VERSION 5.8 ;
BUSBITCHARS "[]" ;
DIVIDERCHAR "/" ;
UNITS
    DATABASE MICRONS 1000 ;
END UNITS

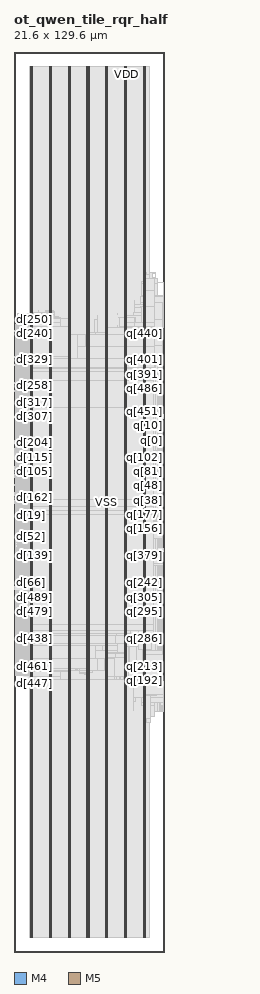
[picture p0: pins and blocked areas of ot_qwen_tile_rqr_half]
MACRO ot_qwen_tile_rqr_half
  FOREIGN ot_qwen_tile_rqr_half 0 0 ;
  CLASS BLOCK ;
  SIZE 21.6 BY 129.6 ;
  PIN clk
    DIRECTION INPUT ;
    USE SIGNAL ;
    PORT
      LAYER M4 ;
        RECT  0 62.064 0.084 62.088 ;
    END
  END clk
  PIN d[0]
    DIRECTION INPUT ;
    USE SIGNAL ;
    PORT
      LAYER M4 ;
        RECT  0 62.16 0.084 62.184 ;
    END
  END d[0]
  PIN d[100]
    DIRECTION INPUT ;
    USE SIGNAL ;
    PORT
      LAYER M4 ;
        RECT  0 68.688 0.084 68.712 ;
    END
  END d[100]
  PIN d[101]
    DIRECTION INPUT ;
    USE SIGNAL ;
    PORT
      LAYER M4 ;
        RECT  0 68.784 0.084 68.808 ;
    END
  END d[101]
  PIN d[102]
    DIRECTION INPUT ;
    USE SIGNAL ;
    PORT
      LAYER M4 ;
        RECT  0 68.88 0.084 68.904 ;
    END
  END d[102]
  PIN d[103]
    DIRECTION INPUT ;
    USE SIGNAL ;
    PORT
      LAYER M4 ;
        RECT  0 68.976 0.084 69 ;
    END
  END d[103]
  PIN d[104]
    DIRECTION INPUT ;
    USE SIGNAL ;
    PORT
      LAYER M4 ;
        RECT  0 69.072 0.084 69.096 ;
    END
  END d[104]
  PIN d[105]
    DIRECTION INPUT ;
    USE SIGNAL ;
    PORT
      LAYER M4 ;
        RECT  0 69.168 0.084 69.192 ;
    END
  END d[105]
  PIN d[106]
    DIRECTION INPUT ;
    USE SIGNAL ;
    PORT
      LAYER M4 ;
        RECT  0 69.264 0.084 69.288 ;
    END
  END d[106]
  PIN d[107]
    DIRECTION INPUT ;
    USE SIGNAL ;
    PORT
      LAYER M4 ;
        RECT  0 69.36 0.084 69.384 ;
    END
  END d[107]
  PIN d[108]
    DIRECTION INPUT ;
    USE SIGNAL ;
    PORT
      LAYER M4 ;
        RECT  0 69.456 0.084 69.48 ;
    END
  END d[108]
  PIN d[109]
    DIRECTION INPUT ;
    USE SIGNAL ;
    PORT
      LAYER M4 ;
        RECT  0 69.552 0.084 69.576 ;
    END
  END d[109]
  PIN d[10]
    DIRECTION INPUT ;
    USE SIGNAL ;
    PORT
      LAYER M4 ;
        RECT  0 63.12 0.084 63.144 ;
    END
  END d[10]
  PIN d[110]
    DIRECTION INPUT ;
    USE SIGNAL ;
    PORT
      LAYER M4 ;
        RECT  0 69.648 0.084 69.672 ;
    END
  END d[110]
  PIN d[111]
    DIRECTION INPUT ;
    USE SIGNAL ;
    PORT
      LAYER M4 ;
        RECT  0 69.744 0.084 69.768 ;
    END
  END d[111]
  PIN d[112]
    DIRECTION INPUT ;
    USE SIGNAL ;
    PORT
      LAYER M4 ;
        RECT  0 69.84 0.084 69.864 ;
    END
  END d[112]
  PIN d[113]
    DIRECTION INPUT ;
    USE SIGNAL ;
    PORT
      LAYER M4 ;
        RECT  0 69.936 0.084 69.96 ;
    END
  END d[113]
  PIN d[114]
    DIRECTION INPUT ;
    USE SIGNAL ;
    PORT
      LAYER M4 ;
        RECT  0 70.032 0.084 70.056 ;
    END
  END d[114]
  PIN d[115]
    DIRECTION INPUT ;
    USE SIGNAL ;
    PORT
      LAYER M4 ;
        RECT  0 70.128 0.084 70.152 ;
    END
  END d[115]
  PIN d[116]
    DIRECTION INPUT ;
    USE SIGNAL ;
    PORT
      LAYER M4 ;
        RECT  0 70.224 0.084 70.248 ;
    END
  END d[116]
  PIN d[117]
    DIRECTION INPUT ;
    USE SIGNAL ;
    PORT
      LAYER M4 ;
        RECT  0 70.32 0.084 70.344 ;
    END
  END d[117]
  PIN d[118]
    DIRECTION INPUT ;
    USE SIGNAL ;
    PORT
      LAYER M4 ;
        RECT  0 70.416 0.084 70.44 ;
    END
  END d[118]
  PIN d[119]
    DIRECTION INPUT ;
    USE SIGNAL ;
    PORT
      LAYER M4 ;
        RECT  0 70.512 0.084 70.536 ;
    END
  END d[119]
  PIN d[11]
    DIRECTION INPUT ;
    USE SIGNAL ;
    PORT
      LAYER M4 ;
        RECT  0 63.216 0.084 63.24 ;
    END
  END d[11]
  PIN d[120]
    DIRECTION INPUT ;
    USE SIGNAL ;
    PORT
      LAYER M4 ;
        RECT  0 70.608 0.084 70.632 ;
    END
  END d[120]
  PIN d[121]
    DIRECTION INPUT ;
    USE SIGNAL ;
    PORT
      LAYER M4 ;
        RECT  0 70.704 0.084 70.728 ;
    END
  END d[121]
  PIN d[122]
    DIRECTION INPUT ;
    USE SIGNAL ;
    PORT
      LAYER M4 ;
        RECT  0 70.8 0.084 70.824 ;
    END
  END d[122]
  PIN d[123]
    DIRECTION INPUT ;
    USE SIGNAL ;
    PORT
      LAYER M4 ;
        RECT  0 70.896 0.084 70.92 ;
    END
  END d[123]
  PIN d[124]
    DIRECTION INPUT ;
    USE SIGNAL ;
    PORT
      LAYER M4 ;
        RECT  0 70.992 0.084 71.016 ;
    END
  END d[124]
  PIN d[125]
    DIRECTION INPUT ;
    USE SIGNAL ;
    PORT
      LAYER M4 ;
        RECT  0 71.088 0.084 71.112 ;
    END
  END d[125]
  PIN d[126]
    DIRECTION INPUT ;
    USE SIGNAL ;
    PORT
      LAYER M4 ;
        RECT  0 71.184 0.084 71.208 ;
    END
  END d[126]
  PIN d[127]
    DIRECTION INPUT ;
    USE SIGNAL ;
    PORT
      LAYER M4 ;
        RECT  0 55.92 0.084 55.944 ;
    END
  END d[127]
  PIN d[128]
    DIRECTION INPUT ;
    USE SIGNAL ;
    PORT
      LAYER M4 ;
        RECT  0 56.016 0.084 56.04 ;
    END
  END d[128]
  PIN d[129]
    DIRECTION INPUT ;
    USE SIGNAL ;
    PORT
      LAYER M4 ;
        RECT  0 56.112 0.084 56.136 ;
    END
  END d[129]
  PIN d[12]
    DIRECTION INPUT ;
    USE SIGNAL ;
    PORT
      LAYER M4 ;
        RECT  0 63.312 0.084 63.336 ;
    END
  END d[12]
  PIN d[130]
    DIRECTION INPUT ;
    USE SIGNAL ;
    PORT
      LAYER M4 ;
        RECT  0 56.208 0.084 56.232 ;
    END
  END d[130]
  PIN d[131]
    DIRECTION INPUT ;
    USE SIGNAL ;
    PORT
      LAYER M4 ;
        RECT  0 56.304 0.084 56.328 ;
    END
  END d[131]
  PIN d[132]
    DIRECTION INPUT ;
    USE SIGNAL ;
    PORT
      LAYER M4 ;
        RECT  0 56.4 0.084 56.424 ;
    END
  END d[132]
  PIN d[133]
    DIRECTION INPUT ;
    USE SIGNAL ;
    PORT
      LAYER M4 ;
        RECT  0 56.496 0.084 56.52 ;
    END
  END d[133]
  PIN d[134]
    DIRECTION INPUT ;
    USE SIGNAL ;
    PORT
      LAYER M4 ;
        RECT  0 56.592 0.084 56.616 ;
    END
  END d[134]
  PIN d[135]
    DIRECTION INPUT ;
    USE SIGNAL ;
    PORT
      LAYER M4 ;
        RECT  0 56.688 0.084 56.712 ;
    END
  END d[135]
  PIN d[136]
    DIRECTION INPUT ;
    USE SIGNAL ;
    PORT
      LAYER M4 ;
        RECT  0 56.784 0.084 56.808 ;
    END
  END d[136]
  PIN d[137]
    DIRECTION INPUT ;
    USE SIGNAL ;
    PORT
      LAYER M4 ;
        RECT  0 56.88 0.084 56.904 ;
    END
  END d[137]
  PIN d[138]
    DIRECTION INPUT ;
    USE SIGNAL ;
    PORT
      LAYER M4 ;
        RECT  0 56.976 0.084 57 ;
    END
  END d[138]
  PIN d[139]
    DIRECTION INPUT ;
    USE SIGNAL ;
    PORT
      LAYER M4 ;
        RECT  0 57.072 0.084 57.096 ;
    END
  END d[139]
  PIN d[13]
    DIRECTION INPUT ;
    USE SIGNAL ;
    PORT
      LAYER M4 ;
        RECT  0 63.408 0.084 63.432 ;
    END
  END d[13]
  PIN d[140]
    DIRECTION INPUT ;
    USE SIGNAL ;
    PORT
      LAYER M4 ;
        RECT  0 57.168 0.084 57.192 ;
    END
  END d[140]
  PIN d[141]
    DIRECTION INPUT ;
    USE SIGNAL ;
    PORT
      LAYER M4 ;
        RECT  0 57.264 0.084 57.288 ;
    END
  END d[141]
  PIN d[142]
    DIRECTION INPUT ;
    USE SIGNAL ;
    PORT
      LAYER M4 ;
        RECT  0 57.36 0.084 57.384 ;
    END
  END d[142]
  PIN d[143]
    DIRECTION INPUT ;
    USE SIGNAL ;
    PORT
      LAYER M4 ;
        RECT  0 57.456 0.084 57.48 ;
    END
  END d[143]
  PIN d[144]
    DIRECTION INPUT ;
    USE SIGNAL ;
    PORT
      LAYER M4 ;
        RECT  0 57.552 0.084 57.576 ;
    END
  END d[144]
  PIN d[145]
    DIRECTION INPUT ;
    USE SIGNAL ;
    PORT
      LAYER M4 ;
        RECT  0 57.648 0.084 57.672 ;
    END
  END d[145]
  PIN d[146]
    DIRECTION INPUT ;
    USE SIGNAL ;
    PORT
      LAYER M4 ;
        RECT  0 57.744 0.084 57.768 ;
    END
  END d[146]
  PIN d[147]
    DIRECTION INPUT ;
    USE SIGNAL ;
    PORT
      LAYER M4 ;
        RECT  0 57.84 0.084 57.864 ;
    END
  END d[147]
  PIN d[148]
    DIRECTION INPUT ;
    USE SIGNAL ;
    PORT
      LAYER M4 ;
        RECT  0 57.936 0.084 57.96 ;
    END
  END d[148]
  PIN d[149]
    DIRECTION INPUT ;
    USE SIGNAL ;
    PORT
      LAYER M4 ;
        RECT  0 58.032 0.084 58.056 ;
    END
  END d[149]
  PIN d[14]
    DIRECTION INPUT ;
    USE SIGNAL ;
    PORT
      LAYER M4 ;
        RECT  0 63.504 0.084 63.528 ;
    END
  END d[14]
  PIN d[150]
    DIRECTION INPUT ;
    USE SIGNAL ;
    PORT
      LAYER M4 ;
        RECT  0 58.128 0.084 58.152 ;
    END
  END d[150]
  PIN d[151]
    DIRECTION INPUT ;
    USE SIGNAL ;
    PORT
      LAYER M4 ;
        RECT  0 58.224 0.084 58.248 ;
    END
  END d[151]
  PIN d[152]
    DIRECTION INPUT ;
    USE SIGNAL ;
    PORT
      LAYER M4 ;
        RECT  0 58.32 0.084 58.344 ;
    END
  END d[152]
  PIN d[153]
    DIRECTION INPUT ;
    USE SIGNAL ;
    PORT
      LAYER M4 ;
        RECT  0 58.416 0.084 58.44 ;
    END
  END d[153]
  PIN d[154]
    DIRECTION INPUT ;
    USE SIGNAL ;
    PORT
      LAYER M4 ;
        RECT  0 58.512 0.084 58.536 ;
    END
  END d[154]
  PIN d[155]
    DIRECTION INPUT ;
    USE SIGNAL ;
    PORT
      LAYER M4 ;
        RECT  0 58.608 0.084 58.632 ;
    END
  END d[155]
  PIN d[156]
    DIRECTION INPUT ;
    USE SIGNAL ;
    PORT
      LAYER M4 ;
        RECT  0 58.704 0.084 58.728 ;
    END
  END d[156]
  PIN d[157]
    DIRECTION INPUT ;
    USE SIGNAL ;
    PORT
      LAYER M4 ;
        RECT  0 58.8 0.084 58.824 ;
    END
  END d[157]
  PIN d[158]
    DIRECTION INPUT ;
    USE SIGNAL ;
    PORT
      LAYER M4 ;
        RECT  0 58.896 0.084 58.92 ;
    END
  END d[158]
  PIN d[159]
    DIRECTION INPUT ;
    USE SIGNAL ;
    PORT
      LAYER M4 ;
        RECT  0 65.136 0.084 65.16 ;
    END
  END d[159]
  PIN d[15]
    DIRECTION INPUT ;
    USE SIGNAL ;
    PORT
      LAYER M4 ;
        RECT  0 63.6 0.084 63.624 ;
    END
  END d[15]
  PIN d[160]
    DIRECTION INPUT ;
    USE SIGNAL ;
    PORT
      LAYER M4 ;
        RECT  0 65.232 0.084 65.256 ;
    END
  END d[160]
  PIN d[161]
    DIRECTION INPUT ;
    USE SIGNAL ;
    PORT
      LAYER M4 ;
        RECT  0 65.328 0.084 65.352 ;
    END
  END d[161]
  PIN d[162]
    DIRECTION INPUT ;
    USE SIGNAL ;
    PORT
      LAYER M4 ;
        RECT  0 65.424 0.084 65.448 ;
    END
  END d[162]
  PIN d[163]
    DIRECTION INPUT ;
    USE SIGNAL ;
    PORT
      LAYER M4 ;
        RECT  0 65.52 0.084 65.544 ;
    END
  END d[163]
  PIN d[164]
    DIRECTION INPUT ;
    USE SIGNAL ;
    PORT
      LAYER M4 ;
        RECT  0 65.616 0.084 65.64 ;
    END
  END d[164]
  PIN d[165]
    DIRECTION INPUT ;
    USE SIGNAL ;
    PORT
      LAYER M4 ;
        RECT  0 65.712 0.084 65.736 ;
    END
  END d[165]
  PIN d[166]
    DIRECTION INPUT ;
    USE SIGNAL ;
    PORT
      LAYER M4 ;
        RECT  0 65.808 0.084 65.832 ;
    END
  END d[166]
  PIN d[167]
    DIRECTION INPUT ;
    USE SIGNAL ;
    PORT
      LAYER M4 ;
        RECT  0 65.904 0.084 65.928 ;
    END
  END d[167]
  PIN d[168]
    DIRECTION INPUT ;
    USE SIGNAL ;
    PORT
      LAYER M4 ;
        RECT  0 66 0.084 66.024 ;
    END
  END d[168]
  PIN d[169]
    DIRECTION INPUT ;
    USE SIGNAL ;
    PORT
      LAYER M4 ;
        RECT  0 66.096 0.084 66.12 ;
    END
  END d[169]
  PIN d[16]
    DIRECTION INPUT ;
    USE SIGNAL ;
    PORT
      LAYER M4 ;
        RECT  0 63.696 0.084 63.72 ;
    END
  END d[16]
  PIN d[170]
    DIRECTION INPUT ;
    USE SIGNAL ;
    PORT
      LAYER M4 ;
        RECT  0 66.192 0.084 66.216 ;
    END
  END d[170]
  PIN d[171]
    DIRECTION INPUT ;
    USE SIGNAL ;
    PORT
      LAYER M4 ;
        RECT  0 66.288 0.084 66.312 ;
    END
  END d[171]
  PIN d[172]
    DIRECTION INPUT ;
    USE SIGNAL ;
    PORT
      LAYER M4 ;
        RECT  0 66.384 0.084 66.408 ;
    END
  END d[172]
  PIN d[173]
    DIRECTION INPUT ;
    USE SIGNAL ;
    PORT
      LAYER M4 ;
        RECT  0 66.48 0.084 66.504 ;
    END
  END d[173]
  PIN d[174]
    DIRECTION INPUT ;
    USE SIGNAL ;
    PORT
      LAYER M4 ;
        RECT  0 66.576 0.084 66.6 ;
    END
  END d[174]
  PIN d[175]
    DIRECTION INPUT ;
    USE SIGNAL ;
    PORT
      LAYER M4 ;
        RECT  0 66.672 0.084 66.696 ;
    END
  END d[175]
  PIN d[176]
    DIRECTION INPUT ;
    USE SIGNAL ;
    PORT
      LAYER M4 ;
        RECT  0 66.768 0.084 66.792 ;
    END
  END d[176]
  PIN d[177]
    DIRECTION INPUT ;
    USE SIGNAL ;
    PORT
      LAYER M4 ;
        RECT  0 66.864 0.084 66.888 ;
    END
  END d[177]
  PIN d[178]
    DIRECTION INPUT ;
    USE SIGNAL ;
    PORT
      LAYER M4 ;
        RECT  0 66.96 0.084 66.984 ;
    END
  END d[178]
  PIN d[179]
    DIRECTION INPUT ;
    USE SIGNAL ;
    PORT
      LAYER M4 ;
        RECT  0 67.056 0.084 67.08 ;
    END
  END d[179]
  PIN d[17]
    DIRECTION INPUT ;
    USE SIGNAL ;
    PORT
      LAYER M4 ;
        RECT  0 63.792 0.084 63.816 ;
    END
  END d[17]
  PIN d[180]
    DIRECTION INPUT ;
    USE SIGNAL ;
    PORT
      LAYER M4 ;
        RECT  0 67.152 0.084 67.176 ;
    END
  END d[180]
  PIN d[181]
    DIRECTION INPUT ;
    USE SIGNAL ;
    PORT
      LAYER M4 ;
        RECT  0 67.248 0.084 67.272 ;
    END
  END d[181]
  PIN d[182]
    DIRECTION INPUT ;
    USE SIGNAL ;
    PORT
      LAYER M4 ;
        RECT  0 67.344 0.084 67.368 ;
    END
  END d[182]
  PIN d[183]
    DIRECTION INPUT ;
    USE SIGNAL ;
    PORT
      LAYER M4 ;
        RECT  0 67.44 0.084 67.464 ;
    END
  END d[183]
  PIN d[184]
    DIRECTION INPUT ;
    USE SIGNAL ;
    PORT
      LAYER M4 ;
        RECT  0 67.536 0.084 67.56 ;
    END
  END d[184]
  PIN d[185]
    DIRECTION INPUT ;
    USE SIGNAL ;
    PORT
      LAYER M4 ;
        RECT  0 67.632 0.084 67.656 ;
    END
  END d[185]
  PIN d[186]
    DIRECTION INPUT ;
    USE SIGNAL ;
    PORT
      LAYER M4 ;
        RECT  0 67.728 0.084 67.752 ;
    END
  END d[186]
  PIN d[187]
    DIRECTION INPUT ;
    USE SIGNAL ;
    PORT
      LAYER M4 ;
        RECT  0 67.824 0.084 67.848 ;
    END
  END d[187]
  PIN d[188]
    DIRECTION INPUT ;
    USE SIGNAL ;
    PORT
      LAYER M4 ;
        RECT  0 67.92 0.084 67.944 ;
    END
  END d[188]
  PIN d[189]
    DIRECTION INPUT ;
    USE SIGNAL ;
    PORT
      LAYER M4 ;
        RECT  0 68.016 0.084 68.04 ;
    END
  END d[189]
  PIN d[18]
    DIRECTION INPUT ;
    USE SIGNAL ;
    PORT
      LAYER M4 ;
        RECT  0 63.888 0.084 63.912 ;
    END
  END d[18]
  PIN d[190]
    DIRECTION INPUT ;
    USE SIGNAL ;
    PORT
      LAYER M4 ;
        RECT  0 68.112 0.084 68.136 ;
    END
  END d[190]
  PIN d[191]
    DIRECTION INPUT ;
    USE SIGNAL ;
    PORT
      LAYER M4 ;
        RECT  0 72.048 0.084 72.072 ;
    END
  END d[191]
  PIN d[192]
    DIRECTION INPUT ;
    USE SIGNAL ;
    PORT
      LAYER M4 ;
        RECT  0 72.144 0.084 72.168 ;
    END
  END d[192]
  PIN d[193]
    DIRECTION INPUT ;
    USE SIGNAL ;
    PORT
      LAYER M4 ;
        RECT  0 72.24 0.084 72.264 ;
    END
  END d[193]
  PIN d[194]
    DIRECTION INPUT ;
    USE SIGNAL ;
    PORT
      LAYER M4 ;
        RECT  0 72.336 0.084 72.36 ;
    END
  END d[194]
  PIN d[195]
    DIRECTION INPUT ;
    USE SIGNAL ;
    PORT
      LAYER M4 ;
        RECT  0 72.432 0.084 72.456 ;
    END
  END d[195]
  PIN d[196]
    DIRECTION INPUT ;
    USE SIGNAL ;
    PORT
      LAYER M4 ;
        RECT  0 72.528 0.084 72.552 ;
    END
  END d[196]
  PIN d[197]
    DIRECTION INPUT ;
    USE SIGNAL ;
    PORT
      LAYER M4 ;
        RECT  0 72.624 0.084 72.648 ;
    END
  END d[197]
  PIN d[198]
    DIRECTION INPUT ;
    USE SIGNAL ;
    PORT
      LAYER M4 ;
        RECT  0 72.72 0.084 72.744 ;
    END
  END d[198]
  PIN d[199]
    DIRECTION INPUT ;
    USE SIGNAL ;
    PORT
      LAYER M4 ;
        RECT  0 72.816 0.084 72.84 ;
    END
  END d[199]
  PIN d[19]
    DIRECTION INPUT ;
    USE SIGNAL ;
    PORT
      LAYER M4 ;
        RECT  0 63.984 0.084 64.008 ;
    END
  END d[19]
  PIN d[1]
    DIRECTION INPUT ;
    USE SIGNAL ;
    PORT
      LAYER M4 ;
        RECT  0 62.256 0.084 62.28 ;
    END
  END d[1]
  PIN d[200]
    DIRECTION INPUT ;
    USE SIGNAL ;
    PORT
      LAYER M4 ;
        RECT  0 72.912 0.084 72.936 ;
    END
  END d[200]
  PIN d[201]
    DIRECTION INPUT ;
    USE SIGNAL ;
    PORT
      LAYER M4 ;
        RECT  0 73.008 0.084 73.032 ;
    END
  END d[201]
  PIN d[202]
    DIRECTION INPUT ;
    USE SIGNAL ;
    PORT
      LAYER M4 ;
        RECT  0 73.104 0.084 73.128 ;
    END
  END d[202]
  PIN d[203]
    DIRECTION INPUT ;
    USE SIGNAL ;
    PORT
      LAYER M4 ;
        RECT  0 73.2 0.084 73.224 ;
    END
  END d[203]
  PIN d[204]
    DIRECTION INPUT ;
    USE SIGNAL ;
    PORT
      LAYER M4 ;
        RECT  0 73.296 0.084 73.32 ;
    END
  END d[204]
  PIN d[205]
    DIRECTION INPUT ;
    USE SIGNAL ;
    PORT
      LAYER M4 ;
        RECT  0 73.392 0.084 73.416 ;
    END
  END d[205]
  PIN d[206]
    DIRECTION INPUT ;
    USE SIGNAL ;
    PORT
      LAYER M4 ;
        RECT  0 73.488 0.084 73.512 ;
    END
  END d[206]
  PIN d[207]
    DIRECTION INPUT ;
    USE SIGNAL ;
    PORT
      LAYER M4 ;
        RECT  0 73.584 0.084 73.608 ;
    END
  END d[207]
  PIN d[208]
    DIRECTION INPUT ;
    USE SIGNAL ;
    PORT
      LAYER M4 ;
        RECT  0 73.68 0.084 73.704 ;
    END
  END d[208]
  PIN d[209]
    DIRECTION INPUT ;
    USE SIGNAL ;
    PORT
      LAYER M4 ;
        RECT  0 73.776 0.084 73.8 ;
    END
  END d[209]
  PIN d[20]
    DIRECTION INPUT ;
    USE SIGNAL ;
    PORT
      LAYER M4 ;
        RECT  0 64.08 0.084 64.104 ;
    END
  END d[20]
  PIN d[210]
    DIRECTION INPUT ;
    USE SIGNAL ;
    PORT
      LAYER M4 ;
        RECT  0 73.872 0.084 73.896 ;
    END
  END d[210]
  PIN d[211]
    DIRECTION INPUT ;
    USE SIGNAL ;
    PORT
      LAYER M4 ;
        RECT  0 73.968 0.084 73.992 ;
    END
  END d[211]
  PIN d[212]
    DIRECTION INPUT ;
    USE SIGNAL ;
    PORT
      LAYER M4 ;
        RECT  0 74.064 0.084 74.088 ;
    END
  END d[212]
  PIN d[213]
    DIRECTION INPUT ;
    USE SIGNAL ;
    PORT
      LAYER M4 ;
        RECT  0 74.16 0.084 74.184 ;
    END
  END d[213]
  PIN d[214]
    DIRECTION INPUT ;
    USE SIGNAL ;
    PORT
      LAYER M4 ;
        RECT  0 74.256 0.084 74.28 ;
    END
  END d[214]
  PIN d[215]
    DIRECTION INPUT ;
    USE SIGNAL ;
    PORT
      LAYER M4 ;
        RECT  0 74.352 0.084 74.376 ;
    END
  END d[215]
  PIN d[216]
    DIRECTION INPUT ;
    USE SIGNAL ;
    PORT
      LAYER M4 ;
        RECT  0 74.448 0.084 74.472 ;
    END
  END d[216]
  PIN d[217]
    DIRECTION INPUT ;
    USE SIGNAL ;
    PORT
      LAYER M4 ;
        RECT  0 74.544 0.084 74.568 ;
    END
  END d[217]
  PIN d[218]
    DIRECTION INPUT ;
    USE SIGNAL ;
    PORT
      LAYER M4 ;
        RECT  0 74.64 0.084 74.664 ;
    END
  END d[218]
  PIN d[219]
    DIRECTION INPUT ;
    USE SIGNAL ;
    PORT
      LAYER M4 ;
        RECT  0 74.736 0.084 74.76 ;
    END
  END d[219]
  PIN d[21]
    DIRECTION INPUT ;
    USE SIGNAL ;
    PORT
      LAYER M4 ;
        RECT  0 64.176 0.084 64.2 ;
    END
  END d[21]
  PIN d[220]
    DIRECTION INPUT ;
    USE SIGNAL ;
    PORT
      LAYER M4 ;
        RECT  0 74.832 0.084 74.856 ;
    END
  END d[220]
  PIN d[221]
    DIRECTION INPUT ;
    USE SIGNAL ;
    PORT
      LAYER M4 ;
        RECT  0 74.928 0.084 74.952 ;
    END
  END d[221]
  PIN d[222]
    DIRECTION INPUT ;
    USE SIGNAL ;
    PORT
      LAYER M4 ;
        RECT  0 75.024 0.084 75.048 ;
    END
  END d[222]
  PIN d[223]
    DIRECTION INPUT ;
    USE SIGNAL ;
    PORT
      LAYER M4 ;
        RECT  0 87.408 0.084 87.432 ;
    END
  END d[223]
  PIN d[224]
    DIRECTION INPUT ;
    USE SIGNAL ;
    PORT
      LAYER M4 ;
        RECT  0 87.504 0.084 87.528 ;
    END
  END d[224]
  PIN d[225]
    DIRECTION INPUT ;
    USE SIGNAL ;
    PORT
      LAYER M4 ;
        RECT  0 87.6 0.084 87.624 ;
    END
  END d[225]
  PIN d[226]
    DIRECTION INPUT ;
    USE SIGNAL ;
    PORT
      LAYER M4 ;
        RECT  0 87.696 0.084 87.72 ;
    END
  END d[226]
  PIN d[227]
    DIRECTION INPUT ;
    USE SIGNAL ;
    PORT
      LAYER M4 ;
        RECT  0 87.792 0.084 87.816 ;
    END
  END d[227]
  PIN d[228]
    DIRECTION INPUT ;
    USE SIGNAL ;
    PORT
      LAYER M4 ;
        RECT  0 87.888 0.084 87.912 ;
    END
  END d[228]
  PIN d[229]
    DIRECTION INPUT ;
    USE SIGNAL ;
    PORT
      LAYER M4 ;
        RECT  0 87.984 0.084 88.008 ;
    END
  END d[229]
  PIN d[22]
    DIRECTION INPUT ;
    USE SIGNAL ;
    PORT
      LAYER M4 ;
        RECT  0 64.272 0.084 64.296 ;
    END
  END d[22]
  PIN d[230]
    DIRECTION INPUT ;
    USE SIGNAL ;
    PORT
      LAYER M4 ;
        RECT  0 88.08 0.084 88.104 ;
    END
  END d[230]
  PIN d[231]
    DIRECTION INPUT ;
    USE SIGNAL ;
    PORT
      LAYER M4 ;
        RECT  0 88.176 0.084 88.2 ;
    END
  END d[231]
  PIN d[232]
    DIRECTION INPUT ;
    USE SIGNAL ;
    PORT
      LAYER M4 ;
        RECT  0 88.272 0.084 88.296 ;
    END
  END d[232]
  PIN d[233]
    DIRECTION INPUT ;
    USE SIGNAL ;
    PORT
      LAYER M4 ;
        RECT  0 88.368 0.084 88.392 ;
    END
  END d[233]
  PIN d[234]
    DIRECTION INPUT ;
    USE SIGNAL ;
    PORT
      LAYER M4 ;
        RECT  0 88.464 0.084 88.488 ;
    END
  END d[234]
  PIN d[235]
    DIRECTION INPUT ;
    USE SIGNAL ;
    PORT
      LAYER M4 ;
        RECT  0 88.56 0.084 88.584 ;
    END
  END d[235]
  PIN d[236]
    DIRECTION INPUT ;
    USE SIGNAL ;
    PORT
      LAYER M4 ;
        RECT  0 88.656 0.084 88.68 ;
    END
  END d[236]
  PIN d[237]
    DIRECTION INPUT ;
    USE SIGNAL ;
    PORT
      LAYER M4 ;
        RECT  0 88.752 0.084 88.776 ;
    END
  END d[237]
  PIN d[238]
    DIRECTION INPUT ;
    USE SIGNAL ;
    PORT
      LAYER M4 ;
        RECT  0 88.848 0.084 88.872 ;
    END
  END d[238]
  PIN d[239]
    DIRECTION INPUT ;
    USE SIGNAL ;
    PORT
      LAYER M4 ;
        RECT  0 88.944 0.084 88.968 ;
    END
  END d[239]
  PIN d[23]
    DIRECTION INPUT ;
    USE SIGNAL ;
    PORT
      LAYER M4 ;
        RECT  0 64.368 0.084 64.392 ;
    END
  END d[23]
  PIN d[240]
    DIRECTION INPUT ;
    USE SIGNAL ;
    PORT
      LAYER M4 ;
        RECT  0 89.04 0.084 89.064 ;
    END
  END d[240]
  PIN d[241]
    DIRECTION INPUT ;
    USE SIGNAL ;
    PORT
      LAYER M4 ;
        RECT  0 89.136 0.084 89.16 ;
    END
  END d[241]
  PIN d[242]
    DIRECTION INPUT ;
    USE SIGNAL ;
    PORT
      LAYER M4 ;
        RECT  0 89.232 0.084 89.256 ;
    END
  END d[242]
  PIN d[243]
    DIRECTION INPUT ;
    USE SIGNAL ;
    PORT
      LAYER M4 ;
        RECT  0 89.328 0.084 89.352 ;
    END
  END d[243]
  PIN d[244]
    DIRECTION INPUT ;
    USE SIGNAL ;
    PORT
      LAYER M4 ;
        RECT  0 89.424 0.084 89.448 ;
    END
  END d[244]
  PIN d[245]
    DIRECTION INPUT ;
    USE SIGNAL ;
    PORT
      LAYER M4 ;
        RECT  0 89.52 0.084 89.544 ;
    END
  END d[245]
  PIN d[246]
    DIRECTION INPUT ;
    USE SIGNAL ;
    PORT
      LAYER M4 ;
        RECT  0 89.616 0.084 89.64 ;
    END
  END d[246]
  PIN d[247]
    DIRECTION INPUT ;
    USE SIGNAL ;
    PORT
      LAYER M4 ;
        RECT  0 89.712 0.084 89.736 ;
    END
  END d[247]
  PIN d[248]
    DIRECTION INPUT ;
    USE SIGNAL ;
    PORT
      LAYER M4 ;
        RECT  0 89.808 0.084 89.832 ;
    END
  END d[248]
  PIN d[249]
    DIRECTION INPUT ;
    USE SIGNAL ;
    PORT
      LAYER M4 ;
        RECT  0 89.904 0.084 89.928 ;
    END
  END d[249]
  PIN d[24]
    DIRECTION INPUT ;
    USE SIGNAL ;
    PORT
      LAYER M4 ;
        RECT  0 64.464 0.084 64.488 ;
    END
  END d[24]
  PIN d[250]
    DIRECTION INPUT ;
    USE SIGNAL ;
    PORT
      LAYER M4 ;
        RECT  0 90 0.084 90.024 ;
    END
  END d[250]
  PIN d[251]
    DIRECTION INPUT ;
    USE SIGNAL ;
    PORT
      LAYER M4 ;
        RECT  0 90.096 0.084 90.12 ;
    END
  END d[251]
  PIN d[252]
    DIRECTION INPUT ;
    USE SIGNAL ;
    PORT
      LAYER M4 ;
        RECT  0 90.192 0.084 90.216 ;
    END
  END d[252]
  PIN d[253]
    DIRECTION INPUT ;
    USE SIGNAL ;
    PORT
      LAYER M4 ;
        RECT  0 90.288 0.084 90.312 ;
    END
  END d[253]
  PIN d[254]
    DIRECTION INPUT ;
    USE SIGNAL ;
    PORT
      LAYER M4 ;
        RECT  0 90.384 0.084 90.408 ;
    END
  END d[254]
  PIN d[255]
    DIRECTION INPUT ;
    USE SIGNAL ;
    PORT
      LAYER M4 ;
        RECT  0 81.264 0.084 81.288 ;
    END
  END d[255]
  PIN d[256]
    DIRECTION INPUT ;
    USE SIGNAL ;
    PORT
      LAYER M4 ;
        RECT  0 81.36 0.084 81.384 ;
    END
  END d[256]
  PIN d[257]
    DIRECTION INPUT ;
    USE SIGNAL ;
    PORT
      LAYER M4 ;
        RECT  0 81.456 0.084 81.48 ;
    END
  END d[257]
  PIN d[258]
    DIRECTION INPUT ;
    USE SIGNAL ;
    PORT
      LAYER M4 ;
        RECT  0 81.552 0.084 81.576 ;
    END
  END d[258]
  PIN d[259]
    DIRECTION INPUT ;
    USE SIGNAL ;
    PORT
      LAYER M4 ;
        RECT  0 81.648 0.084 81.672 ;
    END
  END d[259]
  PIN d[25]
    DIRECTION INPUT ;
    USE SIGNAL ;
    PORT
      LAYER M4 ;
        RECT  0 64.56 0.084 64.584 ;
    END
  END d[25]
  PIN d[260]
    DIRECTION INPUT ;
    USE SIGNAL ;
    PORT
      LAYER M4 ;
        RECT  0 81.744 0.084 81.768 ;
    END
  END d[260]
  PIN d[261]
    DIRECTION INPUT ;
    USE SIGNAL ;
    PORT
      LAYER M4 ;
        RECT  0 81.84 0.084 81.864 ;
    END
  END d[261]
  PIN d[262]
    DIRECTION INPUT ;
    USE SIGNAL ;
    PORT
      LAYER M4 ;
        RECT  0 81.936 0.084 81.96 ;
    END
  END d[262]
  PIN d[263]
    DIRECTION INPUT ;
    USE SIGNAL ;
    PORT
      LAYER M4 ;
        RECT  0 82.032 0.084 82.056 ;
    END
  END d[263]
  PIN d[264]
    DIRECTION INPUT ;
    USE SIGNAL ;
    PORT
      LAYER M4 ;
        RECT  0 82.128 0.084 82.152 ;
    END
  END d[264]
  PIN d[265]
    DIRECTION INPUT ;
    USE SIGNAL ;
    PORT
      LAYER M4 ;
        RECT  0 82.224 0.084 82.248 ;
    END
  END d[265]
  PIN d[266]
    DIRECTION INPUT ;
    USE SIGNAL ;
    PORT
      LAYER M4 ;
        RECT  0 82.32 0.084 82.344 ;
    END
  END d[266]
  PIN d[267]
    DIRECTION INPUT ;
    USE SIGNAL ;
    PORT
      LAYER M4 ;
        RECT  0 82.416 0.084 82.44 ;
    END
  END d[267]
  PIN d[268]
    DIRECTION INPUT ;
    USE SIGNAL ;
    PORT
      LAYER M4 ;
        RECT  0 82.512 0.084 82.536 ;
    END
  END d[268]
  PIN d[269]
    DIRECTION INPUT ;
    USE SIGNAL ;
    PORT
      LAYER M4 ;
        RECT  0 82.608 0.084 82.632 ;
    END
  END d[269]
  PIN d[26]
    DIRECTION INPUT ;
    USE SIGNAL ;
    PORT
      LAYER M4 ;
        RECT  0 64.656 0.084 64.68 ;
    END
  END d[26]
  PIN d[270]
    DIRECTION INPUT ;
    USE SIGNAL ;
    PORT
      LAYER M4 ;
        RECT  0 82.704 0.084 82.728 ;
    END
  END d[270]
  PIN d[271]
    DIRECTION INPUT ;
    USE SIGNAL ;
    PORT
      LAYER M4 ;
        RECT  0 82.8 0.084 82.824 ;
    END
  END d[271]
  PIN d[272]
    DIRECTION INPUT ;
    USE SIGNAL ;
    PORT
      LAYER M4 ;
        RECT  0 82.896 0.084 82.92 ;
    END
  END d[272]
  PIN d[273]
    DIRECTION INPUT ;
    USE SIGNAL ;
    PORT
      LAYER M4 ;
        RECT  0 82.992 0.084 83.016 ;
    END
  END d[273]
  PIN d[274]
    DIRECTION INPUT ;
    USE SIGNAL ;
    PORT
      LAYER M4 ;
        RECT  0 83.088 0.084 83.112 ;
    END
  END d[274]
  PIN d[275]
    DIRECTION INPUT ;
    USE SIGNAL ;
    PORT
      LAYER M4 ;
        RECT  0 83.184 0.084 83.208 ;
    END
  END d[275]
  PIN d[276]
    DIRECTION INPUT ;
    USE SIGNAL ;
    PORT
      LAYER M4 ;
        RECT  0 83.28 0.084 83.304 ;
    END
  END d[276]
  PIN d[277]
    DIRECTION INPUT ;
    USE SIGNAL ;
    PORT
      LAYER M4 ;
        RECT  0 83.376 0.084 83.4 ;
    END
  END d[277]
  PIN d[278]
    DIRECTION INPUT ;
    USE SIGNAL ;
    PORT
      LAYER M4 ;
        RECT  0 83.472 0.084 83.496 ;
    END
  END d[278]
  PIN d[279]
    DIRECTION INPUT ;
    USE SIGNAL ;
    PORT
      LAYER M4 ;
        RECT  0 83.568 0.084 83.592 ;
    END
  END d[279]
  PIN d[27]
    DIRECTION INPUT ;
    USE SIGNAL ;
    PORT
      LAYER M4 ;
        RECT  0 64.752 0.084 64.776 ;
    END
  END d[27]
  PIN d[280]
    DIRECTION INPUT ;
    USE SIGNAL ;
    PORT
      LAYER M4 ;
        RECT  0 83.664 0.084 83.688 ;
    END
  END d[280]
  PIN d[281]
    DIRECTION INPUT ;
    USE SIGNAL ;
    PORT
      LAYER M4 ;
        RECT  0 83.76 0.084 83.784 ;
    END
  END d[281]
  PIN d[282]
    DIRECTION INPUT ;
    USE SIGNAL ;
    PORT
      LAYER M4 ;
        RECT  0 83.856 0.084 83.88 ;
    END
  END d[282]
  PIN d[283]
    DIRECTION INPUT ;
    USE SIGNAL ;
    PORT
      LAYER M4 ;
        RECT  0 83.952 0.084 83.976 ;
    END
  END d[283]
  PIN d[284]
    DIRECTION INPUT ;
    USE SIGNAL ;
    PORT
      LAYER M4 ;
        RECT  0 84.048 0.084 84.072 ;
    END
  END d[284]
  PIN d[285]
    DIRECTION INPUT ;
    USE SIGNAL ;
    PORT
      LAYER M4 ;
        RECT  0 84.144 0.084 84.168 ;
    END
  END d[285]
  PIN d[286]
    DIRECTION INPUT ;
    USE SIGNAL ;
    PORT
      LAYER M4 ;
        RECT  0 84.24 0.084 84.264 ;
    END
  END d[286]
  PIN d[287]
    DIRECTION INPUT ;
    USE SIGNAL ;
    PORT
      LAYER M4 ;
        RECT  0 75.12 0.084 75.144 ;
    END
  END d[287]
  PIN d[288]
    DIRECTION INPUT ;
    USE SIGNAL ;
    PORT
      LAYER M4 ;
        RECT  0 75.216 0.084 75.24 ;
    END
  END d[288]
  PIN d[289]
    DIRECTION INPUT ;
    USE SIGNAL ;
    PORT
      LAYER M4 ;
        RECT  0 75.312 0.084 75.336 ;
    END
  END d[289]
  PIN d[28]
    DIRECTION INPUT ;
    USE SIGNAL ;
    PORT
      LAYER M4 ;
        RECT  0 64.848 0.084 64.872 ;
    END
  END d[28]
  PIN d[290]
    DIRECTION INPUT ;
    USE SIGNAL ;
    PORT
      LAYER M4 ;
        RECT  0 75.408 0.084 75.432 ;
    END
  END d[290]
  PIN d[291]
    DIRECTION INPUT ;
    USE SIGNAL ;
    PORT
      LAYER M4 ;
        RECT  0 75.504 0.084 75.528 ;
    END
  END d[291]
  PIN d[292]
    DIRECTION INPUT ;
    USE SIGNAL ;
    PORT
      LAYER M4 ;
        RECT  0 75.6 0.084 75.624 ;
    END
  END d[292]
  PIN d[293]
    DIRECTION INPUT ;
    USE SIGNAL ;
    PORT
      LAYER M4 ;
        RECT  0 75.696 0.084 75.72 ;
    END
  END d[293]
  PIN d[294]
    DIRECTION INPUT ;
    USE SIGNAL ;
    PORT
      LAYER M4 ;
        RECT  0 75.792 0.084 75.816 ;
    END
  END d[294]
  PIN d[295]
    DIRECTION INPUT ;
    USE SIGNAL ;
    PORT
      LAYER M4 ;
        RECT  0 75.888 0.084 75.912 ;
    END
  END d[295]
  PIN d[296]
    DIRECTION INPUT ;
    USE SIGNAL ;
    PORT
      LAYER M4 ;
        RECT  0 75.984 0.084 76.008 ;
    END
  END d[296]
  PIN d[297]
    DIRECTION INPUT ;
    USE SIGNAL ;
    PORT
      LAYER M4 ;
        RECT  0 76.08 0.084 76.104 ;
    END
  END d[297]
  PIN d[298]
    DIRECTION INPUT ;
    USE SIGNAL ;
    PORT
      LAYER M4 ;
        RECT  0 76.176 0.084 76.2 ;
    END
  END d[298]
  PIN d[299]
    DIRECTION INPUT ;
    USE SIGNAL ;
    PORT
      LAYER M4 ;
        RECT  0 76.272 0.084 76.296 ;
    END
  END d[299]
  PIN d[29]
    DIRECTION INPUT ;
    USE SIGNAL ;
    PORT
      LAYER M4 ;
        RECT  0 64.944 0.084 64.968 ;
    END
  END d[29]
  PIN d[2]
    DIRECTION INPUT ;
    USE SIGNAL ;
    PORT
      LAYER M4 ;
        RECT  0 62.352 0.084 62.376 ;
    END
  END d[2]
  PIN d[300]
    DIRECTION INPUT ;
    USE SIGNAL ;
    PORT
      LAYER M4 ;
        RECT  0 76.368 0.084 76.392 ;
    END
  END d[300]
  PIN d[301]
    DIRECTION INPUT ;
    USE SIGNAL ;
    PORT
      LAYER M4 ;
        RECT  0 76.464 0.084 76.488 ;
    END
  END d[301]
  PIN d[302]
    DIRECTION INPUT ;
    USE SIGNAL ;
    PORT
      LAYER M4 ;
        RECT  0 76.56 0.084 76.584 ;
    END
  END d[302]
  PIN d[303]
    DIRECTION INPUT ;
    USE SIGNAL ;
    PORT
      LAYER M4 ;
        RECT  0 76.656 0.084 76.68 ;
    END
  END d[303]
  PIN d[304]
    DIRECTION INPUT ;
    USE SIGNAL ;
    PORT
      LAYER M4 ;
        RECT  0 76.752 0.084 76.776 ;
    END
  END d[304]
  PIN d[305]
    DIRECTION INPUT ;
    USE SIGNAL ;
    PORT
      LAYER M4 ;
        RECT  0 76.848 0.084 76.872 ;
    END
  END d[305]
  PIN d[306]
    DIRECTION INPUT ;
    USE SIGNAL ;
    PORT
      LAYER M4 ;
        RECT  0 76.944 0.084 76.968 ;
    END
  END d[306]
  PIN d[307]
    DIRECTION INPUT ;
    USE SIGNAL ;
    PORT
      LAYER M4 ;
        RECT  0 77.04 0.084 77.064 ;
    END
  END d[307]
  PIN d[308]
    DIRECTION INPUT ;
    USE SIGNAL ;
    PORT
      LAYER M4 ;
        RECT  0 77.136 0.084 77.16 ;
    END
  END d[308]
  PIN d[309]
    DIRECTION INPUT ;
    USE SIGNAL ;
    PORT
      LAYER M4 ;
        RECT  0 77.232 0.084 77.256 ;
    END
  END d[309]
  PIN d[30]
    DIRECTION INPUT ;
    USE SIGNAL ;
    PORT
      LAYER M4 ;
        RECT  0 65.04 0.084 65.064 ;
    END
  END d[30]
  PIN d[310]
    DIRECTION INPUT ;
    USE SIGNAL ;
    PORT
      LAYER M4 ;
        RECT  0 77.328 0.084 77.352 ;
    END
  END d[310]
  PIN d[311]
    DIRECTION INPUT ;
    USE SIGNAL ;
    PORT
      LAYER M4 ;
        RECT  0 77.424 0.084 77.448 ;
    END
  END d[311]
  PIN d[312]
    DIRECTION INPUT ;
    USE SIGNAL ;
    PORT
      LAYER M4 ;
        RECT  0 77.52 0.084 77.544 ;
    END
  END d[312]
  PIN d[313]
    DIRECTION INPUT ;
    USE SIGNAL ;
    PORT
      LAYER M4 ;
        RECT  0 77.616 0.084 77.64 ;
    END
  END d[313]
  PIN d[314]
    DIRECTION INPUT ;
    USE SIGNAL ;
    PORT
      LAYER M4 ;
        RECT  0 77.712 0.084 77.736 ;
    END
  END d[314]
  PIN d[315]
    DIRECTION INPUT ;
    USE SIGNAL ;
    PORT
      LAYER M4 ;
        RECT  0 77.808 0.084 77.832 ;
    END
  END d[315]
  PIN d[316]
    DIRECTION INPUT ;
    USE SIGNAL ;
    PORT
      LAYER M4 ;
        RECT  0 77.904 0.084 77.928 ;
    END
  END d[316]
  PIN d[317]
    DIRECTION INPUT ;
    USE SIGNAL ;
    PORT
      LAYER M4 ;
        RECT  0 78 0.084 78.024 ;
    END
  END d[317]
  PIN d[318]
    DIRECTION INPUT ;
    USE SIGNAL ;
    PORT
      LAYER M4 ;
        RECT  0 78.096 0.084 78.12 ;
    END
  END d[318]
  PIN d[319]
    DIRECTION INPUT ;
    USE SIGNAL ;
    PORT
      LAYER M4 ;
        RECT  0 84.336 0.084 84.36 ;
    END
  END d[319]
  PIN d[31]
    DIRECTION INPUT ;
    USE SIGNAL ;
    PORT
      LAYER M4 ;
        RECT  0 58.992 0.084 59.016 ;
    END
  END d[31]
  PIN d[320]
    DIRECTION INPUT ;
    USE SIGNAL ;
    PORT
      LAYER M4 ;
        RECT  0 84.432 0.084 84.456 ;
    END
  END d[320]
  PIN d[321]
    DIRECTION INPUT ;
    USE SIGNAL ;
    PORT
      LAYER M4 ;
        RECT  0 84.528 0.084 84.552 ;
    END
  END d[321]
  PIN d[322]
    DIRECTION INPUT ;
    USE SIGNAL ;
    PORT
      LAYER M4 ;
        RECT  0 84.624 0.084 84.648 ;
    END
  END d[322]
  PIN d[323]
    DIRECTION INPUT ;
    USE SIGNAL ;
    PORT
      LAYER M4 ;
        RECT  0 84.72 0.084 84.744 ;
    END
  END d[323]
  PIN d[324]
    DIRECTION INPUT ;
    USE SIGNAL ;
    PORT
      LAYER M4 ;
        RECT  0 84.816 0.084 84.84 ;
    END
  END d[324]
  PIN d[325]
    DIRECTION INPUT ;
    USE SIGNAL ;
    PORT
      LAYER M4 ;
        RECT  0 84.912 0.084 84.936 ;
    END
  END d[325]
  PIN d[326]
    DIRECTION INPUT ;
    USE SIGNAL ;
    PORT
      LAYER M4 ;
        RECT  0 85.008 0.084 85.032 ;
    END
  END d[326]
  PIN d[327]
    DIRECTION INPUT ;
    USE SIGNAL ;
    PORT
      LAYER M4 ;
        RECT  0 85.104 0.084 85.128 ;
    END
  END d[327]
  PIN d[328]
    DIRECTION INPUT ;
    USE SIGNAL ;
    PORT
      LAYER M4 ;
        RECT  0 85.2 0.084 85.224 ;
    END
  END d[328]
  PIN d[329]
    DIRECTION INPUT ;
    USE SIGNAL ;
    PORT
      LAYER M4 ;
        RECT  0 85.296 0.084 85.32 ;
    END
  END d[329]
  PIN d[32]
    DIRECTION INPUT ;
    USE SIGNAL ;
    PORT
      LAYER M4 ;
        RECT  0 59.088 0.084 59.112 ;
    END
  END d[32]
  PIN d[330]
    DIRECTION INPUT ;
    USE SIGNAL ;
    PORT
      LAYER M4 ;
        RECT  0 85.392 0.084 85.416 ;
    END
  END d[330]
  PIN d[331]
    DIRECTION INPUT ;
    USE SIGNAL ;
    PORT
      LAYER M4 ;
        RECT  0 85.488 0.084 85.512 ;
    END
  END d[331]
  PIN d[332]
    DIRECTION INPUT ;
    USE SIGNAL ;
    PORT
      LAYER M4 ;
        RECT  0 85.584 0.084 85.608 ;
    END
  END d[332]
  PIN d[333]
    DIRECTION INPUT ;
    USE SIGNAL ;
    PORT
      LAYER M4 ;
        RECT  0 85.68 0.084 85.704 ;
    END
  END d[333]
  PIN d[334]
    DIRECTION INPUT ;
    USE SIGNAL ;
    PORT
      LAYER M4 ;
        RECT  0 85.776 0.084 85.8 ;
    END
  END d[334]
  PIN d[335]
    DIRECTION INPUT ;
    USE SIGNAL ;
    PORT
      LAYER M4 ;
        RECT  0 85.872 0.084 85.896 ;
    END
  END d[335]
  PIN d[336]
    DIRECTION INPUT ;
    USE SIGNAL ;
    PORT
      LAYER M4 ;
        RECT  0 85.968 0.084 85.992 ;
    END
  END d[336]
  PIN d[337]
    DIRECTION INPUT ;
    USE SIGNAL ;
    PORT
      LAYER M4 ;
        RECT  0 86.064 0.084 86.088 ;
    END
  END d[337]
  PIN d[338]
    DIRECTION INPUT ;
    USE SIGNAL ;
    PORT
      LAYER M4 ;
        RECT  0 86.16 0.084 86.184 ;
    END
  END d[338]
  PIN d[339]
    DIRECTION INPUT ;
    USE SIGNAL ;
    PORT
      LAYER M4 ;
        RECT  0 86.256 0.084 86.28 ;
    END
  END d[339]
  PIN d[33]
    DIRECTION INPUT ;
    USE SIGNAL ;
    PORT
      LAYER M4 ;
        RECT  0 59.184 0.084 59.208 ;
    END
  END d[33]
  PIN d[340]
    DIRECTION INPUT ;
    USE SIGNAL ;
    PORT
      LAYER M4 ;
        RECT  0 86.352 0.084 86.376 ;
    END
  END d[340]
  PIN d[341]
    DIRECTION INPUT ;
    USE SIGNAL ;
    PORT
      LAYER M4 ;
        RECT  0 86.448 0.084 86.472 ;
    END
  END d[341]
  PIN d[342]
    DIRECTION INPUT ;
    USE SIGNAL ;
    PORT
      LAYER M4 ;
        RECT  0 86.544 0.084 86.568 ;
    END
  END d[342]
  PIN d[343]
    DIRECTION INPUT ;
    USE SIGNAL ;
    PORT
      LAYER M4 ;
        RECT  0 86.64 0.084 86.664 ;
    END
  END d[343]
  PIN d[344]
    DIRECTION INPUT ;
    USE SIGNAL ;
    PORT
      LAYER M4 ;
        RECT  0 86.736 0.084 86.76 ;
    END
  END d[344]
  PIN d[345]
    DIRECTION INPUT ;
    USE SIGNAL ;
    PORT
      LAYER M4 ;
        RECT  0 86.832 0.084 86.856 ;
    END
  END d[345]
  PIN d[346]
    DIRECTION INPUT ;
    USE SIGNAL ;
    PORT
      LAYER M4 ;
        RECT  0 86.928 0.084 86.952 ;
    END
  END d[346]
  PIN d[347]
    DIRECTION INPUT ;
    USE SIGNAL ;
    PORT
      LAYER M4 ;
        RECT  0 87.024 0.084 87.048 ;
    END
  END d[347]
  PIN d[348]
    DIRECTION INPUT ;
    USE SIGNAL ;
    PORT
      LAYER M4 ;
        RECT  0 87.12 0.084 87.144 ;
    END
  END d[348]
  PIN d[349]
    DIRECTION INPUT ;
    USE SIGNAL ;
    PORT
      LAYER M4 ;
        RECT  0 87.216 0.084 87.24 ;
    END
  END d[349]
  PIN d[34]
    DIRECTION INPUT ;
    USE SIGNAL ;
    PORT
      LAYER M4 ;
        RECT  0 59.28 0.084 59.304 ;
    END
  END d[34]
  PIN d[350]
    DIRECTION INPUT ;
    USE SIGNAL ;
    PORT
      LAYER M4 ;
        RECT  0 87.312 0.084 87.336 ;
    END
  END d[350]
  PIN d[351]
    DIRECTION INPUT ;
    USE SIGNAL ;
    PORT
      LAYER M4 ;
        RECT  0 78.192 0.084 78.216 ;
    END
  END d[351]
  PIN d[352]
    DIRECTION INPUT ;
    USE SIGNAL ;
    PORT
      LAYER M4 ;
        RECT  0 78.288 0.084 78.312 ;
    END
  END d[352]
  PIN d[353]
    DIRECTION INPUT ;
    USE SIGNAL ;
    PORT
      LAYER M4 ;
        RECT  0 78.384 0.084 78.408 ;
    END
  END d[353]
  PIN d[354]
    DIRECTION INPUT ;
    USE SIGNAL ;
    PORT
      LAYER M4 ;
        RECT  0 78.48 0.084 78.504 ;
    END
  END d[354]
  PIN d[355]
    DIRECTION INPUT ;
    USE SIGNAL ;
    PORT
      LAYER M4 ;
        RECT  0 78.576 0.084 78.6 ;
    END
  END d[355]
  PIN d[356]
    DIRECTION INPUT ;
    USE SIGNAL ;
    PORT
      LAYER M4 ;
        RECT  0 78.672 0.084 78.696 ;
    END
  END d[356]
  PIN d[357]
    DIRECTION INPUT ;
    USE SIGNAL ;
    PORT
      LAYER M4 ;
        RECT  0 78.768 0.084 78.792 ;
    END
  END d[357]
  PIN d[358]
    DIRECTION INPUT ;
    USE SIGNAL ;
    PORT
      LAYER M4 ;
        RECT  0 78.864 0.084 78.888 ;
    END
  END d[358]
  PIN d[359]
    DIRECTION INPUT ;
    USE SIGNAL ;
    PORT
      LAYER M4 ;
        RECT  0 78.96 0.084 78.984 ;
    END
  END d[359]
  PIN d[35]
    DIRECTION INPUT ;
    USE SIGNAL ;
    PORT
      LAYER M4 ;
        RECT  0 59.376 0.084 59.4 ;
    END
  END d[35]
  PIN d[360]
    DIRECTION INPUT ;
    USE SIGNAL ;
    PORT
      LAYER M4 ;
        RECT  0 79.056 0.084 79.08 ;
    END
  END d[360]
  PIN d[361]
    DIRECTION INPUT ;
    USE SIGNAL ;
    PORT
      LAYER M4 ;
        RECT  0 79.152 0.084 79.176 ;
    END
  END d[361]
  PIN d[362]
    DIRECTION INPUT ;
    USE SIGNAL ;
    PORT
      LAYER M4 ;
        RECT  0 79.248 0.084 79.272 ;
    END
  END d[362]
  PIN d[363]
    DIRECTION INPUT ;
    USE SIGNAL ;
    PORT
      LAYER M4 ;
        RECT  0 79.344 0.084 79.368 ;
    END
  END d[363]
  PIN d[364]
    DIRECTION INPUT ;
    USE SIGNAL ;
    PORT
      LAYER M4 ;
        RECT  0 79.44 0.084 79.464 ;
    END
  END d[364]
  PIN d[365]
    DIRECTION INPUT ;
    USE SIGNAL ;
    PORT
      LAYER M4 ;
        RECT  0 79.536 0.084 79.56 ;
    END
  END d[365]
  PIN d[366]
    DIRECTION INPUT ;
    USE SIGNAL ;
    PORT
      LAYER M4 ;
        RECT  0 79.632 0.084 79.656 ;
    END
  END d[366]
  PIN d[367]
    DIRECTION INPUT ;
    USE SIGNAL ;
    PORT
      LAYER M4 ;
        RECT  0 79.728 0.084 79.752 ;
    END
  END d[367]
  PIN d[368]
    DIRECTION INPUT ;
    USE SIGNAL ;
    PORT
      LAYER M4 ;
        RECT  0 79.824 0.084 79.848 ;
    END
  END d[368]
  PIN d[369]
    DIRECTION INPUT ;
    USE SIGNAL ;
    PORT
      LAYER M4 ;
        RECT  0 79.92 0.084 79.944 ;
    END
  END d[369]
  PIN d[36]
    DIRECTION INPUT ;
    USE SIGNAL ;
    PORT
      LAYER M4 ;
        RECT  0 59.472 0.084 59.496 ;
    END
  END d[36]
  PIN d[370]
    DIRECTION INPUT ;
    USE SIGNAL ;
    PORT
      LAYER M4 ;
        RECT  0 80.016 0.084 80.04 ;
    END
  END d[370]
  PIN d[371]
    DIRECTION INPUT ;
    USE SIGNAL ;
    PORT
      LAYER M4 ;
        RECT  0 80.112 0.084 80.136 ;
    END
  END d[371]
  PIN d[372]
    DIRECTION INPUT ;
    USE SIGNAL ;
    PORT
      LAYER M4 ;
        RECT  0 80.208 0.084 80.232 ;
    END
  END d[372]
  PIN d[373]
    DIRECTION INPUT ;
    USE SIGNAL ;
    PORT
      LAYER M4 ;
        RECT  0 80.304 0.084 80.328 ;
    END
  END d[373]
  PIN d[374]
    DIRECTION INPUT ;
    USE SIGNAL ;
    PORT
      LAYER M4 ;
        RECT  0 80.4 0.084 80.424 ;
    END
  END d[374]
  PIN d[375]
    DIRECTION INPUT ;
    USE SIGNAL ;
    PORT
      LAYER M4 ;
        RECT  0 80.496 0.084 80.52 ;
    END
  END d[375]
  PIN d[376]
    DIRECTION INPUT ;
    USE SIGNAL ;
    PORT
      LAYER M4 ;
        RECT  0 80.592 0.084 80.616 ;
    END
  END d[376]
  PIN d[377]
    DIRECTION INPUT ;
    USE SIGNAL ;
    PORT
      LAYER M4 ;
        RECT  0 80.688 0.084 80.712 ;
    END
  END d[377]
  PIN d[378]
    DIRECTION INPUT ;
    USE SIGNAL ;
    PORT
      LAYER M4 ;
        RECT  0 80.784 0.084 80.808 ;
    END
  END d[378]
  PIN d[379]
    DIRECTION INPUT ;
    USE SIGNAL ;
    PORT
      LAYER M4 ;
        RECT  0 80.88 0.084 80.904 ;
    END
  END d[379]
  PIN d[37]
    DIRECTION INPUT ;
    USE SIGNAL ;
    PORT
      LAYER M4 ;
        RECT  0 59.568 0.084 59.592 ;
    END
  END d[37]
  PIN d[380]
    DIRECTION INPUT ;
    USE SIGNAL ;
    PORT
      LAYER M4 ;
        RECT  0 80.976 0.084 81 ;
    END
  END d[380]
  PIN d[381]
    DIRECTION INPUT ;
    USE SIGNAL ;
    PORT
      LAYER M4 ;
        RECT  0 81.072 0.084 81.096 ;
    END
  END d[381]
  PIN d[382]
    DIRECTION INPUT ;
    USE SIGNAL ;
    PORT
      LAYER M4 ;
        RECT  0 81.168 0.084 81.192 ;
    END
  END d[382]
  PIN d[383]
    DIRECTION INPUT ;
    USE SIGNAL ;
    PORT
      LAYER M4 ;
        RECT  0 45.936 0.084 45.96 ;
    END
  END d[383]
  PIN d[384]
    DIRECTION INPUT ;
    USE SIGNAL ;
    PORT
      LAYER M4 ;
        RECT  0 46.032 0.084 46.056 ;
    END
  END d[384]
  PIN d[385]
    DIRECTION INPUT ;
    USE SIGNAL ;
    PORT
      LAYER M4 ;
        RECT  0 46.128 0.084 46.152 ;
    END
  END d[385]
  PIN d[386]
    DIRECTION INPUT ;
    USE SIGNAL ;
    PORT
      LAYER M4 ;
        RECT  0 46.224 0.084 46.248 ;
    END
  END d[386]
  PIN d[387]
    DIRECTION INPUT ;
    USE SIGNAL ;
    PORT
      LAYER M4 ;
        RECT  0 46.32 0.084 46.344 ;
    END
  END d[387]
  PIN d[388]
    DIRECTION INPUT ;
    USE SIGNAL ;
    PORT
      LAYER M4 ;
        RECT  0 46.416 0.084 46.44 ;
    END
  END d[388]
  PIN d[389]
    DIRECTION INPUT ;
    USE SIGNAL ;
    PORT
      LAYER M4 ;
        RECT  0 46.512 0.084 46.536 ;
    END
  END d[389]
  PIN d[38]
    DIRECTION INPUT ;
    USE SIGNAL ;
    PORT
      LAYER M4 ;
        RECT  0 59.664 0.084 59.688 ;
    END
  END d[38]
  PIN d[390]
    DIRECTION INPUT ;
    USE SIGNAL ;
    PORT
      LAYER M4 ;
        RECT  0 46.608 0.084 46.632 ;
    END
  END d[390]
  PIN d[391]
    DIRECTION INPUT ;
    USE SIGNAL ;
    PORT
      LAYER M4 ;
        RECT  0 46.704 0.084 46.728 ;
    END
  END d[391]
  PIN d[392]
    DIRECTION INPUT ;
    USE SIGNAL ;
    PORT
      LAYER M4 ;
        RECT  0 46.8 0.084 46.824 ;
    END
  END d[392]
  PIN d[393]
    DIRECTION INPUT ;
    USE SIGNAL ;
    PORT
      LAYER M4 ;
        RECT  0 46.896 0.084 46.92 ;
    END
  END d[393]
  PIN d[394]
    DIRECTION INPUT ;
    USE SIGNAL ;
    PORT
      LAYER M4 ;
        RECT  0 46.992 0.084 47.016 ;
    END
  END d[394]
  PIN d[395]
    DIRECTION INPUT ;
    USE SIGNAL ;
    PORT
      LAYER M4 ;
        RECT  0 47.088 0.084 47.112 ;
    END
  END d[395]
  PIN d[396]
    DIRECTION INPUT ;
    USE SIGNAL ;
    PORT
      LAYER M4 ;
        RECT  0 47.184 0.084 47.208 ;
    END
  END d[396]
  PIN d[397]
    DIRECTION INPUT ;
    USE SIGNAL ;
    PORT
      LAYER M4 ;
        RECT  0 47.28 0.084 47.304 ;
    END
  END d[397]
  PIN d[398]
    DIRECTION INPUT ;
    USE SIGNAL ;
    PORT
      LAYER M4 ;
        RECT  0 47.376 0.084 47.4 ;
    END
  END d[398]
  PIN d[399]
    DIRECTION INPUT ;
    USE SIGNAL ;
    PORT
      LAYER M4 ;
        RECT  0 47.472 0.084 47.496 ;
    END
  END d[399]
  PIN d[39]
    DIRECTION INPUT ;
    USE SIGNAL ;
    PORT
      LAYER M4 ;
        RECT  0 59.76 0.084 59.784 ;
    END
  END d[39]
  PIN d[3]
    DIRECTION INPUT ;
    USE SIGNAL ;
    PORT
      LAYER M4 ;
        RECT  0 62.448 0.084 62.472 ;
    END
  END d[3]
  PIN d[400]
    DIRECTION INPUT ;
    USE SIGNAL ;
    PORT
      LAYER M4 ;
        RECT  0 47.568 0.084 47.592 ;
    END
  END d[400]
  PIN d[401]
    DIRECTION INPUT ;
    USE SIGNAL ;
    PORT
      LAYER M4 ;
        RECT  0 47.664 0.084 47.688 ;
    END
  END d[401]
  PIN d[402]
    DIRECTION INPUT ;
    USE SIGNAL ;
    PORT
      LAYER M4 ;
        RECT  0 47.76 0.084 47.784 ;
    END
  END d[402]
  PIN d[403]
    DIRECTION INPUT ;
    USE SIGNAL ;
    PORT
      LAYER M4 ;
        RECT  0 47.856 0.084 47.88 ;
    END
  END d[403]
  PIN d[404]
    DIRECTION INPUT ;
    USE SIGNAL ;
    PORT
      LAYER M4 ;
        RECT  0 47.952 0.084 47.976 ;
    END
  END d[404]
  PIN d[405]
    DIRECTION INPUT ;
    USE SIGNAL ;
    PORT
      LAYER M4 ;
        RECT  0 48.048 0.084 48.072 ;
    END
  END d[405]
  PIN d[406]
    DIRECTION INPUT ;
    USE SIGNAL ;
    PORT
      LAYER M4 ;
        RECT  0 48.144 0.084 48.168 ;
    END
  END d[406]
  PIN d[407]
    DIRECTION INPUT ;
    USE SIGNAL ;
    PORT
      LAYER M4 ;
        RECT  0 48.24 0.084 48.264 ;
    END
  END d[407]
  PIN d[408]
    DIRECTION INPUT ;
    USE SIGNAL ;
    PORT
      LAYER M4 ;
        RECT  0 48.336 0.084 48.36 ;
    END
  END d[408]
  PIN d[409]
    DIRECTION INPUT ;
    USE SIGNAL ;
    PORT
      LAYER M4 ;
        RECT  0 48.432 0.084 48.456 ;
    END
  END d[409]
  PIN d[40]
    DIRECTION INPUT ;
    USE SIGNAL ;
    PORT
      LAYER M4 ;
        RECT  0 59.856 0.084 59.88 ;
    END
  END d[40]
  PIN d[410]
    DIRECTION INPUT ;
    USE SIGNAL ;
    PORT
      LAYER M4 ;
        RECT  0 48.528 0.084 48.552 ;
    END
  END d[410]
  PIN d[411]
    DIRECTION INPUT ;
    USE SIGNAL ;
    PORT
      LAYER M4 ;
        RECT  0 48.624 0.084 48.648 ;
    END
  END d[411]
  PIN d[412]
    DIRECTION INPUT ;
    USE SIGNAL ;
    PORT
      LAYER M4 ;
        RECT  0 48.72 0.084 48.744 ;
    END
  END d[412]
  PIN d[413]
    DIRECTION INPUT ;
    USE SIGNAL ;
    PORT
      LAYER M4 ;
        RECT  0 48.816 0.084 48.84 ;
    END
  END d[413]
  PIN d[414]
    DIRECTION INPUT ;
    USE SIGNAL ;
    PORT
      LAYER M4 ;
        RECT  0 48.912 0.084 48.936 ;
    END
  END d[414]
  PIN d[415]
    DIRECTION INPUT ;
    USE SIGNAL ;
    PORT
      LAYER M4 ;
        RECT  0 42.864 0.084 42.888 ;
    END
  END d[415]
  PIN d[416]
    DIRECTION INPUT ;
    USE SIGNAL ;
    PORT
      LAYER M4 ;
        RECT  0 42.96 0.084 42.984 ;
    END
  END d[416]
  PIN d[417]
    DIRECTION INPUT ;
    USE SIGNAL ;
    PORT
      LAYER M4 ;
        RECT  0 43.056 0.084 43.08 ;
    END
  END d[417]
  PIN d[418]
    DIRECTION INPUT ;
    USE SIGNAL ;
    PORT
      LAYER M4 ;
        RECT  0 43.152 0.084 43.176 ;
    END
  END d[418]
  PIN d[419]
    DIRECTION INPUT ;
    USE SIGNAL ;
    PORT
      LAYER M4 ;
        RECT  0 43.248 0.084 43.272 ;
    END
  END d[419]
  PIN d[41]
    DIRECTION INPUT ;
    USE SIGNAL ;
    PORT
      LAYER M4 ;
        RECT  0 59.952 0.084 59.976 ;
    END
  END d[41]
  PIN d[420]
    DIRECTION INPUT ;
    USE SIGNAL ;
    PORT
      LAYER M4 ;
        RECT  0 43.344 0.084 43.368 ;
    END
  END d[420]
  PIN d[421]
    DIRECTION INPUT ;
    USE SIGNAL ;
    PORT
      LAYER M4 ;
        RECT  0 43.44 0.084 43.464 ;
    END
  END d[421]
  PIN d[422]
    DIRECTION INPUT ;
    USE SIGNAL ;
    PORT
      LAYER M4 ;
        RECT  0 43.536 0.084 43.56 ;
    END
  END d[422]
  PIN d[423]
    DIRECTION INPUT ;
    USE SIGNAL ;
    PORT
      LAYER M4 ;
        RECT  0 43.632 0.084 43.656 ;
    END
  END d[423]
  PIN d[424]
    DIRECTION INPUT ;
    USE SIGNAL ;
    PORT
      LAYER M4 ;
        RECT  0 43.728 0.084 43.752 ;
    END
  END d[424]
  PIN d[425]
    DIRECTION INPUT ;
    USE SIGNAL ;
    PORT
      LAYER M4 ;
        RECT  0 43.824 0.084 43.848 ;
    END
  END d[425]
  PIN d[426]
    DIRECTION INPUT ;
    USE SIGNAL ;
    PORT
      LAYER M4 ;
        RECT  0 43.92 0.084 43.944 ;
    END
  END d[426]
  PIN d[427]
    DIRECTION INPUT ;
    USE SIGNAL ;
    PORT
      LAYER M4 ;
        RECT  0 44.016 0.084 44.04 ;
    END
  END d[427]
  PIN d[428]
    DIRECTION INPUT ;
    USE SIGNAL ;
    PORT
      LAYER M4 ;
        RECT  0 44.112 0.084 44.136 ;
    END
  END d[428]
  PIN d[429]
    DIRECTION INPUT ;
    USE SIGNAL ;
    PORT
      LAYER M4 ;
        RECT  0 44.208 0.084 44.232 ;
    END
  END d[429]
  PIN d[42]
    DIRECTION INPUT ;
    USE SIGNAL ;
    PORT
      LAYER M4 ;
        RECT  0 60.048 0.084 60.072 ;
    END
  END d[42]
  PIN d[430]
    DIRECTION INPUT ;
    USE SIGNAL ;
    PORT
      LAYER M4 ;
        RECT  0 44.304 0.084 44.328 ;
    END
  END d[430]
  PIN d[431]
    DIRECTION INPUT ;
    USE SIGNAL ;
    PORT
      LAYER M4 ;
        RECT  0 44.4 0.084 44.424 ;
    END
  END d[431]
  PIN d[432]
    DIRECTION INPUT ;
    USE SIGNAL ;
    PORT
      LAYER M4 ;
        RECT  0 44.496 0.084 44.52 ;
    END
  END d[432]
  PIN d[433]
    DIRECTION INPUT ;
    USE SIGNAL ;
    PORT
      LAYER M4 ;
        RECT  0 44.592 0.084 44.616 ;
    END
  END d[433]
  PIN d[434]
    DIRECTION INPUT ;
    USE SIGNAL ;
    PORT
      LAYER M4 ;
        RECT  0 44.688 0.084 44.712 ;
    END
  END d[434]
  PIN d[435]
    DIRECTION INPUT ;
    USE SIGNAL ;
    PORT
      LAYER M4 ;
        RECT  0 44.784 0.084 44.808 ;
    END
  END d[435]
  PIN d[436]
    DIRECTION INPUT ;
    USE SIGNAL ;
    PORT
      LAYER M4 ;
        RECT  0 44.88 0.084 44.904 ;
    END
  END d[436]
  PIN d[437]
    DIRECTION INPUT ;
    USE SIGNAL ;
    PORT
      LAYER M4 ;
        RECT  0 44.976 0.084 45 ;
    END
  END d[437]
  PIN d[438]
    DIRECTION INPUT ;
    USE SIGNAL ;
    PORT
      LAYER M4 ;
        RECT  0 45.072 0.084 45.096 ;
    END
  END d[438]
  PIN d[439]
    DIRECTION INPUT ;
    USE SIGNAL ;
    PORT
      LAYER M4 ;
        RECT  0 45.168 0.084 45.192 ;
    END
  END d[439]
  PIN d[43]
    DIRECTION INPUT ;
    USE SIGNAL ;
    PORT
      LAYER M4 ;
        RECT  0 60.144 0.084 60.168 ;
    END
  END d[43]
  PIN d[440]
    DIRECTION INPUT ;
    USE SIGNAL ;
    PORT
      LAYER M4 ;
        RECT  0 45.264 0.084 45.288 ;
    END
  END d[440]
  PIN d[441]
    DIRECTION INPUT ;
    USE SIGNAL ;
    PORT
      LAYER M4 ;
        RECT  0 45.36 0.084 45.384 ;
    END
  END d[441]
  PIN d[442]
    DIRECTION INPUT ;
    USE SIGNAL ;
    PORT
      LAYER M4 ;
        RECT  0 45.456 0.084 45.48 ;
    END
  END d[442]
  PIN d[443]
    DIRECTION INPUT ;
    USE SIGNAL ;
    PORT
      LAYER M4 ;
        RECT  0 45.552 0.084 45.576 ;
    END
  END d[443]
  PIN d[444]
    DIRECTION INPUT ;
    USE SIGNAL ;
    PORT
      LAYER M4 ;
        RECT  0 45.648 0.084 45.672 ;
    END
  END d[444]
  PIN d[445]
    DIRECTION INPUT ;
    USE SIGNAL ;
    PORT
      LAYER M4 ;
        RECT  0 45.744 0.084 45.768 ;
    END
  END d[445]
  PIN d[446]
    DIRECTION INPUT ;
    USE SIGNAL ;
    PORT
      LAYER M4 ;
        RECT  0 45.84 0.084 45.864 ;
    END
  END d[446]
  PIN d[447]
    DIRECTION INPUT ;
    USE SIGNAL ;
    PORT
      LAYER M4 ;
        RECT  0 39.792 0.084 39.816 ;
    END
  END d[447]
  PIN d[448]
    DIRECTION INPUT ;
    USE SIGNAL ;
    PORT
      LAYER M4 ;
        RECT  0 39.888 0.084 39.912 ;
    END
  END d[448]
  PIN d[449]
    DIRECTION INPUT ;
    USE SIGNAL ;
    PORT
      LAYER M4 ;
        RECT  0 39.984 0.084 40.008 ;
    END
  END d[449]
  PIN d[44]
    DIRECTION INPUT ;
    USE SIGNAL ;
    PORT
      LAYER M4 ;
        RECT  0 60.24 0.084 60.264 ;
    END
  END d[44]
  PIN d[450]
    DIRECTION INPUT ;
    USE SIGNAL ;
    PORT
      LAYER M4 ;
        RECT  0 40.08 0.084 40.104 ;
    END
  END d[450]
  PIN d[451]
    DIRECTION INPUT ;
    USE SIGNAL ;
    PORT
      LAYER M4 ;
        RECT  0 40.176 0.084 40.2 ;
    END
  END d[451]
  PIN d[452]
    DIRECTION INPUT ;
    USE SIGNAL ;
    PORT
      LAYER M4 ;
        RECT  0 40.272 0.084 40.296 ;
    END
  END d[452]
  PIN d[453]
    DIRECTION INPUT ;
    USE SIGNAL ;
    PORT
      LAYER M4 ;
        RECT  0 40.368 0.084 40.392 ;
    END
  END d[453]
  PIN d[454]
    DIRECTION INPUT ;
    USE SIGNAL ;
    PORT
      LAYER M4 ;
        RECT  0 40.464 0.084 40.488 ;
    END
  END d[454]
  PIN d[455]
    DIRECTION INPUT ;
    USE SIGNAL ;
    PORT
      LAYER M4 ;
        RECT  0 40.56 0.084 40.584 ;
    END
  END d[455]
  PIN d[456]
    DIRECTION INPUT ;
    USE SIGNAL ;
    PORT
      LAYER M4 ;
        RECT  0 40.656 0.084 40.68 ;
    END
  END d[456]
  PIN d[457]
    DIRECTION INPUT ;
    USE SIGNAL ;
    PORT
      LAYER M4 ;
        RECT  0 40.752 0.084 40.776 ;
    END
  END d[457]
  PIN d[458]
    DIRECTION INPUT ;
    USE SIGNAL ;
    PORT
      LAYER M4 ;
        RECT  0 40.848 0.084 40.872 ;
    END
  END d[458]
  PIN d[459]
    DIRECTION INPUT ;
    USE SIGNAL ;
    PORT
      LAYER M4 ;
        RECT  0 40.944 0.084 40.968 ;
    END
  END d[459]
  PIN d[45]
    DIRECTION INPUT ;
    USE SIGNAL ;
    PORT
      LAYER M4 ;
        RECT  0 60.336 0.084 60.36 ;
    END
  END d[45]
  PIN d[460]
    DIRECTION INPUT ;
    USE SIGNAL ;
    PORT
      LAYER M4 ;
        RECT  0 41.04 0.084 41.064 ;
    END
  END d[460]
  PIN d[461]
    DIRECTION INPUT ;
    USE SIGNAL ;
    PORT
      LAYER M4 ;
        RECT  0 41.136 0.084 41.16 ;
    END
  END d[461]
  PIN d[462]
    DIRECTION INPUT ;
    USE SIGNAL ;
    PORT
      LAYER M4 ;
        RECT  0 41.232 0.084 41.256 ;
    END
  END d[462]
  PIN d[463]
    DIRECTION INPUT ;
    USE SIGNAL ;
    PORT
      LAYER M4 ;
        RECT  0 41.328 0.084 41.352 ;
    END
  END d[463]
  PIN d[464]
    DIRECTION INPUT ;
    USE SIGNAL ;
    PORT
      LAYER M4 ;
        RECT  0 41.424 0.084 41.448 ;
    END
  END d[464]
  PIN d[465]
    DIRECTION INPUT ;
    USE SIGNAL ;
    PORT
      LAYER M4 ;
        RECT  0 41.52 0.084 41.544 ;
    END
  END d[465]
  PIN d[466]
    DIRECTION INPUT ;
    USE SIGNAL ;
    PORT
      LAYER M4 ;
        RECT  0 41.616 0.084 41.64 ;
    END
  END d[466]
  PIN d[467]
    DIRECTION INPUT ;
    USE SIGNAL ;
    PORT
      LAYER M4 ;
        RECT  0 41.712 0.084 41.736 ;
    END
  END d[467]
  PIN d[468]
    DIRECTION INPUT ;
    USE SIGNAL ;
    PORT
      LAYER M4 ;
        RECT  0 41.808 0.084 41.832 ;
    END
  END d[468]
  PIN d[469]
    DIRECTION INPUT ;
    USE SIGNAL ;
    PORT
      LAYER M4 ;
        RECT  0 41.904 0.084 41.928 ;
    END
  END d[469]
  PIN d[46]
    DIRECTION INPUT ;
    USE SIGNAL ;
    PORT
      LAYER M4 ;
        RECT  0 60.432 0.084 60.456 ;
    END
  END d[46]
  PIN d[470]
    DIRECTION INPUT ;
    USE SIGNAL ;
    PORT
      LAYER M4 ;
        RECT  0 42 0.084 42.024 ;
    END
  END d[470]
  PIN d[471]
    DIRECTION INPUT ;
    USE SIGNAL ;
    PORT
      LAYER M4 ;
        RECT  0 42.096 0.084 42.12 ;
    END
  END d[471]
  PIN d[472]
    DIRECTION INPUT ;
    USE SIGNAL ;
    PORT
      LAYER M4 ;
        RECT  0 42.192 0.084 42.216 ;
    END
  END d[472]
  PIN d[473]
    DIRECTION INPUT ;
    USE SIGNAL ;
    PORT
      LAYER M4 ;
        RECT  0 42.288 0.084 42.312 ;
    END
  END d[473]
  PIN d[474]
    DIRECTION INPUT ;
    USE SIGNAL ;
    PORT
      LAYER M4 ;
        RECT  0 42.384 0.084 42.408 ;
    END
  END d[474]
  PIN d[475]
    DIRECTION INPUT ;
    USE SIGNAL ;
    PORT
      LAYER M4 ;
        RECT  0 42.48 0.084 42.504 ;
    END
  END d[475]
  PIN d[476]
    DIRECTION INPUT ;
    USE SIGNAL ;
    PORT
      LAYER M4 ;
        RECT  0 42.576 0.084 42.6 ;
    END
  END d[476]
  PIN d[477]
    DIRECTION INPUT ;
    USE SIGNAL ;
    PORT
      LAYER M4 ;
        RECT  0 42.672 0.084 42.696 ;
    END
  END d[477]
  PIN d[478]
    DIRECTION INPUT ;
    USE SIGNAL ;
    PORT
      LAYER M4 ;
        RECT  0 42.768 0.084 42.792 ;
    END
  END d[478]
  PIN d[479]
    DIRECTION INPUT ;
    USE SIGNAL ;
    PORT
      LAYER M4 ;
        RECT  0 49.008 0.084 49.032 ;
    END
  END d[479]
  PIN d[47]
    DIRECTION INPUT ;
    USE SIGNAL ;
    PORT
      LAYER M4 ;
        RECT  0 60.528 0.084 60.552 ;
    END
  END d[47]
  PIN d[480]
    DIRECTION INPUT ;
    USE SIGNAL ;
    PORT
      LAYER M4 ;
        RECT  0 49.104 0.084 49.128 ;
    END
  END d[480]
  PIN d[481]
    DIRECTION INPUT ;
    USE SIGNAL ;
    PORT
      LAYER M4 ;
        RECT  0 49.2 0.084 49.224 ;
    END
  END d[481]
  PIN d[482]
    DIRECTION INPUT ;
    USE SIGNAL ;
    PORT
      LAYER M4 ;
        RECT  0 49.296 0.084 49.32 ;
    END
  END d[482]
  PIN d[483]
    DIRECTION INPUT ;
    USE SIGNAL ;
    PORT
      LAYER M4 ;
        RECT  0 49.392 0.084 49.416 ;
    END
  END d[483]
  PIN d[484]
    DIRECTION INPUT ;
    USE SIGNAL ;
    PORT
      LAYER M4 ;
        RECT  0 49.488 0.084 49.512 ;
    END
  END d[484]
  PIN d[485]
    DIRECTION INPUT ;
    USE SIGNAL ;
    PORT
      LAYER M4 ;
        RECT  0 49.584 0.084 49.608 ;
    END
  END d[485]
  PIN d[486]
    DIRECTION INPUT ;
    USE SIGNAL ;
    PORT
      LAYER M4 ;
        RECT  0 49.68 0.084 49.704 ;
    END
  END d[486]
  PIN d[487]
    DIRECTION INPUT ;
    USE SIGNAL ;
    PORT
      LAYER M4 ;
        RECT  0 49.776 0.084 49.8 ;
    END
  END d[487]
  PIN d[488]
    DIRECTION INPUT ;
    USE SIGNAL ;
    PORT
      LAYER M4 ;
        RECT  0 49.872 0.084 49.896 ;
    END
  END d[488]
  PIN d[489]
    DIRECTION INPUT ;
    USE SIGNAL ;
    PORT
      LAYER M4 ;
        RECT  0 49.968 0.084 49.992 ;
    END
  END d[489]
  PIN d[48]
    DIRECTION INPUT ;
    USE SIGNAL ;
    PORT
      LAYER M4 ;
        RECT  0 60.624 0.084 60.648 ;
    END
  END d[48]
  PIN d[490]
    DIRECTION INPUT ;
    USE SIGNAL ;
    PORT
      LAYER M4 ;
        RECT  0 50.064 0.084 50.088 ;
    END
  END d[490]
  PIN d[491]
    DIRECTION INPUT ;
    USE SIGNAL ;
    PORT
      LAYER M4 ;
        RECT  0 50.16 0.084 50.184 ;
    END
  END d[491]
  PIN d[492]
    DIRECTION INPUT ;
    USE SIGNAL ;
    PORT
      LAYER M4 ;
        RECT  0 50.256 0.084 50.28 ;
    END
  END d[492]
  PIN d[493]
    DIRECTION INPUT ;
    USE SIGNAL ;
    PORT
      LAYER M4 ;
        RECT  0 50.352 0.084 50.376 ;
    END
  END d[493]
  PIN d[494]
    DIRECTION INPUT ;
    USE SIGNAL ;
    PORT
      LAYER M4 ;
        RECT  0 50.448 0.084 50.472 ;
    END
  END d[494]
  PIN d[495]
    DIRECTION INPUT ;
    USE SIGNAL ;
    PORT
      LAYER M4 ;
        RECT  0 50.544 0.084 50.568 ;
    END
  END d[495]
  PIN d[496]
    DIRECTION INPUT ;
    USE SIGNAL ;
    PORT
      LAYER M4 ;
        RECT  0 50.64 0.084 50.664 ;
    END
  END d[496]
  PIN d[497]
    DIRECTION INPUT ;
    USE SIGNAL ;
    PORT
      LAYER M4 ;
        RECT  0 50.736 0.084 50.76 ;
    END
  END d[497]
  PIN d[498]
    DIRECTION INPUT ;
    USE SIGNAL ;
    PORT
      LAYER M4 ;
        RECT  0 50.832 0.084 50.856 ;
    END
  END d[498]
  PIN d[499]
    DIRECTION INPUT ;
    USE SIGNAL ;
    PORT
      LAYER M4 ;
        RECT  0 50.928 0.084 50.952 ;
    END
  END d[499]
  PIN d[49]
    DIRECTION INPUT ;
    USE SIGNAL ;
    PORT
      LAYER M4 ;
        RECT  0 60.72 0.084 60.744 ;
    END
  END d[49]
  PIN d[4]
    DIRECTION INPUT ;
    USE SIGNAL ;
    PORT
      LAYER M4 ;
        RECT  0 62.544 0.084 62.568 ;
    END
  END d[4]
  PIN d[500]
    DIRECTION INPUT ;
    USE SIGNAL ;
    PORT
      LAYER M4 ;
        RECT  0 51.024 0.084 51.048 ;
    END
  END d[500]
  PIN d[501]
    DIRECTION INPUT ;
    USE SIGNAL ;
    PORT
      LAYER M4 ;
        RECT  0 51.12 0.084 51.144 ;
    END
  END d[501]
  PIN d[502]
    DIRECTION INPUT ;
    USE SIGNAL ;
    PORT
      LAYER M4 ;
        RECT  0 51.216 0.084 51.24 ;
    END
  END d[502]
  PIN d[503]
    DIRECTION INPUT ;
    USE SIGNAL ;
    PORT
      LAYER M4 ;
        RECT  0 51.312 0.084 51.336 ;
    END
  END d[503]
  PIN d[504]
    DIRECTION INPUT ;
    USE SIGNAL ;
    PORT
      LAYER M4 ;
        RECT  0 51.408 0.084 51.432 ;
    END
  END d[504]
  PIN d[505]
    DIRECTION INPUT ;
    USE SIGNAL ;
    PORT
      LAYER M4 ;
        RECT  0 51.504 0.084 51.528 ;
    END
  END d[505]
  PIN d[506]
    DIRECTION INPUT ;
    USE SIGNAL ;
    PORT
      LAYER M4 ;
        RECT  0 51.6 0.084 51.624 ;
    END
  END d[506]
  PIN d[507]
    DIRECTION INPUT ;
    USE SIGNAL ;
    PORT
      LAYER M4 ;
        RECT  0 51.696 0.084 51.72 ;
    END
  END d[507]
  PIN d[508]
    DIRECTION INPUT ;
    USE SIGNAL ;
    PORT
      LAYER M4 ;
        RECT  0 51.792 0.084 51.816 ;
    END
  END d[508]
  PIN d[509]
    DIRECTION INPUT ;
    USE SIGNAL ;
    PORT
      LAYER M4 ;
        RECT  0 51.888 0.084 51.912 ;
    END
  END d[509]
  PIN d[50]
    DIRECTION INPUT ;
    USE SIGNAL ;
    PORT
      LAYER M4 ;
        RECT  0 60.816 0.084 60.84 ;
    END
  END d[50]
  PIN d[510]
    DIRECTION INPUT ;
    USE SIGNAL ;
    PORT
      LAYER M4 ;
        RECT  0 51.984 0.084 52.008 ;
    END
  END d[510]
  PIN d[511]
    DIRECTION INPUT ;
    USE SIGNAL ;
    PORT
      LAYER M4 ;
        RECT  0 71.952 0.084 71.976 ;
    END
  END d[511]
  PIN d[51]
    DIRECTION INPUT ;
    USE SIGNAL ;
    PORT
      LAYER M4 ;
        RECT  0 60.912 0.084 60.936 ;
    END
  END d[51]
  PIN d[52]
    DIRECTION INPUT ;
    USE SIGNAL ;
    PORT
      LAYER M4 ;
        RECT  0 61.008 0.084 61.032 ;
    END
  END d[52]
  PIN d[53]
    DIRECTION INPUT ;
    USE SIGNAL ;
    PORT
      LAYER M4 ;
        RECT  0 61.104 0.084 61.128 ;
    END
  END d[53]
  PIN d[54]
    DIRECTION INPUT ;
    USE SIGNAL ;
    PORT
      LAYER M4 ;
        RECT  0 61.2 0.084 61.224 ;
    END
  END d[54]
  PIN d[55]
    DIRECTION INPUT ;
    USE SIGNAL ;
    PORT
      LAYER M4 ;
        RECT  0 61.296 0.084 61.32 ;
    END
  END d[55]
  PIN d[56]
    DIRECTION INPUT ;
    USE SIGNAL ;
    PORT
      LAYER M4 ;
        RECT  0 61.392 0.084 61.416 ;
    END
  END d[56]
  PIN d[57]
    DIRECTION INPUT ;
    USE SIGNAL ;
    PORT
      LAYER M4 ;
        RECT  0 61.488 0.084 61.512 ;
    END
  END d[57]
  PIN d[58]
    DIRECTION INPUT ;
    USE SIGNAL ;
    PORT
      LAYER M4 ;
        RECT  0 61.584 0.084 61.608 ;
    END
  END d[58]
  PIN d[59]
    DIRECTION INPUT ;
    USE SIGNAL ;
    PORT
      LAYER M4 ;
        RECT  0 61.68 0.084 61.704 ;
    END
  END d[59]
  PIN d[5]
    DIRECTION INPUT ;
    USE SIGNAL ;
    PORT
      LAYER M4 ;
        RECT  0 62.64 0.084 62.664 ;
    END
  END d[5]
  PIN d[60]
    DIRECTION INPUT ;
    USE SIGNAL ;
    PORT
      LAYER M4 ;
        RECT  0 61.776 0.084 61.8 ;
    END
  END d[60]
  PIN d[61]
    DIRECTION INPUT ;
    USE SIGNAL ;
    PORT
      LAYER M4 ;
        RECT  0 61.872 0.084 61.896 ;
    END
  END d[61]
  PIN d[62]
    DIRECTION INPUT ;
    USE SIGNAL ;
    PORT
      LAYER M4 ;
        RECT  0 61.968 0.084 61.992 ;
    END
  END d[62]
  PIN d[63]
    DIRECTION INPUT ;
    USE SIGNAL ;
    PORT
      LAYER M4 ;
        RECT  0 52.848 0.084 52.872 ;
    END
  END d[63]
  PIN d[64]
    DIRECTION INPUT ;
    USE SIGNAL ;
    PORT
      LAYER M4 ;
        RECT  0 52.944 0.084 52.968 ;
    END
  END d[64]
  PIN d[65]
    DIRECTION INPUT ;
    USE SIGNAL ;
    PORT
      LAYER M4 ;
        RECT  0 53.04 0.084 53.064 ;
    END
  END d[65]
  PIN d[66]
    DIRECTION INPUT ;
    USE SIGNAL ;
    PORT
      LAYER M4 ;
        RECT  0 53.136 0.084 53.16 ;
    END
  END d[66]
  PIN d[67]
    DIRECTION INPUT ;
    USE SIGNAL ;
    PORT
      LAYER M4 ;
        RECT  0 53.232 0.084 53.256 ;
    END
  END d[67]
  PIN d[68]
    DIRECTION INPUT ;
    USE SIGNAL ;
    PORT
      LAYER M4 ;
        RECT  0 53.328 0.084 53.352 ;
    END
  END d[68]
  PIN d[69]
    DIRECTION INPUT ;
    USE SIGNAL ;
    PORT
      LAYER M4 ;
        RECT  0 53.424 0.084 53.448 ;
    END
  END d[69]
  PIN d[6]
    DIRECTION INPUT ;
    USE SIGNAL ;
    PORT
      LAYER M4 ;
        RECT  0 62.736 0.084 62.76 ;
    END
  END d[6]
  PIN d[70]
    DIRECTION INPUT ;
    USE SIGNAL ;
    PORT
      LAYER M4 ;
        RECT  0 53.52 0.084 53.544 ;
    END
  END d[70]
  PIN d[71]
    DIRECTION INPUT ;
    USE SIGNAL ;
    PORT
      LAYER M4 ;
        RECT  0 53.616 0.084 53.64 ;
    END
  END d[71]
  PIN d[72]
    DIRECTION INPUT ;
    USE SIGNAL ;
    PORT
      LAYER M4 ;
        RECT  0 53.712 0.084 53.736 ;
    END
  END d[72]
  PIN d[73]
    DIRECTION INPUT ;
    USE SIGNAL ;
    PORT
      LAYER M4 ;
        RECT  0 53.808 0.084 53.832 ;
    END
  END d[73]
  PIN d[74]
    DIRECTION INPUT ;
    USE SIGNAL ;
    PORT
      LAYER M4 ;
        RECT  0 53.904 0.084 53.928 ;
    END
  END d[74]
  PIN d[75]
    DIRECTION INPUT ;
    USE SIGNAL ;
    PORT
      LAYER M4 ;
        RECT  0 54 0.084 54.024 ;
    END
  END d[75]
  PIN d[76]
    DIRECTION INPUT ;
    USE SIGNAL ;
    PORT
      LAYER M4 ;
        RECT  0 54.096 0.084 54.12 ;
    END
  END d[76]
  PIN d[77]
    DIRECTION INPUT ;
    USE SIGNAL ;
    PORT
      LAYER M4 ;
        RECT  0 54.192 0.084 54.216 ;
    END
  END d[77]
  PIN d[78]
    DIRECTION INPUT ;
    USE SIGNAL ;
    PORT
      LAYER M4 ;
        RECT  0 54.288 0.084 54.312 ;
    END
  END d[78]
  PIN d[79]
    DIRECTION INPUT ;
    USE SIGNAL ;
    PORT
      LAYER M4 ;
        RECT  0 54.384 0.084 54.408 ;
    END
  END d[79]
  PIN d[7]
    DIRECTION INPUT ;
    USE SIGNAL ;
    PORT
      LAYER M4 ;
        RECT  0 62.832 0.084 62.856 ;
    END
  END d[7]
  PIN d[80]
    DIRECTION INPUT ;
    USE SIGNAL ;
    PORT
      LAYER M4 ;
        RECT  0 54.48 0.084 54.504 ;
    END
  END d[80]
  PIN d[81]
    DIRECTION INPUT ;
    USE SIGNAL ;
    PORT
      LAYER M4 ;
        RECT  0 54.576 0.084 54.6 ;
    END
  END d[81]
  PIN d[82]
    DIRECTION INPUT ;
    USE SIGNAL ;
    PORT
      LAYER M4 ;
        RECT  0 54.672 0.084 54.696 ;
    END
  END d[82]
  PIN d[83]
    DIRECTION INPUT ;
    USE SIGNAL ;
    PORT
      LAYER M4 ;
        RECT  0 54.768 0.084 54.792 ;
    END
  END d[83]
  PIN d[84]
    DIRECTION INPUT ;
    USE SIGNAL ;
    PORT
      LAYER M4 ;
        RECT  0 54.864 0.084 54.888 ;
    END
  END d[84]
  PIN d[85]
    DIRECTION INPUT ;
    USE SIGNAL ;
    PORT
      LAYER M4 ;
        RECT  0 54.96 0.084 54.984 ;
    END
  END d[85]
  PIN d[86]
    DIRECTION INPUT ;
    USE SIGNAL ;
    PORT
      LAYER M4 ;
        RECT  0 55.056 0.084 55.08 ;
    END
  END d[86]
  PIN d[87]
    DIRECTION INPUT ;
    USE SIGNAL ;
    PORT
      LAYER M4 ;
        RECT  0 55.152 0.084 55.176 ;
    END
  END d[87]
  PIN d[88]
    DIRECTION INPUT ;
    USE SIGNAL ;
    PORT
      LAYER M4 ;
        RECT  0 55.248 0.084 55.272 ;
    END
  END d[88]
  PIN d[89]
    DIRECTION INPUT ;
    USE SIGNAL ;
    PORT
      LAYER M4 ;
        RECT  0 55.344 0.084 55.368 ;
    END
  END d[89]
  PIN d[8]
    DIRECTION INPUT ;
    USE SIGNAL ;
    PORT
      LAYER M4 ;
        RECT  0 62.928 0.084 62.952 ;
    END
  END d[8]
  PIN d[90]
    DIRECTION INPUT ;
    USE SIGNAL ;
    PORT
      LAYER M4 ;
        RECT  0 55.44 0.084 55.464 ;
    END
  END d[90]
  PIN d[91]
    DIRECTION INPUT ;
    USE SIGNAL ;
    PORT
      LAYER M4 ;
        RECT  0 55.536 0.084 55.56 ;
    END
  END d[91]
  PIN d[92]
    DIRECTION INPUT ;
    USE SIGNAL ;
    PORT
      LAYER M4 ;
        RECT  0 55.632 0.084 55.656 ;
    END
  END d[92]
  PIN d[93]
    DIRECTION INPUT ;
    USE SIGNAL ;
    PORT
      LAYER M4 ;
        RECT  0 55.728 0.084 55.752 ;
    END
  END d[93]
  PIN d[94]
    DIRECTION INPUT ;
    USE SIGNAL ;
    PORT
      LAYER M4 ;
        RECT  0 55.824 0.084 55.848 ;
    END
  END d[94]
  PIN d[95]
    DIRECTION INPUT ;
    USE SIGNAL ;
    PORT
      LAYER M4 ;
        RECT  0 68.208 0.084 68.232 ;
    END
  END d[95]
  PIN d[96]
    DIRECTION INPUT ;
    USE SIGNAL ;
    PORT
      LAYER M4 ;
        RECT  0 68.304 0.084 68.328 ;
    END
  END d[96]
  PIN d[97]
    DIRECTION INPUT ;
    USE SIGNAL ;
    PORT
      LAYER M4 ;
        RECT  0 68.4 0.084 68.424 ;
    END
  END d[97]
  PIN d[98]
    DIRECTION INPUT ;
    USE SIGNAL ;
    PORT
      LAYER M4 ;
        RECT  0 68.496 0.084 68.52 ;
    END
  END d[98]
  PIN d[99]
    DIRECTION INPUT ;
    USE SIGNAL ;
    PORT
      LAYER M4 ;
        RECT  0 68.592 0.084 68.616 ;
    END
  END d[99]
  PIN d[9]
    DIRECTION INPUT ;
    USE SIGNAL ;
    PORT
      LAYER M4 ;
        RECT  0 63.024 0.084 63.048 ;
    END
  END d[9]
  PIN q[0]
    DIRECTION OUTPUT ;
    USE SIGNAL ;
    PORT
      LAYER M4 ;
        RECT  21.516 73.68 21.6 73.704 ;
    END
  END q[0]
  PIN q[100]
    DIRECTION OUTPUT ;
    USE SIGNAL ;
    PORT
      LAYER M4 ;
        RECT  21.516 70.992 21.6 71.016 ;
    END
  END q[100]
  PIN q[101]
    DIRECTION OUTPUT ;
    USE SIGNAL ;
    PORT
      LAYER M4 ;
        RECT  21.516 71.088 21.6 71.112 ;
    END
  END q[101]
  PIN q[102]
    DIRECTION OUTPUT ;
    USE SIGNAL ;
    PORT
      LAYER M4 ;
        RECT  21.516 71.184 21.6 71.208 ;
    END
  END q[102]
  PIN q[103]
    DIRECTION OUTPUT ;
    USE SIGNAL ;
    PORT
      LAYER M4 ;
        RECT  21.516 71.28 21.6 71.304 ;
    END
  END q[103]
  PIN q[104]
    DIRECTION OUTPUT ;
    USE SIGNAL ;
    PORT
      LAYER M4 ;
        RECT  21.516 71.376 21.6 71.4 ;
    END
  END q[104]
  PIN q[105]
    DIRECTION OUTPUT ;
    USE SIGNAL ;
    PORT
      LAYER M4 ;
        RECT  21.516 71.472 21.6 71.496 ;
    END
  END q[105]
  PIN q[106]
    DIRECTION OUTPUT ;
    USE SIGNAL ;
    PORT
      LAYER M4 ;
        RECT  21.516 71.568 21.6 71.592 ;
    END
  END q[106]
  PIN q[107]
    DIRECTION OUTPUT ;
    USE SIGNAL ;
    PORT
      LAYER M4 ;
        RECT  21.516 71.664 21.6 71.688 ;
    END
  END q[107]
  PIN q[108]
    DIRECTION OUTPUT ;
    USE SIGNAL ;
    PORT
      LAYER M4 ;
        RECT  21.516 71.76 21.6 71.784 ;
    END
  END q[108]
  PIN q[109]
    DIRECTION OUTPUT ;
    USE SIGNAL ;
    PORT
      LAYER M4 ;
        RECT  21.516 71.856 21.6 71.88 ;
    END
  END q[109]
  PIN q[10]
    DIRECTION OUTPUT ;
    USE SIGNAL ;
    PORT
      LAYER M4 ;
        RECT  21.516 74.64 21.6 74.664 ;
    END
  END q[10]
  PIN q[110]
    DIRECTION OUTPUT ;
    USE SIGNAL ;
    PORT
      LAYER M4 ;
        RECT  21.516 71.952 21.6 71.976 ;
    END
  END q[110]
  PIN q[111]
    DIRECTION OUTPUT ;
    USE SIGNAL ;
    PORT
      LAYER M4 ;
        RECT  21.516 72.048 21.6 72.072 ;
    END
  END q[111]
  PIN q[112]
    DIRECTION OUTPUT ;
    USE SIGNAL ;
    PORT
      LAYER M4 ;
        RECT  21.516 72.144 21.6 72.168 ;
    END
  END q[112]
  PIN q[113]
    DIRECTION OUTPUT ;
    USE SIGNAL ;
    PORT
      LAYER M4 ;
        RECT  21.516 72.24 21.6 72.264 ;
    END
  END q[113]
  PIN q[114]
    DIRECTION OUTPUT ;
    USE SIGNAL ;
    PORT
      LAYER M4 ;
        RECT  21.516 72.336 21.6 72.36 ;
    END
  END q[114]
  PIN q[115]
    DIRECTION OUTPUT ;
    USE SIGNAL ;
    PORT
      LAYER M4 ;
        RECT  21.516 72.432 21.6 72.456 ;
    END
  END q[115]
  PIN q[116]
    DIRECTION OUTPUT ;
    USE SIGNAL ;
    PORT
      LAYER M4 ;
        RECT  21.516 72.528 21.6 72.552 ;
    END
  END q[116]
  PIN q[117]
    DIRECTION OUTPUT ;
    USE SIGNAL ;
    PORT
      LAYER M4 ;
        RECT  21.516 72.624 21.6 72.648 ;
    END
  END q[117]
  PIN q[118]
    DIRECTION OUTPUT ;
    USE SIGNAL ;
    PORT
      LAYER M4 ;
        RECT  21.516 72.72 21.6 72.744 ;
    END
  END q[118]
  PIN q[119]
    DIRECTION OUTPUT ;
    USE SIGNAL ;
    PORT
      LAYER M4 ;
        RECT  21.516 72.816 21.6 72.84 ;
    END
  END q[119]
  PIN q[11]
    DIRECTION OUTPUT ;
    USE SIGNAL ;
    PORT
      LAYER M4 ;
        RECT  21.516 74.736 21.6 74.76 ;
    END
  END q[11]
  PIN q[120]
    DIRECTION OUTPUT ;
    USE SIGNAL ;
    PORT
      LAYER M4 ;
        RECT  21.516 72.912 21.6 72.936 ;
    END
  END q[120]
  PIN q[121]
    DIRECTION OUTPUT ;
    USE SIGNAL ;
    PORT
      LAYER M4 ;
        RECT  21.516 73.008 21.6 73.032 ;
    END
  END q[121]
  PIN q[122]
    DIRECTION OUTPUT ;
    USE SIGNAL ;
    PORT
      LAYER M4 ;
        RECT  21.516 73.104 21.6 73.128 ;
    END
  END q[122]
  PIN q[123]
    DIRECTION OUTPUT ;
    USE SIGNAL ;
    PORT
      LAYER M4 ;
        RECT  21.516 73.2 21.6 73.224 ;
    END
  END q[123]
  PIN q[124]
    DIRECTION OUTPUT ;
    USE SIGNAL ;
    PORT
      LAYER M4 ;
        RECT  21.516 73.296 21.6 73.32 ;
    END
  END q[124]
  PIN q[125]
    DIRECTION OUTPUT ;
    USE SIGNAL ;
    PORT
      LAYER M4 ;
        RECT  21.516 73.392 21.6 73.416 ;
    END
  END q[125]
  PIN q[126]
    DIRECTION OUTPUT ;
    USE SIGNAL ;
    PORT
      LAYER M4 ;
        RECT  21.516 73.488 21.6 73.512 ;
    END
  END q[126]
  PIN q[127]
    DIRECTION OUTPUT ;
    USE SIGNAL ;
    PORT
      LAYER M4 ;
        RECT  21.516 73.584 21.6 73.608 ;
    END
  END q[127]
  PIN q[128]
    DIRECTION OUTPUT ;
    USE SIGNAL ;
    PORT
      LAYER M4 ;
        RECT  21.516 58.32 21.6 58.344 ;
    END
  END q[128]
  PIN q[129]
    DIRECTION OUTPUT ;
    USE SIGNAL ;
    PORT
      LAYER M4 ;
        RECT  21.516 58.416 21.6 58.44 ;
    END
  END q[129]
  PIN q[12]
    DIRECTION OUTPUT ;
    USE SIGNAL ;
    PORT
      LAYER M4 ;
        RECT  21.516 74.832 21.6 74.856 ;
    END
  END q[12]
  PIN q[130]
    DIRECTION OUTPUT ;
    USE SIGNAL ;
    PORT
      LAYER M4 ;
        RECT  21.516 58.512 21.6 58.536 ;
    END
  END q[130]
  PIN q[131]
    DIRECTION OUTPUT ;
    USE SIGNAL ;
    PORT
      LAYER M4 ;
        RECT  21.516 58.608 21.6 58.632 ;
    END
  END q[131]
  PIN q[132]
    DIRECTION OUTPUT ;
    USE SIGNAL ;
    PORT
      LAYER M4 ;
        RECT  21.516 58.704 21.6 58.728 ;
    END
  END q[132]
  PIN q[133]
    DIRECTION OUTPUT ;
    USE SIGNAL ;
    PORT
      LAYER M4 ;
        RECT  21.516 58.8 21.6 58.824 ;
    END
  END q[133]
  PIN q[134]
    DIRECTION OUTPUT ;
    USE SIGNAL ;
    PORT
      LAYER M4 ;
        RECT  21.516 58.896 21.6 58.92 ;
    END
  END q[134]
  PIN q[135]
    DIRECTION OUTPUT ;
    USE SIGNAL ;
    PORT
      LAYER M4 ;
        RECT  21.516 58.992 21.6 59.016 ;
    END
  END q[135]
  PIN q[136]
    DIRECTION OUTPUT ;
    USE SIGNAL ;
    PORT
      LAYER M4 ;
        RECT  21.516 59.088 21.6 59.112 ;
    END
  END q[136]
  PIN q[137]
    DIRECTION OUTPUT ;
    USE SIGNAL ;
    PORT
      LAYER M4 ;
        RECT  21.516 59.184 21.6 59.208 ;
    END
  END q[137]
  PIN q[138]
    DIRECTION OUTPUT ;
    USE SIGNAL ;
    PORT
      LAYER M4 ;
        RECT  21.516 59.28 21.6 59.304 ;
    END
  END q[138]
  PIN q[139]
    DIRECTION OUTPUT ;
    USE SIGNAL ;
    PORT
      LAYER M4 ;
        RECT  21.516 59.376 21.6 59.4 ;
    END
  END q[139]
  PIN q[13]
    DIRECTION OUTPUT ;
    USE SIGNAL ;
    PORT
      LAYER M4 ;
        RECT  21.516 74.928 21.6 74.952 ;
    END
  END q[13]
  PIN q[140]
    DIRECTION OUTPUT ;
    USE SIGNAL ;
    PORT
      LAYER M4 ;
        RECT  21.516 59.472 21.6 59.496 ;
    END
  END q[140]
  PIN q[141]
    DIRECTION OUTPUT ;
    USE SIGNAL ;
    PORT
      LAYER M4 ;
        RECT  21.516 59.568 21.6 59.592 ;
    END
  END q[141]
  PIN q[142]
    DIRECTION OUTPUT ;
    USE SIGNAL ;
    PORT
      LAYER M4 ;
        RECT  21.516 59.664 21.6 59.688 ;
    END
  END q[142]
  PIN q[143]
    DIRECTION OUTPUT ;
    USE SIGNAL ;
    PORT
      LAYER M4 ;
        RECT  21.516 59.76 21.6 59.784 ;
    END
  END q[143]
  PIN q[144]
    DIRECTION OUTPUT ;
    USE SIGNAL ;
    PORT
      LAYER M4 ;
        RECT  21.516 59.856 21.6 59.88 ;
    END
  END q[144]
  PIN q[145]
    DIRECTION OUTPUT ;
    USE SIGNAL ;
    PORT
      LAYER M4 ;
        RECT  21.516 59.952 21.6 59.976 ;
    END
  END q[145]
  PIN q[146]
    DIRECTION OUTPUT ;
    USE SIGNAL ;
    PORT
      LAYER M4 ;
        RECT  21.516 60.048 21.6 60.072 ;
    END
  END q[146]
  PIN q[147]
    DIRECTION OUTPUT ;
    USE SIGNAL ;
    PORT
      LAYER M4 ;
        RECT  21.516 60.144 21.6 60.168 ;
    END
  END q[147]
  PIN q[148]
    DIRECTION OUTPUT ;
    USE SIGNAL ;
    PORT
      LAYER M4 ;
        RECT  21.516 60.24 21.6 60.264 ;
    END
  END q[148]
  PIN q[149]
    DIRECTION OUTPUT ;
    USE SIGNAL ;
    PORT
      LAYER M4 ;
        RECT  21.516 60.336 21.6 60.36 ;
    END
  END q[149]
  PIN q[14]
    DIRECTION OUTPUT ;
    USE SIGNAL ;
    PORT
      LAYER M4 ;
        RECT  21.516 75.024 21.6 75.048 ;
    END
  END q[14]
  PIN q[150]
    DIRECTION OUTPUT ;
    USE SIGNAL ;
    PORT
      LAYER M4 ;
        RECT  21.516 60.432 21.6 60.456 ;
    END
  END q[150]
  PIN q[151]
    DIRECTION OUTPUT ;
    USE SIGNAL ;
    PORT
      LAYER M4 ;
        RECT  21.516 60.528 21.6 60.552 ;
    END
  END q[151]
  PIN q[152]
    DIRECTION OUTPUT ;
    USE SIGNAL ;
    PORT
      LAYER M4 ;
        RECT  21.516 60.624 21.6 60.648 ;
    END
  END q[152]
  PIN q[153]
    DIRECTION OUTPUT ;
    USE SIGNAL ;
    PORT
      LAYER M4 ;
        RECT  21.516 60.72 21.6 60.744 ;
    END
  END q[153]
  PIN q[154]
    DIRECTION OUTPUT ;
    USE SIGNAL ;
    PORT
      LAYER M4 ;
        RECT  21.516 60.816 21.6 60.84 ;
    END
  END q[154]
  PIN q[155]
    DIRECTION OUTPUT ;
    USE SIGNAL ;
    PORT
      LAYER M4 ;
        RECT  21.516 60.912 21.6 60.936 ;
    END
  END q[155]
  PIN q[156]
    DIRECTION OUTPUT ;
    USE SIGNAL ;
    PORT
      LAYER M4 ;
        RECT  21.516 61.008 21.6 61.032 ;
    END
  END q[156]
  PIN q[157]
    DIRECTION OUTPUT ;
    USE SIGNAL ;
    PORT
      LAYER M4 ;
        RECT  21.516 61.104 21.6 61.128 ;
    END
  END q[157]
  PIN q[158]
    DIRECTION OUTPUT ;
    USE SIGNAL ;
    PORT
      LAYER M4 ;
        RECT  21.516 61.2 21.6 61.224 ;
    END
  END q[158]
  PIN q[159]
    DIRECTION OUTPUT ;
    USE SIGNAL ;
    PORT
      LAYER M4 ;
        RECT  21.516 61.296 21.6 61.32 ;
    END
  END q[159]
  PIN q[15]
    DIRECTION OUTPUT ;
    USE SIGNAL ;
    PORT
      LAYER M4 ;
        RECT  21.516 75.12 21.6 75.144 ;
    END
  END q[15]
  PIN q[160]
    DIRECTION OUTPUT ;
    USE SIGNAL ;
    PORT
      LAYER M4 ;
        RECT  21.516 61.392 21.6 61.416 ;
    END
  END q[160]
  PIN q[161]
    DIRECTION OUTPUT ;
    USE SIGNAL ;
    PORT
      LAYER M4 ;
        RECT  21.516 61.488 21.6 61.512 ;
    END
  END q[161]
  PIN q[162]
    DIRECTION OUTPUT ;
    USE SIGNAL ;
    PORT
      LAYER M4 ;
        RECT  21.516 61.584 21.6 61.608 ;
    END
  END q[162]
  PIN q[163]
    DIRECTION OUTPUT ;
    USE SIGNAL ;
    PORT
      LAYER M4 ;
        RECT  21.516 61.68 21.6 61.704 ;
    END
  END q[163]
  PIN q[164]
    DIRECTION OUTPUT ;
    USE SIGNAL ;
    PORT
      LAYER M4 ;
        RECT  21.516 61.776 21.6 61.8 ;
    END
  END q[164]
  PIN q[165]
    DIRECTION OUTPUT ;
    USE SIGNAL ;
    PORT
      LAYER M4 ;
        RECT  21.516 61.872 21.6 61.896 ;
    END
  END q[165]
  PIN q[166]
    DIRECTION OUTPUT ;
    USE SIGNAL ;
    PORT
      LAYER M4 ;
        RECT  21.516 61.968 21.6 61.992 ;
    END
  END q[166]
  PIN q[167]
    DIRECTION OUTPUT ;
    USE SIGNAL ;
    PORT
      LAYER M4 ;
        RECT  21.516 62.064 21.6 62.088 ;
    END
  END q[167]
  PIN q[168]
    DIRECTION OUTPUT ;
    USE SIGNAL ;
    PORT
      LAYER M4 ;
        RECT  21.516 62.16 21.6 62.184 ;
    END
  END q[168]
  PIN q[169]
    DIRECTION OUTPUT ;
    USE SIGNAL ;
    PORT
      LAYER M4 ;
        RECT  21.516 62.256 21.6 62.28 ;
    END
  END q[169]
  PIN q[16]
    DIRECTION OUTPUT ;
    USE SIGNAL ;
    PORT
      LAYER M4 ;
        RECT  21.516 75.216 21.6 75.24 ;
    END
  END q[16]
  PIN q[170]
    DIRECTION OUTPUT ;
    USE SIGNAL ;
    PORT
      LAYER M4 ;
        RECT  21.516 62.352 21.6 62.376 ;
    END
  END q[170]
  PIN q[171]
    DIRECTION OUTPUT ;
    USE SIGNAL ;
    PORT
      LAYER M4 ;
        RECT  21.516 62.448 21.6 62.472 ;
    END
  END q[171]
  PIN q[172]
    DIRECTION OUTPUT ;
    USE SIGNAL ;
    PORT
      LAYER M4 ;
        RECT  21.516 62.544 21.6 62.568 ;
    END
  END q[172]
  PIN q[173]
    DIRECTION OUTPUT ;
    USE SIGNAL ;
    PORT
      LAYER M4 ;
        RECT  21.516 62.64 21.6 62.664 ;
    END
  END q[173]
  PIN q[174]
    DIRECTION OUTPUT ;
    USE SIGNAL ;
    PORT
      LAYER M4 ;
        RECT  21.516 62.736 21.6 62.76 ;
    END
  END q[174]
  PIN q[175]
    DIRECTION OUTPUT ;
    USE SIGNAL ;
    PORT
      LAYER M4 ;
        RECT  21.516 62.832 21.6 62.856 ;
    END
  END q[175]
  PIN q[176]
    DIRECTION OUTPUT ;
    USE SIGNAL ;
    PORT
      LAYER M4 ;
        RECT  21.516 62.928 21.6 62.952 ;
    END
  END q[176]
  PIN q[177]
    DIRECTION OUTPUT ;
    USE SIGNAL ;
    PORT
      LAYER M4 ;
        RECT  21.516 63.024 21.6 63.048 ;
    END
  END q[177]
  PIN q[178]
    DIRECTION OUTPUT ;
    USE SIGNAL ;
    PORT
      LAYER M4 ;
        RECT  21.516 63.12 21.6 63.144 ;
    END
  END q[178]
  PIN q[179]
    DIRECTION OUTPUT ;
    USE SIGNAL ;
    PORT
      LAYER M4 ;
        RECT  21.516 63.216 21.6 63.24 ;
    END
  END q[179]
  PIN q[17]
    DIRECTION OUTPUT ;
    USE SIGNAL ;
    PORT
      LAYER M4 ;
        RECT  21.516 75.312 21.6 75.336 ;
    END
  END q[17]
  PIN q[180]
    DIRECTION OUTPUT ;
    USE SIGNAL ;
    PORT
      LAYER M4 ;
        RECT  21.516 63.312 21.6 63.336 ;
    END
  END q[180]
  PIN q[181]
    DIRECTION OUTPUT ;
    USE SIGNAL ;
    PORT
      LAYER M4 ;
        RECT  21.516 63.408 21.6 63.432 ;
    END
  END q[181]
  PIN q[182]
    DIRECTION OUTPUT ;
    USE SIGNAL ;
    PORT
      LAYER M4 ;
        RECT  21.516 63.504 21.6 63.528 ;
    END
  END q[182]
  PIN q[183]
    DIRECTION OUTPUT ;
    USE SIGNAL ;
    PORT
      LAYER M4 ;
        RECT  21.516 63.6 21.6 63.624 ;
    END
  END q[183]
  PIN q[184]
    DIRECTION OUTPUT ;
    USE SIGNAL ;
    PORT
      LAYER M4 ;
        RECT  21.516 63.696 21.6 63.72 ;
    END
  END q[184]
  PIN q[185]
    DIRECTION OUTPUT ;
    USE SIGNAL ;
    PORT
      LAYER M4 ;
        RECT  21.516 63.792 21.6 63.816 ;
    END
  END q[185]
  PIN q[186]
    DIRECTION OUTPUT ;
    USE SIGNAL ;
    PORT
      LAYER M4 ;
        RECT  21.516 63.888 21.6 63.912 ;
    END
  END q[186]
  PIN q[187]
    DIRECTION OUTPUT ;
    USE SIGNAL ;
    PORT
      LAYER M4 ;
        RECT  21.516 63.984 21.6 64.008 ;
    END
  END q[187]
  PIN q[188]
    DIRECTION OUTPUT ;
    USE SIGNAL ;
    PORT
      LAYER M4 ;
        RECT  21.516 64.08 21.6 64.104 ;
    END
  END q[188]
  PIN q[189]
    DIRECTION OUTPUT ;
    USE SIGNAL ;
    PORT
      LAYER M4 ;
        RECT  21.516 64.176 21.6 64.2 ;
    END
  END q[189]
  PIN q[18]
    DIRECTION OUTPUT ;
    USE SIGNAL ;
    PORT
      LAYER M4 ;
        RECT  21.516 75.408 21.6 75.432 ;
    END
  END q[18]
  PIN q[190]
    DIRECTION OUTPUT ;
    USE SIGNAL ;
    PORT
      LAYER M4 ;
        RECT  21.516 64.272 21.6 64.296 ;
    END
  END q[190]
  PIN q[191]
    DIRECTION OUTPUT ;
    USE SIGNAL ;
    PORT
      LAYER M4 ;
        RECT  21.516 64.368 21.6 64.392 ;
    END
  END q[191]
  PIN q[192]
    DIRECTION OUTPUT ;
    USE SIGNAL ;
    PORT
      LAYER M4 ;
        RECT  21.516 39.12 21.6 39.144 ;
    END
  END q[192]
  PIN q[193]
    DIRECTION OUTPUT ;
    USE SIGNAL ;
    PORT
      LAYER M4 ;
        RECT  21.516 39.216 21.6 39.24 ;
    END
  END q[193]
  PIN q[194]
    DIRECTION OUTPUT ;
    USE SIGNAL ;
    PORT
      LAYER M4 ;
        RECT  21.516 39.312 21.6 39.336 ;
    END
  END q[194]
  PIN q[195]
    DIRECTION OUTPUT ;
    USE SIGNAL ;
    PORT
      LAYER M4 ;
        RECT  21.516 39.408 21.6 39.432 ;
    END
  END q[195]
  PIN q[196]
    DIRECTION OUTPUT ;
    USE SIGNAL ;
    PORT
      LAYER M4 ;
        RECT  21.516 39.504 21.6 39.528 ;
    END
  END q[196]
  PIN q[197]
    DIRECTION OUTPUT ;
    USE SIGNAL ;
    PORT
      LAYER M4 ;
        RECT  21.516 39.6 21.6 39.624 ;
    END
  END q[197]
  PIN q[198]
    DIRECTION OUTPUT ;
    USE SIGNAL ;
    PORT
      LAYER M4 ;
        RECT  21.516 39.696 21.6 39.72 ;
    END
  END q[198]
  PIN q[199]
    DIRECTION OUTPUT ;
    USE SIGNAL ;
    PORT
      LAYER M4 ;
        RECT  21.516 39.792 21.6 39.816 ;
    END
  END q[199]
  PIN q[19]
    DIRECTION OUTPUT ;
    USE SIGNAL ;
    PORT
      LAYER M4 ;
        RECT  21.516 75.504 21.6 75.528 ;
    END
  END q[19]
  PIN q[1]
    DIRECTION OUTPUT ;
    USE SIGNAL ;
    PORT
      LAYER M4 ;
        RECT  21.516 73.776 21.6 73.8 ;
    END
  END q[1]
  PIN q[200]
    DIRECTION OUTPUT ;
    USE SIGNAL ;
    PORT
      LAYER M4 ;
        RECT  21.516 39.888 21.6 39.912 ;
    END
  END q[200]
  PIN q[201]
    DIRECTION OUTPUT ;
    USE SIGNAL ;
    PORT
      LAYER M4 ;
        RECT  21.516 39.984 21.6 40.008 ;
    END
  END q[201]
  PIN q[202]
    DIRECTION OUTPUT ;
    USE SIGNAL ;
    PORT
      LAYER M4 ;
        RECT  21.516 40.08 21.6 40.104 ;
    END
  END q[202]
  PIN q[203]
    DIRECTION OUTPUT ;
    USE SIGNAL ;
    PORT
      LAYER M4 ;
        RECT  21.516 40.176 21.6 40.2 ;
    END
  END q[203]
  PIN q[204]
    DIRECTION OUTPUT ;
    USE SIGNAL ;
    PORT
      LAYER M4 ;
        RECT  21.516 40.272 21.6 40.296 ;
    END
  END q[204]
  PIN q[205]
    DIRECTION OUTPUT ;
    USE SIGNAL ;
    PORT
      LAYER M4 ;
        RECT  21.516 40.368 21.6 40.392 ;
    END
  END q[205]
  PIN q[206]
    DIRECTION OUTPUT ;
    USE SIGNAL ;
    PORT
      LAYER M4 ;
        RECT  21.516 40.464 21.6 40.488 ;
    END
  END q[206]
  PIN q[207]
    DIRECTION OUTPUT ;
    USE SIGNAL ;
    PORT
      LAYER M4 ;
        RECT  21.516 40.56 21.6 40.584 ;
    END
  END q[207]
  PIN q[208]
    DIRECTION OUTPUT ;
    USE SIGNAL ;
    PORT
      LAYER M4 ;
        RECT  21.516 40.656 21.6 40.68 ;
    END
  END q[208]
  PIN q[209]
    DIRECTION OUTPUT ;
    USE SIGNAL ;
    PORT
      LAYER M4 ;
        RECT  21.516 40.752 21.6 40.776 ;
    END
  END q[209]
  PIN q[20]
    DIRECTION OUTPUT ;
    USE SIGNAL ;
    PORT
      LAYER M4 ;
        RECT  21.516 75.6 21.6 75.624 ;
    END
  END q[20]
  PIN q[210]
    DIRECTION OUTPUT ;
    USE SIGNAL ;
    PORT
      LAYER M4 ;
        RECT  21.516 40.848 21.6 40.872 ;
    END
  END q[210]
  PIN q[211]
    DIRECTION OUTPUT ;
    USE SIGNAL ;
    PORT
      LAYER M4 ;
        RECT  21.516 40.944 21.6 40.968 ;
    END
  END q[211]
  PIN q[212]
    DIRECTION OUTPUT ;
    USE SIGNAL ;
    PORT
      LAYER M4 ;
        RECT  21.516 41.04 21.6 41.064 ;
    END
  END q[212]
  PIN q[213]
    DIRECTION OUTPUT ;
    USE SIGNAL ;
    PORT
      LAYER M4 ;
        RECT  21.516 41.136 21.6 41.16 ;
    END
  END q[213]
  PIN q[214]
    DIRECTION OUTPUT ;
    USE SIGNAL ;
    PORT
      LAYER M4 ;
        RECT  21.516 41.232 21.6 41.256 ;
    END
  END q[214]
  PIN q[215]
    DIRECTION OUTPUT ;
    USE SIGNAL ;
    PORT
      LAYER M4 ;
        RECT  21.516 41.328 21.6 41.352 ;
    END
  END q[215]
  PIN q[216]
    DIRECTION OUTPUT ;
    USE SIGNAL ;
    PORT
      LAYER M4 ;
        RECT  21.516 41.424 21.6 41.448 ;
    END
  END q[216]
  PIN q[217]
    DIRECTION OUTPUT ;
    USE SIGNAL ;
    PORT
      LAYER M4 ;
        RECT  21.516 41.52 21.6 41.544 ;
    END
  END q[217]
  PIN q[218]
    DIRECTION OUTPUT ;
    USE SIGNAL ;
    PORT
      LAYER M4 ;
        RECT  21.516 41.616 21.6 41.64 ;
    END
  END q[218]
  PIN q[219]
    DIRECTION OUTPUT ;
    USE SIGNAL ;
    PORT
      LAYER M4 ;
        RECT  21.516 41.712 21.6 41.736 ;
    END
  END q[219]
  PIN q[21]
    DIRECTION OUTPUT ;
    USE SIGNAL ;
    PORT
      LAYER M4 ;
        RECT  21.516 75.696 21.6 75.72 ;
    END
  END q[21]
  PIN q[220]
    DIRECTION OUTPUT ;
    USE SIGNAL ;
    PORT
      LAYER M4 ;
        RECT  21.516 41.808 21.6 41.832 ;
    END
  END q[220]
  PIN q[221]
    DIRECTION OUTPUT ;
    USE SIGNAL ;
    PORT
      LAYER M4 ;
        RECT  21.516 41.904 21.6 41.928 ;
    END
  END q[221]
  PIN q[222]
    DIRECTION OUTPUT ;
    USE SIGNAL ;
    PORT
      LAYER M4 ;
        RECT  21.516 42 21.6 42.024 ;
    END
  END q[222]
  PIN q[223]
    DIRECTION OUTPUT ;
    USE SIGNAL ;
    PORT
      LAYER M4 ;
        RECT  21.516 42.096 21.6 42.12 ;
    END
  END q[223]
  PIN q[224]
    DIRECTION OUTPUT ;
    USE SIGNAL ;
    PORT
      LAYER M4 ;
        RECT  21.516 51.408 21.6 51.432 ;
    END
  END q[224]
  PIN q[225]
    DIRECTION OUTPUT ;
    USE SIGNAL ;
    PORT
      LAYER M4 ;
        RECT  21.516 51.504 21.6 51.528 ;
    END
  END q[225]
  PIN q[226]
    DIRECTION OUTPUT ;
    USE SIGNAL ;
    PORT
      LAYER M4 ;
        RECT  21.516 51.6 21.6 51.624 ;
    END
  END q[226]
  PIN q[227]
    DIRECTION OUTPUT ;
    USE SIGNAL ;
    PORT
      LAYER M4 ;
        RECT  21.516 51.696 21.6 51.72 ;
    END
  END q[227]
  PIN q[228]
    DIRECTION OUTPUT ;
    USE SIGNAL ;
    PORT
      LAYER M4 ;
        RECT  21.516 51.792 21.6 51.816 ;
    END
  END q[228]
  PIN q[229]
    DIRECTION OUTPUT ;
    USE SIGNAL ;
    PORT
      LAYER M4 ;
        RECT  21.516 51.888 21.6 51.912 ;
    END
  END q[229]
  PIN q[22]
    DIRECTION OUTPUT ;
    USE SIGNAL ;
    PORT
      LAYER M4 ;
        RECT  21.516 75.792 21.6 75.816 ;
    END
  END q[22]
  PIN q[230]
    DIRECTION OUTPUT ;
    USE SIGNAL ;
    PORT
      LAYER M4 ;
        RECT  21.516 51.984 21.6 52.008 ;
    END
  END q[230]
  PIN q[231]
    DIRECTION OUTPUT ;
    USE SIGNAL ;
    PORT
      LAYER M4 ;
        RECT  21.516 52.08 21.6 52.104 ;
    END
  END q[231]
  PIN q[232]
    DIRECTION OUTPUT ;
    USE SIGNAL ;
    PORT
      LAYER M4 ;
        RECT  21.516 52.176 21.6 52.2 ;
    END
  END q[232]
  PIN q[233]
    DIRECTION OUTPUT ;
    USE SIGNAL ;
    PORT
      LAYER M4 ;
        RECT  21.516 52.272 21.6 52.296 ;
    END
  END q[233]
  PIN q[234]
    DIRECTION OUTPUT ;
    USE SIGNAL ;
    PORT
      LAYER M4 ;
        RECT  21.516 52.368 21.6 52.392 ;
    END
  END q[234]
  PIN q[235]
    DIRECTION OUTPUT ;
    USE SIGNAL ;
    PORT
      LAYER M4 ;
        RECT  21.516 52.464 21.6 52.488 ;
    END
  END q[235]
  PIN q[236]
    DIRECTION OUTPUT ;
    USE SIGNAL ;
    PORT
      LAYER M4 ;
        RECT  21.516 52.56 21.6 52.584 ;
    END
  END q[236]
  PIN q[237]
    DIRECTION OUTPUT ;
    USE SIGNAL ;
    PORT
      LAYER M4 ;
        RECT  21.516 52.656 21.6 52.68 ;
    END
  END q[237]
  PIN q[238]
    DIRECTION OUTPUT ;
    USE SIGNAL ;
    PORT
      LAYER M4 ;
        RECT  21.516 52.752 21.6 52.776 ;
    END
  END q[238]
  PIN q[239]
    DIRECTION OUTPUT ;
    USE SIGNAL ;
    PORT
      LAYER M4 ;
        RECT  21.516 52.848 21.6 52.872 ;
    END
  END q[239]
  PIN q[23]
    DIRECTION OUTPUT ;
    USE SIGNAL ;
    PORT
      LAYER M4 ;
        RECT  21.516 75.888 21.6 75.912 ;
    END
  END q[23]
  PIN q[240]
    DIRECTION OUTPUT ;
    USE SIGNAL ;
    PORT
      LAYER M4 ;
        RECT  21.516 52.944 21.6 52.968 ;
    END
  END q[240]
  PIN q[241]
    DIRECTION OUTPUT ;
    USE SIGNAL ;
    PORT
      LAYER M4 ;
        RECT  21.516 53.04 21.6 53.064 ;
    END
  END q[241]
  PIN q[242]
    DIRECTION OUTPUT ;
    USE SIGNAL ;
    PORT
      LAYER M4 ;
        RECT  21.516 53.136 21.6 53.16 ;
    END
  END q[242]
  PIN q[243]
    DIRECTION OUTPUT ;
    USE SIGNAL ;
    PORT
      LAYER M4 ;
        RECT  21.516 53.232 21.6 53.256 ;
    END
  END q[243]
  PIN q[244]
    DIRECTION OUTPUT ;
    USE SIGNAL ;
    PORT
      LAYER M4 ;
        RECT  21.516 53.328 21.6 53.352 ;
    END
  END q[244]
  PIN q[245]
    DIRECTION OUTPUT ;
    USE SIGNAL ;
    PORT
      LAYER M4 ;
        RECT  21.516 53.424 21.6 53.448 ;
    END
  END q[245]
  PIN q[246]
    DIRECTION OUTPUT ;
    USE SIGNAL ;
    PORT
      LAYER M4 ;
        RECT  21.516 53.52 21.6 53.544 ;
    END
  END q[246]
  PIN q[247]
    DIRECTION OUTPUT ;
    USE SIGNAL ;
    PORT
      LAYER M4 ;
        RECT  21.516 53.616 21.6 53.64 ;
    END
  END q[247]
  PIN q[248]
    DIRECTION OUTPUT ;
    USE SIGNAL ;
    PORT
      LAYER M4 ;
        RECT  21.516 53.712 21.6 53.736 ;
    END
  END q[248]
  PIN q[249]
    DIRECTION OUTPUT ;
    USE SIGNAL ;
    PORT
      LAYER M4 ;
        RECT  21.516 53.808 21.6 53.832 ;
    END
  END q[249]
  PIN q[24]
    DIRECTION OUTPUT ;
    USE SIGNAL ;
    PORT
      LAYER M4 ;
        RECT  21.516 75.984 21.6 76.008 ;
    END
  END q[24]
  PIN q[250]
    DIRECTION OUTPUT ;
    USE SIGNAL ;
    PORT
      LAYER M4 ;
        RECT  21.516 53.904 21.6 53.928 ;
    END
  END q[250]
  PIN q[251]
    DIRECTION OUTPUT ;
    USE SIGNAL ;
    PORT
      LAYER M4 ;
        RECT  21.516 54 21.6 54.024 ;
    END
  END q[251]
  PIN q[252]
    DIRECTION OUTPUT ;
    USE SIGNAL ;
    PORT
      LAYER M4 ;
        RECT  21.516 54.096 21.6 54.12 ;
    END
  END q[252]
  PIN q[253]
    DIRECTION OUTPUT ;
    USE SIGNAL ;
    PORT
      LAYER M4 ;
        RECT  21.516 54.192 21.6 54.216 ;
    END
  END q[253]
  PIN q[254]
    DIRECTION OUTPUT ;
    USE SIGNAL ;
    PORT
      LAYER M4 ;
        RECT  21.516 54.288 21.6 54.312 ;
    END
  END q[254]
  PIN q[255]
    DIRECTION OUTPUT ;
    USE SIGNAL ;
    PORT
      LAYER M4 ;
        RECT  21.516 54.384 21.6 54.408 ;
    END
  END q[255]
  PIN q[256]
    DIRECTION OUTPUT ;
    USE SIGNAL ;
    PORT
      LAYER M4 ;
        RECT  21.516 42.192 21.6 42.216 ;
    END
  END q[256]
  PIN q[257]
    DIRECTION OUTPUT ;
    USE SIGNAL ;
    PORT
      LAYER M4 ;
        RECT  21.516 42.288 21.6 42.312 ;
    END
  END q[257]
  PIN q[258]
    DIRECTION OUTPUT ;
    USE SIGNAL ;
    PORT
      LAYER M4 ;
        RECT  21.516 42.384 21.6 42.408 ;
    END
  END q[258]
  PIN q[259]
    DIRECTION OUTPUT ;
    USE SIGNAL ;
    PORT
      LAYER M4 ;
        RECT  21.516 42.48 21.6 42.504 ;
    END
  END q[259]
  PIN q[25]
    DIRECTION OUTPUT ;
    USE SIGNAL ;
    PORT
      LAYER M4 ;
        RECT  21.516 76.08 21.6 76.104 ;
    END
  END q[25]
  PIN q[260]
    DIRECTION OUTPUT ;
    USE SIGNAL ;
    PORT
      LAYER M4 ;
        RECT  21.516 42.576 21.6 42.6 ;
    END
  END q[260]
  PIN q[261]
    DIRECTION OUTPUT ;
    USE SIGNAL ;
    PORT
      LAYER M4 ;
        RECT  21.516 42.672 21.6 42.696 ;
    END
  END q[261]
  PIN q[262]
    DIRECTION OUTPUT ;
    USE SIGNAL ;
    PORT
      LAYER M4 ;
        RECT  21.516 42.768 21.6 42.792 ;
    END
  END q[262]
  PIN q[263]
    DIRECTION OUTPUT ;
    USE SIGNAL ;
    PORT
      LAYER M4 ;
        RECT  21.516 42.864 21.6 42.888 ;
    END
  END q[263]
  PIN q[264]
    DIRECTION OUTPUT ;
    USE SIGNAL ;
    PORT
      LAYER M4 ;
        RECT  21.516 42.96 21.6 42.984 ;
    END
  END q[264]
  PIN q[265]
    DIRECTION OUTPUT ;
    USE SIGNAL ;
    PORT
      LAYER M4 ;
        RECT  21.516 43.056 21.6 43.08 ;
    END
  END q[265]
  PIN q[266]
    DIRECTION OUTPUT ;
    USE SIGNAL ;
    PORT
      LAYER M4 ;
        RECT  21.516 43.152 21.6 43.176 ;
    END
  END q[266]
  PIN q[267]
    DIRECTION OUTPUT ;
    USE SIGNAL ;
    PORT
      LAYER M4 ;
        RECT  21.516 43.248 21.6 43.272 ;
    END
  END q[267]
  PIN q[268]
    DIRECTION OUTPUT ;
    USE SIGNAL ;
    PORT
      LAYER M4 ;
        RECT  21.516 43.344 21.6 43.368 ;
    END
  END q[268]
  PIN q[269]
    DIRECTION OUTPUT ;
    USE SIGNAL ;
    PORT
      LAYER M4 ;
        RECT  21.516 43.44 21.6 43.464 ;
    END
  END q[269]
  PIN q[26]
    DIRECTION OUTPUT ;
    USE SIGNAL ;
    PORT
      LAYER M4 ;
        RECT  21.516 76.176 21.6 76.2 ;
    END
  END q[26]
  PIN q[270]
    DIRECTION OUTPUT ;
    USE SIGNAL ;
    PORT
      LAYER M4 ;
        RECT  21.516 43.536 21.6 43.56 ;
    END
  END q[270]
  PIN q[271]
    DIRECTION OUTPUT ;
    USE SIGNAL ;
    PORT
      LAYER M4 ;
        RECT  21.516 43.632 21.6 43.656 ;
    END
  END q[271]
  PIN q[272]
    DIRECTION OUTPUT ;
    USE SIGNAL ;
    PORT
      LAYER M4 ;
        RECT  21.516 43.728 21.6 43.752 ;
    END
  END q[272]
  PIN q[273]
    DIRECTION OUTPUT ;
    USE SIGNAL ;
    PORT
      LAYER M4 ;
        RECT  21.516 43.824 21.6 43.848 ;
    END
  END q[273]
  PIN q[274]
    DIRECTION OUTPUT ;
    USE SIGNAL ;
    PORT
      LAYER M4 ;
        RECT  21.516 43.92 21.6 43.944 ;
    END
  END q[274]
  PIN q[275]
    DIRECTION OUTPUT ;
    USE SIGNAL ;
    PORT
      LAYER M4 ;
        RECT  21.516 44.016 21.6 44.04 ;
    END
  END q[275]
  PIN q[276]
    DIRECTION OUTPUT ;
    USE SIGNAL ;
    PORT
      LAYER M4 ;
        RECT  21.516 44.112 21.6 44.136 ;
    END
  END q[276]
  PIN q[277]
    DIRECTION OUTPUT ;
    USE SIGNAL ;
    PORT
      LAYER M4 ;
        RECT  21.516 44.208 21.6 44.232 ;
    END
  END q[277]
  PIN q[278]
    DIRECTION OUTPUT ;
    USE SIGNAL ;
    PORT
      LAYER M4 ;
        RECT  21.516 44.304 21.6 44.328 ;
    END
  END q[278]
  PIN q[279]
    DIRECTION OUTPUT ;
    USE SIGNAL ;
    PORT
      LAYER M4 ;
        RECT  21.516 44.4 21.6 44.424 ;
    END
  END q[279]
  PIN q[27]
    DIRECTION OUTPUT ;
    USE SIGNAL ;
    PORT
      LAYER M4 ;
        RECT  21.516 76.272 21.6 76.296 ;
    END
  END q[27]
  PIN q[280]
    DIRECTION OUTPUT ;
    USE SIGNAL ;
    PORT
      LAYER M4 ;
        RECT  21.516 44.496 21.6 44.52 ;
    END
  END q[280]
  PIN q[281]
    DIRECTION OUTPUT ;
    USE SIGNAL ;
    PORT
      LAYER M4 ;
        RECT  21.516 44.592 21.6 44.616 ;
    END
  END q[281]
  PIN q[282]
    DIRECTION OUTPUT ;
    USE SIGNAL ;
    PORT
      LAYER M4 ;
        RECT  21.516 44.688 21.6 44.712 ;
    END
  END q[282]
  PIN q[283]
    DIRECTION OUTPUT ;
    USE SIGNAL ;
    PORT
      LAYER M4 ;
        RECT  21.516 44.784 21.6 44.808 ;
    END
  END q[283]
  PIN q[284]
    DIRECTION OUTPUT ;
    USE SIGNAL ;
    PORT
      LAYER M4 ;
        RECT  21.516 44.88 21.6 44.904 ;
    END
  END q[284]
  PIN q[285]
    DIRECTION OUTPUT ;
    USE SIGNAL ;
    PORT
      LAYER M4 ;
        RECT  21.516 44.976 21.6 45 ;
    END
  END q[285]
  PIN q[286]
    DIRECTION OUTPUT ;
    USE SIGNAL ;
    PORT
      LAYER M4 ;
        RECT  21.516 45.072 21.6 45.096 ;
    END
  END q[286]
  PIN q[287]
    DIRECTION OUTPUT ;
    USE SIGNAL ;
    PORT
      LAYER M4 ;
        RECT  21.516 45.168 21.6 45.192 ;
    END
  END q[287]
  PIN q[288]
    DIRECTION OUTPUT ;
    USE SIGNAL ;
    PORT
      LAYER M4 ;
        RECT  21.516 48.336 21.6 48.36 ;
    END
  END q[288]
  PIN q[289]
    DIRECTION OUTPUT ;
    USE SIGNAL ;
    PORT
      LAYER M4 ;
        RECT  21.516 48.432 21.6 48.456 ;
    END
  END q[289]
  PIN q[28]
    DIRECTION OUTPUT ;
    USE SIGNAL ;
    PORT
      LAYER M4 ;
        RECT  21.516 76.368 21.6 76.392 ;
    END
  END q[28]
  PIN q[290]
    DIRECTION OUTPUT ;
    USE SIGNAL ;
    PORT
      LAYER M4 ;
        RECT  21.516 48.528 21.6 48.552 ;
    END
  END q[290]
  PIN q[291]
    DIRECTION OUTPUT ;
    USE SIGNAL ;
    PORT
      LAYER M4 ;
        RECT  21.516 48.624 21.6 48.648 ;
    END
  END q[291]
  PIN q[292]
    DIRECTION OUTPUT ;
    USE SIGNAL ;
    PORT
      LAYER M4 ;
        RECT  21.516 48.72 21.6 48.744 ;
    END
  END q[292]
  PIN q[293]
    DIRECTION OUTPUT ;
    USE SIGNAL ;
    PORT
      LAYER M4 ;
        RECT  21.516 48.816 21.6 48.84 ;
    END
  END q[293]
  PIN q[294]
    DIRECTION OUTPUT ;
    USE SIGNAL ;
    PORT
      LAYER M4 ;
        RECT  21.516 48.912 21.6 48.936 ;
    END
  END q[294]
  PIN q[295]
    DIRECTION OUTPUT ;
    USE SIGNAL ;
    PORT
      LAYER M4 ;
        RECT  21.516 49.008 21.6 49.032 ;
    END
  END q[295]
  PIN q[296]
    DIRECTION OUTPUT ;
    USE SIGNAL ;
    PORT
      LAYER M4 ;
        RECT  21.516 49.104 21.6 49.128 ;
    END
  END q[296]
  PIN q[297]
    DIRECTION OUTPUT ;
    USE SIGNAL ;
    PORT
      LAYER M4 ;
        RECT  21.516 49.2 21.6 49.224 ;
    END
  END q[297]
  PIN q[298]
    DIRECTION OUTPUT ;
    USE SIGNAL ;
    PORT
      LAYER M4 ;
        RECT  21.516 49.296 21.6 49.32 ;
    END
  END q[298]
  PIN q[299]
    DIRECTION OUTPUT ;
    USE SIGNAL ;
    PORT
      LAYER M4 ;
        RECT  21.516 49.392 21.6 49.416 ;
    END
  END q[299]
  PIN q[29]
    DIRECTION OUTPUT ;
    USE SIGNAL ;
    PORT
      LAYER M4 ;
        RECT  21.516 76.464 21.6 76.488 ;
    END
  END q[29]
  PIN q[2]
    DIRECTION OUTPUT ;
    USE SIGNAL ;
    PORT
      LAYER M4 ;
        RECT  21.516 73.872 21.6 73.896 ;
    END
  END q[2]
  PIN q[300]
    DIRECTION OUTPUT ;
    USE SIGNAL ;
    PORT
      LAYER M4 ;
        RECT  21.516 49.488 21.6 49.512 ;
    END
  END q[300]
  PIN q[301]
    DIRECTION OUTPUT ;
    USE SIGNAL ;
    PORT
      LAYER M4 ;
        RECT  21.516 49.584 21.6 49.608 ;
    END
  END q[301]
  PIN q[302]
    DIRECTION OUTPUT ;
    USE SIGNAL ;
    PORT
      LAYER M4 ;
        RECT  21.516 49.68 21.6 49.704 ;
    END
  END q[302]
  PIN q[303]
    DIRECTION OUTPUT ;
    USE SIGNAL ;
    PORT
      LAYER M4 ;
        RECT  21.516 49.776 21.6 49.8 ;
    END
  END q[303]
  PIN q[304]
    DIRECTION OUTPUT ;
    USE SIGNAL ;
    PORT
      LAYER M4 ;
        RECT  21.516 49.872 21.6 49.896 ;
    END
  END q[304]
  PIN q[305]
    DIRECTION OUTPUT ;
    USE SIGNAL ;
    PORT
      LAYER M4 ;
        RECT  21.516 49.968 21.6 49.992 ;
    END
  END q[305]
  PIN q[306]
    DIRECTION OUTPUT ;
    USE SIGNAL ;
    PORT
      LAYER M4 ;
        RECT  21.516 50.064 21.6 50.088 ;
    END
  END q[306]
  PIN q[307]
    DIRECTION OUTPUT ;
    USE SIGNAL ;
    PORT
      LAYER M4 ;
        RECT  21.516 50.16 21.6 50.184 ;
    END
  END q[307]
  PIN q[308]
    DIRECTION OUTPUT ;
    USE SIGNAL ;
    PORT
      LAYER M4 ;
        RECT  21.516 50.256 21.6 50.28 ;
    END
  END q[308]
  PIN q[309]
    DIRECTION OUTPUT ;
    USE SIGNAL ;
    PORT
      LAYER M4 ;
        RECT  21.516 50.352 21.6 50.376 ;
    END
  END q[309]
  PIN q[30]
    DIRECTION OUTPUT ;
    USE SIGNAL ;
    PORT
      LAYER M4 ;
        RECT  21.516 76.56 21.6 76.584 ;
    END
  END q[30]
  PIN q[310]
    DIRECTION OUTPUT ;
    USE SIGNAL ;
    PORT
      LAYER M4 ;
        RECT  21.516 50.448 21.6 50.472 ;
    END
  END q[310]
  PIN q[311]
    DIRECTION OUTPUT ;
    USE SIGNAL ;
    PORT
      LAYER M4 ;
        RECT  21.516 50.544 21.6 50.568 ;
    END
  END q[311]
  PIN q[312]
    DIRECTION OUTPUT ;
    USE SIGNAL ;
    PORT
      LAYER M4 ;
        RECT  21.516 50.64 21.6 50.664 ;
    END
  END q[312]
  PIN q[313]
    DIRECTION OUTPUT ;
    USE SIGNAL ;
    PORT
      LAYER M4 ;
        RECT  21.516 50.736 21.6 50.76 ;
    END
  END q[313]
  PIN q[314]
    DIRECTION OUTPUT ;
    USE SIGNAL ;
    PORT
      LAYER M4 ;
        RECT  21.516 50.832 21.6 50.856 ;
    END
  END q[314]
  PIN q[315]
    DIRECTION OUTPUT ;
    USE SIGNAL ;
    PORT
      LAYER M4 ;
        RECT  21.516 50.928 21.6 50.952 ;
    END
  END q[315]
  PIN q[316]
    DIRECTION OUTPUT ;
    USE SIGNAL ;
    PORT
      LAYER M4 ;
        RECT  21.516 51.024 21.6 51.048 ;
    END
  END q[316]
  PIN q[317]
    DIRECTION OUTPUT ;
    USE SIGNAL ;
    PORT
      LAYER M4 ;
        RECT  21.516 51.12 21.6 51.144 ;
    END
  END q[317]
  PIN q[318]
    DIRECTION OUTPUT ;
    USE SIGNAL ;
    PORT
      LAYER M4 ;
        RECT  21.516 51.216 21.6 51.24 ;
    END
  END q[318]
  PIN q[319]
    DIRECTION OUTPUT ;
    USE SIGNAL ;
    PORT
      LAYER M4 ;
        RECT  21.516 51.312 21.6 51.336 ;
    END
  END q[319]
  PIN q[31]
    DIRECTION OUTPUT ;
    USE SIGNAL ;
    PORT
      LAYER M4 ;
        RECT  21.516 76.656 21.6 76.68 ;
    END
  END q[31]
  PIN q[320]
    DIRECTION OUTPUT ;
    USE SIGNAL ;
    PORT
      LAYER M4 ;
        RECT  21.516 45.264 21.6 45.288 ;
    END
  END q[320]
  PIN q[321]
    DIRECTION OUTPUT ;
    USE SIGNAL ;
    PORT
      LAYER M4 ;
        RECT  21.516 45.36 21.6 45.384 ;
    END
  END q[321]
  PIN q[322]
    DIRECTION OUTPUT ;
    USE SIGNAL ;
    PORT
      LAYER M4 ;
        RECT  21.516 45.456 21.6 45.48 ;
    END
  END q[322]
  PIN q[323]
    DIRECTION OUTPUT ;
    USE SIGNAL ;
    PORT
      LAYER M4 ;
        RECT  21.516 45.552 21.6 45.576 ;
    END
  END q[323]
  PIN q[324]
    DIRECTION OUTPUT ;
    USE SIGNAL ;
    PORT
      LAYER M4 ;
        RECT  21.516 45.648 21.6 45.672 ;
    END
  END q[324]
  PIN q[325]
    DIRECTION OUTPUT ;
    USE SIGNAL ;
    PORT
      LAYER M4 ;
        RECT  21.516 45.744 21.6 45.768 ;
    END
  END q[325]
  PIN q[326]
    DIRECTION OUTPUT ;
    USE SIGNAL ;
    PORT
      LAYER M4 ;
        RECT  21.516 45.84 21.6 45.864 ;
    END
  END q[326]
  PIN q[327]
    DIRECTION OUTPUT ;
    USE SIGNAL ;
    PORT
      LAYER M4 ;
        RECT  21.516 45.936 21.6 45.96 ;
    END
  END q[327]
  PIN q[328]
    DIRECTION OUTPUT ;
    USE SIGNAL ;
    PORT
      LAYER M4 ;
        RECT  21.516 46.032 21.6 46.056 ;
    END
  END q[328]
  PIN q[329]
    DIRECTION OUTPUT ;
    USE SIGNAL ;
    PORT
      LAYER M4 ;
        RECT  21.516 46.128 21.6 46.152 ;
    END
  END q[329]
  PIN q[32]
    DIRECTION OUTPUT ;
    USE SIGNAL ;
    PORT
      LAYER M4 ;
        RECT  21.516 64.464 21.6 64.488 ;
    END
  END q[32]
  PIN q[330]
    DIRECTION OUTPUT ;
    USE SIGNAL ;
    PORT
      LAYER M4 ;
        RECT  21.516 46.224 21.6 46.248 ;
    END
  END q[330]
  PIN q[331]
    DIRECTION OUTPUT ;
    USE SIGNAL ;
    PORT
      LAYER M4 ;
        RECT  21.516 46.32 21.6 46.344 ;
    END
  END q[331]
  PIN q[332]
    DIRECTION OUTPUT ;
    USE SIGNAL ;
    PORT
      LAYER M4 ;
        RECT  21.516 46.416 21.6 46.44 ;
    END
  END q[332]
  PIN q[333]
    DIRECTION OUTPUT ;
    USE SIGNAL ;
    PORT
      LAYER M4 ;
        RECT  21.516 46.512 21.6 46.536 ;
    END
  END q[333]
  PIN q[334]
    DIRECTION OUTPUT ;
    USE SIGNAL ;
    PORT
      LAYER M4 ;
        RECT  21.516 46.608 21.6 46.632 ;
    END
  END q[334]
  PIN q[335]
    DIRECTION OUTPUT ;
    USE SIGNAL ;
    PORT
      LAYER M4 ;
        RECT  21.516 46.704 21.6 46.728 ;
    END
  END q[335]
  PIN q[336]
    DIRECTION OUTPUT ;
    USE SIGNAL ;
    PORT
      LAYER M4 ;
        RECT  21.516 46.8 21.6 46.824 ;
    END
  END q[336]
  PIN q[337]
    DIRECTION OUTPUT ;
    USE SIGNAL ;
    PORT
      LAYER M4 ;
        RECT  21.516 46.896 21.6 46.92 ;
    END
  END q[337]
  PIN q[338]
    DIRECTION OUTPUT ;
    USE SIGNAL ;
    PORT
      LAYER M4 ;
        RECT  21.516 46.992 21.6 47.016 ;
    END
  END q[338]
  PIN q[339]
    DIRECTION OUTPUT ;
    USE SIGNAL ;
    PORT
      LAYER M4 ;
        RECT  21.516 47.088 21.6 47.112 ;
    END
  END q[339]
  PIN q[33]
    DIRECTION OUTPUT ;
    USE SIGNAL ;
    PORT
      LAYER M4 ;
        RECT  21.516 64.56 21.6 64.584 ;
    END
  END q[33]
  PIN q[340]
    DIRECTION OUTPUT ;
    USE SIGNAL ;
    PORT
      LAYER M4 ;
        RECT  21.516 47.184 21.6 47.208 ;
    END
  END q[340]
  PIN q[341]
    DIRECTION OUTPUT ;
    USE SIGNAL ;
    PORT
      LAYER M4 ;
        RECT  21.516 47.28 21.6 47.304 ;
    END
  END q[341]
  PIN q[342]
    DIRECTION OUTPUT ;
    USE SIGNAL ;
    PORT
      LAYER M4 ;
        RECT  21.516 47.376 21.6 47.4 ;
    END
  END q[342]
  PIN q[343]
    DIRECTION OUTPUT ;
    USE SIGNAL ;
    PORT
      LAYER M4 ;
        RECT  21.516 47.472 21.6 47.496 ;
    END
  END q[343]
  PIN q[344]
    DIRECTION OUTPUT ;
    USE SIGNAL ;
    PORT
      LAYER M4 ;
        RECT  21.516 47.568 21.6 47.592 ;
    END
  END q[344]
  PIN q[345]
    DIRECTION OUTPUT ;
    USE SIGNAL ;
    PORT
      LAYER M4 ;
        RECT  21.516 47.664 21.6 47.688 ;
    END
  END q[345]
  PIN q[346]
    DIRECTION OUTPUT ;
    USE SIGNAL ;
    PORT
      LAYER M4 ;
        RECT  21.516 47.76 21.6 47.784 ;
    END
  END q[346]
  PIN q[347]
    DIRECTION OUTPUT ;
    USE SIGNAL ;
    PORT
      LAYER M4 ;
        RECT  21.516 47.856 21.6 47.88 ;
    END
  END q[347]
  PIN q[348]
    DIRECTION OUTPUT ;
    USE SIGNAL ;
    PORT
      LAYER M4 ;
        RECT  21.516 47.952 21.6 47.976 ;
    END
  END q[348]
  PIN q[349]
    DIRECTION OUTPUT ;
    USE SIGNAL ;
    PORT
      LAYER M4 ;
        RECT  21.516 48.048 21.6 48.072 ;
    END
  END q[349]
  PIN q[34]
    DIRECTION OUTPUT ;
    USE SIGNAL ;
    PORT
      LAYER M4 ;
        RECT  21.516 64.656 21.6 64.68 ;
    END
  END q[34]
  PIN q[350]
    DIRECTION OUTPUT ;
    USE SIGNAL ;
    PORT
      LAYER M4 ;
        RECT  21.516 48.144 21.6 48.168 ;
    END
  END q[350]
  PIN q[351]
    DIRECTION OUTPUT ;
    USE SIGNAL ;
    PORT
      LAYER M4 ;
        RECT  21.516 48.24 21.6 48.264 ;
    END
  END q[351]
  PIN q[352]
    DIRECTION OUTPUT ;
    USE SIGNAL ;
    PORT
      LAYER M4 ;
        RECT  21.516 54.48 21.6 54.504 ;
    END
  END q[352]
  PIN q[353]
    DIRECTION OUTPUT ;
    USE SIGNAL ;
    PORT
      LAYER M4 ;
        RECT  21.516 54.576 21.6 54.6 ;
    END
  END q[353]
  PIN q[354]
    DIRECTION OUTPUT ;
    USE SIGNAL ;
    PORT
      LAYER M4 ;
        RECT  21.516 54.672 21.6 54.696 ;
    END
  END q[354]
  PIN q[355]
    DIRECTION OUTPUT ;
    USE SIGNAL ;
    PORT
      LAYER M4 ;
        RECT  21.516 54.768 21.6 54.792 ;
    END
  END q[355]
  PIN q[356]
    DIRECTION OUTPUT ;
    USE SIGNAL ;
    PORT
      LAYER M4 ;
        RECT  21.516 54.864 21.6 54.888 ;
    END
  END q[356]
  PIN q[357]
    DIRECTION OUTPUT ;
    USE SIGNAL ;
    PORT
      LAYER M4 ;
        RECT  21.516 54.96 21.6 54.984 ;
    END
  END q[357]
  PIN q[358]
    DIRECTION OUTPUT ;
    USE SIGNAL ;
    PORT
      LAYER M4 ;
        RECT  21.516 55.056 21.6 55.08 ;
    END
  END q[358]
  PIN q[359]
    DIRECTION OUTPUT ;
    USE SIGNAL ;
    PORT
      LAYER M4 ;
        RECT  21.516 55.152 21.6 55.176 ;
    END
  END q[359]
  PIN q[35]
    DIRECTION OUTPUT ;
    USE SIGNAL ;
    PORT
      LAYER M4 ;
        RECT  21.516 64.752 21.6 64.776 ;
    END
  END q[35]
  PIN q[360]
    DIRECTION OUTPUT ;
    USE SIGNAL ;
    PORT
      LAYER M4 ;
        RECT  21.516 55.248 21.6 55.272 ;
    END
  END q[360]
  PIN q[361]
    DIRECTION OUTPUT ;
    USE SIGNAL ;
    PORT
      LAYER M4 ;
        RECT  21.516 55.344 21.6 55.368 ;
    END
  END q[361]
  PIN q[362]
    DIRECTION OUTPUT ;
    USE SIGNAL ;
    PORT
      LAYER M4 ;
        RECT  21.516 55.44 21.6 55.464 ;
    END
  END q[362]
  PIN q[363]
    DIRECTION OUTPUT ;
    USE SIGNAL ;
    PORT
      LAYER M4 ;
        RECT  21.516 55.536 21.6 55.56 ;
    END
  END q[363]
  PIN q[364]
    DIRECTION OUTPUT ;
    USE SIGNAL ;
    PORT
      LAYER M4 ;
        RECT  21.516 55.632 21.6 55.656 ;
    END
  END q[364]
  PIN q[365]
    DIRECTION OUTPUT ;
    USE SIGNAL ;
    PORT
      LAYER M4 ;
        RECT  21.516 55.728 21.6 55.752 ;
    END
  END q[365]
  PIN q[366]
    DIRECTION OUTPUT ;
    USE SIGNAL ;
    PORT
      LAYER M4 ;
        RECT  21.516 55.824 21.6 55.848 ;
    END
  END q[366]
  PIN q[367]
    DIRECTION OUTPUT ;
    USE SIGNAL ;
    PORT
      LAYER M4 ;
        RECT  21.516 55.92 21.6 55.944 ;
    END
  END q[367]
  PIN q[368]
    DIRECTION OUTPUT ;
    USE SIGNAL ;
    PORT
      LAYER M4 ;
        RECT  21.516 56.016 21.6 56.04 ;
    END
  END q[368]
  PIN q[369]
    DIRECTION OUTPUT ;
    USE SIGNAL ;
    PORT
      LAYER M4 ;
        RECT  21.516 56.112 21.6 56.136 ;
    END
  END q[369]
  PIN q[36]
    DIRECTION OUTPUT ;
    USE SIGNAL ;
    PORT
      LAYER M4 ;
        RECT  21.516 64.848 21.6 64.872 ;
    END
  END q[36]
  PIN q[370]
    DIRECTION OUTPUT ;
    USE SIGNAL ;
    PORT
      LAYER M4 ;
        RECT  21.516 56.208 21.6 56.232 ;
    END
  END q[370]
  PIN q[371]
    DIRECTION OUTPUT ;
    USE SIGNAL ;
    PORT
      LAYER M4 ;
        RECT  21.516 56.304 21.6 56.328 ;
    END
  END q[371]
  PIN q[372]
    DIRECTION OUTPUT ;
    USE SIGNAL ;
    PORT
      LAYER M4 ;
        RECT  21.516 56.4 21.6 56.424 ;
    END
  END q[372]
  PIN q[373]
    DIRECTION OUTPUT ;
    USE SIGNAL ;
    PORT
      LAYER M4 ;
        RECT  21.516 56.496 21.6 56.52 ;
    END
  END q[373]
  PIN q[374]
    DIRECTION OUTPUT ;
    USE SIGNAL ;
    PORT
      LAYER M4 ;
        RECT  21.516 56.592 21.6 56.616 ;
    END
  END q[374]
  PIN q[375]
    DIRECTION OUTPUT ;
    USE SIGNAL ;
    PORT
      LAYER M4 ;
        RECT  21.516 56.688 21.6 56.712 ;
    END
  END q[375]
  PIN q[376]
    DIRECTION OUTPUT ;
    USE SIGNAL ;
    PORT
      LAYER M4 ;
        RECT  21.516 56.784 21.6 56.808 ;
    END
  END q[376]
  PIN q[377]
    DIRECTION OUTPUT ;
    USE SIGNAL ;
    PORT
      LAYER M4 ;
        RECT  21.516 56.88 21.6 56.904 ;
    END
  END q[377]
  PIN q[378]
    DIRECTION OUTPUT ;
    USE SIGNAL ;
    PORT
      LAYER M4 ;
        RECT  21.516 56.976 21.6 57 ;
    END
  END q[378]
  PIN q[379]
    DIRECTION OUTPUT ;
    USE SIGNAL ;
    PORT
      LAYER M4 ;
        RECT  21.516 57.072 21.6 57.096 ;
    END
  END q[379]
  PIN q[37]
    DIRECTION OUTPUT ;
    USE SIGNAL ;
    PORT
      LAYER M4 ;
        RECT  21.516 64.944 21.6 64.968 ;
    END
  END q[37]
  PIN q[380]
    DIRECTION OUTPUT ;
    USE SIGNAL ;
    PORT
      LAYER M4 ;
        RECT  21.516 57.168 21.6 57.192 ;
    END
  END q[380]
  PIN q[381]
    DIRECTION OUTPUT ;
    USE SIGNAL ;
    PORT
      LAYER M4 ;
        RECT  21.516 57.264 21.6 57.288 ;
    END
  END q[381]
  PIN q[382]
    DIRECTION OUTPUT ;
    USE SIGNAL ;
    PORT
      LAYER M4 ;
        RECT  21.516 57.36 21.6 57.384 ;
    END
  END q[382]
  PIN q[383]
    DIRECTION OUTPUT ;
    USE SIGNAL ;
    PORT
      LAYER M4 ;
        RECT  21.516 57.456 21.6 57.48 ;
    END
  END q[383]
  PIN q[384]
    DIRECTION OUTPUT ;
    USE SIGNAL ;
    PORT
      LAYER M4 ;
        RECT  21.516 83.664 21.6 83.688 ;
    END
  END q[384]
  PIN q[385]
    DIRECTION OUTPUT ;
    USE SIGNAL ;
    PORT
      LAYER M4 ;
        RECT  21.516 83.76 21.6 83.784 ;
    END
  END q[385]
  PIN q[386]
    DIRECTION OUTPUT ;
    USE SIGNAL ;
    PORT
      LAYER M4 ;
        RECT  21.516 83.856 21.6 83.88 ;
    END
  END q[386]
  PIN q[387]
    DIRECTION OUTPUT ;
    USE SIGNAL ;
    PORT
      LAYER M4 ;
        RECT  21.516 83.952 21.6 83.976 ;
    END
  END q[387]
  PIN q[388]
    DIRECTION OUTPUT ;
    USE SIGNAL ;
    PORT
      LAYER M4 ;
        RECT  21.516 84.048 21.6 84.072 ;
    END
  END q[388]
  PIN q[389]
    DIRECTION OUTPUT ;
    USE SIGNAL ;
    PORT
      LAYER M4 ;
        RECT  21.516 84.144 21.6 84.168 ;
    END
  END q[389]
  PIN q[38]
    DIRECTION OUTPUT ;
    USE SIGNAL ;
    PORT
      LAYER M4 ;
        RECT  21.516 65.04 21.6 65.064 ;
    END
  END q[38]
  PIN q[390]
    DIRECTION OUTPUT ;
    USE SIGNAL ;
    PORT
      LAYER M4 ;
        RECT  21.516 84.24 21.6 84.264 ;
    END
  END q[390]
  PIN q[391]
    DIRECTION OUTPUT ;
    USE SIGNAL ;
    PORT
      LAYER M4 ;
        RECT  21.516 84.336 21.6 84.36 ;
    END
  END q[391]
  PIN q[392]
    DIRECTION OUTPUT ;
    USE SIGNAL ;
    PORT
      LAYER M4 ;
        RECT  21.516 84.432 21.6 84.456 ;
    END
  END q[392]
  PIN q[393]
    DIRECTION OUTPUT ;
    USE SIGNAL ;
    PORT
      LAYER M4 ;
        RECT  21.516 84.528 21.6 84.552 ;
    END
  END q[393]
  PIN q[394]
    DIRECTION OUTPUT ;
    USE SIGNAL ;
    PORT
      LAYER M4 ;
        RECT  21.516 84.624 21.6 84.648 ;
    END
  END q[394]
  PIN q[395]
    DIRECTION OUTPUT ;
    USE SIGNAL ;
    PORT
      LAYER M4 ;
        RECT  21.516 84.72 21.6 84.744 ;
    END
  END q[395]
  PIN q[396]
    DIRECTION OUTPUT ;
    USE SIGNAL ;
    PORT
      LAYER M4 ;
        RECT  21.516 84.816 21.6 84.84 ;
    END
  END q[396]
  PIN q[397]
    DIRECTION OUTPUT ;
    USE SIGNAL ;
    PORT
      LAYER M4 ;
        RECT  21.516 84.912 21.6 84.936 ;
    END
  END q[397]
  PIN q[398]
    DIRECTION OUTPUT ;
    USE SIGNAL ;
    PORT
      LAYER M4 ;
        RECT  21.516 85.008 21.6 85.032 ;
    END
  END q[398]
  PIN q[399]
    DIRECTION OUTPUT ;
    USE SIGNAL ;
    PORT
      LAYER M4 ;
        RECT  21.516 85.104 21.6 85.128 ;
    END
  END q[399]
  PIN q[39]
    DIRECTION OUTPUT ;
    USE SIGNAL ;
    PORT
      LAYER M4 ;
        RECT  21.516 65.136 21.6 65.16 ;
    END
  END q[39]
  PIN q[3]
    DIRECTION OUTPUT ;
    USE SIGNAL ;
    PORT
      LAYER M4 ;
        RECT  21.516 73.968 21.6 73.992 ;
    END
  END q[3]
  PIN q[400]
    DIRECTION OUTPUT ;
    USE SIGNAL ;
    PORT
      LAYER M4 ;
        RECT  21.516 85.2 21.6 85.224 ;
    END
  END q[400]
  PIN q[401]
    DIRECTION OUTPUT ;
    USE SIGNAL ;
    PORT
      LAYER M4 ;
        RECT  21.516 85.296 21.6 85.32 ;
    END
  END q[401]
  PIN q[402]
    DIRECTION OUTPUT ;
    USE SIGNAL ;
    PORT
      LAYER M4 ;
        RECT  21.516 85.392 21.6 85.416 ;
    END
  END q[402]
  PIN q[403]
    DIRECTION OUTPUT ;
    USE SIGNAL ;
    PORT
      LAYER M4 ;
        RECT  21.516 85.488 21.6 85.512 ;
    END
  END q[403]
  PIN q[404]
    DIRECTION OUTPUT ;
    USE SIGNAL ;
    PORT
      LAYER M4 ;
        RECT  21.516 85.584 21.6 85.608 ;
    END
  END q[404]
  PIN q[405]
    DIRECTION OUTPUT ;
    USE SIGNAL ;
    PORT
      LAYER M4 ;
        RECT  21.516 85.68 21.6 85.704 ;
    END
  END q[405]
  PIN q[406]
    DIRECTION OUTPUT ;
    USE SIGNAL ;
    PORT
      LAYER M4 ;
        RECT  21.516 85.776 21.6 85.8 ;
    END
  END q[406]
  PIN q[407]
    DIRECTION OUTPUT ;
    USE SIGNAL ;
    PORT
      LAYER M4 ;
        RECT  21.516 85.872 21.6 85.896 ;
    END
  END q[407]
  PIN q[408]
    DIRECTION OUTPUT ;
    USE SIGNAL ;
    PORT
      LAYER M4 ;
        RECT  21.516 85.968 21.6 85.992 ;
    END
  END q[408]
  PIN q[409]
    DIRECTION OUTPUT ;
    USE SIGNAL ;
    PORT
      LAYER M4 ;
        RECT  21.516 86.064 21.6 86.088 ;
    END
  END q[409]
  PIN q[40]
    DIRECTION OUTPUT ;
    USE SIGNAL ;
    PORT
      LAYER M4 ;
        RECT  21.516 65.232 21.6 65.256 ;
    END
  END q[40]
  PIN q[410]
    DIRECTION OUTPUT ;
    USE SIGNAL ;
    PORT
      LAYER M4 ;
        RECT  21.516 86.16 21.6 86.184 ;
    END
  END q[410]
  PIN q[411]
    DIRECTION OUTPUT ;
    USE SIGNAL ;
    PORT
      LAYER M4 ;
        RECT  21.516 86.256 21.6 86.28 ;
    END
  END q[411]
  PIN q[412]
    DIRECTION OUTPUT ;
    USE SIGNAL ;
    PORT
      LAYER M4 ;
        RECT  21.516 86.352 21.6 86.376 ;
    END
  END q[412]
  PIN q[413]
    DIRECTION OUTPUT ;
    USE SIGNAL ;
    PORT
      LAYER M4 ;
        RECT  21.516 86.448 21.6 86.472 ;
    END
  END q[413]
  PIN q[414]
    DIRECTION OUTPUT ;
    USE SIGNAL ;
    PORT
      LAYER M4 ;
        RECT  21.516 86.544 21.6 86.568 ;
    END
  END q[414]
  PIN q[415]
    DIRECTION OUTPUT ;
    USE SIGNAL ;
    PORT
      LAYER M4 ;
        RECT  21.516 86.64 21.6 86.664 ;
    END
  END q[415]
  PIN q[416]
    DIRECTION OUTPUT ;
    USE SIGNAL ;
    PORT
      LAYER M4 ;
        RECT  21.516 86.736 21.6 86.76 ;
    END
  END q[416]
  PIN q[417]
    DIRECTION OUTPUT ;
    USE SIGNAL ;
    PORT
      LAYER M4 ;
        RECT  21.516 86.832 21.6 86.856 ;
    END
  END q[417]
  PIN q[418]
    DIRECTION OUTPUT ;
    USE SIGNAL ;
    PORT
      LAYER M4 ;
        RECT  21.516 86.928 21.6 86.952 ;
    END
  END q[418]
  PIN q[419]
    DIRECTION OUTPUT ;
    USE SIGNAL ;
    PORT
      LAYER M4 ;
        RECT  21.516 87.024 21.6 87.048 ;
    END
  END q[419]
  PIN q[41]
    DIRECTION OUTPUT ;
    USE SIGNAL ;
    PORT
      LAYER M4 ;
        RECT  21.516 65.328 21.6 65.352 ;
    END
  END q[41]
  PIN q[420]
    DIRECTION OUTPUT ;
    USE SIGNAL ;
    PORT
      LAYER M4 ;
        RECT  21.516 87.12 21.6 87.144 ;
    END
  END q[420]
  PIN q[421]
    DIRECTION OUTPUT ;
    USE SIGNAL ;
    PORT
      LAYER M4 ;
        RECT  21.516 87.216 21.6 87.24 ;
    END
  END q[421]
  PIN q[422]
    DIRECTION OUTPUT ;
    USE SIGNAL ;
    PORT
      LAYER M4 ;
        RECT  21.516 87.312 21.6 87.336 ;
    END
  END q[422]
  PIN q[423]
    DIRECTION OUTPUT ;
    USE SIGNAL ;
    PORT
      LAYER M4 ;
        RECT  21.516 87.408 21.6 87.432 ;
    END
  END q[423]
  PIN q[424]
    DIRECTION OUTPUT ;
    USE SIGNAL ;
    PORT
      LAYER M4 ;
        RECT  21.516 87.504 21.6 87.528 ;
    END
  END q[424]
  PIN q[425]
    DIRECTION OUTPUT ;
    USE SIGNAL ;
    PORT
      LAYER M4 ;
        RECT  21.516 87.6 21.6 87.624 ;
    END
  END q[425]
  PIN q[426]
    DIRECTION OUTPUT ;
    USE SIGNAL ;
    PORT
      LAYER M4 ;
        RECT  21.516 87.696 21.6 87.72 ;
    END
  END q[426]
  PIN q[427]
    DIRECTION OUTPUT ;
    USE SIGNAL ;
    PORT
      LAYER M4 ;
        RECT  21.516 87.792 21.6 87.816 ;
    END
  END q[427]
  PIN q[428]
    DIRECTION OUTPUT ;
    USE SIGNAL ;
    PORT
      LAYER M4 ;
        RECT  21.516 87.888 21.6 87.912 ;
    END
  END q[428]
  PIN q[429]
    DIRECTION OUTPUT ;
    USE SIGNAL ;
    PORT
      LAYER M4 ;
        RECT  21.516 87.984 21.6 88.008 ;
    END
  END q[429]
  PIN q[42]
    DIRECTION OUTPUT ;
    USE SIGNAL ;
    PORT
      LAYER M4 ;
        RECT  21.516 65.424 21.6 65.448 ;
    END
  END q[42]
  PIN q[430]
    DIRECTION OUTPUT ;
    USE SIGNAL ;
    PORT
      LAYER M4 ;
        RECT  21.516 88.08 21.6 88.104 ;
    END
  END q[430]
  PIN q[431]
    DIRECTION OUTPUT ;
    USE SIGNAL ;
    PORT
      LAYER M4 ;
        RECT  21.516 88.176 21.6 88.2 ;
    END
  END q[431]
  PIN q[432]
    DIRECTION OUTPUT ;
    USE SIGNAL ;
    PORT
      LAYER M4 ;
        RECT  21.516 88.272 21.6 88.296 ;
    END
  END q[432]
  PIN q[433]
    DIRECTION OUTPUT ;
    USE SIGNAL ;
    PORT
      LAYER M4 ;
        RECT  21.516 88.368 21.6 88.392 ;
    END
  END q[433]
  PIN q[434]
    DIRECTION OUTPUT ;
    USE SIGNAL ;
    PORT
      LAYER M4 ;
        RECT  21.516 88.464 21.6 88.488 ;
    END
  END q[434]
  PIN q[435]
    DIRECTION OUTPUT ;
    USE SIGNAL ;
    PORT
      LAYER M4 ;
        RECT  21.516 88.56 21.6 88.584 ;
    END
  END q[435]
  PIN q[436]
    DIRECTION OUTPUT ;
    USE SIGNAL ;
    PORT
      LAYER M4 ;
        RECT  21.516 88.656 21.6 88.68 ;
    END
  END q[436]
  PIN q[437]
    DIRECTION OUTPUT ;
    USE SIGNAL ;
    PORT
      LAYER M4 ;
        RECT  21.516 88.752 21.6 88.776 ;
    END
  END q[437]
  PIN q[438]
    DIRECTION OUTPUT ;
    USE SIGNAL ;
    PORT
      LAYER M4 ;
        RECT  21.516 88.848 21.6 88.872 ;
    END
  END q[438]
  PIN q[439]
    DIRECTION OUTPUT ;
    USE SIGNAL ;
    PORT
      LAYER M4 ;
        RECT  21.516 88.944 21.6 88.968 ;
    END
  END q[439]
  PIN q[43]
    DIRECTION OUTPUT ;
    USE SIGNAL ;
    PORT
      LAYER M4 ;
        RECT  21.516 65.52 21.6 65.544 ;
    END
  END q[43]
  PIN q[440]
    DIRECTION OUTPUT ;
    USE SIGNAL ;
    PORT
      LAYER M4 ;
        RECT  21.516 89.04 21.6 89.064 ;
    END
  END q[440]
  PIN q[441]
    DIRECTION OUTPUT ;
    USE SIGNAL ;
    PORT
      LAYER M4 ;
        RECT  21.516 89.136 21.6 89.16 ;
    END
  END q[441]
  PIN q[442]
    DIRECTION OUTPUT ;
    USE SIGNAL ;
    PORT
      LAYER M4 ;
        RECT  21.516 89.232 21.6 89.256 ;
    END
  END q[442]
  PIN q[443]
    DIRECTION OUTPUT ;
    USE SIGNAL ;
    PORT
      LAYER M4 ;
        RECT  21.516 89.328 21.6 89.352 ;
    END
  END q[443]
  PIN q[444]
    DIRECTION OUTPUT ;
    USE SIGNAL ;
    PORT
      LAYER M4 ;
        RECT  21.516 89.424 21.6 89.448 ;
    END
  END q[444]
  PIN q[445]
    DIRECTION OUTPUT ;
    USE SIGNAL ;
    PORT
      LAYER M4 ;
        RECT  21.516 89.52 21.6 89.544 ;
    END
  END q[445]
  PIN q[446]
    DIRECTION OUTPUT ;
    USE SIGNAL ;
    PORT
      LAYER M4 ;
        RECT  21.516 89.616 21.6 89.64 ;
    END
  END q[446]
  PIN q[447]
    DIRECTION OUTPUT ;
    USE SIGNAL ;
    PORT
      LAYER M4 ;
        RECT  21.516 89.712 21.6 89.736 ;
    END
  END q[447]
  PIN q[448]
    DIRECTION OUTPUT ;
    USE SIGNAL ;
    PORT
      LAYER M4 ;
        RECT  21.516 77.52 21.6 77.544 ;
    END
  END q[448]
  PIN q[449]
    DIRECTION OUTPUT ;
    USE SIGNAL ;
    PORT
      LAYER M4 ;
        RECT  21.516 77.616 21.6 77.64 ;
    END
  END q[449]
  PIN q[44]
    DIRECTION OUTPUT ;
    USE SIGNAL ;
    PORT
      LAYER M4 ;
        RECT  21.516 65.616 21.6 65.64 ;
    END
  END q[44]
  PIN q[450]
    DIRECTION OUTPUT ;
    USE SIGNAL ;
    PORT
      LAYER M4 ;
        RECT  21.516 77.712 21.6 77.736 ;
    END
  END q[450]
  PIN q[451]
    DIRECTION OUTPUT ;
    USE SIGNAL ;
    PORT
      LAYER M4 ;
        RECT  21.516 77.808 21.6 77.832 ;
    END
  END q[451]
  PIN q[452]
    DIRECTION OUTPUT ;
    USE SIGNAL ;
    PORT
      LAYER M4 ;
        RECT  21.516 77.904 21.6 77.928 ;
    END
  END q[452]
  PIN q[453]
    DIRECTION OUTPUT ;
    USE SIGNAL ;
    PORT
      LAYER M4 ;
        RECT  21.516 78 21.6 78.024 ;
    END
  END q[453]
  PIN q[454]
    DIRECTION OUTPUT ;
    USE SIGNAL ;
    PORT
      LAYER M4 ;
        RECT  21.516 78.096 21.6 78.12 ;
    END
  END q[454]
  PIN q[455]
    DIRECTION OUTPUT ;
    USE SIGNAL ;
    PORT
      LAYER M4 ;
        RECT  21.516 78.192 21.6 78.216 ;
    END
  END q[455]
  PIN q[456]
    DIRECTION OUTPUT ;
    USE SIGNAL ;
    PORT
      LAYER M4 ;
        RECT  21.516 78.288 21.6 78.312 ;
    END
  END q[456]
  PIN q[457]
    DIRECTION OUTPUT ;
    USE SIGNAL ;
    PORT
      LAYER M4 ;
        RECT  21.516 78.384 21.6 78.408 ;
    END
  END q[457]
  PIN q[458]
    DIRECTION OUTPUT ;
    USE SIGNAL ;
    PORT
      LAYER M4 ;
        RECT  21.516 78.48 21.6 78.504 ;
    END
  END q[458]
  PIN q[459]
    DIRECTION OUTPUT ;
    USE SIGNAL ;
    PORT
      LAYER M4 ;
        RECT  21.516 78.576 21.6 78.6 ;
    END
  END q[459]
  PIN q[45]
    DIRECTION OUTPUT ;
    USE SIGNAL ;
    PORT
      LAYER M4 ;
        RECT  21.516 65.712 21.6 65.736 ;
    END
  END q[45]
  PIN q[460]
    DIRECTION OUTPUT ;
    USE SIGNAL ;
    PORT
      LAYER M4 ;
        RECT  21.516 78.672 21.6 78.696 ;
    END
  END q[460]
  PIN q[461]
    DIRECTION OUTPUT ;
    USE SIGNAL ;
    PORT
      LAYER M4 ;
        RECT  21.516 78.768 21.6 78.792 ;
    END
  END q[461]
  PIN q[462]
    DIRECTION OUTPUT ;
    USE SIGNAL ;
    PORT
      LAYER M4 ;
        RECT  21.516 78.864 21.6 78.888 ;
    END
  END q[462]
  PIN q[463]
    DIRECTION OUTPUT ;
    USE SIGNAL ;
    PORT
      LAYER M4 ;
        RECT  21.516 78.96 21.6 78.984 ;
    END
  END q[463]
  PIN q[464]
    DIRECTION OUTPUT ;
    USE SIGNAL ;
    PORT
      LAYER M4 ;
        RECT  21.516 79.056 21.6 79.08 ;
    END
  END q[464]
  PIN q[465]
    DIRECTION OUTPUT ;
    USE SIGNAL ;
    PORT
      LAYER M4 ;
        RECT  21.516 79.152 21.6 79.176 ;
    END
  END q[465]
  PIN q[466]
    DIRECTION OUTPUT ;
    USE SIGNAL ;
    PORT
      LAYER M4 ;
        RECT  21.516 79.248 21.6 79.272 ;
    END
  END q[466]
  PIN q[467]
    DIRECTION OUTPUT ;
    USE SIGNAL ;
    PORT
      LAYER M4 ;
        RECT  21.516 79.344 21.6 79.368 ;
    END
  END q[467]
  PIN q[468]
    DIRECTION OUTPUT ;
    USE SIGNAL ;
    PORT
      LAYER M4 ;
        RECT  21.516 79.44 21.6 79.464 ;
    END
  END q[468]
  PIN q[469]
    DIRECTION OUTPUT ;
    USE SIGNAL ;
    PORT
      LAYER M4 ;
        RECT  21.516 79.536 21.6 79.56 ;
    END
  END q[469]
  PIN q[46]
    DIRECTION OUTPUT ;
    USE SIGNAL ;
    PORT
      LAYER M4 ;
        RECT  21.516 65.808 21.6 65.832 ;
    END
  END q[46]
  PIN q[470]
    DIRECTION OUTPUT ;
    USE SIGNAL ;
    PORT
      LAYER M4 ;
        RECT  21.516 79.632 21.6 79.656 ;
    END
  END q[470]
  PIN q[471]
    DIRECTION OUTPUT ;
    USE SIGNAL ;
    PORT
      LAYER M4 ;
        RECT  21.516 79.728 21.6 79.752 ;
    END
  END q[471]
  PIN q[472]
    DIRECTION OUTPUT ;
    USE SIGNAL ;
    PORT
      LAYER M4 ;
        RECT  21.516 79.824 21.6 79.848 ;
    END
  END q[472]
  PIN q[473]
    DIRECTION OUTPUT ;
    USE SIGNAL ;
    PORT
      LAYER M4 ;
        RECT  21.516 79.92 21.6 79.944 ;
    END
  END q[473]
  PIN q[474]
    DIRECTION OUTPUT ;
    USE SIGNAL ;
    PORT
      LAYER M4 ;
        RECT  21.516 80.016 21.6 80.04 ;
    END
  END q[474]
  PIN q[475]
    DIRECTION OUTPUT ;
    USE SIGNAL ;
    PORT
      LAYER M4 ;
        RECT  21.516 80.112 21.6 80.136 ;
    END
  END q[475]
  PIN q[476]
    DIRECTION OUTPUT ;
    USE SIGNAL ;
    PORT
      LAYER M4 ;
        RECT  21.516 80.208 21.6 80.232 ;
    END
  END q[476]
  PIN q[477]
    DIRECTION OUTPUT ;
    USE SIGNAL ;
    PORT
      LAYER M4 ;
        RECT  21.516 80.304 21.6 80.328 ;
    END
  END q[477]
  PIN q[478]
    DIRECTION OUTPUT ;
    USE SIGNAL ;
    PORT
      LAYER M4 ;
        RECT  21.516 80.4 21.6 80.424 ;
    END
  END q[478]
  PIN q[479]
    DIRECTION OUTPUT ;
    USE SIGNAL ;
    PORT
      LAYER M4 ;
        RECT  21.516 80.496 21.6 80.52 ;
    END
  END q[479]
  PIN q[47]
    DIRECTION OUTPUT ;
    USE SIGNAL ;
    PORT
      LAYER M4 ;
        RECT  21.516 65.904 21.6 65.928 ;
    END
  END q[47]
  PIN q[480]
    DIRECTION OUTPUT ;
    USE SIGNAL ;
    PORT
      LAYER M4 ;
        RECT  21.516 80.592 21.6 80.616 ;
    END
  END q[480]
  PIN q[481]
    DIRECTION OUTPUT ;
    USE SIGNAL ;
    PORT
      LAYER M4 ;
        RECT  21.516 80.688 21.6 80.712 ;
    END
  END q[481]
  PIN q[482]
    DIRECTION OUTPUT ;
    USE SIGNAL ;
    PORT
      LAYER M4 ;
        RECT  21.516 80.784 21.6 80.808 ;
    END
  END q[482]
  PIN q[483]
    DIRECTION OUTPUT ;
    USE SIGNAL ;
    PORT
      LAYER M4 ;
        RECT  21.516 80.88 21.6 80.904 ;
    END
  END q[483]
  PIN q[484]
    DIRECTION OUTPUT ;
    USE SIGNAL ;
    PORT
      LAYER M4 ;
        RECT  21.516 80.976 21.6 81 ;
    END
  END q[484]
  PIN q[485]
    DIRECTION OUTPUT ;
    USE SIGNAL ;
    PORT
      LAYER M4 ;
        RECT  21.516 81.072 21.6 81.096 ;
    END
  END q[485]
  PIN q[486]
    DIRECTION OUTPUT ;
    USE SIGNAL ;
    PORT
      LAYER M4 ;
        RECT  21.516 81.168 21.6 81.192 ;
    END
  END q[486]
  PIN q[487]
    DIRECTION OUTPUT ;
    USE SIGNAL ;
    PORT
      LAYER M4 ;
        RECT  21.516 81.264 21.6 81.288 ;
    END
  END q[487]
  PIN q[488]
    DIRECTION OUTPUT ;
    USE SIGNAL ;
    PORT
      LAYER M4 ;
        RECT  21.516 81.36 21.6 81.384 ;
    END
  END q[488]
  PIN q[489]
    DIRECTION OUTPUT ;
    USE SIGNAL ;
    PORT
      LAYER M4 ;
        RECT  21.516 81.456 21.6 81.48 ;
    END
  END q[489]
  PIN q[48]
    DIRECTION OUTPUT ;
    USE SIGNAL ;
    PORT
      LAYER M4 ;
        RECT  21.516 66 21.6 66.024 ;
    END
  END q[48]
  PIN q[490]
    DIRECTION OUTPUT ;
    USE SIGNAL ;
    PORT
      LAYER M4 ;
        RECT  21.516 81.552 21.6 81.576 ;
    END
  END q[490]
  PIN q[491]
    DIRECTION OUTPUT ;
    USE SIGNAL ;
    PORT
      LAYER M4 ;
        RECT  21.516 81.648 21.6 81.672 ;
    END
  END q[491]
  PIN q[492]
    DIRECTION OUTPUT ;
    USE SIGNAL ;
    PORT
      LAYER M4 ;
        RECT  21.516 81.744 21.6 81.768 ;
    END
  END q[492]
  PIN q[493]
    DIRECTION OUTPUT ;
    USE SIGNAL ;
    PORT
      LAYER M4 ;
        RECT  21.516 81.84 21.6 81.864 ;
    END
  END q[493]
  PIN q[494]
    DIRECTION OUTPUT ;
    USE SIGNAL ;
    PORT
      LAYER M4 ;
        RECT  21.516 81.936 21.6 81.96 ;
    END
  END q[494]
  PIN q[495]
    DIRECTION OUTPUT ;
    USE SIGNAL ;
    PORT
      LAYER M4 ;
        RECT  21.516 82.032 21.6 82.056 ;
    END
  END q[495]
  PIN q[496]
    DIRECTION OUTPUT ;
    USE SIGNAL ;
    PORT
      LAYER M4 ;
        RECT  21.516 82.128 21.6 82.152 ;
    END
  END q[496]
  PIN q[497]
    DIRECTION OUTPUT ;
    USE SIGNAL ;
    PORT
      LAYER M4 ;
        RECT  21.516 82.224 21.6 82.248 ;
    END
  END q[497]
  PIN q[498]
    DIRECTION OUTPUT ;
    USE SIGNAL ;
    PORT
      LAYER M4 ;
        RECT  21.516 82.32 21.6 82.344 ;
    END
  END q[498]
  PIN q[499]
    DIRECTION OUTPUT ;
    USE SIGNAL ;
    PORT
      LAYER M4 ;
        RECT  21.516 82.416 21.6 82.44 ;
    END
  END q[499]
  PIN q[49]
    DIRECTION OUTPUT ;
    USE SIGNAL ;
    PORT
      LAYER M4 ;
        RECT  21.516 66.096 21.6 66.12 ;
    END
  END q[49]
  PIN q[4]
    DIRECTION OUTPUT ;
    USE SIGNAL ;
    PORT
      LAYER M4 ;
        RECT  21.516 74.064 21.6 74.088 ;
    END
  END q[4]
  PIN q[500]
    DIRECTION OUTPUT ;
    USE SIGNAL ;
    PORT
      LAYER M4 ;
        RECT  21.516 82.512 21.6 82.536 ;
    END
  END q[500]
  PIN q[501]
    DIRECTION OUTPUT ;
    USE SIGNAL ;
    PORT
      LAYER M4 ;
        RECT  21.516 82.608 21.6 82.632 ;
    END
  END q[501]
  PIN q[502]
    DIRECTION OUTPUT ;
    USE SIGNAL ;
    PORT
      LAYER M4 ;
        RECT  21.516 82.704 21.6 82.728 ;
    END
  END q[502]
  PIN q[503]
    DIRECTION OUTPUT ;
    USE SIGNAL ;
    PORT
      LAYER M4 ;
        RECT  21.516 82.8 21.6 82.824 ;
    END
  END q[503]
  PIN q[504]
    DIRECTION OUTPUT ;
    USE SIGNAL ;
    PORT
      LAYER M4 ;
        RECT  21.516 82.896 21.6 82.92 ;
    END
  END q[504]
  PIN q[505]
    DIRECTION OUTPUT ;
    USE SIGNAL ;
    PORT
      LAYER M4 ;
        RECT  21.516 82.992 21.6 83.016 ;
    END
  END q[505]
  PIN q[506]
    DIRECTION OUTPUT ;
    USE SIGNAL ;
    PORT
      LAYER M4 ;
        RECT  21.516 83.088 21.6 83.112 ;
    END
  END q[506]
  PIN q[507]
    DIRECTION OUTPUT ;
    USE SIGNAL ;
    PORT
      LAYER M4 ;
        RECT  21.516 83.184 21.6 83.208 ;
    END
  END q[507]
  PIN q[508]
    DIRECTION OUTPUT ;
    USE SIGNAL ;
    PORT
      LAYER M4 ;
        RECT  21.516 83.28 21.6 83.304 ;
    END
  END q[508]
  PIN q[509]
    DIRECTION OUTPUT ;
    USE SIGNAL ;
    PORT
      LAYER M4 ;
        RECT  21.516 83.376 21.6 83.4 ;
    END
  END q[509]
  PIN q[50]
    DIRECTION OUTPUT ;
    USE SIGNAL ;
    PORT
      LAYER M4 ;
        RECT  21.516 66.192 21.6 66.216 ;
    END
  END q[50]
  PIN q[510]
    DIRECTION OUTPUT ;
    USE SIGNAL ;
    PORT
      LAYER M4 ;
        RECT  21.516 83.472 21.6 83.496 ;
    END
  END q[510]
  PIN q[511]
    DIRECTION OUTPUT ;
    USE SIGNAL ;
    PORT
      LAYER M4 ;
        RECT  21.516 83.568 21.6 83.592 ;
    END
  END q[511]
  PIN q[51]
    DIRECTION OUTPUT ;
    USE SIGNAL ;
    PORT
      LAYER M4 ;
        RECT  21.516 66.288 21.6 66.312 ;
    END
  END q[51]
  PIN q[52]
    DIRECTION OUTPUT ;
    USE SIGNAL ;
    PORT
      LAYER M4 ;
        RECT  21.516 66.384 21.6 66.408 ;
    END
  END q[52]
  PIN q[53]
    DIRECTION OUTPUT ;
    USE SIGNAL ;
    PORT
      LAYER M4 ;
        RECT  21.516 66.48 21.6 66.504 ;
    END
  END q[53]
  PIN q[54]
    DIRECTION OUTPUT ;
    USE SIGNAL ;
    PORT
      LAYER M4 ;
        RECT  21.516 66.576 21.6 66.6 ;
    END
  END q[54]
  PIN q[55]
    DIRECTION OUTPUT ;
    USE SIGNAL ;
    PORT
      LAYER M4 ;
        RECT  21.516 66.672 21.6 66.696 ;
    END
  END q[55]
  PIN q[56]
    DIRECTION OUTPUT ;
    USE SIGNAL ;
    PORT
      LAYER M4 ;
        RECT  21.516 66.768 21.6 66.792 ;
    END
  END q[56]
  PIN q[57]
    DIRECTION OUTPUT ;
    USE SIGNAL ;
    PORT
      LAYER M4 ;
        RECT  21.516 66.864 21.6 66.888 ;
    END
  END q[57]
  PIN q[58]
    DIRECTION OUTPUT ;
    USE SIGNAL ;
    PORT
      LAYER M4 ;
        RECT  21.516 66.96 21.6 66.984 ;
    END
  END q[58]
  PIN q[59]
    DIRECTION OUTPUT ;
    USE SIGNAL ;
    PORT
      LAYER M4 ;
        RECT  21.516 67.056 21.6 67.08 ;
    END
  END q[59]
  PIN q[5]
    DIRECTION OUTPUT ;
    USE SIGNAL ;
    PORT
      LAYER M4 ;
        RECT  21.516 74.16 21.6 74.184 ;
    END
  END q[5]
  PIN q[60]
    DIRECTION OUTPUT ;
    USE SIGNAL ;
    PORT
      LAYER M4 ;
        RECT  21.516 67.152 21.6 67.176 ;
    END
  END q[60]
  PIN q[61]
    DIRECTION OUTPUT ;
    USE SIGNAL ;
    PORT
      LAYER M4 ;
        RECT  21.516 67.248 21.6 67.272 ;
    END
  END q[61]
  PIN q[62]
    DIRECTION OUTPUT ;
    USE SIGNAL ;
    PORT
      LAYER M4 ;
        RECT  21.516 67.344 21.6 67.368 ;
    END
  END q[62]
  PIN q[63]
    DIRECTION OUTPUT ;
    USE SIGNAL ;
    PORT
      LAYER M4 ;
        RECT  21.516 67.44 21.6 67.464 ;
    END
  END q[63]
  PIN q[64]
    DIRECTION OUTPUT ;
    USE SIGNAL ;
    PORT
      LAYER M4 ;
        RECT  21.516 67.536 21.6 67.56 ;
    END
  END q[64]
  PIN q[65]
    DIRECTION OUTPUT ;
    USE SIGNAL ;
    PORT
      LAYER M4 ;
        RECT  21.516 67.632 21.6 67.656 ;
    END
  END q[65]
  PIN q[66]
    DIRECTION OUTPUT ;
    USE SIGNAL ;
    PORT
      LAYER M4 ;
        RECT  21.516 67.728 21.6 67.752 ;
    END
  END q[66]
  PIN q[67]
    DIRECTION OUTPUT ;
    USE SIGNAL ;
    PORT
      LAYER M4 ;
        RECT  21.516 67.824 21.6 67.848 ;
    END
  END q[67]
  PIN q[68]
    DIRECTION OUTPUT ;
    USE SIGNAL ;
    PORT
      LAYER M4 ;
        RECT  21.516 67.92 21.6 67.944 ;
    END
  END q[68]
  PIN q[69]
    DIRECTION OUTPUT ;
    USE SIGNAL ;
    PORT
      LAYER M4 ;
        RECT  21.516 68.016 21.6 68.04 ;
    END
  END q[69]
  PIN q[6]
    DIRECTION OUTPUT ;
    USE SIGNAL ;
    PORT
      LAYER M4 ;
        RECT  21.516 74.256 21.6 74.28 ;
    END
  END q[6]
  PIN q[70]
    DIRECTION OUTPUT ;
    USE SIGNAL ;
    PORT
      LAYER M4 ;
        RECT  21.516 68.112 21.6 68.136 ;
    END
  END q[70]
  PIN q[71]
    DIRECTION OUTPUT ;
    USE SIGNAL ;
    PORT
      LAYER M4 ;
        RECT  21.516 68.208 21.6 68.232 ;
    END
  END q[71]
  PIN q[72]
    DIRECTION OUTPUT ;
    USE SIGNAL ;
    PORT
      LAYER M4 ;
        RECT  21.516 68.304 21.6 68.328 ;
    END
  END q[72]
  PIN q[73]
    DIRECTION OUTPUT ;
    USE SIGNAL ;
    PORT
      LAYER M4 ;
        RECT  21.516 68.4 21.6 68.424 ;
    END
  END q[73]
  PIN q[74]
    DIRECTION OUTPUT ;
    USE SIGNAL ;
    PORT
      LAYER M4 ;
        RECT  21.516 68.496 21.6 68.52 ;
    END
  END q[74]
  PIN q[75]
    DIRECTION OUTPUT ;
    USE SIGNAL ;
    PORT
      LAYER M4 ;
        RECT  21.516 68.592 21.6 68.616 ;
    END
  END q[75]
  PIN q[76]
    DIRECTION OUTPUT ;
    USE SIGNAL ;
    PORT
      LAYER M4 ;
        RECT  21.516 68.688 21.6 68.712 ;
    END
  END q[76]
  PIN q[77]
    DIRECTION OUTPUT ;
    USE SIGNAL ;
    PORT
      LAYER M4 ;
        RECT  21.516 68.784 21.6 68.808 ;
    END
  END q[77]
  PIN q[78]
    DIRECTION OUTPUT ;
    USE SIGNAL ;
    PORT
      LAYER M4 ;
        RECT  21.516 68.88 21.6 68.904 ;
    END
  END q[78]
  PIN q[79]
    DIRECTION OUTPUT ;
    USE SIGNAL ;
    PORT
      LAYER M4 ;
        RECT  21.516 68.976 21.6 69 ;
    END
  END q[79]
  PIN q[7]
    DIRECTION OUTPUT ;
    USE SIGNAL ;
    PORT
      LAYER M4 ;
        RECT  21.516 74.352 21.6 74.376 ;
    END
  END q[7]
  PIN q[80]
    DIRECTION OUTPUT ;
    USE SIGNAL ;
    PORT
      LAYER M4 ;
        RECT  21.516 69.072 21.6 69.096 ;
    END
  END q[80]
  PIN q[81]
    DIRECTION OUTPUT ;
    USE SIGNAL ;
    PORT
      LAYER M4 ;
        RECT  21.516 69.168 21.6 69.192 ;
    END
  END q[81]
  PIN q[82]
    DIRECTION OUTPUT ;
    USE SIGNAL ;
    PORT
      LAYER M4 ;
        RECT  21.516 69.264 21.6 69.288 ;
    END
  END q[82]
  PIN q[83]
    DIRECTION OUTPUT ;
    USE SIGNAL ;
    PORT
      LAYER M4 ;
        RECT  21.516 69.36 21.6 69.384 ;
    END
  END q[83]
  PIN q[84]
    DIRECTION OUTPUT ;
    USE SIGNAL ;
    PORT
      LAYER M4 ;
        RECT  21.516 69.456 21.6 69.48 ;
    END
  END q[84]
  PIN q[85]
    DIRECTION OUTPUT ;
    USE SIGNAL ;
    PORT
      LAYER M4 ;
        RECT  21.516 69.552 21.6 69.576 ;
    END
  END q[85]
  PIN q[86]
    DIRECTION OUTPUT ;
    USE SIGNAL ;
    PORT
      LAYER M4 ;
        RECT  21.516 69.648 21.6 69.672 ;
    END
  END q[86]
  PIN q[87]
    DIRECTION OUTPUT ;
    USE SIGNAL ;
    PORT
      LAYER M4 ;
        RECT  21.516 69.744 21.6 69.768 ;
    END
  END q[87]
  PIN q[88]
    DIRECTION OUTPUT ;
    USE SIGNAL ;
    PORT
      LAYER M4 ;
        RECT  21.516 69.84 21.6 69.864 ;
    END
  END q[88]
  PIN q[89]
    DIRECTION OUTPUT ;
    USE SIGNAL ;
    PORT
      LAYER M4 ;
        RECT  21.516 69.936 21.6 69.96 ;
    END
  END q[89]
  PIN q[8]
    DIRECTION OUTPUT ;
    USE SIGNAL ;
    PORT
      LAYER M4 ;
        RECT  21.516 74.448 21.6 74.472 ;
    END
  END q[8]
  PIN q[90]
    DIRECTION OUTPUT ;
    USE SIGNAL ;
    PORT
      LAYER M4 ;
        RECT  21.516 70.032 21.6 70.056 ;
    END
  END q[90]
  PIN q[91]
    DIRECTION OUTPUT ;
    USE SIGNAL ;
    PORT
      LAYER M4 ;
        RECT  21.516 70.128 21.6 70.152 ;
    END
  END q[91]
  PIN q[92]
    DIRECTION OUTPUT ;
    USE SIGNAL ;
    PORT
      LAYER M4 ;
        RECT  21.516 70.224 21.6 70.248 ;
    END
  END q[92]
  PIN q[93]
    DIRECTION OUTPUT ;
    USE SIGNAL ;
    PORT
      LAYER M4 ;
        RECT  21.516 70.32 21.6 70.344 ;
    END
  END q[93]
  PIN q[94]
    DIRECTION OUTPUT ;
    USE SIGNAL ;
    PORT
      LAYER M4 ;
        RECT  21.516 70.416 21.6 70.44 ;
    END
  END q[94]
  PIN q[95]
    DIRECTION OUTPUT ;
    USE SIGNAL ;
    PORT
      LAYER M4 ;
        RECT  21.516 70.512 21.6 70.536 ;
    END
  END q[95]
  PIN q[96]
    DIRECTION OUTPUT ;
    USE SIGNAL ;
    PORT
      LAYER M4 ;
        RECT  21.516 70.608 21.6 70.632 ;
    END
  END q[96]
  PIN q[97]
    DIRECTION OUTPUT ;
    USE SIGNAL ;
    PORT
      LAYER M4 ;
        RECT  21.516 70.704 21.6 70.728 ;
    END
  END q[97]
  PIN q[98]
    DIRECTION OUTPUT ;
    USE SIGNAL ;
    PORT
      LAYER M4 ;
        RECT  21.516 70.8 21.6 70.824 ;
    END
  END q[98]
  PIN q[99]
    DIRECTION OUTPUT ;
    USE SIGNAL ;
    PORT
      LAYER M4 ;
        RECT  21.516 70.896 21.6 70.92 ;
    END
  END q[99]
  PIN q[9]
    DIRECTION OUTPUT ;
    USE SIGNAL ;
    PORT
      LAYER M4 ;
        RECT  21.516 74.544 21.6 74.568 ;
    END
  END q[9]
  PIN VDD
    DIRECTION INOUT ;
    USE POWER ;
    PORT
      LAYER M5 ;
        RECT  18.792 2.151 18.912 127.449 ;
        RECT  16.092 2.151 16.212 127.449 ;
        RECT  13.392 2.151 13.512 127.449 ;
        RECT  10.692 2.151 10.812 127.449 ;
        RECT  7.992 2.151 8.112 127.449 ;
        RECT  5.292 2.151 5.412 127.449 ;
        RECT  2.592 2.151 2.712 127.449 ;
    END
  END VDD
  PIN VSS
    DIRECTION INOUT ;
    USE GROUND ;
    PORT
      LAYER M5 ;
        RECT  18.6 2.137 18.72 127.463 ;
        RECT  15.9 2.137 16.02 127.463 ;
        RECT  13.2 2.137 13.32 127.463 ;
        RECT  10.5 2.137 10.62 127.463 ;
        RECT  7.8 2.137 7.92 127.463 ;
        RECT  5.1 2.137 5.22 127.463 ;
        RECT  2.4 2.137 2.52 127.463 ;
    END
  END VSS
  # OT_OBS_CLOSED layer=M5 d_um=1.536 added=55
  OBS
    LAYER RVTN ;
     RECT  2.16 2.16 19.44 2.295 ;
     RECT  2.16 2.565 19.44 2.835 ;
     RECT  2.16 3.105 19.44 3.375 ;
     RECT  2.16 3.645 19.44 3.915 ;
     RECT  2.16 4.185 19.44 4.455 ;
     RECT  2.16 4.725 19.44 4.995 ;
     RECT  2.16 5.265 19.44 5.535 ;
     RECT  2.16 5.805 19.44 6.075 ;
     RECT  2.16 6.345 19.44 6.615 ;
     RECT  2.16 6.885 19.44 7.155 ;
     RECT  2.16 7.425 19.44 7.695 ;
     RECT  2.16 7.965 19.44 8.235 ;
     RECT  2.16 8.505 19.44 8.775 ;
     RECT  2.16 9.045 19.44 9.315 ;
     RECT  2.16 9.585 19.44 9.855 ;
     RECT  2.16 10.125 19.44 10.395 ;
     RECT  2.16 10.665 19.44 10.935 ;
     RECT  2.16 11.205 19.44 11.475 ;
     RECT  2.16 11.745 19.44 12.015 ;
     RECT  2.16 12.285 19.44 12.555 ;
     RECT  2.16 12.825 19.44 13.095 ;
     RECT  2.16 13.365 19.44 13.635 ;
     RECT  2.16 13.905 19.44 14.175 ;
     RECT  2.16 14.445 19.44 14.715 ;
     RECT  2.16 14.985 19.44 15.255 ;
     RECT  2.16 15.525 19.44 15.795 ;
     RECT  2.16 16.065 19.44 16.335 ;
     RECT  2.16 16.605 19.44 16.875 ;
     RECT  2.16 17.145 19.44 17.415 ;
     RECT  2.16 17.685 19.44 17.955 ;
     RECT  2.16 18.225 19.44 18.495 ;
     RECT  2.16 18.765 19.44 19.035 ;
     RECT  2.16 19.305 19.44 19.575 ;
     RECT  2.16 19.845 19.44 20.115 ;
     RECT  2.16 20.385 19.44 20.655 ;
     RECT  2.16 20.925 19.44 21.195 ;
     RECT  2.16 21.465 19.44 21.735 ;
     RECT  2.16 22.005 19.44 22.275 ;
     RECT  2.16 22.545 19.44 22.815 ;
     RECT  2.16 23.085 19.44 23.355 ;
     RECT  2.16 23.625 19.44 23.895 ;
     RECT  2.16 24.165 19.44 24.435 ;
     RECT  2.16 24.705 19.44 24.975 ;
     RECT  2.16 25.245 19.44 25.515 ;
     RECT  2.16 25.785 19.44 26.055 ;
     RECT  2.16 26.325 19.44 26.595 ;
     RECT  2.16 26.865 19.44 27.135 ;
     RECT  2.16 27.405 19.44 27.675 ;
     RECT  2.16 27.945 19.44 28.215 ;
     RECT  2.16 28.485 19.44 28.755 ;
     RECT  2.16 29.025 19.44 29.295 ;
     RECT  2.16 29.565 19.44 29.835 ;
     RECT  2.16 30.105 19.44 30.375 ;
     RECT  2.16 30.645 19.44 30.915 ;
     RECT  2.16 31.185 19.44 31.455 ;
     RECT  2.16 31.725 19.44 31.995 ;
     RECT  2.16 32.265 19.44 32.535 ;
     RECT  2.16 32.805 19.44 33.075 ;
     RECT  2.16 33.345 19.44 33.615 ;
     RECT  2.16 33.885 19.44 34.155 ;
     RECT  2.16 34.425 19.44 34.695 ;
     RECT  2.16 34.965 19.44 35.235 ;
     RECT  2.16 35.505 19.44 35.775 ;
     RECT  2.16 36.045 19.44 36.315 ;
     RECT  2.16 36.585 19.44 36.855 ;
     RECT  2.16 37.125 19.44 37.395 ;
     RECT  2.16 37.665 19.44 37.935 ;
     RECT  2.16 38.205 19.44 38.475 ;
     RECT  2.16 38.745 19.44 39.015 ;
     RECT  2.16 39.285 19.44 39.555 ;
     RECT  2.16 39.825 19.44 40.095 ;
     RECT  2.16 40.365 19.44 40.635 ;
     RECT  2.16 40.905 19.44 41.175 ;
     RECT  2.16 41.445 19.44 41.715 ;
     RECT  2.16 41.985 19.44 42.255 ;
     RECT  2.16 42.525 19.44 42.795 ;
     RECT  2.16 43.065 19.44 43.335 ;
     RECT  2.16 43.605 19.44 43.875 ;
     RECT  2.16 44.145 19.44 44.415 ;
     RECT  2.16 44.685 19.44 44.955 ;
     RECT  2.16 45.225 19.44 45.495 ;
     RECT  2.16 45.765 19.44 46.035 ;
     RECT  2.16 46.305 19.44 46.575 ;
     RECT  2.16 46.845 19.44 47.115 ;
     RECT  2.16 47.385 19.44 47.655 ;
     RECT  2.16 47.925 19.44 48.195 ;
     RECT  2.16 48.465 19.44 48.735 ;
     RECT  2.16 49.005 19.44 49.275 ;
     RECT  2.16 49.545 19.44 49.815 ;
     RECT  2.16 50.085 19.44 50.355 ;
     RECT  2.16 50.625 19.44 50.895 ;
     RECT  2.16 51.165 19.44 51.435 ;
     RECT  2.16 51.705 19.44 51.975 ;
     RECT  2.16 52.245 19.44 52.515 ;
     RECT  2.16 52.785 19.44 53.055 ;
     RECT  2.16 53.325 19.44 53.595 ;
     RECT  2.16 53.865 19.44 54.135 ;
     RECT  2.16 54.405 19.44 54.675 ;
     RECT  2.16 54.945 19.44 55.215 ;
     RECT  2.16 55.485 19.44 55.755 ;
     RECT  2.16 56.025 19.44 56.295 ;
     RECT  2.16 56.565 19.44 56.835 ;
     RECT  2.16 57.105 19.44 57.375 ;
     RECT  2.16 57.645 19.44 57.915 ;
     RECT  2.16 58.185 19.44 58.455 ;
     RECT  2.16 58.725 19.44 58.995 ;
     RECT  2.16 59.265 19.44 59.535 ;
     RECT  2.16 59.805 19.44 60.075 ;
     RECT  2.16 60.345 19.44 60.615 ;
     RECT  2.16 60.885 19.44 61.155 ;
     RECT  2.16 61.425 19.44 61.695 ;
     RECT  2.16 61.965 19.44 62.235 ;
     RECT  2.16 62.505 19.44 62.775 ;
     RECT  2.16 63.045 19.44 63.315 ;
     RECT  2.16 63.585 19.44 63.855 ;
     RECT  2.16 64.125 19.44 64.395 ;
     RECT  2.16 64.665 19.44 64.935 ;
     RECT  2.16 65.205 19.44 65.475 ;
     RECT  2.16 65.745 19.44 66.015 ;
     RECT  2.16 66.285 19.44 66.555 ;
     RECT  2.16 66.825 19.44 67.095 ;
     RECT  2.16 67.365 19.44 67.635 ;
     RECT  2.16 67.905 19.44 68.175 ;
     RECT  2.16 68.445 19.44 68.715 ;
     RECT  2.16 68.985 19.44 69.255 ;
     RECT  2.16 69.525 19.44 69.795 ;
     RECT  2.16 70.065 19.44 70.335 ;
     RECT  2.16 70.605 19.44 70.875 ;
     RECT  2.16 71.145 19.44 71.415 ;
     RECT  2.16 71.685 19.44 71.955 ;
     RECT  2.16 72.225 19.44 72.495 ;
     RECT  2.16 72.765 19.44 73.035 ;
     RECT  2.16 73.305 19.44 73.575 ;
     RECT  2.16 73.845 19.44 74.115 ;
     RECT  2.16 74.385 19.44 74.655 ;
     RECT  2.16 74.925 19.44 75.195 ;
     RECT  2.16 75.465 19.44 75.735 ;
     RECT  2.16 76.005 19.44 76.275 ;
     RECT  2.16 76.545 19.44 76.815 ;
     RECT  2.16 77.085 19.44 77.355 ;
     RECT  2.16 77.625 19.44 77.895 ;
     RECT  2.16 78.165 19.44 78.435 ;
     RECT  2.16 78.705 19.44 78.975 ;
     RECT  2.16 79.245 19.44 79.515 ;
     RECT  2.16 79.785 19.44 80.055 ;
     RECT  2.16 80.325 19.44 80.595 ;
     RECT  2.16 80.865 19.44 81.135 ;
     RECT  2.16 81.405 19.44 81.675 ;
     RECT  2.16 81.945 19.44 82.215 ;
     RECT  2.16 82.485 19.44 82.755 ;
     RECT  2.16 83.025 19.44 83.295 ;
     RECT  2.16 83.565 19.44 83.835 ;
     RECT  2.16 84.105 19.44 84.375 ;
     RECT  2.16 84.645 19.44 84.915 ;
     RECT  2.16 85.185 19.44 85.455 ;
     RECT  2.16 85.725 19.44 85.995 ;
     RECT  2.16 86.265 19.44 86.535 ;
     RECT  2.16 86.805 19.44 87.075 ;
     RECT  2.16 87.345 19.44 87.615 ;
     RECT  2.16 87.885 19.44 88.155 ;
     RECT  2.16 88.425 19.44 88.695 ;
     RECT  2.16 88.965 19.44 89.235 ;
     RECT  2.16 89.505 19.44 89.775 ;
     RECT  2.16 90.045 19.44 90.315 ;
     RECT  2.16 90.585 19.44 90.855 ;
     RECT  2.16 91.125 19.44 91.395 ;
     RECT  2.16 91.665 19.44 91.935 ;
     RECT  2.16 92.205 19.44 92.475 ;
     RECT  2.16 92.745 19.44 93.015 ;
     RECT  2.16 93.285 19.44 93.555 ;
     RECT  2.16 93.825 19.44 94.095 ;
     RECT  2.16 94.365 19.44 94.635 ;
     RECT  2.16 94.905 19.44 95.175 ;
     RECT  2.16 95.445 19.44 95.715 ;
     RECT  2.16 95.985 19.44 96.255 ;
     RECT  2.16 96.525 19.44 96.795 ;
     RECT  2.16 97.065 19.44 97.335 ;
     RECT  2.16 97.605 19.44 97.875 ;
     RECT  2.16 98.145 19.44 98.415 ;
     RECT  2.16 98.685 19.44 98.955 ;
     RECT  2.16 99.225 19.44 99.495 ;
     RECT  2.16 99.765 19.44 100.035 ;
     RECT  2.16 100.305 19.44 100.575 ;
     RECT  2.16 100.845 19.44 101.115 ;
     RECT  2.16 101.385 19.44 101.655 ;
     RECT  2.16 101.925 19.44 102.195 ;
     RECT  2.16 102.465 19.44 102.735 ;
     RECT  2.16 103.005 19.44 103.275 ;
     RECT  2.16 103.545 19.44 103.815 ;
     RECT  2.16 104.085 19.44 104.355 ;
     RECT  2.16 104.625 19.44 104.895 ;
     RECT  2.16 105.165 19.44 105.435 ;
     RECT  2.16 105.705 19.44 105.975 ;
     RECT  2.16 106.245 19.44 106.515 ;
     RECT  2.16 106.785 19.44 107.055 ;
     RECT  2.16 107.325 19.44 107.595 ;
     RECT  2.16 107.865 19.44 108.135 ;
     RECT  2.16 108.405 19.44 108.675 ;
     RECT  2.16 108.945 19.44 109.215 ;
     RECT  2.16 109.485 19.44 109.755 ;
     RECT  2.16 110.025 19.44 110.295 ;
     RECT  2.16 110.565 19.44 110.835 ;
     RECT  2.16 111.105 19.44 111.375 ;
     RECT  2.16 111.645 19.44 111.915 ;
     RECT  2.16 112.185 19.44 112.455 ;
     RECT  2.16 112.725 19.44 112.995 ;
     RECT  2.16 113.265 19.44 113.535 ;
     RECT  2.16 113.805 19.44 114.075 ;
     RECT  2.16 114.345 19.44 114.615 ;
     RECT  2.16 114.885 19.44 115.155 ;
     RECT  2.16 115.425 19.44 115.695 ;
     RECT  2.16 115.965 19.44 116.235 ;
     RECT  2.16 116.505 19.44 116.775 ;
     RECT  2.16 117.045 19.44 117.315 ;
     RECT  2.16 117.585 19.44 117.855 ;
     RECT  2.16 118.125 19.44 118.395 ;
     RECT  2.16 118.665 19.44 118.935 ;
     RECT  2.16 119.205 19.44 119.475 ;
     RECT  2.16 119.745 19.44 120.015 ;
     RECT  2.16 120.285 19.44 120.555 ;
     RECT  2.16 120.825 19.44 121.095 ;
     RECT  2.16 121.365 19.44 121.635 ;
     RECT  2.16 121.905 19.44 122.175 ;
     RECT  2.16 122.445 19.44 122.715 ;
     RECT  2.16 122.985 19.44 123.255 ;
     RECT  2.16 123.525 19.44 123.795 ;
     RECT  2.16 124.065 19.44 124.335 ;
     RECT  2.16 124.605 19.44 124.875 ;
     RECT  2.16 125.145 19.44 125.415 ;
     RECT  2.16 125.685 19.44 125.955 ;
     RECT  2.16 126.225 19.44 126.495 ;
     RECT  2.16 126.765 19.44 127.035 ;
     RECT  2.16 127.305 19.44 127.44 ;
    LAYER RVTP ;
     RECT  2.16 2.295 19.44 2.565 ;
     RECT  2.16 2.835 19.44 3.105 ;
     RECT  2.16 3.375 19.44 3.645 ;
     RECT  2.16 3.915 19.44 4.185 ;
     RECT  2.16 4.455 19.44 4.725 ;
     RECT  2.16 4.995 19.44 5.265 ;
     RECT  2.16 5.535 19.44 5.805 ;
     RECT  2.16 6.075 19.44 6.345 ;
     RECT  2.16 6.615 19.44 6.885 ;
     RECT  2.16 7.155 19.44 7.425 ;
     RECT  2.16 7.695 19.44 7.965 ;
     RECT  2.16 8.235 19.44 8.505 ;
     RECT  2.16 8.775 19.44 9.045 ;
     RECT  2.16 9.315 19.44 9.585 ;
     RECT  2.16 9.855 19.44 10.125 ;
     RECT  2.16 10.395 19.44 10.665 ;
     RECT  2.16 10.935 19.44 11.205 ;
     RECT  2.16 11.475 19.44 11.745 ;
     RECT  2.16 12.015 19.44 12.285 ;
     RECT  2.16 12.555 19.44 12.825 ;
     RECT  2.16 13.095 19.44 13.365 ;
     RECT  2.16 13.635 19.44 13.905 ;
     RECT  2.16 14.175 19.44 14.445 ;
     RECT  2.16 14.715 19.44 14.985 ;
     RECT  2.16 15.255 19.44 15.525 ;
     RECT  2.16 15.795 19.44 16.065 ;
     RECT  2.16 16.335 19.44 16.605 ;
     RECT  2.16 16.875 19.44 17.145 ;
     RECT  2.16 17.415 19.44 17.685 ;
     RECT  2.16 17.955 19.44 18.225 ;
     RECT  2.16 18.495 19.44 18.765 ;
     RECT  2.16 19.035 19.44 19.305 ;
     RECT  2.16 19.575 19.44 19.845 ;
     RECT  2.16 20.115 19.44 20.385 ;
     RECT  2.16 20.655 19.44 20.925 ;
     RECT  2.16 21.195 19.44 21.465 ;
     RECT  2.16 21.735 19.44 22.005 ;
     RECT  2.16 22.275 19.44 22.545 ;
     RECT  2.16 22.815 19.44 23.085 ;
     RECT  2.16 23.355 19.44 23.625 ;
     RECT  2.16 23.895 19.44 24.165 ;
     RECT  2.16 24.435 19.44 24.705 ;
     RECT  2.16 24.975 19.44 25.245 ;
     RECT  2.16 25.515 19.44 25.785 ;
     RECT  2.16 26.055 19.44 26.325 ;
     RECT  2.16 26.595 19.44 26.865 ;
     RECT  2.16 27.135 19.44 27.405 ;
     RECT  2.16 27.675 19.44 27.945 ;
     RECT  2.16 28.215 19.44 28.485 ;
     RECT  2.16 28.755 19.44 29.025 ;
     RECT  2.16 29.295 19.44 29.565 ;
     RECT  2.16 29.835 19.44 30.105 ;
     RECT  2.16 30.375 19.44 30.645 ;
     RECT  2.16 30.915 19.44 31.185 ;
     RECT  2.16 31.455 19.44 31.725 ;
     RECT  2.16 31.995 19.44 32.265 ;
     RECT  2.16 32.535 19.44 32.805 ;
     RECT  2.16 33.075 19.44 33.345 ;
     RECT  2.16 33.615 19.44 33.885 ;
     RECT  2.16 34.155 19.44 34.425 ;
     RECT  2.16 34.695 19.44 34.965 ;
     RECT  2.16 35.235 19.44 35.505 ;
     RECT  2.16 35.775 19.44 36.045 ;
     RECT  2.16 36.315 19.44 36.585 ;
     RECT  2.16 36.855 19.44 37.125 ;
     RECT  2.16 37.395 19.44 37.665 ;
     RECT  2.16 37.935 19.44 38.205 ;
     RECT  2.16 38.475 19.44 38.745 ;
     RECT  2.16 39.015 19.44 39.285 ;
     RECT  2.16 39.555 19.44 39.825 ;
     RECT  2.16 40.095 19.44 40.365 ;
     RECT  2.16 40.635 19.44 40.905 ;
     RECT  2.16 41.175 19.44 41.445 ;
     RECT  2.16 41.715 19.44 41.985 ;
     RECT  2.16 42.255 19.44 42.525 ;
     RECT  2.16 42.795 19.44 43.065 ;
     RECT  2.16 43.335 19.44 43.605 ;
     RECT  2.16 43.875 19.44 44.145 ;
     RECT  2.16 44.415 19.44 44.685 ;
     RECT  2.16 44.955 19.44 45.225 ;
     RECT  2.16 45.495 19.44 45.765 ;
     RECT  2.16 46.035 19.44 46.305 ;
     RECT  2.16 46.575 19.44 46.845 ;
     RECT  2.16 47.115 19.44 47.385 ;
     RECT  2.16 47.655 19.44 47.925 ;
     RECT  2.16 48.195 19.44 48.465 ;
     RECT  2.16 48.735 19.44 49.005 ;
     RECT  2.16 49.275 19.44 49.545 ;
     RECT  2.16 49.815 19.44 50.085 ;
     RECT  2.16 50.355 19.44 50.625 ;
     RECT  2.16 50.895 19.44 51.165 ;
     RECT  2.16 51.435 19.44 51.705 ;
     RECT  2.16 51.975 19.44 52.245 ;
     RECT  2.16 52.515 19.44 52.785 ;
     RECT  2.16 53.055 19.44 53.325 ;
     RECT  2.16 53.595 19.44 53.865 ;
     RECT  2.16 54.135 19.44 54.405 ;
     RECT  2.16 54.675 19.44 54.945 ;
     RECT  2.16 55.215 19.44 55.485 ;
     RECT  2.16 55.755 19.44 56.025 ;
     RECT  2.16 56.295 19.44 56.565 ;
     RECT  2.16 56.835 19.44 57.105 ;
     RECT  2.16 57.375 19.44 57.645 ;
     RECT  2.16 57.915 19.44 58.185 ;
     RECT  2.16 58.455 19.44 58.725 ;
     RECT  2.16 58.995 19.44 59.265 ;
     RECT  2.16 59.535 19.44 59.805 ;
     RECT  2.16 60.075 19.44 60.345 ;
     RECT  2.16 60.615 19.44 60.885 ;
     RECT  2.16 61.155 19.44 61.425 ;
     RECT  2.16 61.695 19.44 61.965 ;
     RECT  2.16 62.235 19.44 62.505 ;
     RECT  2.16 62.775 19.44 63.045 ;
     RECT  2.16 63.315 19.44 63.585 ;
     RECT  2.16 63.855 19.44 64.125 ;
     RECT  2.16 64.395 19.44 64.665 ;
     RECT  2.16 64.935 19.44 65.205 ;
     RECT  2.16 65.475 19.44 65.745 ;
     RECT  2.16 66.015 19.44 66.285 ;
     RECT  2.16 66.555 19.44 66.825 ;
     RECT  2.16 67.095 19.44 67.365 ;
     RECT  2.16 67.635 19.44 67.905 ;
     RECT  2.16 68.175 19.44 68.445 ;
     RECT  2.16 68.715 19.44 68.985 ;
     RECT  2.16 69.255 19.44 69.525 ;
     RECT  2.16 69.795 19.44 70.065 ;
     RECT  2.16 70.335 19.44 70.605 ;
     RECT  2.16 70.875 19.44 71.145 ;
     RECT  2.16 71.415 19.44 71.685 ;
     RECT  2.16 71.955 19.44 72.225 ;
     RECT  2.16 72.495 19.44 72.765 ;
     RECT  2.16 73.035 19.44 73.305 ;
     RECT  2.16 73.575 19.44 73.845 ;
     RECT  2.16 74.115 19.44 74.385 ;
     RECT  2.16 74.655 19.44 74.925 ;
     RECT  2.16 75.195 19.44 75.465 ;
     RECT  2.16 75.735 19.44 76.005 ;
     RECT  2.16 76.275 19.44 76.545 ;
     RECT  2.16 76.815 19.44 77.085 ;
     RECT  2.16 77.355 19.44 77.625 ;
     RECT  2.16 77.895 19.44 78.165 ;
     RECT  2.16 78.435 19.44 78.705 ;
     RECT  2.16 78.975 19.44 79.245 ;
     RECT  2.16 79.515 19.44 79.785 ;
     RECT  2.16 80.055 19.44 80.325 ;
     RECT  2.16 80.595 19.44 80.865 ;
     RECT  2.16 81.135 19.44 81.405 ;
     RECT  2.16 81.675 19.44 81.945 ;
     RECT  2.16 82.215 19.44 82.485 ;
     RECT  2.16 82.755 19.44 83.025 ;
     RECT  2.16 83.295 19.44 83.565 ;
     RECT  2.16 83.835 19.44 84.105 ;
     RECT  2.16 84.375 19.44 84.645 ;
     RECT  2.16 84.915 19.44 85.185 ;
     RECT  2.16 85.455 19.44 85.725 ;
     RECT  2.16 85.995 19.44 86.265 ;
     RECT  2.16 86.535 19.44 86.805 ;
     RECT  2.16 87.075 19.44 87.345 ;
     RECT  2.16 87.615 19.44 87.885 ;
     RECT  2.16 88.155 19.44 88.425 ;
     RECT  2.16 88.695 19.44 88.965 ;
     RECT  2.16 89.235 19.44 89.505 ;
     RECT  2.16 89.775 19.44 90.045 ;
     RECT  2.16 90.315 19.44 90.585 ;
     RECT  2.16 90.855 19.44 91.125 ;
     RECT  2.16 91.395 19.44 91.665 ;
     RECT  2.16 91.935 19.44 92.205 ;
     RECT  2.16 92.475 19.44 92.745 ;
     RECT  2.16 93.015 19.44 93.285 ;
     RECT  2.16 93.555 19.44 93.825 ;
     RECT  2.16 94.095 19.44 94.365 ;
     RECT  2.16 94.635 19.44 94.905 ;
     RECT  2.16 95.175 19.44 95.445 ;
     RECT  2.16 95.715 19.44 95.985 ;
     RECT  2.16 96.255 19.44 96.525 ;
     RECT  2.16 96.795 19.44 97.065 ;
     RECT  2.16 97.335 19.44 97.605 ;
     RECT  2.16 97.875 19.44 98.145 ;
     RECT  2.16 98.415 19.44 98.685 ;
     RECT  2.16 98.955 19.44 99.225 ;
     RECT  2.16 99.495 19.44 99.765 ;
     RECT  2.16 100.035 19.44 100.305 ;
     RECT  2.16 100.575 19.44 100.845 ;
     RECT  2.16 101.115 19.44 101.385 ;
     RECT  2.16 101.655 19.44 101.925 ;
     RECT  2.16 102.195 19.44 102.465 ;
     RECT  2.16 102.735 19.44 103.005 ;
     RECT  2.16 103.275 19.44 103.545 ;
     RECT  2.16 103.815 19.44 104.085 ;
     RECT  2.16 104.355 19.44 104.625 ;
     RECT  2.16 104.895 19.44 105.165 ;
     RECT  2.16 105.435 19.44 105.705 ;
     RECT  2.16 105.975 19.44 106.245 ;
     RECT  2.16 106.515 19.44 106.785 ;
     RECT  2.16 107.055 19.44 107.325 ;
     RECT  2.16 107.595 19.44 107.865 ;
     RECT  2.16 108.135 19.44 108.405 ;
     RECT  2.16 108.675 19.44 108.945 ;
     RECT  2.16 109.215 19.44 109.485 ;
     RECT  2.16 109.755 19.44 110.025 ;
     RECT  2.16 110.295 19.44 110.565 ;
     RECT  2.16 110.835 19.44 111.105 ;
     RECT  2.16 111.375 19.44 111.645 ;
     RECT  2.16 111.915 19.44 112.185 ;
     RECT  2.16 112.455 19.44 112.725 ;
     RECT  2.16 112.995 19.44 113.265 ;
     RECT  2.16 113.535 19.44 113.805 ;
     RECT  2.16 114.075 19.44 114.345 ;
     RECT  2.16 114.615 19.44 114.885 ;
     RECT  2.16 115.155 19.44 115.425 ;
     RECT  2.16 115.695 19.44 115.965 ;
     RECT  2.16 116.235 19.44 116.505 ;
     RECT  2.16 116.775 19.44 117.045 ;
     RECT  2.16 117.315 19.44 117.585 ;
     RECT  2.16 117.855 19.44 118.125 ;
     RECT  2.16 118.395 19.44 118.665 ;
     RECT  2.16 118.935 19.44 119.205 ;
     RECT  2.16 119.475 19.44 119.745 ;
     RECT  2.16 120.015 19.44 120.285 ;
     RECT  2.16 120.555 19.44 120.825 ;
     RECT  2.16 121.095 19.44 121.365 ;
     RECT  2.16 121.635 19.44 121.905 ;
     RECT  2.16 122.175 19.44 122.445 ;
     RECT  2.16 122.715 19.44 122.985 ;
     RECT  2.16 123.255 19.44 123.525 ;
     RECT  2.16 123.795 19.44 124.065 ;
     RECT  2.16 124.335 19.44 124.605 ;
     RECT  2.16 124.875 19.44 125.145 ;
     RECT  2.16 125.415 19.44 125.685 ;
     RECT  2.16 125.955 19.44 126.225 ;
     RECT  2.16 126.495 19.44 126.765 ;
     RECT  2.16 127.035 19.44 127.305 ;
    LAYER M1 ;
     RECT  2.16 2.151 19.44 127.449 ;
    LAYER M2 ;
     RECT  0.031 71.001 0.103 71.019 ;
     RECT  0.175 78.102 0.211 78.12 ;
     RECT  0.103 70.92 0.239 71.172 ;
     RECT  0.139 82.026 0.239 82.314 ;
     RECT  0.239 71.001 0.275 71.172 ;
     RECT  0.103 59.58 0.311 59.598 ;
     RECT  0.103 43.812 0.347 43.83 ;
     RECT  0.211 47.736 0.347 47.754 ;
     RECT  0.103 63.9 0.347 64.188 ;
     RECT  0.275 71.001 0.347 71.1 ;
     RECT  0.211 78.102 0.347 78.309 ;
     RECT  0.239 82.296 0.347 82.314 ;
     RECT  0.103 84.312 0.463 84.33 ;
     RECT  0.463 66.726 0.499 66.744 ;
     RECT  0.463 67.806 0.499 67.824 ;
     RECT  0.463 84.312 0.499 84.906 ;
     RECT  0.103 39.87 0.535 39.888 ;
     RECT  0.463 53.136 0.535 53.154 ;
     RECT  0.463 79.722 0.535 79.74 ;
     RECT  0.463 50.751 0.563 50.769 ;
     RECT  0.535 52.866 0.563 53.154 ;
     RECT  0.499 66.726 0.563 67.824 ;
     RECT  0.535 79.722 0.563 79.812 ;
     RECT  0.499 83.916 0.563 84.906 ;
     RECT  0.563 79.794 0.967 79.812 ;
     RECT  0.535 39.834 1.003 39.888 ;
     RECT  0.895 40.68 1.003 40.698 ;
     RECT  1.003 39.834 1.039 40.698 ;
     RECT  1.075 88.47 1.111 88.488 ;
     RECT  1.111 88.47 1.147 88.614 ;
     RECT  0.967 79.794 1.435 80.154 ;
     RECT  1.435 56.34 1.507 56.358 ;
     RECT  1.507 56.34 1.543 56.394 ;
     RECT  1.507 90.126 1.543 90.144 ;
     RECT  1.579 54.99 1.615 55.008 ;
     RECT  1.543 90.126 1.615 90.684 ;
     RECT  0.535 91.908 1.615 91.926 ;
     RECT  1.615 54.99 1.651 55.278 ;
     RECT  1.615 90.126 1.687 91.926 ;
     RECT  0.535 43.11 2.047 43.128 ;
     RECT  1.111 44.496 2.047 44.514 ;
     RECT  1.147 88.47 2.047 88.722 ;
     RECT  1.435 79.326 2.083 80.154 ;
     RECT  1.651 54.486 2.119 55.278 ;
     RECT  0.931 86.436 2.119 86.454 ;
     RECT  1.039 39.294 2.16 40.698 ;
     RECT  0.967 41.994 2.16 42.012 ;
     RECT  2.047 43.11 2.16 44.514 ;
     RECT  1.075 45.468 2.16 45.486 ;
     RECT  0.103 46.62 2.16 46.638 ;
     RECT  1.687 47.628 2.16 47.646 ;
     RECT  1.471 48.51 2.16 48.528 ;
     RECT  0.931 49.554 2.16 49.572 ;
     RECT  0.563 52.866 2.16 52.884 ;
     RECT  2.119 53.946 2.16 55.278 ;
     RECT  1.543 56.034 2.16 56.394 ;
     RECT  2.011 57.96 2.16 57.978 ;
     RECT  2.011 64.062 2.16 64.08 ;
     RECT  0.563 66.87 2.16 67.158 ;
     RECT  0.895 76.626 2.16 76.644 ;
     RECT  2.083 79.326 2.16 80.352 ;
     RECT  1.471 81.756 2.16 81.774 ;
     RECT  0.535 82.836 2.16 82.854 ;
     RECT  0.563 83.916 2.16 84.204 ;
     RECT  2.119 86.346 2.16 86.454 ;
     RECT  2.047 87.966 2.16 88.722 ;
     RECT  1.687 89.514 2.16 91.926 ;
     RECT  2.16 2.151 19.44 127.449 ;
     RECT  19.44 45.27 19.463 60.984 ;
     RECT  19.44 64.134 19.535 69.894 ;
     RECT  19.44 85.806 19.571 97.794 ;
     RECT  19.571 85.896 19.643 95.238 ;
     RECT  19.44 33.048 19.679 33.066 ;
     RECT  19.44 33.858 19.715 43.974 ;
     RECT  19.715 41.616 19.787 43.974 ;
     RECT  19.643 85.896 19.787 88.254 ;
     RECT  19.715 33.858 19.823 40.824 ;
     RECT  19.44 70.686 19.859 76.842 ;
     RECT  19.463 45.27 19.931 59.328 ;
     RECT  19.535 64.134 19.931 67.626 ;
     RECT  19.859 72.846 19.931 76.842 ;
     RECT  19.44 77.706 19.931 84.6 ;
     RECT  19.931 45.27 19.967 46.638 ;
     RECT  19.931 52.956 19.967 59.328 ;
     RECT  19.931 77.706 19.967 79.038 ;
     RECT  19.787 41.886 20.003 43.974 ;
     RECT  19.463 60.12 20.003 60.984 ;
     RECT  19.967 77.706 20.003 77.724 ;
     RECT  19.643 89.478 20.003 95.238 ;
     RECT  19.571 96.156 20.003 97.794 ;
     RECT  19.931 47.628 20.039 52.038 ;
     RECT  20.003 60.426 20.111 60.984 ;
     RECT  19.931 75.816 20.147 76.842 ;
     RECT  20.003 89.586 20.147 95.238 ;
     RECT  19.44 61.938 20.191 63.234 ;
     RECT  20.003 41.886 20.219 41.904 ;
     RECT  19.823 33.858 20.291 40.194 ;
     RECT  20.191 61.938 20.291 63.306 ;
     RECT  20.003 97.776 20.435 97.794 ;
     RECT  20.147 75.816 20.471 76.806 ;
     RECT  19.967 45.396 20.507 46.638 ;
     RECT  20.039 47.7 20.507 52.038 ;
     RECT  19.967 52.956 20.507 53.316 ;
     RECT  19.967 54.18 20.507 59.292 ;
     RECT  19.931 64.134 20.507 66.618 ;
     RECT  19.535 68.49 20.507 69.894 ;
     RECT  19.859 70.686 20.507 71.748 ;
     RECT  20.471 75.816 20.507 75.834 ;
     RECT  19.931 79.794 20.507 81.774 ;
     RECT  19.931 82.728 20.507 84.6 ;
     RECT  20.507 84.456 20.515 84.6 ;
     RECT  20.291 40.176 20.543 40.194 ;
     RECT  20.003 43.11 20.543 43.974 ;
     RECT  20.507 45.54 20.543 46.638 ;
     RECT  20.507 47.7 20.543 51.966 ;
     RECT  20.507 54.18 20.543 54.738 ;
     RECT  20.507 55.836 20.543 58.788 ;
     RECT  20.111 60.552 20.543 60.984 ;
     RECT  20.291 61.938 20.543 63.108 ;
     RECT  20.507 64.134 20.543 65.772 ;
     RECT  20.507 71.73 20.543 71.748 ;
     RECT  19.967 78.48 20.543 79.038 ;
     RECT  20.507 79.794 20.543 80.082 ;
     RECT  19.787 85.896 20.543 87.912 ;
     RECT  20.543 43.956 20.579 43.974 ;
     RECT  20.543 45.702 20.579 46.368 ;
     RECT  20.543 47.7 20.579 51.894 ;
     RECT  20.543 65.52 20.579 65.772 ;
     RECT  20.507 82.728 20.579 83.592 ;
     RECT  20.147 90.126 20.579 95.238 ;
     RECT  20.291 34.596 20.615 39.042 ;
     RECT  20.543 43.11 20.615 43.128 ;
     RECT  20.515 84.456 20.615 84.906 ;
     RECT  20.003 96.156 20.615 96.984 ;
     RECT  20.579 47.7 20.651 50.769 ;
     RECT  20.543 54.45 20.651 54.738 ;
     RECT  20.615 96.426 20.651 96.984 ;
     RECT  20.543 56.034 20.687 57.906 ;
     RECT  20.651 54.576 20.723 54.738 ;
     RECT  20.507 80.91 20.723 81.774 ;
     RECT  20.543 61.938 20.759 62.73 ;
     RECT  20.543 60.93 20.831 60.984 ;
     RECT  20.615 34.596 21.011 38.844 ;
     RECT  20.579 90.126 21.083 94.554 ;
     RECT  21.011 34.596 21.155 38.394 ;
     RECT  21.155 34.596 21.227 37.314 ;
     RECT  21.055 40.842 21.227 40.86 ;
     RECT  20.507 52.956 21.235 52.974 ;
     RECT  20.579 65.754 21.235 65.772 ;
     RECT  20.507 66.6 21.235 66.618 ;
     RECT  20.543 85.896 21.271 87.804 ;
     RECT  20.579 51.678 21.307 51.894 ;
     RECT  21.155 38.142 21.335 38.394 ;
     RECT  20.543 64.404 21.343 64.422 ;
     RECT  21.227 34.596 21.371 35.874 ;
     RECT  19.931 72.846 21.371 74.988 ;
     RECT  20.579 83.574 21.371 83.592 ;
     RECT  21.083 90.756 21.371 94.554 ;
     RECT  21.235 52.83 21.379 52.974 ;
     RECT  21.371 34.596 21.407 35.694 ;
     RECT  21.307 51.138 21.407 51.894 ;
     RECT  21.371 73.476 21.407 74.988 ;
     RECT  21.371 90.756 21.407 93.888 ;
     RECT  21.091 42.651 21.415 42.669 ;
     RECT  21.379 52.758 21.415 52.974 ;
     RECT  20.543 58.77 21.415 58.788 ;
     RECT  20.759 61.938 21.415 62.226 ;
     RECT  21.235 65.754 21.415 66.618 ;
     RECT  21.235 67.608 21.415 67.626 ;
     RECT  20.507 68.49 21.415 68.976 ;
     RECT  21.407 35.676 21.443 35.694 ;
     RECT  21.343 63.828 21.443 64.764 ;
     RECT  21.407 73.476 21.443 74.646 ;
     RECT  20.543 79.794 21.443 79.812 ;
     RECT  20.723 80.946 21.443 81.774 ;
     RECT  21.271 85.896 21.443 87.876 ;
     RECT  21.415 42.192 21.451 42.669 ;
     RECT  21.335 38.376 21.479 38.394 ;
     RECT  20.579 45.702 21.479 45.954 ;
     RECT  21.407 51.678 21.479 51.894 ;
     RECT  21.415 52.758 21.479 53.352 ;
     RECT  20.687 56.034 21.479 57.294 ;
     RECT  21.415 61.2 21.479 62.226 ;
     RECT  21.443 63.828 21.479 64.08 ;
     RECT  21.415 65.52 21.479 67.626 ;
     RECT  21.415 68.49 21.479 69.084 ;
     RECT  21.343 71.658 21.479 71.676 ;
     RECT  20.579 82.728 21.479 82.746 ;
     RECT  21.407 92.754 21.479 93.888 ;
     RECT  21.443 80.946 21.487 81.054 ;
     RECT  21.227 37.026 21.515 37.314 ;
     RECT  21.451 42.192 21.515 42.822 ;
     RECT  21.479 45.936 21.515 45.954 ;
     RECT  20.651 47.7 21.515 50.346 ;
     RECT  21.479 51.876 21.515 51.894 ;
     RECT  21.479 52.956 21.515 53.352 ;
     RECT  20.723 54.576 21.515 54.594 ;
     RECT  21.479 56.106 21.515 56.124 ;
     RECT  21.479 57.276 21.515 57.294 ;
     RECT  21.415 58.77 21.515 59.094 ;
     RECT  21.415 60.246 21.515 60.264 ;
     RECT  21.479 61.2 21.515 61.956 ;
     RECT  21.479 64.062 21.515 64.08 ;
     RECT  21.479 65.52 21.515 66.51 ;
     RECT  21.479 67.266 21.515 67.626 ;
     RECT  21.479 68.616 21.515 69.084 ;
     RECT  21.415 69.966 21.515 69.984 ;
     RECT  21.443 73.476 21.515 74.34 ;
     RECT  20.471 76.788 21.515 76.806 ;
     RECT  20.543 79.02 21.515 79.038 ;
     RECT  20.615 84.456 21.515 84.474 ;
     RECT  21.443 85.896 21.515 86.796 ;
     RECT  21.407 90.756 21.515 91.584 ;
     RECT  20.651 96.426 21.515 96.444 ;
     RECT  21.515 37.026 21.551 37.044 ;
     RECT  21.515 42.264 21.551 42.822 ;
     RECT  21.515 86.544 21.551 86.562 ;
     RECT  21.479 93.456 21.551 93.474 ;
     RECT  21.407 34.596 21.587 34.614 ;
     RECT  21.551 42.264 21.587 42.282 ;
     RECT  21.487 80.406 21.587 81.054 ;
     RECT  21.443 87.786 21.587 87.876 ;
     RECT  21.515 91.566 21.587 91.584 ;
    LAYER M3 ;
     RECT  2.415 2.143 2.505 2.413 ;
     RECT  5.115 2.143 5.205 2.413 ;
     RECT  7.815 2.143 7.905 2.413 ;
     RECT  10.515 2.143 10.605 2.413 ;
     RECT  13.215 2.143 13.305 2.413 ;
     RECT  15.915 2.143 16.005 2.413 ;
     RECT  18.615 2.143 18.705 2.413 ;
     RECT  18.615 2.413 18.897 33.007 ;
     RECT  18.615 33.007 19.098 33.043 ;
     RECT  18.615 33.043 19.674 33.853 ;
     RECT  21.564 34.591 21.582 35.203 ;
     RECT  21.384 35.203 21.582 35.401 ;
     RECT  21.276 35.401 21.582 35.473 ;
     RECT  18.615 33.853 20.286 35.545 ;
     RECT  18.324 35.545 20.286 35.896 ;
     RECT  18.324 35.896 20.358 35.941 ;
     RECT  21.096 35.473 21.582 35.941 ;
     RECT  17.172 34.735 17.19 36.085 ;
     RECT  17.172 36.085 17.478 36.625 ;
     RECT  18.324 35.941 21.582 36.625 ;
     RECT  5.115 2.413 5.397 38.911 ;
     RECT  5.115 38.911 5.562 39.055 ;
     RECT  15.915 2.413 16.197 39.055 ;
     RECT  17.172 36.625 21.582 39.055 ;
     RECT  2.415 2.413 2.697 39.091 ;
     RECT  3.456 39.055 5.562 39.091 ;
     RECT  7.815 2.413 8.097 39.487 ;
     RECT  2.415 39.091 5.562 39.595 ;
     RECT  2.304 39.595 5.562 39.631 ;
     RECT  2.304 39.631 6.138 39.677 ;
     RECT  1.044 39.289 1.062 39.829 ;
     RECT  0.54 39.829 1.062 39.865 ;
     RECT  0.108 39.865 1.062 39.917 ;
     RECT  10.515 2.413 10.797 40.027 ;
     RECT  10.152 40.027 10.797 40.063 ;
     RECT  9.468 40.063 10.797 40.297 ;
     RECT  7.344 39.487 8.097 40.369 ;
     RECT  0.54 39.917 1.062 40.397 ;
     RECT  7.2 40.369 8.097 40.405 ;
     RECT  2.304 39.677 5.994 40.441 ;
     RECT  6.768 40.405 8.097 40.441 ;
     RECT  2.304 40.441 8.097 40.445 ;
     RECT  14.868 40.297 14.886 40.469 ;
     RECT  7.2 40.445 8.097 40.639 ;
     RECT  7.2 40.639 8.298 40.837 ;
     RECT  9.468 40.297 11.358 40.981 ;
     RECT  13.215 2.413 13.497 41.071 ;
     RECT  13.215 41.071 13.95 41.413 ;
     RECT  2.304 40.445 6.318 41.467 ;
     RECT  7.2 40.837 8.406 41.467 ;
     RECT  2.304 41.467 8.406 41.515 ;
     RECT  9.216 40.981 11.358 41.647 ;
     RECT  0.144 41.563 0.162 41.803 ;
     RECT  0.9 40.397 1.062 41.803 ;
     RECT  9.216 41.647 11.826 41.989 ;
     RECT  2.268 41.515 8.406 42.025 ;
     RECT  14.832 41.341 14.85 42.061 ;
     RECT  2.232 42.025 8.406 42.077 ;
     RECT  0.144 41.803 1.062 42.125 ;
     RECT  15.915 39.055 21.582 42.287 ;
     RECT  14.832 42.061 14.886 42.427 ;
     RECT  2.304 42.077 8.406 42.529 ;
     RECT  9.216 41.989 12.114 42.529 ;
     RECT  15.915 42.287 21.546 42.827 ;
     RECT  14.832 42.427 14.994 43.099 ;
     RECT  0.9 42.125 1.062 43.105 ;
     RECT  15.915 42.827 21.474 43.277 ;
     RECT  0.54 43.105 1.062 43.627 ;
     RECT  14.832 43.099 15.066 43.627 ;
     RECT  21.42 43.277 21.474 43.661 ;
     RECT  15.915 43.277 20.61 43.771 ;
     RECT  0.216 43.627 1.062 43.807 ;
     RECT  2.304 42.529 12.114 43.843 ;
     RECT  0.108 43.807 1.062 43.853 ;
     RECT  14.832 43.627 15.102 44.185 ;
     RECT  15.876 43.771 20.61 44.185 ;
     RECT  0.144 43.853 1.062 44.491 ;
     RECT  21.456 43.661 21.474 44.635 ;
     RECT  0.144 44.491 1.134 44.669 ;
     RECT  14.832 44.185 20.61 44.717 ;
     RECT  21.42 44.635 21.474 44.813 ;
     RECT  2.052 43.843 12.114 45.031 ;
     RECT  12.852 41.413 13.95 45.031 ;
     RECT  14.868 44.717 20.61 45.293 ;
     RECT  20.484 45.293 20.61 45.419 ;
     RECT  14.868 45.293 19.35 45.535 ;
     RECT  21.456 44.813 21.474 45.739 ;
     RECT  14.76 45.535 19.35 45.769 ;
     RECT  14.724 45.769 19.35 45.959 ;
     RECT  21.456 45.739 21.51 45.959 ;
     RECT  21.456 45.959 21.474 45.965 ;
     RECT  2.052 45.031 13.95 46.219 ;
     RECT  0.54 44.669 1.134 46.615 ;
     RECT  20.52 45.419 20.61 46.795 ;
     RECT  2.052 46.219 14.274 46.843 ;
     RECT  15.012 45.959 19.35 46.843 ;
     RECT  2.052 46.843 19.35 47.083 ;
     RECT  20.448 46.795 20.61 47.083 ;
     RECT  0.108 46.615 1.134 47.405 ;
     RECT  21.42 46.555 21.438 47.419 ;
     RECT  0.216 47.405 1.134 47.623 ;
     RECT  2.052 47.083 20.61 47.623 ;
     RECT  21.384 47.419 21.438 47.695 ;
     RECT  0.216 47.623 20.61 47.759 ;
     RECT  0.324 47.759 20.61 47.885 ;
     RECT  21.384 47.695 21.51 47.885 ;
     RECT  0.54 47.885 20.61 48.965 ;
     RECT  19.944 48.965 20.61 49.099 ;
     RECT  21.42 47.885 21.51 49.099 ;
     RECT  0.54 48.965 19.062 49.28 ;
     RECT  0.54 49.28 19.026 49.469 ;
     RECT  19.944 49.099 21.51 49.517 ;
     RECT  19.944 49.517 20.61 50.251 ;
     RECT  21.348 49.517 21.51 50.251 ;
     RECT  19.944 50.251 21.51 50.351 ;
     RECT  19.944 50.351 21.474 50.491 ;
     RECT  0.54 49.469 18.99 50.746 ;
     RECT  0.468 50.746 18.99 50.791 ;
     RECT  19.8 50.491 21.474 50.791 ;
     RECT  0.468 50.791 21.474 51.115 ;
     RECT  0.324 51.115 21.474 51.451 ;
     RECT  0.18 51.451 21.474 51.691 ;
     RECT  0.18 51.691 21.51 51.725 ;
     RECT  0.468 51.725 21.51 51.821 ;
     RECT  0.468 51.821 20.646 52.589 ;
     RECT  19.908 52.589 20.646 52.651 ;
     RECT  21.384 51.821 21.51 52.651 ;
     RECT  19.908 52.651 21.51 53.357 ;
     RECT  0.468 52.589 19.134 53.419 ;
     RECT  19.908 53.357 21.438 53.453 ;
     RECT  0.324 53.419 19.134 53.549 ;
     RECT  0.54 53.549 19.134 53.803 ;
     RECT  19.908 53.453 20.646 53.803 ;
     RECT  21.42 53.453 21.438 54.091 ;
     RECT  0.54 53.803 20.646 54.427 ;
     RECT  21.42 54.091 21.51 54.427 ;
     RECT  0.54 54.427 21.51 54.475 ;
     RECT  0.144 54.475 21.51 54.599 ;
     RECT  0.144 54.599 21.438 54.653 ;
     RECT  0.54 54.653 21.438 54.941 ;
     RECT  0.54 54.941 20.718 55.483 ;
     RECT  0.216 55.483 20.718 55.867 ;
     RECT  21.492 55.915 21.51 56.011 ;
     RECT  0.144 55.867 20.718 56.045 ;
     RECT  0.18 56.045 20.718 56.059 ;
     RECT  21.456 56.011 21.51 56.059 ;
     RECT  0.18 56.059 21.51 56.381 ;
     RECT  0.54 56.381 21.51 57.299 ;
     RECT  0.54 57.299 21.438 57.341 ;
     RECT  0.54 57.341 20.826 57.739 ;
     RECT  0.36 57.739 20.826 57.835 ;
     RECT  0.144 57.835 20.826 58.219 ;
     RECT  0.144 58.219 21.51 58.637 ;
     RECT  0.216 58.637 21.51 59.117 ;
     RECT  0.216 59.117 21.438 59.467 ;
     RECT  0.144 59.467 21.438 59.575 ;
     RECT  0.108 59.575 21.438 59.789 ;
     RECT  0.144 59.789 21.438 60.232 ;
     RECT  0.144 60.232 21.51 60.269 ;
     RECT  0.144 60.269 21.438 60.317 ;
     RECT  0.252 60.317 20.826 60.797 ;
     RECT  0.54 60.797 20.826 61.147 ;
     RECT  0.54 61.147 21.438 61.195 ;
     RECT  0.54 61.195 21.51 61.771 ;
     RECT  0.144 61.771 21.51 61.949 ;
     RECT  0.54 61.949 21.51 61.961 ;
     RECT  0.54 61.961 21.474 62.285 ;
     RECT  0.54 62.285 21.438 62.957 ;
     RECT  0.54 62.957 21.366 62.971 ;
     RECT  0.144 62.971 21.366 63.643 ;
     RECT  0.108 63.643 21.366 63.787 ;
     RECT  0.108 63.787 21.474 64.057 ;
     RECT  0.108 64.057 21.51 64.109 ;
     RECT  0.108 64.109 21.438 64.193 ;
     RECT  0.144 64.193 21.438 64.925 ;
     RECT  0.324 64.925 21.438 65.515 ;
     RECT  0.324 65.515 21.51 65.707 ;
     RECT  0.18 65.707 21.51 66.077 ;
     RECT  0.468 66.077 21.51 66.515 ;
     RECT  0.468 66.515 21.474 66.955 ;
     RECT  0.324 66.955 21.474 67.243 ;
     RECT  0.324 67.243 21.51 67.435 ;
     RECT  0.18 67.435 21.51 67.709 ;
     RECT  0.324 67.709 21.51 68.333 ;
     RECT  0.54 68.333 21.51 69.101 ;
     RECT  0.54 69.101 21.438 69.163 ;
     RECT  0.324 69.163 21.438 69.931 ;
     RECT  0.324 69.931 21.51 69.989 ;
     RECT  0.324 69.989 21.438 70.589 ;
     RECT  0.324 70.589 20.754 70.795 ;
     RECT  0.18 70.795 20.754 70.843 ;
     RECT  0.036 70.843 20.754 71.024 ;
     RECT  0.108 71.024 20.754 71.213 ;
     RECT  0.54 71.213 20.754 71.371 ;
     RECT  21.492 70.987 21.51 71.371 ;
     RECT  0.54 71.371 21.51 72.811 ;
     RECT  0.324 72.811 21.51 73.339 ;
     RECT  0.144 73.339 21.51 73.517 ;
     RECT  0.54 73.517 21.51 74.345 ;
     RECT  0.54 74.345 21.438 74.443 ;
     RECT  0.144 74.443 21.438 74.621 ;
     RECT  0.54 74.621 21.438 75.389 ;
     RECT  0.54 75.389 19.206 75.403 ;
     RECT  0.144 75.403 19.206 75.581 ;
     RECT  0.216 75.581 19.206 75.677 ;
     RECT  0.324 75.677 19.206 75.725 ;
     RECT  19.944 75.389 21.438 76.253 ;
     RECT  19.98 76.253 21.438 76.363 ;
     RECT  19.98 76.363 21.51 76.613 ;
     RECT  20.088 76.613 21.51 76.775 ;
     RECT  20.124 76.775 21.51 76.811 ;
     RECT  20.124 76.811 21.402 76.829 ;
     RECT  0.54 75.725 19.206 76.939 ;
     RECT  0.252 76.939 19.206 76.981 ;
     RECT  0.252 76.981 19.278 77.323 ;
     RECT  0.18 77.323 19.278 77.515 ;
     RECT  20.124 76.829 20.718 77.515 ;
     RECT  0.18 77.515 20.718 77.563 ;
     RECT  0.18 77.563 21.438 77.659 ;
     RECT  0.144 77.659 21.438 77.741 ;
     RECT  0.144 77.741 20.718 77.933 ;
     RECT  0.18 77.933 20.718 78.221 ;
     RECT  20.052 78.221 20.718 78.317 ;
     RECT  0.18 78.221 19.278 78.715 ;
     RECT  20.412 78.317 20.718 78.763 ;
     RECT  20.412 78.763 21.438 79.015 ;
     RECT  20.412 79.015 21.51 79.085 ;
     RECT  0.144 78.715 19.278 79.147 ;
     RECT  20.412 79.085 21.438 79.147 ;
     RECT  0.144 79.147 21.438 79.313 ;
     RECT  0.144 79.313 19.422 79.421 ;
     RECT  0.288 79.421 19.422 79.613 ;
     RECT  0.468 79.613 19.422 80.365 ;
     RECT  20.412 79.313 21.438 80.365 ;
     RECT  0.468 80.365 21.438 80.392 ;
     RECT  0.468 80.392 21.51 80.401 ;
     RECT  0.468 80.401 21.582 81.095 ;
     RECT  20.484 81.095 21.582 81.329 ;
     RECT  0.468 81.095 19.422 81.835 ;
     RECT  0.324 81.835 19.422 81.869 ;
     RECT  0.324 81.869 14.274 81.979 ;
     RECT  0.216 81.979 14.274 82.021 ;
     RECT  15.012 81.869 19.422 82.219 ;
     RECT  20.592 81.329 21.582 82.219 ;
     RECT  0.144 82.021 14.274 82.319 ;
     RECT  15.012 82.219 21.582 82.349 ;
     RECT  0.18 82.319 14.274 82.637 ;
     RECT  0.324 82.637 14.274 82.651 ;
     RECT  15.012 82.349 19.458 82.651 ;
     RECT  20.592 82.349 21.582 83.191 ;
     RECT  20.556 83.191 21.582 83.563 ;
     RECT  0.324 82.651 19.458 83.597 ;
     RECT  0.324 83.597 14.058 83.669 ;
     RECT  14.976 83.597 19.458 83.803 ;
     RECT  20.448 83.563 21.582 83.803 ;
     RECT  14.976 83.803 21.582 84.029 ;
     RECT  0.324 83.669 13.497 84.307 ;
     RECT  15.048 84.029 21.582 84.335 ;
     RECT  0.108 84.307 13.497 84.365 ;
     RECT  0.468 84.365 13.497 84.911 ;
     RECT  15.084 84.335 21.582 85.147 ;
     RECT  0.504 84.911 13.497 85.229 ;
     RECT  0.54 85.229 13.497 85.483 ;
     RECT  0.54 85.483 13.59 85.661 ;
     RECT  0.54 85.661 13.497 86.347 ;
     RECT  0.144 86.347 13.497 86.525 ;
     RECT  14.832 85.147 21.582 86.567 ;
     RECT  0.324 86.525 13.497 86.729 ;
     RECT  0.324 86.729 9.486 86.873 ;
     RECT  0.324 86.873 9.45 87.058 ;
     RECT  9.36 87.058 9.45 87.149 ;
     RECT  0.324 87.058 8.226 87.269 ;
     RECT  14.94 86.567 21.582 87.385 ;
     RECT  10.404 86.729 13.497 87.413 ;
     RECT  14.832 87.385 21.582 87.539 ;
     RECT  10.515 87.413 13.497 88.079 ;
     RECT  0.324 87.269 8.19 88.109 ;
     RECT  9.432 87.149 9.45 88.349 ;
     RECT  15.084 87.539 21.582 88.349 ;
     RECT  11.556 88.079 13.497 88.529 ;
     RECT  0.54 88.109 8.19 88.619 ;
     RECT  0.54 88.619 8.097 88.727 ;
     RECT  0.54 88.727 0.558 89.035 ;
     RECT  15.876 88.349 21.582 89.159 ;
     RECT  0.144 89.035 0.558 89.213 ;
     RECT  14.832 88.393 14.85 89.227 ;
     RECT  14.832 89.227 14.922 89.743 ;
     RECT  14.832 89.743 14.958 90.041 ;
     RECT  0.18 89.213 0.558 90.077 ;
     RECT  1.512 88.727 8.097 90.149 ;
     RECT  1.548 90.149 8.097 90.239 ;
     RECT  14.832 90.041 14.85 90.239 ;
     RECT  1.548 90.239 6.678 90.689 ;
     RECT  11.556 88.529 12.078 91.049 ;
     RECT  1.62 90.689 6.678 91.195 ;
     RECT  1.62 91.195 6.714 91.229 ;
     RECT  2.304 91.229 6.714 91.319 ;
     RECT  2.304 91.319 6.354 91.355 ;
     RECT  2.376 91.355 6.354 91.499 ;
     RECT  12.06 91.049 12.078 91.589 ;
     RECT  15.915 89.159 21.582 91.589 ;
     RECT  2.376 91.499 5.886 91.625 ;
     RECT  15.915 91.589 21.546 91.625 ;
     RECT  2.415 91.625 5.886 91.733 ;
     RECT  2.415 91.733 5.85 91.757 ;
     RECT  0.54 90.077 0.558 91.931 ;
     RECT  14.832 91.831 14.85 91.931 ;
     RECT  17.244 91.625 21.546 92.039 ;
     RECT  3.456 91.757 5.85 92.141 ;
     RECT  3.456 92.141 3.582 92.165 ;
     RECT  3.492 92.165 3.582 92.237 ;
     RECT  4.464 92.141 5.85 92.273 ;
     RECT  3.564 92.237 3.582 92.309 ;
     RECT  4.464 92.273 5.706 92.309 ;
     RECT  17.352 92.039 21.546 92.821 ;
     RECT  17.28 92.821 21.546 93.245 ;
     RECT  18.18 93.245 21.546 93.479 ;
     RECT  17.28 93.245 17.298 93.785 ;
     RECT  18.18 93.479 21.51 94.325 ;
     RECT  18.36 94.325 21.51 94.559 ;
     RECT  18.36 94.559 20.646 96.251 ;
     RECT  18.36 96.251 19.17 96.323 ;
     RECT  21.492 94.559 21.51 96.449 ;
     RECT  18.36 96.323 19.098 96.485 ;
     RECT  19.98 96.251 20.646 96.989 ;
     RECT  19.98 96.989 20.43 97.061 ;
     RECT  20.412 97.061 20.43 97.799 ;
     RECT  18.615 96.485 19.098 97.835 ;
     RECT  2.415 91.757 2.697 127.187 ;
     RECT  5.115 92.309 5.397 127.187 ;
     RECT  7.815 90.239 8.097 127.187 ;
     RECT  10.515 88.079 10.797 127.187 ;
     RECT  13.215 88.529 13.497 127.187 ;
     RECT  15.915 91.625 16.197 127.187 ;
     RECT  18.615 97.835 18.897 127.187 ;
     RECT  2.415 127.187 2.505 127.457 ;
     RECT  5.115 127.187 5.205 127.457 ;
     RECT  7.815 127.187 7.905 127.457 ;
     RECT  10.515 127.187 10.605 127.457 ;
     RECT  13.215 127.187 13.305 127.457 ;
     RECT  15.915 127.187 16.005 127.457 ;
     RECT  18.615 127.187 18.705 127.457 ;
    LAYER M4 ;
     RECT  0.025 70.848 0.06 70.872 ;
     RECT  0.084 39.792 2.408 39.816 ;
     RECT  0.06 39.816 2.408 39.888 ;
     RECT  0.084 39.888 2.408 39.912 ;
     RECT  0.06 39.912 2.408 39.984 ;
     RECT  0.084 39.984 2.408 40.008 ;
     RECT  0.06 40.008 2.408 40.08 ;
     RECT  0.084 40.08 2.408 40.104 ;
     RECT  0.06 40.104 2.408 40.176 ;
     RECT  0.084 40.176 2.408 40.2 ;
     RECT  0.06 40.2 2.408 40.272 ;
     RECT  0.084 40.272 2.408 40.296 ;
     RECT  0.06 40.296 2.408 40.368 ;
     RECT  0.084 40.368 2.408 40.392 ;
     RECT  0.06 40.392 2.408 40.464 ;
     RECT  0.084 40.464 2.408 40.488 ;
     RECT  0.06 40.488 2.408 40.56 ;
     RECT  0.084 40.56 2.408 40.584 ;
     RECT  0.06 40.584 2.408 40.656 ;
     RECT  0.084 40.656 2.408 40.68 ;
     RECT  0.06 40.68 2.408 40.752 ;
     RECT  0.084 40.752 2.408 40.776 ;
     RECT  0.06 40.776 2.408 40.848 ;
     RECT  0.084 40.848 2.408 40.872 ;
     RECT  0.06 40.872 2.408 40.944 ;
     RECT  0.084 40.944 2.408 40.968 ;
     RECT  0.06 40.968 2.408 41.04 ;
     RECT  0.084 41.04 2.408 41.064 ;
     RECT  0.06 41.064 2.408 41.136 ;
     RECT  0.084 41.136 2.408 41.16 ;
     RECT  0.06 41.16 2.408 41.232 ;
     RECT  0.084 41.232 2.408 41.256 ;
     RECT  0.06 41.256 2.408 41.328 ;
     RECT  0.084 41.328 2.408 41.352 ;
     RECT  0.06 41.352 2.408 41.424 ;
     RECT  0.084 41.424 2.408 41.448 ;
     RECT  0.06 41.448 2.408 41.52 ;
     RECT  0.084 41.52 2.408 41.544 ;
     RECT  0.06 41.544 2.408 41.616 ;
     RECT  0.084 41.616 2.408 41.64 ;
     RECT  0.06 41.64 2.408 41.712 ;
     RECT  0.084 41.712 2.408 41.736 ;
     RECT  0.06 41.736 2.408 41.808 ;
     RECT  0.084 41.808 2.408 41.832 ;
     RECT  0.06 41.832 2.408 41.904 ;
     RECT  0.084 41.904 2.408 41.928 ;
     RECT  0.06 41.928 2.408 42 ;
     RECT  0.084 42 2.408 42.024 ;
     RECT  0.06 42.024 2.408 42.096 ;
     RECT  0.084 42.096 2.408 42.12 ;
     RECT  0.06 42.12 2.408 42.192 ;
     RECT  0.084 42.192 2.408 42.216 ;
     RECT  0.06 42.216 2.408 42.288 ;
     RECT  0.084 42.288 2.408 42.312 ;
     RECT  0.06 42.312 2.408 42.384 ;
     RECT  0.084 42.384 2.408 42.408 ;
     RECT  0.06 42.408 2.408 42.48 ;
     RECT  0.084 42.48 2.408 42.504 ;
     RECT  0.06 42.504 2.408 42.576 ;
     RECT  0.084 42.576 2.408 42.6 ;
     RECT  0.06 42.6 2.408 42.672 ;
     RECT  0.084 42.672 2.408 42.696 ;
     RECT  0.06 42.696 2.408 42.768 ;
     RECT  0.084 42.768 2.408 42.792 ;
     RECT  0.06 42.792 2.408 42.864 ;
     RECT  0.084 42.864 2.408 42.888 ;
     RECT  0.06 42.888 2.408 42.96 ;
     RECT  0.084 42.96 2.408 42.984 ;
     RECT  0.06 42.984 2.408 43.056 ;
     RECT  0.084 43.056 2.408 43.08 ;
     RECT  0.06 43.08 2.408 43.152 ;
     RECT  0.084 43.152 2.408 43.176 ;
     RECT  0.06 43.176 2.408 43.248 ;
     RECT  0.084 43.248 2.408 43.272 ;
     RECT  0.06 43.272 2.408 43.344 ;
     RECT  0.084 43.344 2.408 43.368 ;
     RECT  0.06 43.368 2.408 43.44 ;
     RECT  0.084 43.44 2.408 43.464 ;
     RECT  0.06 43.464 2.408 43.536 ;
     RECT  0.084 43.536 2.408 43.56 ;
     RECT  0.06 43.56 2.408 43.632 ;
     RECT  0.084 43.632 2.408 43.656 ;
     RECT  0.06 43.656 2.408 43.728 ;
     RECT  0.084 43.728 2.408 43.752 ;
     RECT  0.06 43.752 2.408 43.824 ;
     RECT  0.084 43.824 2.408 43.848 ;
     RECT  0.06 43.848 2.408 43.92 ;
     RECT  0.084 43.92 2.408 43.944 ;
     RECT  0.06 43.944 2.408 44.016 ;
     RECT  0.084 44.016 2.408 44.04 ;
     RECT  0.06 44.04 2.408 44.112 ;
     RECT  0.084 44.112 2.408 44.136 ;
     RECT  0.06 44.136 2.408 44.208 ;
     RECT  0.084 44.208 2.408 44.232 ;
     RECT  0.06 44.232 2.408 44.304 ;
     RECT  0.084 44.304 2.408 44.328 ;
     RECT  0.06 44.328 2.408 44.4 ;
     RECT  0.084 44.4 2.408 44.424 ;
     RECT  0.06 44.424 2.408 44.496 ;
     RECT  0.084 44.496 2.408 44.52 ;
     RECT  0.06 44.52 2.408 44.592 ;
     RECT  0.084 44.592 2.408 44.616 ;
     RECT  0.06 44.616 2.408 44.688 ;
     RECT  0.084 44.688 2.408 44.712 ;
     RECT  0.06 44.712 2.408 44.784 ;
     RECT  0.084 44.784 2.408 44.808 ;
     RECT  0.06 44.808 2.408 44.88 ;
     RECT  0.084 44.88 2.408 44.904 ;
     RECT  0.06 44.904 2.408 44.976 ;
     RECT  0.084 44.976 2.408 45 ;
     RECT  0.06 45 2.408 45.072 ;
     RECT  0.084 45.072 2.408 45.096 ;
     RECT  0.06 45.096 2.408 45.168 ;
     RECT  0.084 45.168 2.408 45.192 ;
     RECT  0.06 45.192 2.408 45.264 ;
     RECT  0.084 45.264 2.408 45.288 ;
     RECT  0.06 45.288 2.408 45.36 ;
     RECT  0.084 45.36 2.408 45.384 ;
     RECT  0.06 45.384 2.408 45.456 ;
     RECT  0.084 45.456 2.408 45.48 ;
     RECT  0.06 45.48 2.408 45.552 ;
     RECT  0.084 45.552 2.408 45.576 ;
     RECT  0.06 45.576 2.408 45.648 ;
     RECT  0.084 45.648 2.408 45.672 ;
     RECT  0.06 45.672 2.408 45.744 ;
     RECT  0.084 45.744 2.408 45.768 ;
     RECT  0.06 45.768 2.408 45.84 ;
     RECT  0.084 45.84 2.408 45.864 ;
     RECT  0.06 45.864 2.408 45.936 ;
     RECT  0.084 45.936 2.408 45.96 ;
     RECT  0.06 45.96 2.408 46.032 ;
     RECT  0.084 46.032 2.408 46.056 ;
     RECT  0.06 46.056 2.408 46.128 ;
     RECT  0.084 46.128 2.408 46.152 ;
     RECT  0.06 46.152 2.408 46.224 ;
     RECT  0.084 46.224 2.408 46.248 ;
     RECT  0.06 46.248 2.408 46.32 ;
     RECT  0.084 46.32 2.408 46.344 ;
     RECT  0.06 46.344 2.408 46.416 ;
     RECT  0.084 46.416 2.408 46.44 ;
     RECT  0.06 46.44 2.408 46.512 ;
     RECT  0.084 46.512 2.408 46.536 ;
     RECT  0.06 46.536 2.408 46.608 ;
     RECT  0.084 46.608 2.408 46.632 ;
     RECT  0.06 46.632 2.408 46.704 ;
     RECT  0.084 46.704 2.408 46.728 ;
     RECT  0.06 46.728 2.408 46.8 ;
     RECT  0.084 46.8 2.408 46.824 ;
     RECT  0.06 46.824 2.408 46.896 ;
     RECT  0.084 46.896 2.408 46.92 ;
     RECT  0.06 46.92 2.408 46.992 ;
     RECT  0.084 46.992 2.408 47.016 ;
     RECT  0.06 47.016 2.408 47.088 ;
     RECT  0.084 47.088 2.408 47.112 ;
     RECT  0.06 47.112 2.408 47.184 ;
     RECT  0.084 47.184 2.408 47.208 ;
     RECT  0.06 47.208 2.408 47.28 ;
     RECT  0.084 47.28 2.408 47.304 ;
     RECT  0.06 47.304 2.408 47.376 ;
     RECT  0.084 47.376 2.408 47.4 ;
     RECT  0.06 47.4 2.408 47.472 ;
     RECT  0.084 47.472 2.408 47.496 ;
     RECT  0.06 47.496 2.408 47.568 ;
     RECT  0.084 47.568 2.408 47.592 ;
     RECT  0.06 47.592 2.408 47.664 ;
     RECT  0.084 47.664 2.408 47.688 ;
     RECT  0.06 47.688 2.408 47.76 ;
     RECT  0.084 47.76 2.408 47.784 ;
     RECT  0.06 47.784 2.408 47.856 ;
     RECT  0.084 47.856 2.408 47.88 ;
     RECT  0.06 47.88 2.408 47.952 ;
     RECT  0.084 47.952 2.408 47.976 ;
     RECT  0.06 47.976 2.408 48.048 ;
     RECT  0.084 48.048 2.408 48.072 ;
     RECT  0.06 48.072 2.408 48.144 ;
     RECT  0.084 48.144 2.408 48.168 ;
     RECT  0.06 48.168 2.408 48.24 ;
     RECT  0.084 48.24 2.408 48.264 ;
     RECT  0.06 48.264 2.408 48.336 ;
     RECT  0.084 48.336 2.408 48.36 ;
     RECT  0.06 48.36 2.408 48.432 ;
     RECT  0.084 48.432 2.408 48.456 ;
     RECT  0.06 48.456 2.408 48.528 ;
     RECT  0.084 48.528 2.408 48.552 ;
     RECT  0.06 48.552 2.408 48.624 ;
     RECT  0.084 48.624 2.408 48.648 ;
     RECT  0.06 48.648 2.408 48.72 ;
     RECT  0.084 48.72 2.408 48.744 ;
     RECT  0.06 48.744 2.408 48.816 ;
     RECT  0.084 48.816 2.408 48.84 ;
     RECT  0.06 48.84 2.408 48.912 ;
     RECT  0.084 48.912 2.408 48.936 ;
     RECT  0.06 48.936 2.408 49.008 ;
     RECT  0.084 49.008 2.408 49.032 ;
     RECT  0.06 49.032 2.408 49.104 ;
     RECT  0.084 49.104 2.408 49.128 ;
     RECT  0.06 49.128 2.408 49.2 ;
     RECT  0.084 49.2 2.408 49.224 ;
     RECT  0.06 49.224 2.408 49.296 ;
     RECT  0.084 49.296 2.408 49.32 ;
     RECT  0.06 49.32 2.408 49.392 ;
     RECT  0.084 49.392 2.408 49.416 ;
     RECT  0.06 49.416 2.408 49.488 ;
     RECT  0.084 49.488 2.408 49.512 ;
     RECT  0.06 49.512 2.408 49.584 ;
     RECT  0.084 49.584 2.408 49.608 ;
     RECT  0.06 49.608 2.408 49.68 ;
     RECT  0.084 49.68 2.408 49.704 ;
     RECT  0.06 49.704 2.408 49.776 ;
     RECT  0.084 49.776 2.408 49.8 ;
     RECT  0.06 49.8 2.408 49.872 ;
     RECT  0.084 49.872 2.408 49.896 ;
     RECT  0.06 49.896 2.408 49.968 ;
     RECT  0.084 49.968 2.408 49.992 ;
     RECT  0.06 49.992 2.408 50.064 ;
     RECT  0.084 50.064 2.408 50.088 ;
     RECT  0.06 50.088 2.408 50.16 ;
     RECT  0.084 50.16 2.408 50.184 ;
     RECT  0.06 50.184 2.408 50.256 ;
     RECT  0.084 50.256 2.408 50.28 ;
     RECT  0.06 50.28 2.408 50.352 ;
     RECT  0.084 50.352 2.408 50.376 ;
     RECT  0.06 50.376 2.408 50.448 ;
     RECT  0.084 50.448 2.408 50.472 ;
     RECT  0.06 50.472 2.408 50.544 ;
     RECT  0.084 50.544 2.408 50.568 ;
     RECT  0.06 50.568 2.408 50.64 ;
     RECT  0.084 50.64 2.408 50.664 ;
     RECT  0.06 50.664 2.408 50.736 ;
     RECT  0.084 50.736 2.408 50.76 ;
     RECT  0.06 50.76 2.408 50.832 ;
     RECT  0.084 50.832 2.408 50.856 ;
     RECT  0.06 50.856 2.408 50.928 ;
     RECT  0.084 50.928 2.408 50.952 ;
     RECT  0.06 50.952 2.408 51.024 ;
     RECT  0.084 51.024 2.408 51.048 ;
     RECT  0.06 51.048 2.408 51.12 ;
     RECT  0.084 51.12 2.408 51.144 ;
     RECT  0.06 51.144 2.408 51.216 ;
     RECT  0.084 51.216 2.408 51.24 ;
     RECT  0.06 51.24 2.408 51.312 ;
     RECT  0.084 51.312 2.408 51.336 ;
     RECT  0.06 51.336 2.408 51.408 ;
     RECT  0.084 51.408 2.408 51.432 ;
     RECT  0.06 51.432 2.408 51.504 ;
     RECT  0.084 51.504 2.408 51.528 ;
     RECT  0.06 51.528 2.408 51.6 ;
     RECT  0.084 51.6 2.408 51.624 ;
     RECT  0.06 51.624 2.408 51.696 ;
     RECT  0.084 51.696 2.408 51.72 ;
     RECT  0.06 51.72 2.408 51.792 ;
     RECT  0.084 51.792 2.408 51.816 ;
     RECT  0.06 51.816 2.408 51.888 ;
     RECT  0.084 51.888 2.408 51.912 ;
     RECT  0.06 51.912 2.408 51.984 ;
     RECT  0.084 51.984 2.408 52.008 ;
     RECT  0.06 52.008 2.408 52.848 ;
     RECT  0.084 52.848 2.408 52.872 ;
     RECT  0.06 52.872 2.408 52.944 ;
     RECT  0.084 52.944 2.408 52.968 ;
     RECT  0.06 52.968 2.408 53.04 ;
     RECT  0.084 53.04 2.408 53.064 ;
     RECT  0.06 53.064 2.408 53.136 ;
     RECT  0.084 53.136 2.408 53.16 ;
     RECT  0.06 53.16 2.408 53.232 ;
     RECT  0.084 53.232 2.408 53.256 ;
     RECT  0.06 53.256 2.408 53.328 ;
     RECT  0.084 53.328 2.408 53.352 ;
     RECT  0.06 53.352 2.408 53.424 ;
     RECT  0.084 53.424 2.408 53.448 ;
     RECT  0.06 53.448 2.408 53.52 ;
     RECT  0.084 53.52 2.408 53.544 ;
     RECT  0.06 53.544 2.408 53.616 ;
     RECT  0.084 53.616 2.408 53.64 ;
     RECT  0.06 53.64 2.408 53.712 ;
     RECT  0.084 53.712 2.408 53.736 ;
     RECT  0.06 53.736 2.408 53.808 ;
     RECT  0.084 53.808 2.408 53.832 ;
     RECT  0.06 53.832 2.408 53.904 ;
     RECT  0.084 53.904 2.408 53.928 ;
     RECT  0.06 53.928 2.408 54 ;
     RECT  0.084 54 2.408 54.024 ;
     RECT  0.06 54.024 2.408 54.096 ;
     RECT  0.084 54.096 2.408 54.12 ;
     RECT  0.06 54.12 2.408 54.192 ;
     RECT  0.084 54.192 2.408 54.216 ;
     RECT  0.06 54.216 2.408 54.288 ;
     RECT  0.084 54.288 2.408 54.312 ;
     RECT  0.06 54.312 2.408 54.384 ;
     RECT  0.084 54.384 2.408 54.408 ;
     RECT  0.06 54.408 2.408 54.48 ;
     RECT  0.084 54.48 2.408 54.504 ;
     RECT  0.06 54.504 2.408 54.576 ;
     RECT  0.084 54.576 2.408 54.6 ;
     RECT  0.06 54.6 2.408 54.672 ;
     RECT  0.084 54.672 2.408 54.696 ;
     RECT  0.06 54.696 2.408 54.768 ;
     RECT  0.084 54.768 2.408 54.792 ;
     RECT  0.06 54.792 2.408 54.864 ;
     RECT  0.084 54.864 2.408 54.888 ;
     RECT  0.06 54.888 2.408 54.96 ;
     RECT  0.084 54.96 2.408 54.984 ;
     RECT  0.06 54.984 2.408 55.056 ;
     RECT  0.084 55.056 2.408 55.08 ;
     RECT  0.06 55.08 2.408 55.152 ;
     RECT  0.084 55.152 2.408 55.176 ;
     RECT  0.06 55.176 2.408 55.248 ;
     RECT  0.084 55.248 2.408 55.272 ;
     RECT  0.06 55.272 2.408 55.344 ;
     RECT  0.084 55.344 2.408 55.368 ;
     RECT  0.06 55.368 2.408 55.44 ;
     RECT  0.084 55.44 2.408 55.464 ;
     RECT  0.06 55.464 2.408 55.536 ;
     RECT  0.084 55.536 2.408 55.56 ;
     RECT  0.06 55.56 2.408 55.632 ;
     RECT  0.084 55.632 2.408 55.656 ;
     RECT  0.06 55.656 2.408 55.728 ;
     RECT  0.084 55.728 2.408 55.752 ;
     RECT  0.06 55.752 2.408 55.824 ;
     RECT  0.084 55.824 2.408 55.848 ;
     RECT  0.06 55.848 2.408 55.92 ;
     RECT  0.084 55.92 2.408 55.944 ;
     RECT  0.06 55.944 2.408 56.016 ;
     RECT  0.084 56.016 2.408 56.04 ;
     RECT  0.06 56.04 2.408 56.112 ;
     RECT  0.084 56.112 2.408 56.136 ;
     RECT  0.06 56.136 2.408 56.208 ;
     RECT  0.084 56.208 2.408 56.232 ;
     RECT  0.06 56.232 2.408 56.304 ;
     RECT  0.084 56.304 2.408 56.328 ;
     RECT  0.06 56.328 2.408 56.4 ;
     RECT  0.084 56.4 2.408 56.424 ;
     RECT  0.06 56.424 2.408 56.496 ;
     RECT  0.084 56.496 2.408 56.52 ;
     RECT  0.06 56.52 2.408 56.592 ;
     RECT  0.084 56.592 2.408 56.616 ;
     RECT  0.06 56.616 2.408 56.688 ;
     RECT  0.084 56.688 2.408 56.712 ;
     RECT  0.06 56.712 2.408 56.784 ;
     RECT  0.084 56.784 2.408 56.808 ;
     RECT  0.06 56.808 2.408 56.88 ;
     RECT  0.084 56.88 2.408 56.904 ;
     RECT  0.06 56.904 2.408 56.976 ;
     RECT  0.084 56.976 2.408 57 ;
     RECT  0.06 57 2.408 57.072 ;
     RECT  0.084 57.072 2.408 57.096 ;
     RECT  0.06 57.096 2.408 57.168 ;
     RECT  0.084 57.168 2.408 57.192 ;
     RECT  0.06 57.192 2.408 57.264 ;
     RECT  0.084 57.264 2.408 57.288 ;
     RECT  0.06 57.288 2.408 57.36 ;
     RECT  0.084 57.36 2.408 57.384 ;
     RECT  0.06 57.384 2.408 57.456 ;
     RECT  0.084 57.456 2.408 57.48 ;
     RECT  0.06 57.48 2.408 57.552 ;
     RECT  0.084 57.552 2.408 57.576 ;
     RECT  0.06 57.576 2.408 57.648 ;
     RECT  0.084 57.648 2.408 57.672 ;
     RECT  0.06 57.672 2.408 57.744 ;
     RECT  0.084 57.744 2.408 57.768 ;
     RECT  0.06 57.768 2.408 57.84 ;
     RECT  0.084 57.84 2.408 57.864 ;
     RECT  0.06 57.864 2.408 57.936 ;
     RECT  0.084 57.936 2.408 57.96 ;
     RECT  0.06 57.96 2.408 58.032 ;
     RECT  0.084 58.032 2.408 58.056 ;
     RECT  0.06 58.056 2.408 58.128 ;
     RECT  0.084 58.128 2.408 58.152 ;
     RECT  0.06 58.152 2.408 58.224 ;
     RECT  0.084 58.224 2.408 58.248 ;
     RECT  0.06 58.248 2.408 58.32 ;
     RECT  0.084 58.32 2.408 58.344 ;
     RECT  0.06 58.344 2.408 58.416 ;
     RECT  0.084 58.416 2.408 58.44 ;
     RECT  0.06 58.44 2.408 58.512 ;
     RECT  0.084 58.512 2.408 58.536 ;
     RECT  0.06 58.536 2.408 58.608 ;
     RECT  0.084 58.608 2.408 58.632 ;
     RECT  0.06 58.632 2.408 58.704 ;
     RECT  0.084 58.704 2.408 58.728 ;
     RECT  0.06 58.728 2.408 58.8 ;
     RECT  0.084 58.8 2.408 58.824 ;
     RECT  0.06 58.824 2.408 58.896 ;
     RECT  0.084 58.896 2.408 58.92 ;
     RECT  0.06 58.92 2.408 58.992 ;
     RECT  0.084 58.992 2.408 59.016 ;
     RECT  0.06 59.016 2.408 59.088 ;
     RECT  0.084 59.088 2.408 59.112 ;
     RECT  0.06 59.112 2.408 59.184 ;
     RECT  0.084 59.184 2.408 59.208 ;
     RECT  0.06 59.208 2.408 59.28 ;
     RECT  0.084 59.28 2.408 59.304 ;
     RECT  0.06 59.304 2.408 59.376 ;
     RECT  0.084 59.376 2.408 59.4 ;
     RECT  0.06 59.4 2.408 59.472 ;
     RECT  0.084 59.472 2.408 59.496 ;
     RECT  0.06 59.496 2.408 59.568 ;
     RECT  0.084 59.568 2.408 59.592 ;
     RECT  0.06 59.592 2.408 59.664 ;
     RECT  0.084 59.664 2.408 59.688 ;
     RECT  0.06 59.688 2.408 59.76 ;
     RECT  0.084 59.76 2.408 59.784 ;
     RECT  0.06 59.784 2.408 59.856 ;
     RECT  0.084 59.856 2.408 59.88 ;
     RECT  0.06 59.88 2.408 59.952 ;
     RECT  0.084 59.952 2.408 59.976 ;
     RECT  0.06 59.976 2.408 60.048 ;
     RECT  0.084 60.048 2.408 60.072 ;
     RECT  0.06 60.072 2.408 60.144 ;
     RECT  0.084 60.144 2.408 60.168 ;
     RECT  0.06 60.168 2.408 60.24 ;
     RECT  0.084 60.24 2.408 60.264 ;
     RECT  0.06 60.264 2.408 60.336 ;
     RECT  0.084 60.336 2.408 60.36 ;
     RECT  0.06 60.36 2.408 60.432 ;
     RECT  0.084 60.432 2.408 60.456 ;
     RECT  0.06 60.456 2.408 60.528 ;
     RECT  0.084 60.528 2.408 60.552 ;
     RECT  0.06 60.552 2.408 60.624 ;
     RECT  0.084 60.624 2.408 60.648 ;
     RECT  0.06 60.648 2.408 60.72 ;
     RECT  0.084 60.72 2.408 60.744 ;
     RECT  0.06 60.744 2.408 60.816 ;
     RECT  0.084 60.816 2.408 60.84 ;
     RECT  0.06 60.84 2.408 60.912 ;
     RECT  0.084 60.912 2.408 60.936 ;
     RECT  0.06 60.936 2.408 61.008 ;
     RECT  0.084 61.008 2.408 61.032 ;
     RECT  0.06 61.032 2.408 61.104 ;
     RECT  0.084 61.104 2.408 61.128 ;
     RECT  0.06 61.128 2.408 61.2 ;
     RECT  0.084 61.2 2.408 61.224 ;
     RECT  0.06 61.224 2.408 61.296 ;
     RECT  0.084 61.296 2.408 61.32 ;
     RECT  0.06 61.32 2.408 61.392 ;
     RECT  0.084 61.392 2.408 61.416 ;
     RECT  0.06 61.416 2.408 61.488 ;
     RECT  0.084 61.488 2.408 61.512 ;
     RECT  0.06 61.512 2.408 61.584 ;
     RECT  0.084 61.584 2.408 61.608 ;
     RECT  0.06 61.608 2.408 61.68 ;
     RECT  0.084 61.68 2.408 61.704 ;
     RECT  0.06 61.704 2.408 61.776 ;
     RECT  0.084 61.776 2.408 61.8 ;
     RECT  0.06 61.8 2.408 61.872 ;
     RECT  0.084 61.872 2.408 61.896 ;
     RECT  0.06 61.896 2.408 61.968 ;
     RECT  0.084 61.968 2.408 61.992 ;
     RECT  0.06 61.992 2.408 62.064 ;
     RECT  0.084 62.064 2.408 62.088 ;
     RECT  0.06 62.088 2.408 62.16 ;
     RECT  0.084 62.16 2.408 62.184 ;
     RECT  0.06 62.184 2.408 62.256 ;
     RECT  0.084 62.256 2.408 62.28 ;
     RECT  0.06 62.28 2.408 62.352 ;
     RECT  0.084 62.352 2.408 62.376 ;
     RECT  0.06 62.376 2.408 62.448 ;
     RECT  0.084 62.448 2.408 62.472 ;
     RECT  0.06 62.472 2.408 62.544 ;
     RECT  0.084 62.544 2.408 62.568 ;
     RECT  0.06 62.568 2.408 62.64 ;
     RECT  0.084 62.64 2.408 62.664 ;
     RECT  0.06 62.664 2.408 62.736 ;
     RECT  0.084 62.736 2.408 62.76 ;
     RECT  0.06 62.76 2.408 62.832 ;
     RECT  0.084 62.832 2.408 62.856 ;
     RECT  0.06 62.856 2.408 62.928 ;
     RECT  0.084 62.928 2.408 62.952 ;
     RECT  0.06 62.952 2.408 63.024 ;
     RECT  0.084 63.024 2.408 63.048 ;
     RECT  0.06 63.048 2.408 63.12 ;
     RECT  0.084 63.12 2.408 63.144 ;
     RECT  0.06 63.144 2.408 63.216 ;
     RECT  0.084 63.216 2.408 63.24 ;
     RECT  0.06 63.24 2.408 63.312 ;
     RECT  0.084 63.312 2.408 63.336 ;
     RECT  0.06 63.336 2.408 63.408 ;
     RECT  0.084 63.408 2.408 63.432 ;
     RECT  0.06 63.432 2.408 63.504 ;
     RECT  0.084 63.504 2.408 63.528 ;
     RECT  0.06 63.528 2.408 63.6 ;
     RECT  0.084 63.6 2.408 63.624 ;
     RECT  0.06 63.624 2.408 63.696 ;
     RECT  0.084 63.696 2.408 63.72 ;
     RECT  0.06 63.72 2.408 63.792 ;
     RECT  0.084 63.792 2.408 63.816 ;
     RECT  0.06 63.816 2.408 63.888 ;
     RECT  0.084 63.888 2.408 63.912 ;
     RECT  0.06 63.912 2.408 63.984 ;
     RECT  0.084 63.984 2.408 64.008 ;
     RECT  0.06 64.008 2.408 64.08 ;
     RECT  0.084 64.08 2.408 64.104 ;
     RECT  0.06 64.104 2.408 64.176 ;
     RECT  0.084 64.176 2.408 64.2 ;
     RECT  0.06 64.2 2.408 64.272 ;
     RECT  0.084 64.272 2.408 64.296 ;
     RECT  0.06 64.296 2.408 64.368 ;
     RECT  0.084 64.368 2.408 64.392 ;
     RECT  0.06 64.392 2.408 64.464 ;
     RECT  0.084 64.464 2.408 64.488 ;
     RECT  0.06 64.488 2.408 64.56 ;
     RECT  0.084 64.56 2.408 64.584 ;
     RECT  0.06 64.584 2.408 64.656 ;
     RECT  0.084 64.656 2.408 64.68 ;
     RECT  0.06 64.68 2.408 64.752 ;
     RECT  0.084 64.752 2.408 64.776 ;
     RECT  0.06 64.776 2.408 64.848 ;
     RECT  0.084 64.848 2.408 64.872 ;
     RECT  0.06 64.872 2.408 64.944 ;
     RECT  0.084 64.944 2.408 64.968 ;
     RECT  0.06 64.968 2.408 65.04 ;
     RECT  0.084 65.04 2.408 65.064 ;
     RECT  0.06 65.064 2.408 65.136 ;
     RECT  0.084 65.136 2.408 65.16 ;
     RECT  0.06 65.16 2.408 65.232 ;
     RECT  0.084 65.232 2.408 65.256 ;
     RECT  0.06 65.256 2.408 65.328 ;
     RECT  0.084 65.328 2.408 65.352 ;
     RECT  0.06 65.352 2.408 65.424 ;
     RECT  0.084 65.424 2.408 65.448 ;
     RECT  0.06 65.448 2.408 65.52 ;
     RECT  0.084 65.52 2.408 65.544 ;
     RECT  0.06 65.544 2.408 65.616 ;
     RECT  0.084 65.616 2.408 65.64 ;
     RECT  0.06 65.64 2.408 65.712 ;
     RECT  0.084 65.712 2.408 65.736 ;
     RECT  0.06 65.736 2.408 65.808 ;
     RECT  0.084 65.808 2.408 65.832 ;
     RECT  0.06 65.832 2.408 65.904 ;
     RECT  0.084 65.904 2.408 65.928 ;
     RECT  0.06 65.928 2.408 66 ;
     RECT  0.084 66 2.408 66.024 ;
     RECT  0.06 66.024 2.408 66.096 ;
     RECT  0.084 66.096 2.408 66.12 ;
     RECT  0.06 66.12 2.408 66.192 ;
     RECT  0.084 66.192 2.408 66.216 ;
     RECT  0.06 66.216 2.408 66.288 ;
     RECT  0.084 66.288 2.408 66.312 ;
     RECT  0.06 66.312 2.408 66.384 ;
     RECT  0.084 66.384 2.408 66.408 ;
     RECT  0.06 66.408 2.408 66.48 ;
     RECT  0.084 66.48 2.408 66.504 ;
     RECT  0.06 66.504 2.408 66.576 ;
     RECT  0.084 66.576 2.408 66.6 ;
     RECT  0.06 66.6 2.408 66.672 ;
     RECT  0.084 66.672 2.408 66.696 ;
     RECT  0.06 66.696 2.408 66.768 ;
     RECT  0.084 66.768 2.408 66.792 ;
     RECT  0.06 66.792 2.408 66.864 ;
     RECT  0.084 66.864 2.408 66.888 ;
     RECT  0.06 66.888 2.408 66.96 ;
     RECT  0.084 66.96 2.408 66.984 ;
     RECT  0.06 66.984 2.408 67.056 ;
     RECT  0.084 67.056 2.408 67.08 ;
     RECT  0.06 67.08 2.408 67.152 ;
     RECT  0.084 67.152 2.408 67.176 ;
     RECT  0.06 67.176 2.408 67.248 ;
     RECT  0.084 67.248 2.408 67.272 ;
     RECT  0.06 67.272 2.408 67.344 ;
     RECT  0.084 67.344 2.408 67.368 ;
     RECT  0.06 67.368 2.408 67.44 ;
     RECT  0.084 67.44 2.408 67.464 ;
     RECT  0.06 67.464 2.408 67.536 ;
     RECT  0.084 67.536 2.408 67.56 ;
     RECT  0.06 67.56 2.408 67.632 ;
     RECT  0.084 67.632 2.408 67.656 ;
     RECT  0.06 67.656 2.408 67.728 ;
     RECT  0.084 67.728 2.408 67.752 ;
     RECT  0.06 67.752 2.408 67.824 ;
     RECT  0.084 67.824 2.408 67.848 ;
     RECT  0.06 67.848 2.408 67.92 ;
     RECT  0.084 67.92 2.408 67.944 ;
     RECT  0.06 67.944 2.408 68.016 ;
     RECT  0.084 68.016 2.408 68.04 ;
     RECT  0.06 68.04 2.408 68.112 ;
     RECT  0.084 68.112 2.408 68.136 ;
     RECT  0.06 68.136 2.408 68.208 ;
     RECT  0.084 68.208 2.408 68.232 ;
     RECT  0.06 68.232 2.408 68.304 ;
     RECT  0.084 68.304 2.408 68.328 ;
     RECT  0.06 68.328 2.408 68.4 ;
     RECT  0.084 68.4 2.408 68.424 ;
     RECT  0.06 68.424 2.408 68.496 ;
     RECT  0.084 68.496 2.408 68.52 ;
     RECT  0.06 68.52 2.408 68.592 ;
     RECT  0.084 68.592 2.408 68.616 ;
     RECT  0.06 68.616 2.408 68.688 ;
     RECT  0.084 68.688 2.408 68.712 ;
     RECT  0.06 68.712 2.408 68.784 ;
     RECT  0.084 68.784 2.408 68.808 ;
     RECT  0.06 68.808 2.408 68.88 ;
     RECT  0.084 68.88 2.408 68.904 ;
     RECT  0.06 68.904 2.408 68.976 ;
     RECT  0.084 68.976 2.408 69 ;
     RECT  0.06 69 2.408 69.072 ;
     RECT  0.084 69.072 2.408 69.096 ;
     RECT  0.06 69.096 2.408 69.168 ;
     RECT  0.084 69.168 2.408 69.192 ;
     RECT  0.06 69.192 2.408 69.264 ;
     RECT  0.084 69.264 2.408 69.288 ;
     RECT  0.06 69.288 2.408 69.36 ;
     RECT  0.084 69.36 2.408 69.384 ;
     RECT  0.06 69.384 2.408 69.456 ;
     RECT  0.084 69.456 2.408 69.48 ;
     RECT  0.06 69.48 2.408 69.552 ;
     RECT  0.084 69.552 2.408 69.576 ;
     RECT  0.06 69.576 2.408 69.648 ;
     RECT  0.084 69.648 2.408 69.672 ;
     RECT  0.06 69.672 2.408 69.744 ;
     RECT  0.084 69.744 2.408 69.768 ;
     RECT  0.06 69.768 2.408 69.84 ;
     RECT  0.084 69.84 2.408 69.864 ;
     RECT  0.06 69.864 2.408 69.936 ;
     RECT  0.084 69.936 2.408 69.96 ;
     RECT  0.06 69.96 2.408 70.032 ;
     RECT  0.084 70.032 2.408 70.056 ;
     RECT  0.06 70.056 2.408 70.128 ;
     RECT  0.084 70.128 2.408 70.152 ;
     RECT  0.06 70.152 2.408 70.224 ;
     RECT  0.084 70.224 2.408 70.248 ;
     RECT  0.06 70.248 2.408 70.32 ;
     RECT  0.084 70.32 2.408 70.344 ;
     RECT  0.06 70.344 2.408 70.416 ;
     RECT  0.084 70.416 2.408 70.44 ;
     RECT  0.06 70.44 2.408 70.512 ;
     RECT  0.084 70.512 2.408 70.536 ;
     RECT  0.06 70.536 2.408 70.608 ;
     RECT  0.084 70.608 2.408 70.632 ;
     RECT  0.06 70.632 2.408 70.704 ;
     RECT  0.084 70.704 2.408 70.728 ;
     RECT  0.06 70.728 2.408 70.8 ;
     RECT  0.084 70.8 2.408 70.824 ;
     RECT  0.06 70.824 2.408 70.896 ;
     RECT  0.084 70.896 2.408 70.92 ;
     RECT  0.06 70.92 2.408 70.992 ;
     RECT  0.084 70.992 2.408 71.016 ;
     RECT  0.06 71.016 2.408 71.088 ;
     RECT  0.084 71.088 2.408 71.112 ;
     RECT  0.06 71.112 2.408 71.184 ;
     RECT  0.084 71.184 2.408 71.208 ;
     RECT  0.06 71.208 2.408 71.952 ;
     RECT  0.084 71.952 2.408 71.976 ;
     RECT  0.06 71.976 2.408 72.048 ;
     RECT  0.084 72.048 2.408 72.072 ;
     RECT  0.06 72.072 2.408 72.144 ;
     RECT  0.084 72.144 2.408 72.168 ;
     RECT  0.06 72.168 2.408 72.24 ;
     RECT  0.084 72.24 2.408 72.264 ;
     RECT  0.06 72.264 2.408 72.336 ;
     RECT  0.084 72.336 2.408 72.36 ;
     RECT  0.06 72.36 2.408 72.432 ;
     RECT  0.084 72.432 2.408 72.456 ;
     RECT  0.06 72.456 2.408 72.528 ;
     RECT  0.084 72.528 2.408 72.552 ;
     RECT  0.06 72.552 2.408 72.624 ;
     RECT  0.084 72.624 2.408 72.648 ;
     RECT  0.06 72.648 2.408 72.72 ;
     RECT  0.084 72.72 2.408 72.744 ;
     RECT  0.06 72.744 2.408 72.816 ;
     RECT  0.084 72.816 2.408 72.84 ;
     RECT  0.06 72.84 2.408 72.912 ;
     RECT  0.084 72.912 2.408 72.936 ;
     RECT  0.06 72.936 2.408 73.008 ;
     RECT  0.084 73.008 2.408 73.032 ;
     RECT  0.06 73.032 2.408 73.104 ;
     RECT  0.084 73.104 2.408 73.128 ;
     RECT  0.06 73.128 2.408 73.2 ;
     RECT  0.084 73.2 2.408 73.224 ;
     RECT  0.06 73.224 2.408 73.296 ;
     RECT  0.084 73.296 2.408 73.32 ;
     RECT  0.06 73.32 2.408 73.392 ;
     RECT  0.084 73.392 2.408 73.416 ;
     RECT  0.06 73.416 2.408 73.488 ;
     RECT  0.084 73.488 2.408 73.512 ;
     RECT  0.06 73.512 2.408 73.584 ;
     RECT  0.084 73.584 2.408 73.608 ;
     RECT  0.06 73.608 2.408 73.68 ;
     RECT  0.084 73.68 2.408 73.704 ;
     RECT  0.06 73.704 2.408 73.776 ;
     RECT  0.084 73.776 2.408 73.8 ;
     RECT  0.06 73.8 2.408 73.872 ;
     RECT  0.084 73.872 2.408 73.896 ;
     RECT  0.06 73.896 2.408 73.968 ;
     RECT  0.084 73.968 2.408 73.992 ;
     RECT  0.06 73.992 2.408 74.064 ;
     RECT  0.084 74.064 2.408 74.088 ;
     RECT  0.06 74.088 2.408 74.16 ;
     RECT  0.084 74.16 2.408 74.184 ;
     RECT  0.06 74.184 2.408 74.256 ;
     RECT  0.084 74.256 2.408 74.28 ;
     RECT  0.06 74.28 2.408 74.352 ;
     RECT  0.084 74.352 2.408 74.376 ;
     RECT  0.06 74.376 2.408 74.448 ;
     RECT  0.084 74.448 2.408 74.472 ;
     RECT  0.06 74.472 2.408 74.544 ;
     RECT  0.084 74.544 2.408 74.568 ;
     RECT  0.06 74.568 2.408 74.64 ;
     RECT  0.084 74.64 2.408 74.664 ;
     RECT  0.06 74.664 2.408 74.736 ;
     RECT  0.084 74.736 2.408 74.76 ;
     RECT  0.06 74.76 2.408 74.832 ;
     RECT  0.084 74.832 2.408 74.856 ;
     RECT  0.06 74.856 2.408 74.928 ;
     RECT  0.084 74.928 2.408 74.952 ;
     RECT  0.06 74.952 2.408 75.024 ;
     RECT  0.084 75.024 2.408 75.048 ;
     RECT  0.06 75.048 2.408 75.12 ;
     RECT  0.084 75.12 2.408 75.144 ;
     RECT  0.06 75.144 2.408 75.216 ;
     RECT  0.084 75.216 2.408 75.24 ;
     RECT  0.06 75.24 2.408 75.312 ;
     RECT  0.084 75.312 2.408 75.336 ;
     RECT  0.06 75.336 2.408 75.408 ;
     RECT  0.084 75.408 2.408 75.432 ;
     RECT  0.06 75.432 2.408 75.504 ;
     RECT  0.084 75.504 2.408 75.528 ;
     RECT  0.06 75.528 2.408 75.6 ;
     RECT  0.084 75.6 2.408 75.624 ;
     RECT  0.06 75.624 2.408 75.696 ;
     RECT  0.084 75.696 2.408 75.72 ;
     RECT  0.06 75.72 2.408 75.792 ;
     RECT  0.084 75.792 2.408 75.816 ;
     RECT  0.06 75.816 2.408 75.888 ;
     RECT  0.084 75.888 2.408 75.912 ;
     RECT  0.06 75.912 2.408 75.984 ;
     RECT  0.084 75.984 2.408 76.008 ;
     RECT  0.06 76.008 2.408 76.08 ;
     RECT  0.084 76.08 2.408 76.104 ;
     RECT  0.06 76.104 2.408 76.176 ;
     RECT  0.084 76.176 2.408 76.2 ;
     RECT  0.06 76.2 2.408 76.272 ;
     RECT  0.084 76.272 2.408 76.296 ;
     RECT  0.06 76.296 2.408 76.368 ;
     RECT  0.084 76.368 2.408 76.392 ;
     RECT  0.06 76.392 2.408 76.464 ;
     RECT  0.084 76.464 2.408 76.488 ;
     RECT  0.06 76.488 2.408 76.56 ;
     RECT  0.084 76.56 2.408 76.584 ;
     RECT  0.06 76.584 2.408 76.656 ;
     RECT  0.084 76.656 2.408 76.68 ;
     RECT  0.06 76.68 2.408 76.752 ;
     RECT  0.084 76.752 2.408 76.776 ;
     RECT  0.06 76.776 2.408 76.848 ;
     RECT  0.084 76.848 2.408 76.872 ;
     RECT  0.06 76.872 2.408 76.944 ;
     RECT  0.084 76.944 2.408 76.968 ;
     RECT  0.06 76.968 2.408 77.04 ;
     RECT  0.084 77.04 2.408 77.064 ;
     RECT  0.06 77.064 2.408 77.136 ;
     RECT  0.084 77.136 2.408 77.16 ;
     RECT  0.06 77.16 2.408 77.232 ;
     RECT  0.084 77.232 2.408 77.256 ;
     RECT  0.06 77.256 2.408 77.328 ;
     RECT  0.084 77.328 2.408 77.352 ;
     RECT  0.06 77.352 2.408 77.424 ;
     RECT  0.084 77.424 2.408 77.448 ;
     RECT  0.06 77.448 2.408 77.52 ;
     RECT  0.084 77.52 2.408 77.544 ;
     RECT  0.06 77.544 2.408 77.616 ;
     RECT  0.084 77.616 2.408 77.64 ;
     RECT  0.06 77.64 2.408 77.712 ;
     RECT  0.084 77.712 2.408 77.736 ;
     RECT  0.06 77.736 2.408 77.808 ;
     RECT  0.084 77.808 2.408 77.832 ;
     RECT  0.06 77.832 2.408 77.904 ;
     RECT  0.084 77.904 2.408 77.928 ;
     RECT  0.06 77.928 2.408 78 ;
     RECT  0.084 78 2.408 78.024 ;
     RECT  0.06 78.024 2.408 78.096 ;
     RECT  0.084 78.096 2.408 78.12 ;
     RECT  0.06 78.12 2.408 78.192 ;
     RECT  0.084 78.192 2.408 78.216 ;
     RECT  0.06 78.216 2.408 78.288 ;
     RECT  0.084 78.288 2.408 78.312 ;
     RECT  0.06 78.312 2.408 78.384 ;
     RECT  0.084 78.384 2.408 78.408 ;
     RECT  0.06 78.408 2.408 78.48 ;
     RECT  0.084 78.48 2.408 78.504 ;
     RECT  0.06 78.504 2.408 78.576 ;
     RECT  0.084 78.576 2.408 78.6 ;
     RECT  0.06 78.6 2.408 78.672 ;
     RECT  0.084 78.672 2.408 78.696 ;
     RECT  0.06 78.696 2.408 78.768 ;
     RECT  0.084 78.768 2.408 78.792 ;
     RECT  0.06 78.792 2.408 78.864 ;
     RECT  0.084 78.864 2.408 78.888 ;
     RECT  0.06 78.888 2.408 78.96 ;
     RECT  0.084 78.96 2.408 78.984 ;
     RECT  0.06 78.984 2.408 79.056 ;
     RECT  0.084 79.056 2.408 79.08 ;
     RECT  0.06 79.08 2.408 79.152 ;
     RECT  0.084 79.152 2.408 79.176 ;
     RECT  0.06 79.176 2.408 79.248 ;
     RECT  0.084 79.248 2.408 79.272 ;
     RECT  0.06 79.272 2.408 79.344 ;
     RECT  0.084 79.344 2.408 79.368 ;
     RECT  0.06 79.368 2.408 79.44 ;
     RECT  0.084 79.44 2.408 79.464 ;
     RECT  0.06 79.464 2.408 79.536 ;
     RECT  0.084 79.536 2.408 79.56 ;
     RECT  0.06 79.56 2.408 79.632 ;
     RECT  0.084 79.632 2.408 79.656 ;
     RECT  0.06 79.656 2.408 79.728 ;
     RECT  0.084 79.728 2.408 79.752 ;
     RECT  0.06 79.752 2.408 79.824 ;
     RECT  0.084 79.824 2.408 79.848 ;
     RECT  0.06 79.848 2.408 79.92 ;
     RECT  0.084 79.92 2.408 79.944 ;
     RECT  0.06 79.944 2.408 80.016 ;
     RECT  0.084 80.016 2.408 80.04 ;
     RECT  0.06 80.04 2.408 80.112 ;
     RECT  0.084 80.112 2.408 80.136 ;
     RECT  0.06 80.136 2.408 80.208 ;
     RECT  0.084 80.208 2.408 80.232 ;
     RECT  0.06 80.232 2.408 80.304 ;
     RECT  0.084 80.304 2.408 80.328 ;
     RECT  0.06 80.328 2.408 80.4 ;
     RECT  0.084 80.4 2.408 80.424 ;
     RECT  0.06 80.424 2.408 80.496 ;
     RECT  0.084 80.496 2.408 80.52 ;
     RECT  0.06 80.52 2.408 80.592 ;
     RECT  0.084 80.592 2.408 80.616 ;
     RECT  0.06 80.616 2.408 80.688 ;
     RECT  0.084 80.688 2.408 80.712 ;
     RECT  0.06 80.712 2.408 80.784 ;
     RECT  0.084 80.784 2.408 80.808 ;
     RECT  0.06 80.808 2.408 80.88 ;
     RECT  0.084 80.88 2.408 80.904 ;
     RECT  0.06 80.904 2.408 80.976 ;
     RECT  0.084 80.976 2.408 81 ;
     RECT  0.06 81 2.408 81.072 ;
     RECT  0.084 81.072 2.408 81.096 ;
     RECT  0.06 81.096 2.408 81.168 ;
     RECT  0.084 81.168 2.408 81.192 ;
     RECT  0.06 81.192 2.408 81.264 ;
     RECT  0.084 81.264 2.408 81.288 ;
     RECT  0.06 81.288 2.408 81.36 ;
     RECT  0.084 81.36 2.408 81.384 ;
     RECT  0.06 81.384 2.408 81.456 ;
     RECT  0.084 81.456 2.408 81.48 ;
     RECT  0.06 81.48 2.408 81.552 ;
     RECT  0.084 81.552 2.408 81.576 ;
     RECT  0.06 81.576 2.408 81.648 ;
     RECT  0.084 81.648 2.408 81.672 ;
     RECT  0.06 81.672 2.408 81.744 ;
     RECT  0.084 81.744 2.408 81.768 ;
     RECT  0.06 81.768 2.408 81.84 ;
     RECT  0.084 81.84 2.408 81.864 ;
     RECT  0.06 81.864 2.408 81.936 ;
     RECT  0.084 81.936 2.408 81.96 ;
     RECT  0.06 81.96 2.408 82.032 ;
     RECT  0.084 82.032 2.408 82.056 ;
     RECT  0.06 82.056 2.408 82.128 ;
     RECT  0.084 82.128 2.408 82.152 ;
     RECT  0.06 82.152 2.408 82.224 ;
     RECT  0.084 82.224 2.408 82.248 ;
     RECT  0.06 82.248 2.408 82.32 ;
     RECT  0.084 82.32 2.408 82.344 ;
     RECT  0.06 82.344 2.408 82.416 ;
     RECT  0.084 82.416 2.408 82.44 ;
     RECT  0.06 82.44 2.408 82.512 ;
     RECT  0.084 82.512 2.408 82.536 ;
     RECT  0.06 82.536 2.408 82.608 ;
     RECT  0.084 82.608 2.408 82.632 ;
     RECT  0.06 82.632 2.408 82.704 ;
     RECT  0.084 82.704 2.408 82.728 ;
     RECT  0.06 82.728 2.408 82.8 ;
     RECT  0.084 82.8 2.408 82.824 ;
     RECT  0.06 82.824 2.408 82.896 ;
     RECT  0.084 82.896 2.408 82.92 ;
     RECT  0.06 82.92 2.408 82.992 ;
     RECT  0.084 82.992 2.408 83.016 ;
     RECT  0.06 83.016 2.408 83.088 ;
     RECT  0.084 83.088 2.408 83.112 ;
     RECT  0.06 83.112 2.408 83.184 ;
     RECT  0.084 83.184 2.408 83.208 ;
     RECT  0.06 83.208 2.408 83.28 ;
     RECT  0.084 83.28 2.408 83.304 ;
     RECT  0.06 83.304 2.408 83.376 ;
     RECT  0.084 83.376 2.408 83.4 ;
     RECT  0.06 83.4 2.408 83.472 ;
     RECT  0.084 83.472 2.408 83.496 ;
     RECT  0.06 83.496 2.408 83.568 ;
     RECT  0.084 83.568 2.408 83.592 ;
     RECT  0.06 83.592 2.408 83.664 ;
     RECT  0.084 83.664 2.408 83.688 ;
     RECT  0.06 83.688 2.408 83.76 ;
     RECT  0.084 83.76 2.408 83.784 ;
     RECT  0.06 83.784 2.408 83.856 ;
     RECT  0.084 83.856 2.408 83.88 ;
     RECT  0.06 83.88 2.408 83.952 ;
     RECT  0.084 83.952 2.408 83.976 ;
     RECT  0.06 83.976 2.408 84.048 ;
     RECT  0.084 84.048 2.408 84.072 ;
     RECT  0.06 84.072 2.408 84.144 ;
     RECT  0.084 84.144 2.408 84.168 ;
     RECT  0.06 84.168 2.408 84.24 ;
     RECT  0.084 84.24 2.408 84.264 ;
     RECT  0.06 84.264 2.408 84.336 ;
     RECT  0.084 84.336 2.408 84.36 ;
     RECT  0.06 84.36 2.408 84.432 ;
     RECT  0.084 84.432 2.408 84.456 ;
     RECT  0.06 84.456 2.408 84.528 ;
     RECT  0.084 84.528 2.408 84.552 ;
     RECT  0.06 84.552 2.408 84.624 ;
     RECT  0.084 84.624 2.408 84.648 ;
     RECT  0.06 84.648 2.408 84.72 ;
     RECT  0.084 84.72 2.408 84.744 ;
     RECT  0.06 84.744 2.408 84.816 ;
     RECT  0.084 84.816 2.408 84.84 ;
     RECT  0.06 84.84 2.408 84.912 ;
     RECT  0.084 84.912 2.408 84.936 ;
     RECT  0.06 84.936 2.408 85.008 ;
     RECT  0.084 85.008 2.408 85.032 ;
     RECT  0.06 85.032 2.408 85.104 ;
     RECT  0.084 85.104 2.408 85.128 ;
     RECT  0.06 85.128 2.408 85.2 ;
     RECT  0.084 85.2 2.408 85.224 ;
     RECT  0.06 85.224 2.408 85.296 ;
     RECT  0.084 85.296 2.408 85.32 ;
     RECT  0.06 85.32 2.408 85.392 ;
     RECT  0.084 85.392 2.408 85.416 ;
     RECT  0.06 85.416 2.408 85.488 ;
     RECT  0.084 85.488 2.408 85.512 ;
     RECT  0.06 85.512 2.408 85.584 ;
     RECT  0.084 85.584 2.408 85.608 ;
     RECT  0.06 85.608 2.408 85.68 ;
     RECT  0.084 85.68 2.408 85.704 ;
     RECT  0.06 85.704 2.408 85.776 ;
     RECT  0.084 85.776 2.408 85.8 ;
     RECT  0.06 85.8 2.408 85.872 ;
     RECT  0.084 85.872 2.408 85.896 ;
     RECT  0.06 85.896 2.408 85.968 ;
     RECT  0.084 85.968 2.408 85.992 ;
     RECT  0.06 85.992 2.408 86.064 ;
     RECT  0.084 86.064 2.408 86.088 ;
     RECT  0.06 86.088 2.408 86.16 ;
     RECT  0.084 86.16 2.408 86.184 ;
     RECT  0.06 86.184 2.408 86.256 ;
     RECT  0.084 86.256 2.408 86.28 ;
     RECT  0.06 86.28 2.408 86.352 ;
     RECT  0.084 86.352 2.408 86.376 ;
     RECT  0.06 86.376 2.408 86.448 ;
     RECT  0.084 86.448 2.408 86.472 ;
     RECT  0.06 86.472 2.408 86.544 ;
     RECT  0.084 86.544 2.408 86.568 ;
     RECT  0.06 86.568 2.408 86.64 ;
     RECT  0.084 86.64 2.408 86.664 ;
     RECT  0.06 86.664 2.408 86.736 ;
     RECT  0.084 86.736 2.408 86.76 ;
     RECT  0.06 86.76 2.408 86.832 ;
     RECT  0.084 86.832 2.408 86.856 ;
     RECT  0.06 86.856 2.408 86.928 ;
     RECT  0.084 86.928 2.408 86.952 ;
     RECT  0.06 86.952 2.408 87.024 ;
     RECT  0.084 87.024 2.408 87.048 ;
     RECT  0.06 87.048 2.408 87.12 ;
     RECT  0.084 87.12 2.408 87.144 ;
     RECT  0.06 87.144 2.408 87.216 ;
     RECT  0.084 87.216 2.408 87.24 ;
     RECT  0.06 87.24 2.408 87.312 ;
     RECT  0.084 87.312 2.408 87.336 ;
     RECT  0.06 87.336 2.408 87.408 ;
     RECT  0.084 87.408 2.408 87.432 ;
     RECT  0.06 87.432 2.408 87.504 ;
     RECT  0.084 87.504 2.408 87.528 ;
     RECT  0.06 87.528 2.408 87.6 ;
     RECT  0.084 87.6 2.408 87.624 ;
     RECT  0.06 87.624 2.408 87.696 ;
     RECT  0.084 87.696 2.408 87.72 ;
     RECT  0.06 87.72 2.408 87.792 ;
     RECT  0.084 87.792 2.408 87.816 ;
     RECT  0.06 87.816 2.408 87.888 ;
     RECT  0.084 87.888 2.408 87.912 ;
     RECT  0.06 87.912 2.408 87.984 ;
     RECT  0.084 87.984 2.408 88.008 ;
     RECT  0.06 88.008 2.408 88.08 ;
     RECT  0.084 88.08 2.408 88.104 ;
     RECT  0.06 88.104 2.408 88.176 ;
     RECT  0.084 88.176 2.408 88.2 ;
     RECT  0.06 88.2 2.408 88.272 ;
     RECT  0.084 88.272 2.408 88.296 ;
     RECT  0.06 88.296 2.408 88.368 ;
     RECT  0.084 88.368 2.408 88.392 ;
     RECT  0.06 88.392 2.408 88.464 ;
     RECT  0.084 88.464 2.408 88.488 ;
     RECT  0.06 88.488 2.408 88.56 ;
     RECT  0.084 88.56 2.408 88.584 ;
     RECT  0.06 88.584 2.408 88.656 ;
     RECT  0.084 88.656 2.408 88.68 ;
     RECT  0.06 88.68 2.408 88.752 ;
     RECT  0.084 88.752 2.408 88.776 ;
     RECT  0.06 88.776 2.408 88.848 ;
     RECT  0.084 88.848 2.408 88.872 ;
     RECT  0.06 88.872 2.408 88.944 ;
     RECT  0.084 88.944 2.408 88.968 ;
     RECT  0.06 88.968 2.408 89.04 ;
     RECT  0.084 89.04 2.408 89.064 ;
     RECT  0.06 89.064 2.408 89.136 ;
     RECT  0.084 89.136 2.408 89.16 ;
     RECT  0.06 89.16 2.408 89.232 ;
     RECT  0.084 89.232 2.408 89.256 ;
     RECT  0.06 89.256 2.408 89.328 ;
     RECT  0.084 89.328 2.408 89.352 ;
     RECT  0.06 89.352 2.408 89.424 ;
     RECT  0.084 89.424 2.408 89.448 ;
     RECT  0.06 89.448 2.408 89.52 ;
     RECT  0.084 89.52 2.408 89.544 ;
     RECT  0.06 89.544 2.408 89.616 ;
     RECT  0.084 89.616 2.408 89.64 ;
     RECT  0.06 89.64 2.408 89.712 ;
     RECT  0.084 89.712 2.408 89.736 ;
     RECT  0.06 89.736 2.408 89.808 ;
     RECT  0.084 89.808 2.408 89.832 ;
     RECT  0.06 89.832 2.408 89.904 ;
     RECT  0.084 89.904 2.408 89.928 ;
     RECT  0.06 89.928 2.408 90 ;
     RECT  0.084 90 2.408 90.024 ;
     RECT  0.06 90.024 2.408 90.096 ;
     RECT  0.084 90.096 2.408 90.12 ;
     RECT  0.06 90.12 2.408 90.192 ;
     RECT  0.084 90.192 2.408 90.216 ;
     RECT  0.06 90.216 2.408 90.288 ;
     RECT  0.084 90.288 2.408 90.312 ;
     RECT  0.06 90.312 2.408 90.384 ;
     RECT  0.084 90.384 2.408 90.408 ;
     RECT  2.408 2.148 2.512 127.452 ;
     RECT  2.512 2.418 2.704 127.182 ;
     RECT  2.704 39.072 2.845 92.04 ;
     RECT  2.845 39.072 2.873 89.544 ;
     RECT  2.873 66.72 2.881 89.544 ;
     RECT  2.881 88.128 2.945 89.544 ;
     RECT  2.873 39.072 3.881 65.736 ;
     RECT  2.845 90.816 3.949 92.04 ;
     RECT  3.881 39.312 3.985 65.736 ;
     RECT  2.881 66.72 3.985 87.144 ;
     RECT  3.985 39.312 4.021 87.144 ;
     RECT  2.945 88.368 4.021 89.544 ;
     RECT  4.021 39.312 4.057 89.544 ;
     RECT  3.949 90.816 4.057 92.136 ;
     RECT  4.057 39.312 5.108 92.136 ;
     RECT  5.108 2.148 5.212 127.452 ;
     RECT  5.212 2.418 5.404 127.182 ;
     RECT  5.404 39.648 5.465 91.944 ;
     RECT  5.465 39.648 5.609 91.8 ;
     RECT  5.609 39.648 5.825 91.416 ;
     RECT  5.825 91.2 5.933 91.416 ;
     RECT  5.825 39.648 6.172 90.072 ;
     RECT  6.172 40.416 6.725 90.072 ;
     RECT  5.933 91.2 6.769 91.224 ;
     RECT  6.725 42.48 6.797 90.072 ;
     RECT  6.725 40.416 6.803 41.496 ;
     RECT  6.661 39.216 7.808 39.24 ;
     RECT  6.803 40.56 7.808 41.496 ;
     RECT  6.797 42.48 7.808 89.016 ;
     RECT  6.797 90.048 7.808 90.072 ;
     RECT  7.808 2.148 7.912 127.452 ;
     RECT  7.912 2.418 8.104 127.182 ;
     RECT  8.104 40.56 8.201 88.968 ;
     RECT  8.201 40.56 8.813 79.752 ;
     RECT  8.813 40.56 9.065 69.672 ;
     RECT  9.065 40.56 9.101 69.576 ;
     RECT  8.201 80.832 9.155 88.968 ;
     RECT  9.101 40.56 9.425 69.048 ;
     RECT  8.813 70.704 9.443 79.752 ;
     RECT  9.425 40.56 9.461 68.184 ;
     RECT  9.443 70.848 9.973 79.752 ;
     RECT  8.104 39.216 10.508 39.24 ;
     RECT  9.461 40.56 10.508 59.592 ;
     RECT  9.461 60.624 10.508 68.184 ;
     RECT  9.973 70.848 10.508 79.848 ;
     RECT  9.155 80.832 10.508 88.92 ;
     RECT  10.508 2.148 10.612 127.452 ;
     RECT  10.612 2.418 10.804 127.182 ;
     RECT  10.804 83.04 10.865 87 ;
     RECT  10.804 70.704 11.009 79.848 ;
     RECT  11.009 71.856 11.189 79.848 ;
     RECT  11.009 70.704 11.225 70.872 ;
     RECT  10.804 67.584 11.797 68.184 ;
     RECT  10.804 40.56 11.987 57.864 ;
     RECT  10.804 62.976 12.121 66.072 ;
     RECT  11.797 67.056 12.157 68.184 ;
     RECT  12.157 67.056 12.325 68.952 ;
     RECT  10.804 58.944 12.373 59.592 ;
     RECT  10.804 60.624 12.373 61.656 ;
     RECT  10.804 88.08 12.421 88.104 ;
     RECT  10.804 89.184 12.421 89.256 ;
     RECT  10.865 83.04 12.757 86.856 ;
     RECT  12.421 88.08 12.757 89.256 ;
     RECT  11.987 40.56 13.057 45.24 ;
     RECT  11.987 46.272 13.057 57.864 ;
     RECT  11.225 70.8 13.129 70.872 ;
     RECT  11.189 71.856 13.129 79.752 ;
     RECT  12.373 58.944 13.201 61.656 ;
     RECT  12.121 62.688 13.201 66.072 ;
     RECT  10.804 39.216 13.208 39.24 ;
     RECT  13.057 40.56 13.208 57.864 ;
     RECT  13.201 58.944 13.208 66.072 ;
     RECT  12.325 67.056 13.208 69.576 ;
     RECT  13.129 70.8 13.208 79.752 ;
     RECT  10.804 80.832 13.208 81.912 ;
     RECT  12.757 83.04 13.208 89.256 ;
     RECT  13.208 2.148 13.312 127.452 ;
     RECT  13.312 2.418 13.504 127.182 ;
     RECT  13.504 51.168 13.667 68.376 ;
     RECT  13.504 80.976 14.077 81.912 ;
     RECT  13.504 39.216 14.485 39.24 ;
     RECT  13.504 40.56 14.485 50.136 ;
     RECT  14.077 81.408 14.533 81.912 ;
     RECT  13.504 83.04 14.533 89.976 ;
     RECT  14.533 81.408 14.617 89.976 ;
     RECT  13.667 51.168 14.713 61.752 ;
     RECT  13.667 62.88 14.713 68.376 ;
     RECT  14.485 39.216 14.749 50.136 ;
     RECT  14.713 51.168 14.749 68.376 ;
     RECT  14.617 83.568 14.933 89.976 ;
     RECT  14.749 39.216 15.217 68.376 ;
     RECT  13.504 69.504 15.217 79.752 ;
     RECT  15.217 39.216 15.361 79.752 ;
     RECT  14.617 81.408 15.361 82.344 ;
     RECT  15.361 81.12 15.469 82.344 ;
     RECT  15.469 80.88 15.649 82.344 ;
     RECT  14.933 83.568 15.649 88.968 ;
     RECT  15.361 39.216 15.757 79.848 ;
     RECT  15.649 80.88 15.757 88.968 ;
     RECT  15.757 39.216 15.908 88.968 ;
     RECT  14.933 89.952 15.908 89.976 ;
     RECT  15.109 91.344 15.908 91.368 ;
     RECT  15.908 2.148 16.012 127.452 ;
     RECT  16.012 2.418 16.204 127.182 ;
     RECT  16.204 39.216 16.517 88.968 ;
     RECT  16.517 40.56 16.595 88.968 ;
     RECT  16.204 90.048 17.333 90.072 ;
     RECT  16.204 91.344 17.333 91.368 ;
     RECT  16.595 87.84 17.413 88.968 ;
     RECT  17.333 90.048 17.413 91.368 ;
     RECT  17.413 87.84 17.489 91.368 ;
     RECT  16.595 40.56 17.629 86.856 ;
     RECT  17.489 87.84 17.629 90.648 ;
     RECT  16.517 39.216 17.845 39.24 ;
     RECT  17.845 38.784 18.061 39.24 ;
     RECT  18.277 92.88 18.373 92.904 ;
     RECT  18.373 92.496 18.421 93 ;
     RECT  18.061 38.784 18.529 39.336 ;
     RECT  17.629 40.56 18.529 90.648 ;
     RECT  18.529 38.784 18.608 90.648 ;
     RECT  18.421 91.872 18.608 93 ;
     RECT  18.608 2.148 18.712 127.452 ;
     RECT  18.712 2.418 18.904 127.182 ;
     RECT  18.904 34.752 19.043 34.776 ;
     RECT  18.904 33.024 19.132 33.624 ;
     RECT  18.904 37.056 19.187 37.752 ;
     RECT  18.904 38.736 19.235 93.048 ;
     RECT  19.235 38.736 19.325 92.952 ;
     RECT  19.325 91.2 19.331 92.952 ;
     RECT  19.187 37.056 19.379 37.656 ;
     RECT  19.331 91.2 19.379 91.224 ;
     RECT  18.904 96.912 19.475 97.512 ;
     RECT  19.325 38.736 19.523 90.072 ;
     RECT  19.132 33.6 19.667 33.624 ;
     RECT  18.904 94.608 19.667 95.88 ;
     RECT  19.667 94.608 19.715 95.832 ;
     RECT  19.715 95.184 19.763 95.832 ;
     RECT  19.331 92.352 19.793 92.952 ;
     RECT  19.793 92.88 19.837 92.952 ;
     RECT  19.837 92.88 19.955 92.904 ;
     RECT  19.475 96.912 20.243 96.936 ;
     RECT  19.763 95.184 20.291 95.208 ;
     RECT  19.523 38.736 20.339 89.64 ;
     RECT  19.379 37.632 20.437 37.656 ;
     RECT  20.437 37.008 20.531 37.656 ;
     RECT  20.581 91.152 20.617 91.176 ;
     RECT  20.339 39.12 20.725 89.64 ;
     RECT  20.617 91.056 21.347 91.176 ;
     RECT  21.337 93.504 21.404 93.528 ;
     RECT  21.404 92.88 21.421 93.528 ;
     RECT  20.531 37.056 21.443 37.656 ;
     RECT  21.347 91.152 21.443 91.176 ;
     RECT  21.443 37.056 21.491 37.08 ;
     RECT  21.421 92.88 21.491 92.904 ;
     RECT  20.725 39.12 21.516 39.144 ;
     RECT  20.725 39.144 21.564 39.216 ;
     RECT  20.725 39.216 21.516 39.24 ;
     RECT  20.725 39.24 21.564 39.312 ;
     RECT  20.725 39.312 21.516 39.336 ;
     RECT  20.725 39.336 21.564 39.408 ;
     RECT  20.725 39.408 21.516 39.432 ;
     RECT  20.725 39.432 21.564 39.504 ;
     RECT  20.725 39.504 21.516 39.528 ;
     RECT  20.725 39.528 21.564 39.6 ;
     RECT  20.725 39.6 21.516 39.624 ;
     RECT  20.725 39.624 21.564 39.696 ;
     RECT  20.725 39.696 21.516 39.72 ;
     RECT  20.725 39.72 21.564 39.792 ;
     RECT  20.725 39.792 21.516 39.816 ;
     RECT  20.725 39.816 21.564 39.888 ;
     RECT  20.725 39.888 21.516 39.912 ;
     RECT  20.725 39.912 21.564 39.984 ;
     RECT  20.725 39.984 21.516 40.008 ;
     RECT  20.725 40.008 21.564 40.08 ;
     RECT  20.725 40.08 21.516 40.104 ;
     RECT  20.725 40.104 21.564 40.176 ;
     RECT  20.725 40.176 21.516 40.2 ;
     RECT  20.725 40.2 21.564 40.272 ;
     RECT  20.725 40.272 21.516 40.296 ;
     RECT  20.725 40.296 21.564 40.368 ;
     RECT  20.725 40.368 21.516 40.392 ;
     RECT  20.725 40.392 21.564 40.464 ;
     RECT  20.725 40.464 21.516 40.488 ;
     RECT  20.725 40.488 21.564 40.56 ;
     RECT  20.725 40.56 21.516 40.584 ;
     RECT  20.725 40.584 21.564 40.656 ;
     RECT  20.725 40.656 21.516 40.68 ;
     RECT  20.725 40.68 21.564 40.752 ;
     RECT  20.725 40.752 21.516 40.776 ;
     RECT  20.725 40.776 21.564 40.848 ;
     RECT  20.725 40.848 21.516 40.872 ;
     RECT  20.725 40.872 21.564 40.944 ;
     RECT  20.725 40.944 21.516 40.968 ;
     RECT  20.725 40.968 21.564 41.04 ;
     RECT  20.725 41.04 21.516 41.064 ;
     RECT  20.725 41.064 21.564 41.136 ;
     RECT  20.725 41.136 21.516 41.16 ;
     RECT  20.725 41.16 21.564 41.232 ;
     RECT  20.725 41.232 21.516 41.256 ;
     RECT  20.725 41.256 21.564 41.328 ;
     RECT  20.725 41.328 21.516 41.352 ;
     RECT  20.725 41.352 21.564 41.424 ;
     RECT  20.725 41.424 21.516 41.448 ;
     RECT  20.725 41.448 21.564 41.52 ;
     RECT  20.725 41.52 21.516 41.544 ;
     RECT  20.725 41.544 21.564 41.616 ;
     RECT  20.725 41.616 21.516 41.64 ;
     RECT  20.725 41.64 21.564 41.712 ;
     RECT  20.725 41.712 21.516 41.736 ;
     RECT  20.725 41.736 21.564 41.808 ;
     RECT  20.725 41.808 21.516 41.832 ;
     RECT  20.725 41.832 21.564 41.904 ;
     RECT  20.725 41.904 21.516 41.928 ;
     RECT  20.725 41.928 21.564 42 ;
     RECT  20.725 42 21.516 42.024 ;
     RECT  20.725 42.024 21.564 42.096 ;
     RECT  20.725 42.096 21.516 42.12 ;
     RECT  20.725 42.12 21.564 42.192 ;
     RECT  20.725 42.192 21.516 42.216 ;
     RECT  20.725 42.216 21.564 42.288 ;
     RECT  20.725 42.288 21.516 42.312 ;
     RECT  20.725 42.312 21.564 42.384 ;
     RECT  20.725 42.384 21.516 42.408 ;
     RECT  20.725 42.408 21.564 42.48 ;
     RECT  20.725 42.48 21.516 42.504 ;
     RECT  20.725 42.504 21.564 42.576 ;
     RECT  20.725 42.576 21.516 42.6 ;
     RECT  20.725 42.6 21.564 42.672 ;
     RECT  20.725 42.672 21.516 42.696 ;
     RECT  20.725 42.696 21.564 42.768 ;
     RECT  20.725 42.768 21.516 42.792 ;
     RECT  20.725 42.792 21.564 42.864 ;
     RECT  20.725 42.864 21.516 42.888 ;
     RECT  20.725 42.888 21.564 42.96 ;
     RECT  20.725 42.96 21.516 42.984 ;
     RECT  20.725 42.984 21.564 43.056 ;
     RECT  20.725 43.056 21.516 43.08 ;
     RECT  20.725 43.08 21.564 43.152 ;
     RECT  20.725 43.152 21.516 43.176 ;
     RECT  20.725 43.176 21.564 43.248 ;
     RECT  20.725 43.248 21.516 43.272 ;
     RECT  20.725 43.272 21.564 43.344 ;
     RECT  20.725 43.344 21.516 43.368 ;
     RECT  20.725 43.368 21.564 43.44 ;
     RECT  20.725 43.44 21.516 43.464 ;
     RECT  20.725 43.464 21.564 43.536 ;
     RECT  20.725 43.536 21.516 43.56 ;
     RECT  20.725 43.56 21.564 43.632 ;
     RECT  20.725 43.632 21.516 43.656 ;
     RECT  20.725 43.656 21.564 43.728 ;
     RECT  20.725 43.728 21.516 43.752 ;
     RECT  20.725 43.752 21.564 43.824 ;
     RECT  20.725 43.824 21.516 43.848 ;
     RECT  20.725 43.848 21.564 43.92 ;
     RECT  20.725 43.92 21.516 43.944 ;
     RECT  20.725 43.944 21.564 44.016 ;
     RECT  20.725 44.016 21.516 44.04 ;
     RECT  20.725 44.04 21.564 44.112 ;
     RECT  20.725 44.112 21.516 44.136 ;
     RECT  20.725 44.136 21.564 44.208 ;
     RECT  20.725 44.208 21.516 44.232 ;
     RECT  20.725 44.232 21.564 44.304 ;
     RECT  20.725 44.304 21.516 44.328 ;
     RECT  20.725 44.328 21.564 44.4 ;
     RECT  20.725 44.4 21.516 44.424 ;
     RECT  20.725 44.424 21.564 44.496 ;
     RECT  20.725 44.496 21.516 44.52 ;
     RECT  20.725 44.52 21.564 44.592 ;
     RECT  20.725 44.592 21.516 44.616 ;
     RECT  20.725 44.616 21.564 44.688 ;
     RECT  20.725 44.688 21.516 44.712 ;
     RECT  20.725 44.712 21.564 44.784 ;
     RECT  20.725 44.784 21.516 44.808 ;
     RECT  20.725 44.808 21.564 44.88 ;
     RECT  20.725 44.88 21.516 44.904 ;
     RECT  20.725 44.904 21.564 44.976 ;
     RECT  20.725 44.976 21.516 45 ;
     RECT  20.725 45 21.564 45.072 ;
     RECT  20.725 45.072 21.516 45.096 ;
     RECT  20.725 45.096 21.564 45.168 ;
     RECT  20.725 45.168 21.516 45.192 ;
     RECT  20.725 45.192 21.564 45.264 ;
     RECT  20.725 45.264 21.516 45.288 ;
     RECT  20.725 45.288 21.564 45.36 ;
     RECT  20.725 45.36 21.516 45.384 ;
     RECT  20.725 45.384 21.564 45.456 ;
     RECT  20.725 45.456 21.516 45.48 ;
     RECT  20.725 45.48 21.564 45.552 ;
     RECT  20.725 45.552 21.516 45.576 ;
     RECT  20.725 45.576 21.564 45.648 ;
     RECT  20.725 45.648 21.516 45.672 ;
     RECT  20.725 45.672 21.564 45.744 ;
     RECT  20.725 45.744 21.516 45.768 ;
     RECT  20.725 45.768 21.564 45.84 ;
     RECT  20.725 45.84 21.516 45.864 ;
     RECT  20.725 45.864 21.564 45.936 ;
     RECT  20.725 45.936 21.516 45.96 ;
     RECT  20.725 45.96 21.564 46.032 ;
     RECT  20.725 46.032 21.516 46.056 ;
     RECT  20.725 46.056 21.564 46.128 ;
     RECT  20.725 46.128 21.516 46.152 ;
     RECT  20.725 46.152 21.564 46.224 ;
     RECT  20.725 46.224 21.516 46.248 ;
     RECT  20.725 46.248 21.564 46.32 ;
     RECT  20.725 46.32 21.516 46.344 ;
     RECT  20.725 46.344 21.564 46.416 ;
     RECT  20.725 46.416 21.516 46.44 ;
     RECT  20.725 46.44 21.564 46.512 ;
     RECT  20.725 46.512 21.516 46.536 ;
     RECT  20.725 46.536 21.564 46.608 ;
     RECT  20.725 46.608 21.516 46.632 ;
     RECT  20.725 46.632 21.564 46.704 ;
     RECT  20.725 46.704 21.516 46.728 ;
     RECT  20.725 46.728 21.564 46.8 ;
     RECT  20.725 46.8 21.516 46.824 ;
     RECT  20.725 46.824 21.564 46.896 ;
     RECT  20.725 46.896 21.516 46.92 ;
     RECT  20.725 46.92 21.564 46.992 ;
     RECT  20.725 46.992 21.516 47.016 ;
     RECT  20.725 47.016 21.564 47.088 ;
     RECT  20.725 47.088 21.516 47.112 ;
     RECT  20.725 47.112 21.564 47.184 ;
     RECT  20.725 47.184 21.516 47.208 ;
     RECT  20.725 47.208 21.564 47.28 ;
     RECT  20.725 47.28 21.516 47.304 ;
     RECT  20.725 47.304 21.564 47.376 ;
     RECT  20.725 47.376 21.516 47.4 ;
     RECT  20.725 47.4 21.564 47.472 ;
     RECT  20.725 47.472 21.516 47.496 ;
     RECT  20.725 47.496 21.564 47.568 ;
     RECT  20.725 47.568 21.516 47.592 ;
     RECT  20.725 47.592 21.564 47.664 ;
     RECT  20.725 47.664 21.516 47.688 ;
     RECT  20.725 47.688 21.564 47.76 ;
     RECT  20.725 47.76 21.516 47.784 ;
     RECT  20.725 47.784 21.564 47.856 ;
     RECT  20.725 47.856 21.516 47.88 ;
     RECT  20.725 47.88 21.564 47.952 ;
     RECT  20.725 47.952 21.516 47.976 ;
     RECT  20.725 47.976 21.564 48.048 ;
     RECT  20.725 48.048 21.516 48.072 ;
     RECT  20.725 48.072 21.564 48.144 ;
     RECT  20.725 48.144 21.516 48.168 ;
     RECT  20.725 48.168 21.564 48.24 ;
     RECT  20.725 48.24 21.516 48.264 ;
     RECT  20.725 48.264 21.564 48.336 ;
     RECT  20.725 48.336 21.516 48.36 ;
     RECT  20.725 48.36 21.564 48.432 ;
     RECT  20.725 48.432 21.516 48.456 ;
     RECT  20.725 48.456 21.564 48.528 ;
     RECT  20.725 48.528 21.516 48.552 ;
     RECT  20.725 48.552 21.564 48.624 ;
     RECT  20.725 48.624 21.516 48.648 ;
     RECT  20.725 48.648 21.564 48.72 ;
     RECT  20.725 48.72 21.516 48.744 ;
     RECT  20.725 48.744 21.564 48.816 ;
     RECT  20.725 48.816 21.516 48.84 ;
     RECT  20.725 48.84 21.564 48.912 ;
     RECT  20.725 48.912 21.516 48.936 ;
     RECT  20.725 48.936 21.564 49.008 ;
     RECT  20.725 49.008 21.516 49.032 ;
     RECT  20.725 49.032 21.564 49.104 ;
     RECT  20.725 49.104 21.516 49.128 ;
     RECT  20.725 49.128 21.564 49.2 ;
     RECT  20.725 49.2 21.516 49.224 ;
     RECT  20.725 49.224 21.564 49.296 ;
     RECT  20.725 49.296 21.516 49.32 ;
     RECT  20.725 49.32 21.564 49.392 ;
     RECT  20.725 49.392 21.516 49.416 ;
     RECT  20.725 49.416 21.564 49.488 ;
     RECT  20.725 49.488 21.516 49.512 ;
     RECT  20.725 49.512 21.564 49.584 ;
     RECT  20.725 49.584 21.516 49.608 ;
     RECT  20.725 49.608 21.564 49.68 ;
     RECT  20.725 49.68 21.516 49.704 ;
     RECT  20.725 49.704 21.564 49.776 ;
     RECT  20.725 49.776 21.516 49.8 ;
     RECT  20.725 49.8 21.564 49.872 ;
     RECT  20.725 49.872 21.516 49.896 ;
     RECT  20.725 49.896 21.564 49.968 ;
     RECT  20.725 49.968 21.516 49.992 ;
     RECT  20.725 49.992 21.564 50.064 ;
     RECT  20.725 50.064 21.516 50.088 ;
     RECT  20.725 50.088 21.564 50.16 ;
     RECT  20.725 50.16 21.516 50.184 ;
     RECT  20.725 50.184 21.564 50.256 ;
     RECT  20.725 50.256 21.516 50.28 ;
     RECT  20.725 50.28 21.564 50.352 ;
     RECT  20.725 50.352 21.516 50.376 ;
     RECT  20.725 50.376 21.564 50.448 ;
     RECT  20.725 50.448 21.516 50.472 ;
     RECT  20.725 50.472 21.564 50.544 ;
     RECT  20.725 50.544 21.516 50.568 ;
     RECT  20.725 50.568 21.564 50.64 ;
     RECT  20.725 50.64 21.516 50.664 ;
     RECT  20.725 50.664 21.564 50.736 ;
     RECT  20.725 50.736 21.516 50.76 ;
     RECT  20.725 50.76 21.564 50.832 ;
     RECT  20.725 50.832 21.516 50.856 ;
     RECT  20.725 50.856 21.564 50.928 ;
     RECT  20.725 50.928 21.516 50.952 ;
     RECT  20.725 50.952 21.564 51.024 ;
     RECT  20.725 51.024 21.516 51.048 ;
     RECT  20.725 51.048 21.564 51.12 ;
     RECT  20.725 51.12 21.516 51.144 ;
     RECT  20.725 51.144 21.564 51.216 ;
     RECT  20.725 51.216 21.516 51.24 ;
     RECT  20.725 51.24 21.564 51.312 ;
     RECT  20.725 51.312 21.516 51.336 ;
     RECT  20.725 51.336 21.564 51.408 ;
     RECT  20.725 51.408 21.516 51.432 ;
     RECT  20.725 51.432 21.564 51.504 ;
     RECT  20.725 51.504 21.516 51.528 ;
     RECT  20.725 51.528 21.564 51.6 ;
     RECT  20.725 51.6 21.516 51.624 ;
     RECT  20.725 51.624 21.564 51.696 ;
     RECT  20.725 51.696 21.516 51.72 ;
     RECT  20.725 51.72 21.564 51.792 ;
     RECT  20.725 51.792 21.516 51.816 ;
     RECT  20.725 51.816 21.564 51.888 ;
     RECT  20.725 51.888 21.516 51.912 ;
     RECT  20.725 51.912 21.564 51.984 ;
     RECT  20.725 51.984 21.516 52.008 ;
     RECT  20.725 52.008 21.564 52.08 ;
     RECT  20.725 52.08 21.516 52.104 ;
     RECT  20.725 52.104 21.564 52.176 ;
     RECT  20.725 52.176 21.516 52.2 ;
     RECT  20.725 52.2 21.564 52.272 ;
     RECT  20.725 52.272 21.516 52.296 ;
     RECT  20.725 52.296 21.564 52.368 ;
     RECT  20.725 52.368 21.516 52.392 ;
     RECT  20.725 52.392 21.564 52.464 ;
     RECT  20.725 52.464 21.516 52.488 ;
     RECT  20.725 52.488 21.564 52.56 ;
     RECT  20.725 52.56 21.516 52.584 ;
     RECT  20.725 52.584 21.564 52.656 ;
     RECT  20.725 52.656 21.516 52.68 ;
     RECT  20.725 52.68 21.564 52.752 ;
     RECT  20.725 52.752 21.516 52.776 ;
     RECT  20.725 52.776 21.564 52.848 ;
     RECT  20.725 52.848 21.516 52.872 ;
     RECT  20.725 52.872 21.564 52.944 ;
     RECT  20.725 52.944 21.516 52.968 ;
     RECT  20.725 52.968 21.564 53.04 ;
     RECT  20.725 53.04 21.516 53.064 ;
     RECT  20.725 53.064 21.564 53.136 ;
     RECT  20.725 53.136 21.516 53.16 ;
     RECT  20.725 53.16 21.564 53.232 ;
     RECT  20.725 53.232 21.516 53.256 ;
     RECT  20.725 53.256 21.564 53.328 ;
     RECT  20.725 53.328 21.516 53.352 ;
     RECT  20.725 53.352 21.564 53.424 ;
     RECT  20.725 53.424 21.516 53.448 ;
     RECT  20.725 53.448 21.564 53.52 ;
     RECT  20.725 53.52 21.516 53.544 ;
     RECT  20.725 53.544 21.564 53.616 ;
     RECT  20.725 53.616 21.516 53.64 ;
     RECT  20.725 53.64 21.564 53.712 ;
     RECT  20.725 53.712 21.516 53.736 ;
     RECT  20.725 53.736 21.564 53.808 ;
     RECT  20.725 53.808 21.516 53.832 ;
     RECT  20.725 53.832 21.564 53.904 ;
     RECT  20.725 53.904 21.516 53.928 ;
     RECT  20.725 53.928 21.564 54 ;
     RECT  20.725 54 21.516 54.024 ;
     RECT  20.725 54.024 21.564 54.096 ;
     RECT  20.725 54.096 21.516 54.12 ;
     RECT  20.725 54.12 21.564 54.192 ;
     RECT  20.725 54.192 21.516 54.216 ;
     RECT  20.725 54.216 21.564 54.288 ;
     RECT  20.725 54.288 21.516 54.312 ;
     RECT  20.725 54.312 21.564 54.384 ;
     RECT  20.725 54.384 21.516 54.408 ;
     RECT  20.725 54.408 21.564 54.48 ;
     RECT  20.725 54.48 21.516 54.504 ;
     RECT  20.725 54.504 21.564 54.576 ;
     RECT  20.725 54.576 21.516 54.6 ;
     RECT  20.725 54.6 21.564 54.672 ;
     RECT  20.725 54.672 21.516 54.696 ;
     RECT  20.725 54.696 21.564 54.768 ;
     RECT  20.725 54.768 21.516 54.792 ;
     RECT  20.725 54.792 21.564 54.864 ;
     RECT  20.725 54.864 21.516 54.888 ;
     RECT  20.725 54.888 21.564 54.96 ;
     RECT  20.725 54.96 21.516 54.984 ;
     RECT  20.725 54.984 21.564 55.056 ;
     RECT  20.725 55.056 21.516 55.08 ;
     RECT  20.725 55.08 21.564 55.152 ;
     RECT  20.725 55.152 21.516 55.176 ;
     RECT  20.725 55.176 21.564 55.248 ;
     RECT  20.725 55.248 21.516 55.272 ;
     RECT  20.725 55.272 21.564 55.344 ;
     RECT  20.725 55.344 21.516 55.368 ;
     RECT  20.725 55.368 21.564 55.44 ;
     RECT  20.725 55.44 21.516 55.464 ;
     RECT  20.725 55.464 21.564 55.536 ;
     RECT  20.725 55.536 21.516 55.56 ;
     RECT  20.725 55.56 21.564 55.632 ;
     RECT  20.725 55.632 21.516 55.656 ;
     RECT  20.725 55.656 21.564 55.728 ;
     RECT  20.725 55.728 21.516 55.752 ;
     RECT  20.725 55.752 21.564 55.824 ;
     RECT  20.725 55.824 21.516 55.848 ;
     RECT  20.725 55.848 21.564 55.92 ;
     RECT  20.725 55.92 21.516 55.944 ;
     RECT  20.725 55.944 21.564 56.016 ;
     RECT  20.725 56.016 21.516 56.04 ;
     RECT  20.725 56.04 21.564 56.112 ;
     RECT  20.725 56.112 21.516 56.136 ;
     RECT  20.725 56.136 21.564 56.208 ;
     RECT  20.725 56.208 21.516 56.232 ;
     RECT  20.725 56.232 21.564 56.304 ;
     RECT  20.725 56.304 21.516 56.328 ;
     RECT  20.725 56.328 21.564 56.4 ;
     RECT  20.725 56.4 21.516 56.424 ;
     RECT  20.725 56.424 21.564 56.496 ;
     RECT  20.725 56.496 21.516 56.52 ;
     RECT  20.725 56.52 21.564 56.592 ;
     RECT  20.725 56.592 21.516 56.616 ;
     RECT  20.725 56.616 21.564 56.688 ;
     RECT  20.725 56.688 21.516 56.712 ;
     RECT  20.725 56.712 21.564 56.784 ;
     RECT  20.725 56.784 21.516 56.808 ;
     RECT  20.725 56.808 21.564 56.88 ;
     RECT  20.725 56.88 21.516 56.904 ;
     RECT  20.725 56.904 21.564 56.976 ;
     RECT  20.725 56.976 21.516 57 ;
     RECT  20.725 57 21.564 57.072 ;
     RECT  20.725 57.072 21.516 57.096 ;
     RECT  20.725 57.096 21.564 57.168 ;
     RECT  20.725 57.168 21.516 57.192 ;
     RECT  20.725 57.192 21.564 57.264 ;
     RECT  20.725 57.264 21.516 57.288 ;
     RECT  20.725 57.288 21.564 57.36 ;
     RECT  20.725 57.36 21.516 57.384 ;
     RECT  20.725 57.384 21.564 57.456 ;
     RECT  20.725 57.456 21.516 57.48 ;
     RECT  20.725 57.48 21.564 58.32 ;
     RECT  20.725 58.32 21.516 58.344 ;
     RECT  20.725 58.344 21.564 58.416 ;
     RECT  20.725 58.416 21.516 58.44 ;
     RECT  20.725 58.44 21.564 58.512 ;
     RECT  20.725 58.512 21.516 58.536 ;
     RECT  20.725 58.536 21.564 58.608 ;
     RECT  20.725 58.608 21.516 58.632 ;
     RECT  20.725 58.632 21.564 58.704 ;
     RECT  20.725 58.704 21.516 58.728 ;
     RECT  20.725 58.728 21.564 58.8 ;
     RECT  20.725 58.8 21.516 58.824 ;
     RECT  20.725 58.824 21.564 58.896 ;
     RECT  20.725 58.896 21.516 58.92 ;
     RECT  20.725 58.92 21.564 58.992 ;
     RECT  20.725 58.992 21.516 59.016 ;
     RECT  20.725 59.016 21.564 59.088 ;
     RECT  20.725 59.088 21.516 59.112 ;
     RECT  20.725 59.112 21.564 59.184 ;
     RECT  20.725 59.184 21.516 59.208 ;
     RECT  20.725 59.208 21.564 59.28 ;
     RECT  20.725 59.28 21.516 59.304 ;
     RECT  20.725 59.304 21.564 59.376 ;
     RECT  20.725 59.376 21.516 59.4 ;
     RECT  20.725 59.4 21.564 59.472 ;
     RECT  20.725 59.472 21.516 59.496 ;
     RECT  20.725 59.496 21.564 59.568 ;
     RECT  20.725 59.568 21.516 59.592 ;
     RECT  20.725 59.592 21.564 59.664 ;
     RECT  20.725 59.664 21.516 59.688 ;
     RECT  20.725 59.688 21.564 59.76 ;
     RECT  20.725 59.76 21.516 59.784 ;
     RECT  20.725 59.784 21.564 59.856 ;
     RECT  20.725 59.856 21.516 59.88 ;
     RECT  20.725 59.88 21.564 59.952 ;
     RECT  20.725 59.952 21.516 59.976 ;
     RECT  20.725 59.976 21.564 60.048 ;
     RECT  20.725 60.048 21.516 60.072 ;
     RECT  20.725 60.072 21.564 60.144 ;
     RECT  20.725 60.144 21.516 60.168 ;
     RECT  20.725 60.168 21.564 60.24 ;
     RECT  20.725 60.24 21.516 60.264 ;
     RECT  20.725 60.264 21.564 60.336 ;
     RECT  20.725 60.336 21.516 60.36 ;
     RECT  20.725 60.36 21.564 60.432 ;
     RECT  20.725 60.432 21.516 60.456 ;
     RECT  20.725 60.456 21.564 60.528 ;
     RECT  20.725 60.528 21.516 60.552 ;
     RECT  20.725 60.552 21.564 60.624 ;
     RECT  20.725 60.624 21.516 60.648 ;
     RECT  20.725 60.648 21.564 60.72 ;
     RECT  20.725 60.72 21.516 60.744 ;
     RECT  20.725 60.744 21.564 60.816 ;
     RECT  20.725 60.816 21.516 60.84 ;
     RECT  20.725 60.84 21.564 60.912 ;
     RECT  20.725 60.912 21.516 60.936 ;
     RECT  20.725 60.936 21.564 61.008 ;
     RECT  20.725 61.008 21.516 61.032 ;
     RECT  20.725 61.032 21.564 61.104 ;
     RECT  20.725 61.104 21.516 61.128 ;
     RECT  20.725 61.128 21.564 61.2 ;
     RECT  20.725 61.2 21.516 61.224 ;
     RECT  20.725 61.224 21.564 61.296 ;
     RECT  20.725 61.296 21.516 61.32 ;
     RECT  20.725 61.32 21.564 61.392 ;
     RECT  20.725 61.392 21.516 61.416 ;
     RECT  20.725 61.416 21.564 61.488 ;
     RECT  20.725 61.488 21.516 61.512 ;
     RECT  20.725 61.512 21.564 61.584 ;
     RECT  20.725 61.584 21.516 61.608 ;
     RECT  20.725 61.608 21.564 61.68 ;
     RECT  20.725 61.68 21.516 61.704 ;
     RECT  20.725 61.704 21.564 61.776 ;
     RECT  20.725 61.776 21.516 61.8 ;
     RECT  20.725 61.8 21.564 61.872 ;
     RECT  20.725 61.872 21.516 61.896 ;
     RECT  20.725 61.896 21.564 61.968 ;
     RECT  20.725 61.968 21.516 61.992 ;
     RECT  20.725 61.992 21.564 62.064 ;
     RECT  20.725 62.064 21.516 62.088 ;
     RECT  20.725 62.088 21.564 62.16 ;
     RECT  20.725 62.16 21.516 62.184 ;
     RECT  20.725 62.184 21.564 62.256 ;
     RECT  20.725 62.256 21.516 62.28 ;
     RECT  20.725 62.28 21.564 62.352 ;
     RECT  20.725 62.352 21.516 62.376 ;
     RECT  20.725 62.376 21.564 62.448 ;
     RECT  20.725 62.448 21.516 62.472 ;
     RECT  20.725 62.472 21.564 62.544 ;
     RECT  20.725 62.544 21.516 62.568 ;
     RECT  20.725 62.568 21.564 62.64 ;
     RECT  20.725 62.64 21.516 62.664 ;
     RECT  20.725 62.664 21.564 62.736 ;
     RECT  20.725 62.736 21.516 62.76 ;
     RECT  20.725 62.76 21.564 62.832 ;
     RECT  20.725 62.832 21.516 62.856 ;
     RECT  20.725 62.856 21.564 62.928 ;
     RECT  20.725 62.928 21.516 62.952 ;
     RECT  20.725 62.952 21.564 63.024 ;
     RECT  20.725 63.024 21.516 63.048 ;
     RECT  20.725 63.048 21.564 63.12 ;
     RECT  20.725 63.12 21.516 63.144 ;
     RECT  20.725 63.144 21.564 63.216 ;
     RECT  20.725 63.216 21.516 63.24 ;
     RECT  20.725 63.24 21.564 63.312 ;
     RECT  20.725 63.312 21.516 63.336 ;
     RECT  20.725 63.336 21.564 63.408 ;
     RECT  20.725 63.408 21.516 63.432 ;
     RECT  20.725 63.432 21.564 63.504 ;
     RECT  20.725 63.504 21.516 63.528 ;
     RECT  20.725 63.528 21.564 63.6 ;
     RECT  20.725 63.6 21.516 63.624 ;
     RECT  20.725 63.624 21.564 63.696 ;
     RECT  20.725 63.696 21.516 63.72 ;
     RECT  20.725 63.72 21.564 63.792 ;
     RECT  20.725 63.792 21.516 63.816 ;
     RECT  20.725 63.816 21.564 63.888 ;
     RECT  20.725 63.888 21.516 63.912 ;
     RECT  20.725 63.912 21.564 63.984 ;
     RECT  20.725 63.984 21.516 64.008 ;
     RECT  20.725 64.008 21.564 64.08 ;
     RECT  20.725 64.08 21.516 64.104 ;
     RECT  20.725 64.104 21.564 64.176 ;
     RECT  20.725 64.176 21.516 64.2 ;
     RECT  20.725 64.2 21.564 64.272 ;
     RECT  20.725 64.272 21.516 64.296 ;
     RECT  20.725 64.296 21.564 64.368 ;
     RECT  20.725 64.368 21.516 64.392 ;
     RECT  20.725 64.392 21.564 64.464 ;
     RECT  20.725 64.464 21.516 64.488 ;
     RECT  20.725 64.488 21.564 64.56 ;
     RECT  20.725 64.56 21.516 64.584 ;
     RECT  20.725 64.584 21.564 64.656 ;
     RECT  20.725 64.656 21.516 64.68 ;
     RECT  20.725 64.68 21.564 64.752 ;
     RECT  20.725 64.752 21.516 64.776 ;
     RECT  20.725 64.776 21.564 64.848 ;
     RECT  20.725 64.848 21.516 64.872 ;
     RECT  20.725 64.872 21.564 64.944 ;
     RECT  20.725 64.944 21.516 64.968 ;
     RECT  20.725 64.968 21.564 65.04 ;
     RECT  20.725 65.04 21.516 65.064 ;
     RECT  20.725 65.064 21.564 65.136 ;
     RECT  20.725 65.136 21.516 65.16 ;
     RECT  20.725 65.16 21.564 65.232 ;
     RECT  20.725 65.232 21.516 65.256 ;
     RECT  20.725 65.256 21.564 65.328 ;
     RECT  20.725 65.328 21.516 65.352 ;
     RECT  20.725 65.352 21.564 65.424 ;
     RECT  20.725 65.424 21.516 65.448 ;
     RECT  20.725 65.448 21.564 65.52 ;
     RECT  20.725 65.52 21.516 65.544 ;
     RECT  20.725 65.544 21.564 65.616 ;
     RECT  20.725 65.616 21.516 65.64 ;
     RECT  20.725 65.64 21.564 65.712 ;
     RECT  20.725 65.712 21.516 65.736 ;
     RECT  20.725 65.736 21.564 65.808 ;
     RECT  20.725 65.808 21.516 65.832 ;
     RECT  20.725 65.832 21.564 65.904 ;
     RECT  20.725 65.904 21.516 65.928 ;
     RECT  20.725 65.928 21.564 66 ;
     RECT  20.725 66 21.516 66.024 ;
     RECT  20.725 66.024 21.564 66.096 ;
     RECT  20.725 66.096 21.516 66.12 ;
     RECT  20.725 66.12 21.564 66.192 ;
     RECT  20.725 66.192 21.516 66.216 ;
     RECT  20.725 66.216 21.564 66.288 ;
     RECT  20.725 66.288 21.516 66.312 ;
     RECT  20.725 66.312 21.564 66.384 ;
     RECT  20.725 66.384 21.516 66.408 ;
     RECT  20.725 66.408 21.564 66.48 ;
     RECT  20.725 66.48 21.516 66.504 ;
     RECT  20.725 66.504 21.564 66.576 ;
     RECT  20.725 66.576 21.516 66.6 ;
     RECT  20.725 66.6 21.564 66.672 ;
     RECT  20.725 66.672 21.516 66.696 ;
     RECT  20.725 66.696 21.564 66.768 ;
     RECT  20.725 66.768 21.516 66.792 ;
     RECT  20.725 66.792 21.564 66.864 ;
     RECT  20.725 66.864 21.516 66.888 ;
     RECT  20.725 66.888 21.564 66.96 ;
     RECT  20.725 66.96 21.516 66.984 ;
     RECT  20.725 66.984 21.564 67.056 ;
     RECT  20.725 67.056 21.516 67.08 ;
     RECT  20.725 67.08 21.564 67.152 ;
     RECT  20.725 67.152 21.516 67.176 ;
     RECT  20.725 67.176 21.564 67.248 ;
     RECT  20.725 67.248 21.516 67.272 ;
     RECT  20.725 67.272 21.564 67.344 ;
     RECT  20.725 67.344 21.516 67.368 ;
     RECT  20.725 67.368 21.564 67.44 ;
     RECT  20.725 67.44 21.516 67.464 ;
     RECT  20.725 67.464 21.564 67.536 ;
     RECT  20.725 67.536 21.516 67.56 ;
     RECT  20.725 67.56 21.564 67.632 ;
     RECT  20.725 67.632 21.516 67.656 ;
     RECT  20.725 67.656 21.564 67.728 ;
     RECT  20.725 67.728 21.516 67.752 ;
     RECT  20.725 67.752 21.564 67.824 ;
     RECT  20.725 67.824 21.516 67.848 ;
     RECT  20.725 67.848 21.564 67.92 ;
     RECT  20.725 67.92 21.516 67.944 ;
     RECT  20.725 67.944 21.564 68.016 ;
     RECT  20.725 68.016 21.516 68.04 ;
     RECT  20.725 68.04 21.564 68.112 ;
     RECT  20.725 68.112 21.516 68.136 ;
     RECT  20.725 68.136 21.564 68.208 ;
     RECT  20.725 68.208 21.516 68.232 ;
     RECT  20.725 68.232 21.564 68.304 ;
     RECT  20.725 68.304 21.516 68.328 ;
     RECT  20.725 68.328 21.564 68.4 ;
     RECT  20.725 68.4 21.516 68.424 ;
     RECT  20.725 68.424 21.564 68.496 ;
     RECT  20.725 68.496 21.516 68.52 ;
     RECT  20.725 68.52 21.564 68.592 ;
     RECT  20.725 68.592 21.516 68.616 ;
     RECT  20.725 68.616 21.564 68.688 ;
     RECT  20.725 68.688 21.516 68.712 ;
     RECT  20.725 68.712 21.564 68.784 ;
     RECT  20.725 68.784 21.516 68.808 ;
     RECT  20.725 68.808 21.564 68.88 ;
     RECT  20.725 68.88 21.516 68.904 ;
     RECT  20.725 68.904 21.564 68.976 ;
     RECT  20.725 68.976 21.516 69 ;
     RECT  20.725 69 21.564 69.072 ;
     RECT  20.725 69.072 21.516 69.096 ;
     RECT  20.725 69.096 21.564 69.168 ;
     RECT  20.725 69.168 21.516 69.192 ;
     RECT  20.725 69.192 21.564 69.264 ;
     RECT  20.725 69.264 21.516 69.288 ;
     RECT  20.725 69.288 21.564 69.36 ;
     RECT  20.725 69.36 21.516 69.384 ;
     RECT  20.725 69.384 21.564 69.456 ;
     RECT  20.725 69.456 21.516 69.48 ;
     RECT  20.725 69.48 21.564 69.552 ;
     RECT  20.725 69.552 21.516 69.576 ;
     RECT  20.725 69.576 21.564 69.648 ;
     RECT  20.725 69.648 21.516 69.672 ;
     RECT  20.725 69.672 21.564 69.744 ;
     RECT  20.725 69.744 21.516 69.768 ;
     RECT  20.725 69.768 21.564 69.84 ;
     RECT  20.725 69.84 21.516 69.864 ;
     RECT  20.725 69.864 21.564 69.936 ;
     RECT  20.725 69.936 21.516 69.96 ;
     RECT  20.725 69.96 21.564 70.032 ;
     RECT  20.725 70.032 21.516 70.056 ;
     RECT  20.725 70.056 21.564 70.128 ;
     RECT  20.725 70.128 21.516 70.152 ;
     RECT  20.725 70.152 21.564 70.224 ;
     RECT  20.725 70.224 21.516 70.248 ;
     RECT  20.725 70.248 21.564 70.32 ;
     RECT  20.725 70.32 21.516 70.344 ;
     RECT  20.725 70.344 21.564 70.416 ;
     RECT  20.725 70.416 21.516 70.44 ;
     RECT  20.725 70.44 21.564 70.512 ;
     RECT  20.725 70.512 21.516 70.536 ;
     RECT  20.725 70.536 21.564 70.608 ;
     RECT  20.725 70.608 21.516 70.632 ;
     RECT  20.725 70.632 21.564 70.704 ;
     RECT  20.725 70.704 21.516 70.728 ;
     RECT  20.725 70.728 21.564 70.8 ;
     RECT  20.725 70.8 21.516 70.824 ;
     RECT  20.725 70.824 21.564 70.896 ;
     RECT  20.725 70.896 21.516 70.92 ;
     RECT  20.725 70.92 21.564 70.992 ;
     RECT  20.725 70.992 21.516 71.016 ;
     RECT  20.725 71.016 21.564 71.088 ;
     RECT  20.725 71.088 21.516 71.112 ;
     RECT  20.725 71.112 21.564 71.184 ;
     RECT  20.725 71.184 21.516 71.208 ;
     RECT  20.725 71.208 21.564 71.28 ;
     RECT  20.725 71.28 21.516 71.304 ;
     RECT  20.725 71.304 21.564 71.376 ;
     RECT  20.725 71.376 21.516 71.4 ;
     RECT  20.725 71.4 21.564 71.472 ;
     RECT  20.725 71.472 21.516 71.496 ;
     RECT  20.725 71.496 21.564 71.568 ;
     RECT  20.725 71.568 21.516 71.592 ;
     RECT  20.725 71.592 21.564 71.664 ;
     RECT  20.725 71.664 21.516 71.688 ;
     RECT  20.725 71.688 21.564 71.76 ;
     RECT  20.725 71.76 21.516 71.784 ;
     RECT  20.725 71.784 21.564 71.856 ;
     RECT  20.725 71.856 21.516 71.88 ;
     RECT  20.725 71.88 21.564 71.952 ;
     RECT  20.725 71.952 21.516 71.976 ;
     RECT  20.725 71.976 21.564 72.048 ;
     RECT  20.725 72.048 21.516 72.072 ;
     RECT  20.725 72.072 21.564 72.144 ;
     RECT  20.725 72.144 21.516 72.168 ;
     RECT  20.725 72.168 21.564 72.24 ;
     RECT  20.725 72.24 21.516 72.264 ;
     RECT  20.725 72.264 21.564 72.336 ;
     RECT  20.725 72.336 21.516 72.36 ;
     RECT  20.725 72.36 21.564 72.432 ;
     RECT  20.725 72.432 21.516 72.456 ;
     RECT  20.725 72.456 21.564 72.528 ;
     RECT  20.725 72.528 21.516 72.552 ;
     RECT  20.725 72.552 21.564 72.624 ;
     RECT  20.725 72.624 21.516 72.648 ;
     RECT  20.725 72.648 21.564 72.72 ;
     RECT  20.725 72.72 21.516 72.744 ;
     RECT  20.725 72.744 21.564 72.816 ;
     RECT  20.725 72.816 21.516 72.84 ;
     RECT  20.725 72.84 21.564 72.912 ;
     RECT  20.725 72.912 21.516 72.936 ;
     RECT  20.725 72.936 21.564 73.008 ;
     RECT  20.725 73.008 21.516 73.032 ;
     RECT  20.725 73.032 21.564 73.104 ;
     RECT  20.725 73.104 21.516 73.128 ;
     RECT  20.725 73.128 21.564 73.2 ;
     RECT  20.725 73.2 21.516 73.224 ;
     RECT  20.725 73.224 21.564 73.296 ;
     RECT  20.725 73.296 21.516 73.32 ;
     RECT  20.725 73.32 21.564 73.392 ;
     RECT  20.725 73.392 21.516 73.416 ;
     RECT  20.725 73.416 21.564 73.488 ;
     RECT  20.725 73.488 21.516 73.512 ;
     RECT  20.725 73.512 21.564 73.584 ;
     RECT  20.725 73.584 21.516 73.608 ;
     RECT  20.725 73.608 21.564 73.68 ;
     RECT  20.725 73.68 21.516 73.704 ;
     RECT  20.725 73.704 21.564 73.776 ;
     RECT  20.725 73.776 21.516 73.8 ;
     RECT  20.725 73.8 21.564 73.872 ;
     RECT  20.725 73.872 21.516 73.896 ;
     RECT  20.725 73.896 21.564 73.968 ;
     RECT  20.725 73.968 21.516 73.992 ;
     RECT  20.725 73.992 21.564 74.064 ;
     RECT  20.725 74.064 21.516 74.088 ;
     RECT  20.725 74.088 21.564 74.16 ;
     RECT  20.725 74.16 21.516 74.184 ;
     RECT  20.725 74.184 21.564 74.256 ;
     RECT  20.725 74.256 21.516 74.28 ;
     RECT  20.725 74.28 21.564 74.352 ;
     RECT  20.725 74.352 21.516 74.376 ;
     RECT  20.725 74.376 21.564 74.448 ;
     RECT  20.725 74.448 21.516 74.472 ;
     RECT  20.725 74.472 21.564 74.544 ;
     RECT  20.725 74.544 21.516 74.568 ;
     RECT  20.725 74.568 21.564 74.64 ;
     RECT  20.725 74.64 21.516 74.664 ;
     RECT  20.725 74.664 21.564 74.736 ;
     RECT  20.725 74.736 21.516 74.76 ;
     RECT  20.725 74.76 21.564 74.832 ;
     RECT  20.725 74.832 21.516 74.856 ;
     RECT  20.725 74.856 21.564 74.928 ;
     RECT  20.725 74.928 21.516 74.952 ;
     RECT  20.725 74.952 21.564 75.024 ;
     RECT  20.725 75.024 21.516 75.048 ;
     RECT  20.725 75.048 21.564 75.12 ;
     RECT  20.725 75.12 21.516 75.144 ;
     RECT  20.725 75.144 21.564 75.216 ;
     RECT  20.725 75.216 21.516 75.24 ;
     RECT  20.725 75.24 21.564 75.312 ;
     RECT  20.725 75.312 21.516 75.336 ;
     RECT  20.725 75.336 21.564 75.408 ;
     RECT  20.725 75.408 21.516 75.432 ;
     RECT  20.725 75.432 21.564 75.504 ;
     RECT  20.725 75.504 21.516 75.528 ;
     RECT  20.725 75.528 21.564 75.6 ;
     RECT  20.725 75.6 21.516 75.624 ;
     RECT  20.725 75.624 21.564 75.696 ;
     RECT  20.725 75.696 21.516 75.72 ;
     RECT  20.725 75.72 21.564 75.792 ;
     RECT  20.725 75.792 21.516 75.816 ;
     RECT  20.725 75.816 21.564 75.888 ;
     RECT  20.725 75.888 21.516 75.912 ;
     RECT  20.725 75.912 21.564 75.984 ;
     RECT  20.725 75.984 21.516 76.008 ;
     RECT  20.725 76.008 21.564 76.08 ;
     RECT  20.725 76.08 21.516 76.104 ;
     RECT  20.725 76.104 21.564 76.176 ;
     RECT  20.725 76.176 21.516 76.2 ;
     RECT  20.725 76.2 21.564 76.272 ;
     RECT  20.725 76.272 21.516 76.296 ;
     RECT  20.725 76.296 21.564 76.368 ;
     RECT  20.725 76.368 21.516 76.392 ;
     RECT  20.725 76.392 21.564 76.464 ;
     RECT  20.725 76.464 21.516 76.488 ;
     RECT  20.725 76.488 21.564 76.56 ;
     RECT  20.725 76.56 21.516 76.584 ;
     RECT  20.725 76.584 21.564 76.656 ;
     RECT  20.725 76.656 21.516 76.68 ;
     RECT  20.725 76.68 21.564 77.52 ;
     RECT  20.725 77.52 21.516 77.544 ;
     RECT  20.725 77.544 21.564 77.616 ;
     RECT  20.725 77.616 21.516 77.64 ;
     RECT  20.725 77.64 21.564 77.712 ;
     RECT  20.725 77.712 21.516 77.736 ;
     RECT  20.725 77.736 21.564 77.808 ;
     RECT  20.725 77.808 21.516 77.832 ;
     RECT  20.725 77.832 21.564 77.904 ;
     RECT  20.725 77.904 21.516 77.928 ;
     RECT  20.725 77.928 21.564 78 ;
     RECT  20.725 78 21.516 78.024 ;
     RECT  20.725 78.024 21.564 78.096 ;
     RECT  20.725 78.096 21.516 78.12 ;
     RECT  20.725 78.12 21.564 78.192 ;
     RECT  20.725 78.192 21.516 78.216 ;
     RECT  20.725 78.216 21.564 78.288 ;
     RECT  20.725 78.288 21.516 78.312 ;
     RECT  20.725 78.312 21.564 78.384 ;
     RECT  20.725 78.384 21.516 78.408 ;
     RECT  20.725 78.408 21.564 78.48 ;
     RECT  20.725 78.48 21.516 78.504 ;
     RECT  20.725 78.504 21.564 78.576 ;
     RECT  20.725 78.576 21.516 78.6 ;
     RECT  20.725 78.6 21.564 78.672 ;
     RECT  20.725 78.672 21.516 78.696 ;
     RECT  20.725 78.696 21.564 78.768 ;
     RECT  20.725 78.768 21.516 78.792 ;
     RECT  20.725 78.792 21.564 78.864 ;
     RECT  20.725 78.864 21.516 78.888 ;
     RECT  20.725 78.888 21.564 78.96 ;
     RECT  20.725 78.96 21.516 78.984 ;
     RECT  20.725 78.984 21.564 79.056 ;
     RECT  20.725 79.056 21.516 79.08 ;
     RECT  20.725 79.08 21.564 79.152 ;
     RECT  20.725 79.152 21.516 79.176 ;
     RECT  20.725 79.176 21.564 79.248 ;
     RECT  20.725 79.248 21.516 79.272 ;
     RECT  20.725 79.272 21.564 79.344 ;
     RECT  20.725 79.344 21.516 79.368 ;
     RECT  20.725 79.368 21.564 79.44 ;
     RECT  20.725 79.44 21.516 79.464 ;
     RECT  20.725 79.464 21.564 79.536 ;
     RECT  20.725 79.536 21.516 79.56 ;
     RECT  20.725 79.56 21.564 79.632 ;
     RECT  20.725 79.632 21.516 79.656 ;
     RECT  20.725 79.656 21.564 79.728 ;
     RECT  20.725 79.728 21.516 79.752 ;
     RECT  20.725 79.752 21.564 79.824 ;
     RECT  20.725 79.824 21.516 79.848 ;
     RECT  20.725 79.848 21.564 79.92 ;
     RECT  20.725 79.92 21.516 79.944 ;
     RECT  20.725 79.944 21.564 80.016 ;
     RECT  20.725 80.016 21.516 80.04 ;
     RECT  20.725 80.04 21.564 80.112 ;
     RECT  20.725 80.112 21.516 80.136 ;
     RECT  20.725 80.136 21.564 80.208 ;
     RECT  20.725 80.208 21.516 80.232 ;
     RECT  20.725 80.232 21.564 80.304 ;
     RECT  20.725 80.304 21.516 80.328 ;
     RECT  20.725 80.328 21.564 80.4 ;
     RECT  20.725 80.4 21.516 80.424 ;
     RECT  20.725 80.424 21.564 80.496 ;
     RECT  20.725 80.496 21.516 80.52 ;
     RECT  20.725 80.52 21.564 80.592 ;
     RECT  20.725 80.592 21.516 80.616 ;
     RECT  20.725 80.616 21.564 80.688 ;
     RECT  20.725 80.688 21.516 80.712 ;
     RECT  20.725 80.712 21.564 80.784 ;
     RECT  20.725 80.784 21.516 80.808 ;
     RECT  20.725 80.808 21.564 80.88 ;
     RECT  20.725 80.88 21.516 80.904 ;
     RECT  20.725 80.904 21.564 80.976 ;
     RECT  20.725 80.976 21.516 81 ;
     RECT  20.725 81 21.564 81.072 ;
     RECT  20.725 81.072 21.516 81.096 ;
     RECT  20.725 81.096 21.564 81.168 ;
     RECT  20.725 81.168 21.516 81.192 ;
     RECT  20.725 81.192 21.564 81.264 ;
     RECT  20.725 81.264 21.516 81.288 ;
     RECT  20.725 81.288 21.564 81.36 ;
     RECT  20.725 81.36 21.516 81.384 ;
     RECT  20.725 81.384 21.564 81.456 ;
     RECT  20.725 81.456 21.516 81.48 ;
     RECT  20.725 81.48 21.564 81.552 ;
     RECT  20.725 81.552 21.516 81.576 ;
     RECT  20.725 81.576 21.564 81.648 ;
     RECT  20.725 81.648 21.516 81.672 ;
     RECT  20.725 81.672 21.564 81.744 ;
     RECT  20.725 81.744 21.516 81.768 ;
     RECT  20.725 81.768 21.564 81.84 ;
     RECT  20.725 81.84 21.516 81.864 ;
     RECT  20.725 81.864 21.564 81.936 ;
     RECT  20.725 81.936 21.516 81.96 ;
     RECT  20.725 81.96 21.564 82.032 ;
     RECT  20.725 82.032 21.516 82.056 ;
     RECT  20.725 82.056 21.564 82.128 ;
     RECT  20.725 82.128 21.516 82.152 ;
     RECT  20.725 82.152 21.564 82.224 ;
     RECT  20.725 82.224 21.516 82.248 ;
     RECT  20.725 82.248 21.564 82.32 ;
     RECT  20.725 82.32 21.516 82.344 ;
     RECT  20.725 82.344 21.564 82.416 ;
     RECT  20.725 82.416 21.516 82.44 ;
     RECT  20.725 82.44 21.564 82.512 ;
     RECT  20.725 82.512 21.516 82.536 ;
     RECT  20.725 82.536 21.564 82.608 ;
     RECT  20.725 82.608 21.516 82.632 ;
     RECT  20.725 82.632 21.564 82.704 ;
     RECT  20.725 82.704 21.516 82.728 ;
     RECT  20.725 82.728 21.564 82.8 ;
     RECT  20.725 82.8 21.516 82.824 ;
     RECT  20.725 82.824 21.564 82.896 ;
     RECT  20.725 82.896 21.516 82.92 ;
     RECT  20.725 82.92 21.564 82.992 ;
     RECT  20.725 82.992 21.516 83.016 ;
     RECT  20.725 83.016 21.564 83.088 ;
     RECT  20.725 83.088 21.516 83.112 ;
     RECT  20.725 83.112 21.564 83.184 ;
     RECT  20.725 83.184 21.516 83.208 ;
     RECT  20.725 83.208 21.564 83.28 ;
     RECT  20.725 83.28 21.516 83.304 ;
     RECT  20.725 83.304 21.564 83.376 ;
     RECT  20.725 83.376 21.516 83.4 ;
     RECT  20.725 83.4 21.564 83.472 ;
     RECT  20.725 83.472 21.516 83.496 ;
     RECT  20.725 83.496 21.564 83.568 ;
     RECT  20.725 83.568 21.516 83.592 ;
     RECT  20.725 83.592 21.564 83.664 ;
     RECT  20.725 83.664 21.516 83.688 ;
     RECT  20.725 83.688 21.564 83.76 ;
     RECT  20.725 83.76 21.516 83.784 ;
     RECT  20.725 83.784 21.564 83.856 ;
     RECT  20.725 83.856 21.516 83.88 ;
     RECT  20.725 83.88 21.564 83.952 ;
     RECT  20.725 83.952 21.516 83.976 ;
     RECT  20.725 83.976 21.564 84.048 ;
     RECT  20.725 84.048 21.516 84.072 ;
     RECT  20.725 84.072 21.564 84.144 ;
     RECT  20.725 84.144 21.516 84.168 ;
     RECT  20.725 84.168 21.564 84.24 ;
     RECT  20.725 84.24 21.516 84.264 ;
     RECT  20.725 84.264 21.564 84.336 ;
     RECT  20.725 84.336 21.516 84.36 ;
     RECT  20.725 84.36 21.564 84.432 ;
     RECT  20.725 84.432 21.516 84.456 ;
     RECT  20.725 84.456 21.564 84.528 ;
     RECT  20.725 84.528 21.516 84.552 ;
     RECT  20.725 84.552 21.564 84.624 ;
     RECT  20.725 84.624 21.516 84.648 ;
     RECT  20.725 84.648 21.564 84.72 ;
     RECT  20.725 84.72 21.516 84.744 ;
     RECT  20.725 84.744 21.564 84.816 ;
     RECT  20.725 84.816 21.516 84.84 ;
     RECT  20.725 84.84 21.564 84.912 ;
     RECT  20.725 84.912 21.516 84.936 ;
     RECT  20.725 84.936 21.564 85.008 ;
     RECT  20.725 85.008 21.516 85.032 ;
     RECT  20.725 85.032 21.564 85.104 ;
     RECT  20.725 85.104 21.516 85.128 ;
     RECT  20.725 85.128 21.564 85.2 ;
     RECT  20.725 85.2 21.516 85.224 ;
     RECT  20.725 85.224 21.564 85.296 ;
     RECT  20.725 85.296 21.516 85.32 ;
     RECT  20.725 85.32 21.564 85.392 ;
     RECT  20.725 85.392 21.516 85.416 ;
     RECT  20.725 85.416 21.564 85.488 ;
     RECT  20.725 85.488 21.516 85.512 ;
     RECT  20.725 85.512 21.564 85.584 ;
     RECT  20.725 85.584 21.516 85.608 ;
     RECT  20.725 85.608 21.564 85.68 ;
     RECT  20.725 85.68 21.516 85.704 ;
     RECT  20.725 85.704 21.564 85.776 ;
     RECT  20.725 85.776 21.516 85.8 ;
     RECT  20.725 85.8 21.564 85.872 ;
     RECT  20.725 85.872 21.516 85.896 ;
     RECT  20.725 85.896 21.564 85.968 ;
     RECT  20.725 85.968 21.516 85.992 ;
     RECT  20.725 85.992 21.564 86.064 ;
     RECT  20.725 86.064 21.516 86.088 ;
     RECT  20.725 86.088 21.564 86.16 ;
     RECT  20.725 86.16 21.516 86.184 ;
     RECT  20.725 86.184 21.564 86.256 ;
     RECT  20.725 86.256 21.516 86.28 ;
     RECT  20.725 86.28 21.564 86.352 ;
     RECT  20.725 86.352 21.516 86.376 ;
     RECT  20.725 86.376 21.564 86.448 ;
     RECT  20.725 86.448 21.516 86.472 ;
     RECT  20.725 86.472 21.564 86.544 ;
     RECT  20.725 86.544 21.516 86.568 ;
     RECT  20.725 86.568 21.564 86.64 ;
     RECT  20.725 86.64 21.516 86.664 ;
     RECT  20.725 86.664 21.564 86.736 ;
     RECT  20.725 86.736 21.516 86.76 ;
     RECT  20.725 86.76 21.564 86.832 ;
     RECT  20.725 86.832 21.516 86.856 ;
     RECT  20.725 86.856 21.564 86.928 ;
     RECT  20.725 86.928 21.516 86.952 ;
     RECT  20.725 86.952 21.564 87.024 ;
     RECT  20.725 87.024 21.516 87.048 ;
     RECT  20.725 87.048 21.564 87.12 ;
     RECT  20.725 87.12 21.516 87.144 ;
     RECT  20.725 87.144 21.564 87.216 ;
     RECT  20.725 87.216 21.516 87.24 ;
     RECT  20.725 87.24 21.564 87.312 ;
     RECT  20.725 87.312 21.516 87.336 ;
     RECT  20.725 87.336 21.564 87.408 ;
     RECT  20.725 87.408 21.516 87.432 ;
     RECT  20.725 87.432 21.564 87.504 ;
     RECT  20.725 87.504 21.516 87.528 ;
     RECT  20.725 87.528 21.564 87.6 ;
     RECT  20.725 87.6 21.516 87.624 ;
     RECT  20.725 87.624 21.564 87.696 ;
     RECT  20.725 87.696 21.516 87.72 ;
     RECT  20.725 87.72 21.564 87.792 ;
     RECT  20.725 87.792 21.516 87.816 ;
     RECT  20.725 87.816 21.564 87.888 ;
     RECT  20.725 87.888 21.516 87.912 ;
     RECT  20.725 87.912 21.564 87.984 ;
     RECT  20.725 87.984 21.516 88.008 ;
     RECT  20.725 88.008 21.564 88.08 ;
     RECT  20.725 88.08 21.516 88.104 ;
     RECT  20.725 88.104 21.564 88.176 ;
     RECT  20.725 88.176 21.516 88.2 ;
     RECT  20.725 88.2 21.564 88.272 ;
     RECT  20.725 88.272 21.516 88.296 ;
     RECT  20.725 88.296 21.564 88.368 ;
     RECT  20.725 88.368 21.516 88.392 ;
     RECT  20.725 88.392 21.564 88.464 ;
     RECT  20.725 88.464 21.516 88.488 ;
     RECT  20.725 88.488 21.564 88.56 ;
     RECT  20.725 88.56 21.516 88.584 ;
     RECT  20.725 88.584 21.564 88.656 ;
     RECT  20.725 88.656 21.516 88.68 ;
     RECT  20.725 88.68 21.564 88.752 ;
     RECT  20.725 88.752 21.516 88.776 ;
     RECT  20.725 88.776 21.564 88.848 ;
     RECT  20.725 88.848 21.516 88.872 ;
     RECT  20.725 88.872 21.564 88.944 ;
     RECT  20.725 88.944 21.516 88.968 ;
     RECT  20.725 88.968 21.564 89.04 ;
     RECT  20.725 89.04 21.516 89.064 ;
     RECT  20.725 89.064 21.564 89.136 ;
     RECT  20.725 89.136 21.516 89.16 ;
     RECT  20.725 89.16 21.564 89.232 ;
     RECT  20.725 89.232 21.516 89.256 ;
     RECT  20.725 89.256 21.564 89.328 ;
     RECT  20.725 89.328 21.516 89.352 ;
     RECT  20.725 89.352 21.564 89.424 ;
     RECT  20.725 89.424 21.516 89.448 ;
     RECT  20.725 89.448 21.564 89.52 ;
     RECT  20.725 89.52 21.516 89.544 ;
     RECT  20.725 89.544 21.564 89.616 ;
     RECT  20.725 89.616 21.516 89.64 ;
     RECT  20.725 89.64 21.564 89.712 ;
     RECT  20.725 89.712 21.516 89.736 ;
    LAYER M5 ;
     RECT  2.4 2.137 2.52 2.151 ;
     RECT  5.1 2.137 5.22 2.151 ;
     RECT  7.8 2.137 7.92 2.151 ;
     RECT  10.5 2.137 10.62 2.151 ;
     RECT  13.2 2.137 13.32 2.151 ;
     RECT  15.9 2.137 16.02 2.151 ;
     RECT  18.6 2.137 18.72 2.151 ;
     RECT  18.6 2.151 18.912 33.013 ;
     RECT  18.6 33.013 19.08 33.589 ;
     RECT  18.6 33.589 19.656 36.997 ;
     RECT  18.6 36.997 20.52 37.045 ;
     RECT  2.4 2.151 2.712 39.061 ;
     RECT  2.4 39.061 2.856 39.205 ;
     RECT  2.4 39.205 3.432 39.301 ;
     RECT  5.1 2.151 5.412 39.301 ;
     RECT  2.4 39.301 5.412 39.637 ;
     RECT  6.672 39.205 6.696 39.637 ;
     RECT  2.4 39.637 6.696 40.405 ;
     RECT  2.4 40.405 6.792 40.549 ;
     RECT  7.8 2.151 8.112 40.549 ;
     RECT  0.288 39.829 0.312 40.597 ;
     RECT  0.192 40.597 0.312 40.837 ;
     RECT  2.4 40.549 8.112 40.837 ;
     RECT  2.4 40.837 8.904 40.885 ;
     RECT  10.5 2.151 10.812 40.885 ;
     RECT  0.144 40.837 0.312 41.173 ;
     RECT  0.144 41.173 0.36 41.939 ;
     RECT  2.4 40.885 10.812 42.277 ;
     RECT  13.2 2.151 13.512 42.277 ;
     RECT  14.496 39.733 14.52 42.277 ;
     RECT  13.2 42.277 14.52 42.469 ;
     RECT  0.24 41.939 0.36 42.611 ;
     RECT  18.6 37.045 21.48 42.803 ;
     RECT  13.2 42.469 14.664 42.997 ;
     RECT  15.9 2.151 16.212 42.997 ;
     RECT  13.2 42.997 16.212 43.139 ;
     RECT  18.6 42.803 21.432 43.379 ;
     RECT  13.2 43.139 14.904 43.381 ;
     RECT  18.6 43.379 19.848 43.573 ;
     RECT  15.9 43.139 16.212 44.053 ;
     RECT  21.408 43.379 21.432 44.147 ;
     RECT  2.4 42.277 11.784 44.149 ;
     RECT  12.768 43.381 14.904 44.149 ;
     RECT  0.144 43.141 0.168 44.341 ;
     RECT  2.4 44.149 14.904 44.435 ;
     RECT  17.952 43.573 19.848 44.965 ;
     RECT  17.952 44.965 19.992 45.205 ;
     RECT  2.4 44.435 14.664 45.541 ;
     RECT  2.4 45.541 14.808 45.877 ;
     RECT  15.9 44.053 16.824 45.877 ;
     RECT  0.144 44.341 0.264 46.307 ;
     RECT  2.4 45.877 16.824 46.309 ;
     RECT  17.952 45.205 20.04 46.309 ;
     RECT  0.288 46.597 0.408 46.835 ;
     RECT  2.4 46.309 20.04 47.125 ;
     RECT  0.288 46.835 0.312 47.413 ;
     RECT  0.144 47.413 0.312 47.891 ;
     RECT  0.24 47.891 0.312 47.939 ;
     RECT  0.24 47.939 0.264 48.755 ;
     RECT  21.408 49.189 21.432 49.379 ;
     RECT  21.408 50.533 21.432 50.723 ;
     RECT  0.144 51.061 0.168 51.683 ;
     RECT  0.144 53.365 0.168 53.555 ;
     RECT  21.456 55.717 21.48 55.957 ;
     RECT  0.144 55.765 0.168 56.339 ;
     RECT  0.336 57.349 0.36 57.637 ;
     RECT  0.24 57.637 0.36 57.685 ;
     RECT  21.408 55.957 21.48 57.731 ;
     RECT  0.24 57.685 0.408 57.877 ;
     RECT  21.456 57.731 21.48 57.971 ;
     RECT  0.192 57.877 0.408 58.213 ;
     RECT  0.192 58.213 0.504 58.693 ;
     RECT  0.144 58.693 0.504 58.979 ;
     RECT  0.192 58.979 0.504 59.219 ;
     RECT  0.48 59.219 0.504 59.507 ;
     RECT  21.408 59.605 21.432 60.563 ;
     RECT  21.408 61.957 21.432 62.101 ;
     RECT  21.264 62.101 21.432 62.147 ;
     RECT  21.264 62.147 21.288 62.291 ;
     RECT  2.4 47.125 20.088 63.061 ;
     RECT  2.4 63.061 20.52 63.539 ;
     RECT  0.192 62.053 0.216 63.875 ;
     RECT  2.4 63.539 20.088 64.117 ;
     RECT  2.304 64.117 20.088 65.219 ;
     RECT  21.216 65.605 21.24 65.893 ;
     RECT  21.216 65.893 21.336 66.325 ;
     RECT  21.216 66.325 21.384 66.611 ;
     RECT  21.216 66.611 21.336 66.803 ;
     RECT  21.312 66.803 21.336 66.851 ;
     RECT  0.144 66.661 0.168 67.045 ;
     RECT  0.144 67.045 0.216 67.235 ;
     RECT  21.408 67.717 21.432 67.907 ;
     RECT  0.144 67.235 0.168 69.445 ;
     RECT  0.144 69.445 0.312 70.835 ;
     RECT  21.408 71.461 21.432 72.275 ;
     RECT  0.144 70.835 0.168 73.285 ;
     RECT  0.144 73.285 0.312 73.571 ;
     RECT  0.288 73.571 0.312 74.725 ;
     RECT  0.288 74.725 0.36 74.917 ;
     RECT  0.192 74.917 0.36 75.253 ;
     RECT  0.192 75.253 0.408 75.443 ;
     RECT  0.192 75.443 0.36 75.685 ;
     RECT  0.144 75.685 0.36 76.547 ;
     RECT  0.24 76.547 0.36 76.549 ;
     RECT  0.24 76.549 0.408 76.789 ;
     RECT  0.24 76.789 0.456 77.315 ;
     RECT  0.288 77.315 0.456 77.459 ;
     RECT  2.4 65.219 20.088 78.421 ;
     RECT  0.288 77.459 0.408 78.467 ;
     RECT  0.288 78.467 0.36 78.565 ;
     RECT  0.24 78.565 0.36 79.045 ;
     RECT  0.144 79.045 0.36 79.571 ;
     RECT  0.144 79.571 0.264 80.435 ;
     RECT  0.144 80.435 0.216 80.579 ;
     RECT  0.192 80.579 0.216 81.155 ;
     RECT  0.144 81.781 0.168 81.971 ;
     RECT  2.304 78.421 20.088 82.307 ;
     RECT  0.192 82.165 0.216 82.451 ;
     RECT  2.4 82.307 20.088 83.653 ;
     RECT  2.4 83.653 20.232 84.085 ;
     RECT  2.304 84.085 20.232 84.229 ;
     RECT  0.144 83.029 0.168 84.419 ;
     RECT  2.304 84.229 20.28 85.523 ;
     RECT  2.304 85.523 8.112 85.763 ;
     RECT  21.36 84.613 21.384 85.765 ;
     RECT  9.12 85.523 20.28 87.251 ;
     RECT  21.36 85.765 21.48 87.397 ;
     RECT  0.144 87.013 0.168 88.259 ;
     RECT  10.32 87.251 20.28 88.931 ;
     RECT  9.12 87.251 9.144 88.979 ;
     RECT  10.5 88.931 11.688 89.267 ;
     RECT  0.144 89.269 0.168 89.459 ;
     RECT  13.2 88.931 20.28 89.987 ;
     RECT  2.4 85.763 8.112 90.083 ;
     RECT  15.12 89.987 20.28 90.083 ;
     RECT  2.4 90.083 6.744 90.659 ;
     RECT  17.376 90.083 20.28 90.707 ;
     RECT  2.4 90.659 5.592 90.851 ;
     RECT  3.936 90.851 5.592 90.899 ;
     RECT  21.312 87.397 21.48 91.091 ;
     RECT  6.72 90.659 6.744 91.235 ;
     RECT  15.12 90.083 16.212 91.379 ;
     RECT  4.08 90.899 5.592 91.619 ;
     RECT  4.416 91.619 5.592 91.811 ;
     RECT  4.656 91.811 5.412 91.907 ;
     RECT  2.4 90.851 2.808 91.955 ;
     RECT  18.288 90.707 20.28 92.915 ;
     RECT  21.36 91.091 21.48 92.915 ;
     RECT  18.384 92.915 20.28 93.011 ;
     RECT  21.36 92.915 21.384 93.539 ;
     RECT  18.6 93.011 20.28 95.219 ;
     RECT  18.6 95.219 20.232 96.947 ;
     RECT  18.6 96.947 19.464 97.523 ;
     RECT  2.4 91.955 2.712 127.449 ;
     RECT  5.1 91.907 5.412 127.449 ;
     RECT  7.8 90.083 8.112 127.449 ;
     RECT  10.5 89.267 10.812 127.449 ;
     RECT  13.2 89.987 13.512 127.449 ;
     RECT  15.9 91.379 16.212 127.449 ;
     RECT  18.6 97.523 18.912 127.449 ;
     RECT  2.4 127.449 2.52 127.463 ;
     RECT  5.1 127.449 5.22 127.463 ;
     RECT  7.8 127.449 7.92 127.463 ;
     RECT  10.5 127.449 10.62 127.463 ;
     RECT  13.2 127.449 13.32 127.463 ;
     RECT  15.9 127.449 16.02 127.463 ;
     RECT  18.6 127.449 18.72 127.463 ;
     RECT  5.412 39.205 6.672 39.637 ;
     RECT  6.696 39.205 7.8 40.405 ;
     RECT  13.512 39.733 14.496 42.277 ;
     RECT  14.52 39.733 15.9 42.469 ;
     RECT  6.792 40.405 7.8 40.549 ;
     RECT  0.144 41.939 0.24 42.611 ;
     RECT  11.784 42.277 13.2 43.381 ;
     RECT  14.664 42.469 15.9 42.997 ;
     RECT  0.144 42.611 0.168 43.141 ;
     RECT  14.904 43.139 15.9 44.435 ;
     RECT  11.784 43.381 12.768 44.149 ;
     RECT  16.824 44.053 17.952 46.309 ;
     RECT  14.664 44.435 15.9 45.541 ;
     RECT  14.808 45.541 15.9 45.877 ;
     RECT  0.144 46.307 0.264 46.597 ;
     RECT  0.144 46.597 0.288 47.413 ;
     RECT  20.088 49.189 21.408 49.379 ;
     RECT  20.088 49.379 21.432 50.533 ;
     RECT  20.088 50.533 21.408 50.723 ;
     RECT  20.088 55.717 21.456 55.957 ;
     RECT  20.088 55.957 21.408 57.731 ;
     RECT  20.088 57.731 21.456 57.971 ;
     RECT  20.088 59.605 21.408 60.563 ;
     RECT  20.088 60.563 21.432 61.957 ;
     RECT  20.088 61.957 21.408 62.101 ;
     RECT  20.088 62.101 21.264 62.291 ;
     RECT  20.088 62.291 20.52 63.061 ;
     RECT  20.088 65.605 21.216 66.803 ;
     RECT  21.336 66.611 21.384 66.851 ;
     RECT  20.088 66.803 21.312 66.851 ;
     RECT  20.088 66.851 21.384 67.717 ;
     RECT  20.088 67.717 21.408 67.907 ;
     RECT  20.088 71.461 21.408 72.275 ;
     RECT  0.192 73.571 0.288 74.917 ;
     RECT  0.36 75.443 0.408 76.549 ;
     RECT  0.24 77.315 0.288 78.565 ;
     RECT  0.144 80.579 0.192 81.155 ;
     RECT  0.144 81.155 0.216 81.781 ;
     RECT  0.168 81.781 0.216 81.971 ;
     RECT  0.144 81.971 0.216 82.165 ;
     RECT  0.144 82.165 0.192 82.451 ;
     RECT  0.144 82.451 0.168 83.029 ;
     RECT  20.28 84.613 21.36 87.397 ;
     RECT  8.112 85.523 9.12 88.979 ;
     RECT  9.144 87.251 10.32 88.931 ;
     RECT  20.28 87.397 21.312 91.091 ;
     RECT  0.144 88.259 0.168 89.269 ;
     RECT  9.144 88.931 10.5 88.979 ;
     RECT  11.688 88.931 13.2 89.267 ;
     RECT  6.744 90.083 7.8 91.235 ;
     RECT  16.212 90.083 17.376 90.707 ;
     RECT  5.592 90.659 6.72 91.235 ;
     RECT  2.808 90.851 3.936 90.899 ;
     RECT  2.808 90.899 4.08 91.619 ;
     RECT  20.28 91.091 21.36 93.539 ;
  END
END ot_qwen_tile_rqr_half
END LIBRARY
